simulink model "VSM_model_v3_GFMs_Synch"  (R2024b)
settings: Solver=ode23tb  StartTime=0.0  StopTime=Tend  FixedStep=T_s  RelTol=1e-3  EnableMultiTasking=on
PostLoadFcn:
  | Tcontrol=20e-6;
InitFcn:
  | Tcontrol=20e-6;
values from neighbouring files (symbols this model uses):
  C_4 = 0.1670*C_b    (= 1.00487241952e-06)    [VSM.m]    (also in VSM_CSIRO.m)
  C_6 = 0.2835*C_b    (= 1.70587623314e-06)    [VSM.m]    (also in VSM_CSIRO.m)
  C_8 = 0.2275*C_b    (= 1.36891302659e-06)    [VSM.m]    (also in VSM_CSIRO.m)
  C_dc = 0.008*(n)    (= 1.6)    [VSM.m]    (also in VSM_CSIRO.m)
  C_f = n*300*10^-6    (= 0.06)    [VSM.m]    (also in VSM_CSIRO.m)
  C_f_gfl = (n_gfl) * Cf_unit_gfl    (= 0.00350140874802)    [DER_param.m]
  D_p = (1/(m_p*w_b))    (= 101321.183642)    [VSM.m]    (also in VSM_CSIRO.m)
  droop_percentage = 5    [VSM.m]    (also in VSM_CSIRO.m = 1)
  I_b_dc = S_b/Vdc_n    [VSM.m]    (also in VSM_CSIRO.m)
  I_b_LV_peak = I_b_LV * sqrt(2)    [VSM.m]
  I_b_SG_peak = I_b_SG * sqrt(2)    [VSM.m]
  i_ll = -1.15*(S_b/Vdc_n)-i_loss_dc    [VSM.m]    (also in VSM_CSIRO.m)
  i_ul = 1.15*(S_b/Vdc_n)+i_loss_dc    [VSM.m]    (also in VSM_CSIRO.m)
  J = D_p*tau_f    (= 2026.42367285)    [VSM.m]    (also in VSM_CSIRO.m)
  k_dc = eta_1/(Vdc_n*m_p)    [VSM.m]    (also in VSM_CSIRO.m)
  K_p = (1/Vdc_n)    [VSM.m]    (also in VSM_CSIRO.m)
  K_r = 1/R_dc    [VSM.m]    (also in VSM_CSIRO.m)
  Kff_i = 1    [VSM.m]    (also in VSM_CSIRO.m)
  Kff_v = 1    [VSM.m]    (also in VSM_CSIRO.m)
  Ki_i = (1/n)*1.19    (= 0.00595)    [VSM.m]    (also in VSM_CSIRO.m)
  Ki_i_gfl = (1/n_gfl) * Ki_i_unit_gfl    (= 0.571198664289)    [DER_param.m]
  Ki_v = (n)*1.161022    (= 232.2044)    [VSM.m]    (also in VSM_CSIRO.m)
  ki_v_ac = 4*5.2500e-04    (= 0.0021)    [VSM.m]    (also in VSM_CSIRO.m)
  Kp_i = 0.738891    [VSM.m]    (also in VSM_CSIRO.m)
  Kp_i_gfl = (1/n_gfl) * Kp_i_unit_gfl    (= 0.00909090909091)    [DER_param.m]
  Kp_v = 0.52    [VSM.m]    (also in VSM_CSIRO.m)
  kp_v_ac = 0.001    [VSM.m]    (also in VSM_CSIRO.m)
  L1_f_gfl = (1/n_gfl) * L1_unit_gfl    (= 1.44686311902e-05)    [DER_param.m]
  L1_pu = 1*0.0186/m    (= 0.000186)    [VSM.m]    (also in VSM_CSIRO.m)
  L1_pu_gfl = 0.03    [DER_param.m]
  L2_f_gfl = (1/n_gfl) * L2_unit_gfl    (= 2.89372623803e-06)    [DER_param.m]
  L2_pu_gfl = 0.03    [DER_param.m]
  L_45 = L_lines(2)    [VSM.m]    (also in VSM_CSIRO.m)
  L_56 = L_lines(3)    [VSM.m]    (also in VSM_CSIRO.m)
  L_67 = L_lines(5)    [VSM.m]    (also in VSM_CSIRO.m)
  L_78 = L_lines(6)    [VSM.m]    (also in VSM_CSIRO.m)
  L_89 = L_lines(8)    [VSM.m]    (also in VSM_CSIRO.m)
  L_94 = L_lines(9)    [VSM.m]    (also in VSM_CSIRO.m)
  L_f = (1/n)*200*10^-6    (= 1e-06)    [VSM.m]    (also in VSM_CSIRO.m)
  Lg = (X_BY_R_gfl * Rg) / wn_gfl    [DER_param.m]    (also in initialcondition_gfm_Pooyan.m = X_BY_R*Rg/(wn); initialcondition_Pooyan.m = X_BY_R*Rg/(wn))
  n = 200    [VSM.m]    (also in VSM_CSIRO.m)
  Pgen_MW_gfl = 20    [DER_param.m]
  ps = base/3    (= 0.75)    [VSM.m]    (also in VSM_CSIRO.m)
  R1_f_gfl = (1/n_gfl) * R1_unit_gfl    (= 0.000909090909091)    [DER_param.m]
  R1_pu = 1*0.00734/m    (= 7.34e-05)    [VSM.m]    (also in VSM_CSIRO.m)
  R1_pu_gfl = 0.005    [DER_param.m]
  R2_f_gfl = (1/n_gfl) * R2_unit_gfl    (= 0.000181818181818)    [DER_param.m]
  R2_pu_gfl = 0.005    [DER_param.m]
  R_45 = R_lines(2)    [VSM.m]    (also in VSM_CSIRO.m)
  R_56 = R_lines(3)    [VSM.m]    (also in VSM_CSIRO.m)
  R_67 = R_lines(5)    [VSM.m]    (also in VSM_CSIRO.m)
  R_78 = R_lines(6)    [VSM.m]    (also in VSM_CSIRO.m)
  R_89 = R_lines(8)    [VSM.m]    (also in VSM_CSIRO.m)
  R_94 = R_lines(9)    [VSM.m]    (also in VSM_CSIRO.m)
  R_base_gfl = (3 * Vg_gfl^2) / (2 * Pn_gfl)    [DER_param.m]
  R_dc = (Vdc_n/(0.05*(S_b)/Vdc_n))    [VSM.m]    (also in VSM_CSIRO.m)
  R_f = 0.001/n    (= 5e-06)    [VSM.m]    (also in VSM_CSIRO.m)
  Rg = (3 * Vg_gfl^2) / (2 * SCR_gfl * sqrt(1 + X_BY_R_gfl^2) * Pn_gfl)    [DER_param.m]    (also in initialcondition_gfm_Pooyan.m = (3*Vg^2)/(2*SCR*sqrt(1+X_BY_R^2)*Pn); initialcondition_Pooyan.m = (3*Vg^2)/(2*SCR*sqrt(1+X_BY_R^2)*Pn))
  S_b = 100*(10^6)    (= 100000000)    [VSM.m]    (also in VSM_CSIRO.m)
  S_bt = S_b    (= 100000000)    [VSM.m]    (also in VSM_CSIRO.m)
  S_bt_gfl = S_b_gfl    (= 22000000)    [DER_param.m]
  T_en = T_load-0.5    (= 24.5)    [VSM.m]    (also in VSM_CSIRO.m = 44.5)
  T_s = 1e-4    (= 0.0001)    [VSM.m]    (also in VSM_CSIRO.m)
  tau_dc = 0.05    [VSM.m]    (also in VSM_CSIRO.m)
  tau_g = 5    [VSM.m]    (also in VSM_CSIRO.m)
  Tend = 90    [VSM.m]    (also in VSM_CSIRO.m = 50)
  ts_DER = 15    [DER_param.m]
  V1_rms = 1000    [VSM.m]    (also in VSM_CSIRO.m)
  V1_rms_gfl = 1000    [DER_param.m]
  V1_rms_tx1_gfl = 1000    [DER_param.m]
  V2_rms = 13800    [VSM.m]    (also in VSM_CSIRO.m)
  V2_rms_tx1_gfl = 13800    [DER_param.m]
  V_b = 230*(10^3)    (= 230000)    [VSM.m]    (also in VSM_CSIRO.m)
  V_m = sqrt(2/3)*V1_rms    [VSM.m]    (also in VSM_CSIRO.m)
  V_m_gfl = sqrt(2/3)*V1_rms_gfl    [DER_param.m]
  V_sg_p = sqrt(2/3)*V2_rms    [VSM.m]
  Vdc_n = 3*V_m    [VSM.m]    (also in VSM_CSIRO.m)
  Vdc_n_gfl = 2300    [DER_param.m]
  w_b = 2*pi*f_b    (= 314.159265359)    [VSM.m]    (also in VSM_CSIRO.m)
  w_b_gfl = 2*pi*f_b_gfl    (= 314.159265359)    [DER_param.m]
  w_f = 2*pi*5    (= 31.4159265359)    [VSM.m]    (also in VSM_CSIRO.m)
undefined symbols (not defined in the file or in its folder): D1, Delta, DiscIntNeverNeededParam, dspblkCoreblockFVToolHelper, gcbh, i_dc, magnitude
libraries: spsSeriesRLCBranchLib x82, spsabctodq0Lib x40, slpidlib x36, spsVoltageMeasurementLib x32, spsThreePhaseVIMeasurementLib x31, spsThreePhaseBreakerLib x26, spsGroundLib x22, spsCurrentMeasurementLib x20, spsPLL3phLib x14, spsThreePhaseTransformerTwoWindingsLib x14, simulink x13, spsThreePhaseSeriesRLCBranchLib x10
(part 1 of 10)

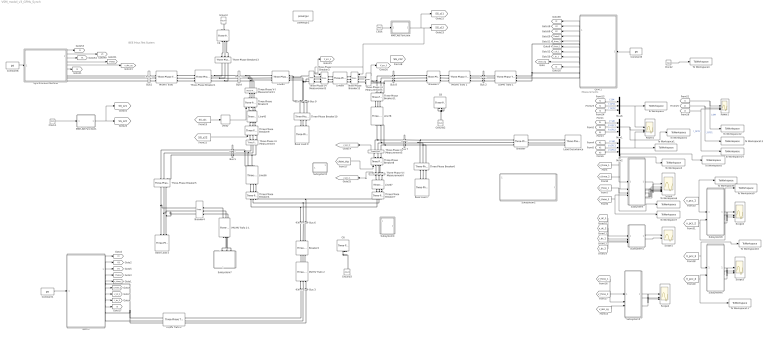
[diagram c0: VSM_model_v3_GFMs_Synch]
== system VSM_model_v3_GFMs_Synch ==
  note: Measurements
  note: IEEE 9-bus Test System
  Base Load 5 : spsThreePhaseParallelRLCLoadLib/Three-Phase Parallel RLC Load  LConnTagsString=A|B|C  Configuration=Y (grounded)  NominalVoltage=230e3  Vabc=[1e3 1e3 1e3]  Vabcp=[1e3 1e3 1e3]  NominalFrequency=50  UnbalancedPower=off  ActivePower=pl  InductivePower=0  CapacitivePower=0  Pabc=[10e3 9e3 11e3]  QLabc=[100 90 110]  QCabc=[100 90 110]  Pabcp=[10e3 9e3 11e3]  QLabcp=[100 90 110]  QCabcp=[100 90 110]  Measurements=None  LoadType=constant Z
  Base Load 7 : spsThreePhaseParallelRLCLoadLib/Three-Phase Parallel RLC Load  LConnTagsString=A|B|C  Configuration=Y (grounded)  NominalVoltage=230e3  Vabc=[1e3 1e3 1e3]  Vabcp=[1e3 1e3 1e3]  NominalFrequency=50  UnbalancedPower=off  ActivePower=pl  InductivePower=0  CapacitivePower=0  Pabc=[10e3 9e3 11e3]  QLabc=[100 90 110]  QCabc=[100 90 110]  Pabcp=[10e3 9e3 11e3]  QLabcp=[100 90 110]  QCabcp=[100 90 110]  Measurements=None  LoadType=constant Z
  "Base Load 9 " : spsThreePhaseParallelRLCLoadLib/Three-Phase Parallel RLC Load  LConnTagsString=A|B|C  Configuration=Y (grounded)  NominalVoltage=230e3  Vabc=[1e3 1e3 1e3]  Vabcp=[1e3 1e3 1e3]  NominalFrequency=50  UnbalancedPower=off  ActivePower=pl  InductivePower=0  CapacitivePower=0  Pabc=[10e3 9e3 11e3]  QLabc=[100 90 110]  QCabc=[100 90 110]  Pabcp=[10e3 9e3 11e3]  QLabcp=[100 90 110]  QCabcp=[100 90 110]  Measurements=None  LoadType=constant Z
  Breaker : spsThreePhaseBreakerLib/Three-Phase Breaker  InitialState=open  SwitchA=on  SwitchB=on  SwitchC=on  SwitchTimes=70  External=off  BreakerResistance=0.01  SnubberResistance=1e6  SnubberCapacitance=inf  Measurements=None
  Breaker2 : spsThreePhaseBreakerLib/Three-Phase Breaker  InitialState=open  SwitchA=on  SwitchB=on  SwitchC=on  SwitchTimes=10  External=off  BreakerResistance=0.01  SnubberResistance=1e6  SnubberCapacitance=inf  Measurements=None
  Breaker3 : spsThreePhaseBreakerLib/Three-Phase Breaker  InitialState=open  SwitchA=on  SwitchB=on  SwitchC=on  SwitchTimes=39  External=off  BreakerResistance=0.01  SnubberResistance=1e6  SnubberCapacitance=inf  Measurements=None
  Breaker4 : spsThreePhaseBreakerLib/Three-Phase Breaker  InitialState=open  SwitchA=on  SwitchB=on  SwitchC=on  SwitchTimes=ts_DER  External=off  BreakerResistance=0.01  SnubberResistance=1e6  SnubberCapacitance=inf  Measurements=None
  Bus 2 : spsThreePhaseVIMeasurementLib/Three-Phase V-I Measurement  VoltageMeasurement=no  SetLabelV=on  LabelV=Vabc_8  Vpu=on  VpuLL=off  CurrentMeasurement=no  SetLabelI=on  LabelI=Iabc_8  Ipu=on  Pbase=S_b  Vbase=V_b  OutputType=Complex  PhasorSimulation=off  PSBequivalent=0
  Bus 3 : spsThreePhaseVIMeasurementLib/Three-Phase V-I Measurement  VoltageMeasurement=no  SetLabelV=off  LabelV=Vabc_6  Vpu=off  VpuLL=off  CurrentMeasurement=no  SetLabelI=off  LabelI=Iabc_6  Ipu=off  Pbase=S_b  Vbase=V_b  OutputType=Complex  PhasorSimulation=off  PSBequivalent=0
  Bus 5 : spsThreePhaseVIMeasurementLib/Three-Phase V-I Measurement  VoltageMeasurement=no  SetLabelV=on  LabelV=Vabc_5  Vpu=on  VpuLL=off  CurrentMeasurement=no  SetLabelI=on  LabelI=Iabc_5  Ipu=on  Pbase=S_b  Vbase=V_b  OutputType=Complex  PhasorSimulation=off  PSBequivalent=0
  Bus 6 : spsThreePhaseVIMeasurementLib/Three-Phase V-I Measurement  VoltageMeasurement=no  SetLabelV=off  LabelV=Vabc_6  Vpu=off  VpuLL=off  CurrentMeasurement=no  SetLabelI=off  LabelI=Iabc_6  Ipu=off  Pbase=S_b  Vbase=V_b  OutputType=Complex  PhasorSimulation=off  PSBequivalent=0
  Bus 7 : spsThreePhaseVIMeasurementLib/Three-Phase V-I Measurement  VoltageMeasurement=no  SetLabelV=on  LabelV=Vabc_5  Vpu=on  VpuLL=off  CurrentMeasurement=no  SetLabelI=on  LabelI=Iabc_5  Ipu=on  Pbase=S_b  Vbase=V_b  OutputType=Complex  PhasorSimulation=off  PSBequivalent=0
  Bus 8 : spsThreePhaseVIMeasurementLib/Three-Phase V-I Measurement  VoltageMeasurement=no  SetLabelV=on  LabelV=Vabc_8  Vpu=on  VpuLL=off  CurrentMeasurement=no  SetLabelI=on  LabelI=Iabc_8  Ipu=on  Pbase=S_b  Vbase=V_b  OutputType=Complex  PhasorSimulation=off  PSBequivalent=0
  Bus 9 : spsThreePhaseVIMeasurementLib/Three-Phase V-I Measurement  VoltageMeasurement=no  SetLabelV=on  LabelV=Vabc_9  Vpu=on  VpuLL=off  CurrentMeasurement=no  SetLabelI=on  LabelI=Iabc_9  Ipu=on  Pbase=S_b  Vbase=V_b  OutputType=Complex  PhasorSimulation=off  PSBequivalent=0
  Bus1 : spsThreePhaseVIMeasurementLib/Three-Phase V-I Measurement  VoltageMeasurement=no  SetLabelV=on  LabelV=Vabc_1  Vpu=on  VpuLL=off  CurrentMeasurement=no  SetLabelI=on  LabelI=Iabc_1  Ipu=on  Pbase=S_b  Vbase=V_b  OutputType=Complex  PhasorSimulation=off  PSBequivalent=0
  Bus4 : spsThreePhaseVIMeasurementLib/Three-Phase V-I Measurement  VoltageMeasurement=no  SetLabelV=on  LabelV=Vabc_4  Vpu=on  VpuLL=off  CurrentMeasurement=no  SetLabelI=on  LabelI=Iabc_4  Ipu=on  Pbase=S_b  Vbase=V_b  OutputType=Complex  PhasorSimulation=off  PSBequivalent=0
  C4 : spsThreePhaseParallelRLCBranchLib/Three-Phase Parallel RLC Branch  LConnTagsString=A|B|C  RConnTagsString=A|B|C  BranchType=C  Resistance=1  Inductance=1e-3  Capacitance=C_4  Measurements=None
  C6 : spsThreePhaseParallelRLCBranchLib/Three-Phase Parallel RLC Branch  Commented=on  LConnTagsString=A|B|C  RConnTagsString=A|B|C  BranchType=C  Resistance=1  Inductance=1e-3  Capacitance=C_6  Measurements=None
  C8 : spsThreePhaseParallelRLCBranchLib/Three-Phase Parallel RLC Branch  Commented=on  LConnTagsString=A|B|C  RConnTagsString=A|B|C  BranchType=C  Resistance=1  Inductance=1e-3  Capacitance=C_8  Measurements=None
  Clock : Clock
  Clock1 : Clock
  Clock2 : Clock
  Constant1 : Constant  Value=ps
  Constant3 : Constant  Value=ps
  Constant8 : Constant  Value=ps
  Delay : Delay  DelayLength=1/T_s
  GFM 1 : Subsystem
  GFM 2 : Subsystem
  Ground : spsGroundLib/Ground  LConnTagsString=a
  Ground2 : spsGroundLib/Ground  Commented=on  LConnTagsString=a
  Ground3 : spsGroundLib/Ground  Commented=on  LConnTagsString=a
  LV/MV Trafo 1 : spsThreePhaseTransformerTwoWindingsLib/Three-Phase Transformer (Two Windings)  Winding1Connection=Yg  Winding2Connection=Yg  CoreType=Three single-phase transformers  SetSaturation=off  Hysteresis=off  DataFile='hysteresis'  SetInitialFlux=off  Measurements=None  UNITS=pu  NominalPower=[S_bt 50 ]  Winding1="[ V1_rms R1_pu  L1_pu]"  Winding2=[ V2_rms R1_pu L1_pu]  Rm=Rm_pu  Lm=Lm_pu  L0=0.5  Saturation="[ 0,0  ;  0.005,1.2  ;  1.0,1.4 ]"  InitialFluxes=[ 0.8 , -0.8 , 0.7 ]  BreakLoop=off  DiscreteSolver=Trapezoidal iterative  DataType=off  TransfoNumber=0
  LV/MV Trafo 2 : spsThreePhaseTransformerTwoWindingsLib/Three-Phase Transformer (Two Windings)  Winding1Connection=Yg  Winding2Connection=Yg  CoreType=Three single-phase transformers  SetSaturation=off  Hysteresis=off  DataFile='hysteresis'  SetInitialFlux=off  Measurements=None  UNITS=pu  NominalPower=[ S_bt 50 ]  Winding1="[ V1_rms R1_pu  L1_pu]"  Winding2=[ V2_rms R1_pu L1_pu]  Rm=Rm_pu  Lm=Lm_pu  L0=0.5  Saturation="[ 0,0  ;  0.005,1.2  ;  1.0,1.4 ]"  InitialFluxes=[ 0.8 , -0.8 , 0.7 ]  BreakLoop=off  DiscreteSolver=Trapezoidal iterative  DataType=off  TransfoNumber=0
  Line45 : spsThreePhaseSeriesRLCBranchLib/Three-Phase Series RLC Branch  LConnTagsString=A|B|C  RConnTagsString=A|B|C  BranchType=RL  Resistance=R_45  Inductance=L_45  Capacitance=0  Measurements=None
  Line56 : spsThreePhaseSeriesRLCBranchLib/Three-Phase Series RLC Branch  LConnTagsString=A|B|C  RConnTagsString=A|B|C  BranchType=RL  Resistance=R_56  Inductance=L_56  Capacitance=0  Measurements=None
  Line67 : spsThreePhaseSeriesRLCBranchLib/Three-Phase Series RLC Branch  LConnTagsString=A|B|C  RConnTagsString=A|B|C  BranchType=RL  Resistance=R_67  Inductance=L_67  Capacitance=0  Measurements=None
  Line78 : spsThreePhaseSeriesRLCBranchLib/Three-Phase Series RLC Branch  LConnTagsString=A|B|C  RConnTagsString=A|B|C  BranchType=RL  Resistance=R_78  Inductance=L_78  Capacitance=0  Measurements=None
  Line89 : spsThreePhaseSeriesRLCBranchLib/Three-Phase Series RLC Branch  LConnTagsString=A|B|C  RConnTagsString=A|B|C  BranchType=RL  Resistance=R_89  Inductance=L_89  Capacitance=0  Measurements=None
  Line94 : spsThreePhaseSeriesRLCBranchLib/Three-Phase Series RLC Branch  LConnTagsString=A|B|C  RConnTagsString=A|B|C  BranchType=RL  Resistance=R_94  Inductance=L_94  Capacitance=0  Measurements=None
  Load Disturbance : spsThreePhaseParallelRLCLoadLib/Three-Phase Parallel RLC Load  LConnTagsString=A|B|C  Configuration=Y (grounded)  NominalVoltage=230e3  Vabc=[1e3 1e3 1e3]  Vabcp=[1e3 1e3 1e3]  NominalFrequency=50  UnbalancedPower=off  ActivePower=load_step  InductivePower=0  CapacitivePower=0  Pabc=[10e3 9e3 11e3]  QLabc=[100 90 110]  QCabc=[100 90 110]  Pabcp=[10e3 9e3 11e3]  QLabcp=[100 90 110]  QCabcp=[100 90 110]  Measurements=None  LoadType=constant Z
  MATLAB Function : MATLAB Function  TreatAsAtomicUnit=on
  MATLAB Function1 : MATLAB Function  TreatAsAtomicUnit=on
  "MV/HV Trafo " : spsThreePhaseTransformerTwoWindingsLib/Three-Phase Transformer (Two Windings)  Winding1Connection=Delta (D1)  Winding2Connection=Yg  CoreType=Three single-phase transformers  SetSaturation=off  Hysteresis=off  DataFile='hysteresis'  SetInitialFlux=off  Measurements=None  UNITS=pu  NominalPower=[ 210e6 50 ]  Winding1="[V2_rms 0.0027  0.08]"  Winding2=[230e3 0.0027 0.08]  Rm=500  Lm=500  L0=0.5  Saturation="[ 0,0  ;  0.005,1.2  ;  1.0,1.4 ]"  InitialFluxes=[ 0.8 , -0.8 , 0.7 ]  BreakLoop=off  DiscreteSolver=Trapezoidal iterative  DataType=off  TransfoNumber=0
  "MV/HV Trafo 1 " : spsThreePhaseTransformerTwoWindingsLib/Three-Phase Transformer (Two Windings)  Winding1Connection=Yg  Winding2Connection=Yg  CoreType=Three single-phase transformers  SetSaturation=off  Hysteresis=off  DataFile='hysteresis'  SetInitialFlux=off  Measurements=None  UNITS=pu  NominalPower=[ 210e6 50 ]  Winding1=[V2_rms 0.0027 0.08]  Winding2=[ 230e3 0.0027 0.08]  Rm=500  Lm=500  L0=0.5  Saturation="[ 0,0  ;  0.005,1.2  ;  1.0,1.4 ]"  InitialFluxes=[ 0.8 , -0.8 , 0.7 ]  BreakLoop=off  DiscreteSolver=Trapezoidal iterative  DataType=off  TransfoNumber=0
  "MV/HV Trafo 2 " : spsThreePhaseTransformerTwoWindingsLib/Three-Phase Transformer (Two Windings)  Winding1Connection=Yg  Winding2Connection=Yg  CoreType=Three single-phase transformers  SetSaturation=off  Hysteresis=off  DataFile='hysteresis'  SetInitialFlux=off  Measurements=None  UNITS=pu  NominalPower=[ 210e6 50 ]  Winding1=[V2_rms 0.0027 0.08]  Winding2=[230e3 0.0027 0.08]  Rm=500  Lm=500  L0=0.5  Saturation="[ 0,0  ;  0.005,1.2  ;  1.0,1.4 ]"  InitialFluxes=[ 0.8 , -0.8 , 0.7 ]  BreakLoop=off  DiscreteSolver=Trapezoidal iterative  DataType=off  TransfoNumber=0
  MV/HV Trafo 2 1 : spsThreePhaseTransformerTwoWindingsLib/Three-Phase Transformer (Two Windings)  Winding1Connection=Yg  Winding2Connection=Yg  CoreType=Three single-phase transformers  SetSaturation=off  Hysteresis=off  DataFile='hysteresis'  SetInitialFlux=off  Measurements=None  UNITS=pu  NominalPower=[ 210e6 50 ]  Winding1=[V2_rms 0.0027 0.08]  Winding2=[230e3 0.0027 0.08]  Rm=500  Lm=500  L0=0.5  Saturation="[ 0,0  ;  0.005,1.2  ;  1.0,1.4 ]"  InitialFluxes=[ 0.8 , -0.8 , 0.7 ]  BreakLoop=off  DiscreteSolver=Trapezoidal iterative  DataType=off  TransfoNumber=0
  Mux1 : Mux  Inputs=3
  Mux2 : Mux  Inputs=3
  Mux6 : Mux  Inputs=3
  Power1 : Scope  NumInputPorts=3
  Power2 : Scope  NumInputPorts=3
  Scope : Scope  NumInputPorts=6
  Scope1 : Scope  NumInputPorts=2
  Scope2 : Scope  NumInputPorts=3
  Scope3 : Scope  NumInputPorts=3
  Scope4 : Scope  NumInputPorts=3
  Subsystem : Subsystem
  Subsystem1 : Subsystem
  Subsystem2 : Subsystem  Commented=on
  Subsystem3 : Subsystem  Commented=on
  Subsystem4 : Subsystem  Commented=on
  Subsystem5 : Subsystem  Commented=on
  Subsystem6 : Subsystem
  Subsystem7 : Subsystem
  Subsystem8 : Subsystem
  Synchronous Machine : Subsystem
  Three-Phase V-I Measurement{,1..5} (6 alike) : spsThreePhaseVIMeasurementLib/Three-Phase V-I Measurement  VoltageMeasurement=phase-to-ground  SetLabelV=off  LabelV=Vabc  Vpu=off  VpuLL=off  CurrentMeasurement=no  SetLabelI=off  LabelI=Iabc  Ipu=off  Pbase=100e6  Vbase=500e3  OutputType=Complex  PhasorSimulation=off  PSBequivalent=0
  Three-Phase Breaker1 : spsThreePhaseBreakerLib/Three-Phase Breaker  InitialState=closed  SwitchA=on  SwitchB=on  SwitchC=on  SwitchTimes=Tend+1  External=off  BreakerResistance=1  SnubberResistance=1e6  SnubberCapacitance=inf  Measurements=None
  Three-Phase Breaker10 : spsThreePhaseBreakerLib/Three-Phase Breaker  InitialState=closed  SwitchA=on  SwitchB=on  SwitchC=on  SwitchTimes=Tend+1  External=off  BreakerResistance=1  SnubberResistance=1e6  SnubberCapacitance=inf  Measurements=None
  Three-Phase Breaker11 : spsThreePhaseBreakerLib/Three-Phase Breaker  InitialState=open  SwitchA=on  SwitchB=on  SwitchC=on  SwitchTimes=41  External=off  BreakerResistance=1  SnubberResistance=1e6  SnubberCapacitance=inf  Measurements=None
  Three-Phase Breaker12 : spsThreePhaseBreakerLib/Three-Phase Breaker  InitialState=open  SwitchA=on  SwitchB=on  SwitchC=on  SwitchTimes=51  External=on  BreakerResistance=1  SnubberResistance=1e6  SnubberCapacitance=inf  Measurements=None
  Three-Phase Breaker13 : spsThreePhaseBreakerLib/Three-Phase Breaker  InitialState=closed  SwitchA=on  SwitchB=on  SwitchC=on  SwitchTimes=Tend+1  External=off  BreakerResistance=1  SnubberResistance=1e6  SnubberCapacitance=inf  Measurements=None
  Three-Phase Breaker2 : spsThreePhaseBreakerLib/Three-Phase Breaker  InitialState=open  SwitchA=on  SwitchB=on  SwitchC=on  SwitchTimes=34  External=on  BreakerResistance=1  SnubberResistance=1e6  SnubberCapacitance=inf  Measurements=None
  Three-Phase Breaker3 : spsThreePhaseBreakerLib/Three-Phase Breaker  InitialState=open  SwitchA=on  SwitchB=on  SwitchC=on  SwitchTimes=32  External=on  BreakerResistance=1  SnubberResistance=1e6  SnubberCapacitance=inf  Measurements=None
  Three-Phase Breaker4 : spsThreePhaseBreakerLib/Three-Phase Breaker  InitialState=open  SwitchA=on  SwitchB=on  SwitchC=on  SwitchTimes=12  External=off  BreakerResistance=1  SnubberResistance=1e6  SnubberCapacitance=inf  Measurements=None
  Three-Phase Breaker5 : spsThreePhaseBreakerLib/Three-Phase Breaker  InitialState=open  SwitchA=on  SwitchB=on  SwitchC=on  SwitchTimes=14  External=off  BreakerResistance=1  SnubberResistance=1e6  SnubberCapacitance=inf  Measurements=None
  Three-Phase Breaker6 : spsThreePhaseBreakerLib/Three-Phase Breaker  InitialState=open  SwitchA=on  SwitchB=on  SwitchC=on  SwitchTimes=43  External=off  BreakerResistance=1  SnubberResistance=1e6  SnubberCapacitance=inf  Measurements=None
  Three-Phase Breaker7 : spsThreePhaseBreakerLib/Three-Phase Breaker  InitialState=open  SwitchA=on  SwitchB=on  SwitchC=on  SwitchTimes=37.5  External=off  BreakerResistance=1  SnubberResistance=1e6  SnubberCapacitance=inf  Measurements=None
  Three-Phase Breaker8 : spsThreePhaseBreakerLib/Three-Phase Breaker  InitialState=open  SwitchA=on  SwitchB=on  SwitchC=on  SwitchTimes=22  External=on  BreakerResistance=1  SnubberResistance=1e6  SnubberCapacitance=inf  Measurements=None
  Three-Phase Breaker9 : spsThreePhaseBreakerLib/Three-Phase Breaker  InitialState=open  SwitchA=on  SwitchB=on  SwitchC=on  SwitchTimes=34  External=on  BreakerResistance=1  SnubberResistance=1e6  SnubberCapacitance=inf  Measurements=None
  To Workspace : ToWorkspace  VariableName=freq  SaveFormat=Structure With Time  SampleTime=-1
  To Workspace1 : ToWorkspace  VariableName=Volt  SaveFormat=Structure With Time  SampleTime=-1
  To Workspace10 : ToWorkspace  VariableName=v_pcc_33  SaveFormat=Structure With Time  SampleTime=-1
  To Workspace11 : ToWorkspace  VariableName=v_pcc_44  SaveFormat=Structure With Time  SampleTime=-1
  To Workspace12 : ToWorkspace  VariableName=I_SM_1  SaveFormat=Structure With Time  SampleTime=-1
  To Workspace13 : ToWorkspace  VariableName=I_GFC_1  SaveFormat=Structure With Time  SampleTime=-1
  To Workspace14 : ToWorkspace  VariableName=I_GFC_2  SaveFormat=Structure With Time  SampleTime=-1
  To Workspace2 : ToWorkspace  VariableName=Pwr  SaveFormat=Structure With Time  SampleTime=-1
  To Workspace3 : ToWorkspace  VariableName=v_three_11  SaveFormat=Structure With Time  SampleTime=-1
  To Workspace4 : ToWorkspace  VariableName=time_steps  SaveFormat=Structure With Time  SampleTime=-1
  To Workspace5 : ToWorkspace  VariableName=v_three_22  SaveFormat=Structure With Time  SampleTime=-1
  To Workspace6 : ToWorkspace  VariableName=i_three_11  SaveFormat=Structure With Time  SampleTime=-1
  To Workspace7 : ToWorkspace  VariableName=i_three_22  SaveFormat=Structure With Time  SampleTime=-1
  To Workspace8 : ToWorkspace  VariableName=v_pcc_11  SaveFormat=Structure With Time  SampleTime=-1
  To Workspace9 : ToWorkspace  VariableName=v_pcc_22  SaveFormat=Structure With Time  SampleTime=-1
  powergui2 : spspowerguiLib/powergui  Priority=1  SimulationMode=Discrete  SampleTime=T_s  frequency=50  Iterations=50  frequencyindice=0  Pbase=100e6  ErrMax=0.0001  UnitsV=kV  UnitsW=MW  buscounter=12  FunctionMessages=off  echomessages=off  EnableUseOfTLC=off  CurrentSourceSwitches=off  DisableSnubberDevices=off  DisableRonSwitches=off  DisableVfSwitches=off  DisplayEquations=off  AutomaticDiscreteSolvers=off  SolverType=Tustin/Backward Euler (TBE)  Interpol=off  ExternalGateDelay=off  methode=off  Ts=100  x0status=blocks  SPID=off  SwTol=0  HookPort=off  NonlinearTolerance=1e-4  nMaxIteration=100  ContinueOnMaxIteration=off  RestoreLinks=warning  ResistiveCurrentMeasurement=off  Frange=[0:2:500]  Ylog=off  Xlog=on  ShowGrid=off  save=off  variable=ZData  structure=0  ZoomFFT=off  StartTime=0.0  cycles=1  DisplayStyle=1  fundamental=60  FreqAxis=off  MaxFrequency=1000  frequencyindicesteady=1  RmsSteady=1  display=off
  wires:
  [f1] -> Mux6/1  "f_SM"
  GFM 2/2(V) -> [V3]
  GFM 2/1(f) -> [f3]
  [P3] -> Mux1/3  "P_GFC2"
  Constant1/1 -> GFM 2/1(Pset)
  [P2] -> Mux1/2  "P_GFC1"
  GFM 2/3(P) -> [P3]
  [V1] -> Mux2/1  "V_SM"
  Synchronous Machine/1(f) -> [f1]
  [f3] -> Mux6/3  "f_GFC2"
  [P1] -> Mux1/1  "P_SM"
  [V3] -> Mux2/3  "V_GFC2"
  Constant8/1 -> Synchronous Machine/1(Pset)
  Mux6/1 -> To Workspace/1, Power2/1
  [V2] -> Mux2/2  "V_GFC1"
  Mux1/1 -> To Workspace2/1, Power2/2
  Synchronous Machine/3(P) -> [P1]
  Synchronous Machine/4(Theta) -> [Theta1]
  GFM 2/4(Theta) -> [Theta3]
  Synchronous Machine/2(V) -> [V1]
  Mux2/1 -> To Workspace1/1, Power2/3
  [f2] -> Mux6/2  "f_GFC1"
  GFM 2/5(vabc) -> [v_three_2]
  GFM 2/6(iabc) -> [i_three_2]
  GFM 2/7(vdc) -> [v_dc_2]
  GFM 2/8(idc) -> [i_dc_2]
  [v_three_1] -> To Workspace3/1, Subsystem/1(In1)
  [v_three_2] -> To Workspace5/1, Subsystem/2(In2)
  [i_three_1] -> To Workspace6/1, Subsystem/3(In3)
  [i_three_2] -> To Workspace7/1, Subsystem/4(In4)
  Subsystem/1(Out1) -> Scope/1
  Subsystem/2(Out2) -> Scope/2
  Subsystem/3(Out3) -> Scope/3
  Subsystem/4(Out4) -> Scope/4
  Subsystem/5(Out5) -> Scope/5
  Subsystem/6(Out6) -> Scope/6
  [v_dc_1] -> Subsystem1/1(In1)
  [v_dc_2] -> Subsystem1/2(In2)
  [i_dc_1] -> Subsystem1/3(In3)
  [i_dc_2] -> Subsystem1/4(In4)
  Subsystem1/1(Out1) -> Scope1/1
  Subsystem1/2(Out2) -> Scope1/2
  GFM 1/8(idc1) -> [i_dc_1]
  GFM 1/6(iabc1) -> [i_three_1]
  GFM 1/7(vdc1) -> [v_dc_1]
  Constant3/1 -> GFM 1/1(Pset2)
  GFM 1/1(f1) -> [f2]
  GFM 1/4(Theta1) -> [Theta2]
  GFM 1/5(vabc1) -> [v_three_1]
  GFM 1/2(V1) -> [V2]
  GFM 1/3(P1) -> [P2]
  Synchronous Machine/5(Outport) -> [v_abc_sg]
  [v_abc_sg] -> Subsystem3/3(In2)
  Subsystem3/1(Out1) -> Scope2/1
  Subsystem3/2(Out2) -> Scope2/2
  Subsystem3/3(Out3) -> Scope2/3
  GFM 1/9(close_signal) -> [close_sig]
  GFM 2/9(I3) -> [I3]
  GFM 1/10(I2) -> [I2]
  Synchronous Machine/6(I1) -> [I1]
  [I1] -> To Workspace12/1, Power1/1  "I_SM"
  [I2] -> To Workspace13/1, Power1/2  "I_GFC1"
  [I3] -> To Workspace14/1, Power1/3  "I_GFC2"
  [SG_z21] -> Delay/1
  Clock/1 -> MATLAB Function/1(t)
  Clock1/1 -> MATLAB Function1/1(t)
  MATLAB Function1/1(y) -> [SG_z22], [SG_z21]
  MATLAB Function/1(y) -> [SG_z11], Three-Phase Breaker3/1, Three-Phase Breaker12/1, [SG_z12]
  [close_sig] -> Three-Phase Breaker8/1
  Three-Phase V-I Measurement5/1 -> [v_pcc_2]
  Three-Phase V-I Measurement4/1 -> [v_pcc_1]
  Delay/1 -> Three-Phase Breaker2/1
  [SG_z22] -> Three-Phase Breaker9/1
  [v_three_1] -> Subsystem3/1(In1)
  [v_three_2] -> Subsystem3/2(In3)
  Three-Phase V-I Measurement2/1 -> [V_pcc_4]
  Subsystem6/3(Out3) -> Scope3/3
  Subsystem6/1(Out1) -> Scope3/1
  Subsystem6/2(Out2) -> Scope3/2
  [V_pcc_3] -> To Workspace10/1, Subsystem6/1(In1)
  [V_pcc_4] -> To Workspace11/1, Subsystem6/2(In3)
  [v_pcc_2] -> To Workspace9/1, Subsystem8/2(In3)
  Subsystem8/3(Out3) -> Scope4/3
  Subsystem8/2(Out2) -> Scope4/2
  Subsystem8/1(Out1) -> Scope4/1
  [v_pcc_1] -> To Workspace8/1, Subsystem8/1(In1)
  Three-Phase V-I Measurement3/1 -> [V_pcc_3]
  Clock2/1 -> To Workspace4/1
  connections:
  GFM 1/RConn1 -- LV/MV Trafo 1/LConn1
  GFM 1/RConn2 -- LV/MV Trafo 1/LConn2
  GFM 1/RConn3 -- LV/MV Trafo 1/LConn3
  C8/RConn2 -- C8/RConn3 -- Ground2/LConn1 -- C8/RConn1
  Line94/RConn1 -- Three-Phase V-I Measurement2/LConn1 -- Bus 9/RConn3
  Bus 7/RConn3 -- Three-Phase V-I Measurement5/RConn3 -- Line78/RConn3
  Breaker2/RConn2 -- Bus 6/RConn2
  Three-Phase Breaker4/LConn1 -- Three-Phase Breaker7/LConn1 -- Bus 6/LConn1
  Three-Phase Breaker4/LConn3 -- Three-Phase Breaker7/LConn3 -- Bus 6/LConn3
  Bus 5/LConn3 -- Three-Phase V-I Measurement/LConn3 -- Line56/LConn3
  Three-Phase Breaker1/RConn2 -- Three-Phase Breaker13/RConn2 -- Bus4/RConn2
  Bus 7/LConn3 -- Three-Phase Breaker6/RConn3 -- Breaker/LConn3
  Bus 7/RConn1 -- Three-Phase V-I Measurement5/RConn1 -- Line78/RConn1
  Bus 5/LConn1 -- Three-Phase V-I Measurement/LConn1 -- Line56/LConn1
  C6/RConn2 -- C6/RConn1 -- Ground3/LConn1 -- C6/RConn3
  Bus 5/LConn2 -- Three-Phase V-I Measurement/LConn2 -- Line56/LConn2
  Breaker/LConn1 -- Three-Phase Breaker6/RConn1 -- Bus 7/LConn1
  Bus 8/RConn3 -- Three-Phase V-I Measurement3/RConn3 -- Three-Phase Breaker11/RConn3
  Bus 8/RConn1 -- Three-Phase V-I Measurement3/RConn1 -- Three-Phase Breaker11/RConn1
  Bus 7/LConn2 -- Three-Phase Breaker6/RConn2 -- Breaker/LConn2
  Line94/RConn3 -- Three-Phase V-I Measurement2/LConn3 -- Bus 9/RConn1
  C4/RConn2 -- C4/RConn1 -- C4/RConn3 -- Ground/LConn1
  Bus 8/RConn2 -- Three-Phase V-I Measurement3/RConn2 -- Three-Phase Breaker11/RConn2
  Bus4/LConn1 -- Three-Phase V-I Measurement1/RConn1 -- Line94/LConn1
  Three-Phase Breaker1/RConn1 -- Three-Phase Breaker13/RConn1 -- Bus4/RConn1
  Bus 7/RConn2 -- Three-Phase V-I Measurement5/RConn2 -- Line78/RConn2
  Bus4/LConn2 -- Three-Phase V-I Measurement1/RConn2 -- Line94/LConn2
  Bus4/LConn3 -- Three-Phase V-I Measurement1/RConn3 -- Line94/LConn3
  Three-Phase Breaker4/LConn2 -- Three-Phase Breaker7/LConn2 -- Bus 6/LConn2
  Breaker2/RConn3 -- Bus 6/RConn3
  Bus 9/RConn2 -- Three-Phase V-I Measurement2/LConn2 -- Line94/RConn2
  Breaker2/RConn1 -- Bus 6/RConn1
  Bus 3/LConn2 -- "MV/HV Trafo 2 "/LConn2
  Bus 3/LConn3 -- "MV/HV Trafo 2 "/LConn3
  Bus 3/LConn1 -- "MV/HV Trafo 2 "/LConn1
  GFM 2/RConn1 -- LV/MV Trafo 2/LConn1
  GFM 2/RConn2 -- LV/MV Trafo 2/LConn2
  GFM 2/RConn3 -- LV/MV Trafo 2/LConn3
  Breaker2/LConn1 -- "MV/HV Trafo 2 "/RConn1
  Breaker2/LConn2 -- "MV/HV Trafo 2 "/RConn2
  Breaker2/LConn3 -- "MV/HV Trafo 2 "/RConn3
  Bus 2/LConn1 -- LV/MV Trafo 1/RConn1
  Bus 2/LConn2 -- LV/MV Trafo 1/RConn2
  Bus 2/LConn3 -- LV/MV Trafo 1/RConn3
  Breaker3/RConn1 -- Bus 8/LConn1
  Breaker3/RConn2 -- Bus 8/LConn2
  Breaker3/RConn3 -- Bus 8/LConn3
  "MV/HV Trafo 1 "/LConn1 -- Bus 2/RConn1
  "MV/HV Trafo 1 "/LConn2 -- Bus 2/RConn2
  "MV/HV Trafo 1 "/LConn3 -- Bus 2/RConn3
  Breaker3/LConn1 -- "MV/HV Trafo 1 "/RConn1
  Breaker3/LConn2 -- "MV/HV Trafo 1 "/RConn2
  Breaker3/LConn3 -- "MV/HV Trafo 1 "/RConn3
  Three-Phase Breaker4/RConn1 -- Line56/RConn1
  Three-Phase Breaker4/RConn2 -- Line56/RConn2
  Three-Phase Breaker4/RConn3 -- Line56/RConn3
  Base Load 7/LConn1 -- Three-Phase Breaker6/LConn1
  Three-Phase Breaker6/LConn2 -- Base Load 7/LConn2
  Three-Phase Breaker6/LConn3 -- Base Load 7/LConn3
  Three-Phase Breaker7/RConn1 -- Line67/RConn1
  Three-Phase Breaker7/RConn2 -- Line67/RConn2
  Three-Phase Breaker7/RConn3 -- Line67/RConn3
  "Base Load 9 "/LConn1 -- Three-Phase Breaker10/LConn1
  "Base Load 9 "/LConn2 -- Three-Phase Breaker10/LConn2
  "Base Load 9 "/LConn3 -- Three-Phase Breaker10/LConn3
  Three-Phase Breaker10/RConn1 -- Bus 9/LConn3
  Three-Phase Breaker10/RConn2 -- Bus 9/LConn2
  Three-Phase Breaker10/RConn3 -- Bus 9/LConn1
  Three-Phase Breaker11/LConn1 -- Line78/LConn1
  Three-Phase Breaker11/LConn2 -- Line78/LConn2
  Three-Phase Breaker11/LConn3 -- Line78/LConn3
  Three-Phase Breaker12/RConn1 -- Line89/RConn1
  Three-Phase Breaker12/RConn2 -- Line89/RConn2
  Three-Phase Breaker12/RConn3 -- Line89/RConn3
  Three-Phase Breaker1/RConn3 -- Bus4/RConn3 -- Three-Phase Breaker13/RConn3
  "MV/HV Trafo "/LConn1 -- Bus1/LConn1
  "MV/HV Trafo "/LConn2 -- Bus1/LConn2
  "MV/HV Trafo "/LConn3 -- Bus1/LConn3
  "MV/HV Trafo "/RConn1 -- Three-Phase Breaker1/LConn1
  "MV/HV Trafo "/RConn2 -- Three-Phase Breaker1/LConn2
  "MV/HV Trafo "/RConn3 -- Three-Phase Breaker1/LConn3
  Synchronous Machine/RConn1 -- Bus1/RConn1
  Synchronous Machine/RConn2 -- Bus1/RConn2
  Synchronous Machine/RConn3 -- Bus1/RConn3
  Bus 5/RConn1 -- Three-Phase Breaker5/RConn1
  Three-Phase Breaker5/RConn2 -- Bus 5/RConn2
  Bus 5/RConn3 -- Three-Phase Breaker5/RConn3
  Base Load 5/LConn1 -- Breaker4/RConn1 -- Three-Phase Breaker5/LConn1
  Base Load 5/LConn2 -- Three-Phase Breaker5/LConn2 -- Breaker4/RConn2
  Base Load 5/LConn3 -- Breaker4/RConn3 -- Three-Phase Breaker5/LConn3
  Bus 3/RConn1 -- LV/MV Trafo 2/RConn1
  Bus 3/RConn2 -- LV/MV Trafo 2/RConn2
  Bus 3/RConn3 -- LV/MV Trafo 2/RConn3
  Three-Phase Breaker2/LConn1 -- Line45/LConn1
  Line45/LConn2 -- Three-Phase Breaker2/LConn2
  Line45/LConn3 -- Three-Phase Breaker2/LConn3
  Three-Phase Breaker9/RConn1 -- Line45/RConn1
  Three-Phase Breaker9/RConn2 -- Line45/RConn2
  Three-Phase Breaker9/RConn3 -- Line45/RConn3
  Three-Phase Breaker9/LConn2 -- Three-Phase V-I Measurement/RConn2
  Three-Phase V-I Measurement1/LConn2 -- Three-Phase Breaker2/RConn2
  Three-Phase V-I Measurement1/LConn1 -- Three-Phase Breaker2/RConn1
  Three-Phase V-I Measurement1/LConn3 -- Three-Phase Breaker2/RConn3
  Three-Phase V-I Measurement2/RConn2 -- Three-Phase Breaker3/LConn2
  Three-Phase V-I Measurement2/RConn1 -- Three-Phase Breaker3/LConn1
  Three-Phase V-I Measurement2/RConn3 -- Three-Phase Breaker3/LConn3
  Three-Phase V-I Measurement/RConn1 -- Three-Phase Breaker9/LConn1
  Three-Phase V-I Measurement/RConn3 -- Three-Phase Breaker9/LConn3
  Breaker/RConn1 -- Load Disturbance/LConn1
  Breaker/RConn2 -- Load Disturbance/LConn2
  Breaker/RConn3 -- Load Disturbance/LConn3
  MV/HV Trafo 2 1/RConn1 -- Breaker4/LConn1
  MV/HV Trafo 2 1/RConn2 -- Breaker4/LConn2
  MV/HV Trafo 2 1/RConn3 -- Breaker4/LConn3
  Subsystem7/RConn1 -- MV/HV Trafo 2 1/LConn1
  Subsystem7/RConn2 -- MV/HV Trafo 2 1/LConn2
  Subsystem7/RConn3 -- MV/HV Trafo 2 1/LConn3
  Three-Phase V-I Measurement4/LConn3 -- Line67/LConn3
  Three-Phase V-I Measurement4/RConn2 -- Three-Phase Breaker8/LConn2
  Three-Phase V-I Measurement4/RConn3 -- Three-Phase Breaker8/LConn3
  Three-Phase V-I Measurement4/RConn1 -- Three-Phase Breaker8/LConn1
  Line67/LConn2 -- Three-Phase V-I Measurement4/LConn2
  Line67/LConn1 -- Three-Phase V-I Measurement4/LConn1
  Three-Phase Breaker8/RConn1 -- Three-Phase V-I Measurement5/LConn1
  Three-Phase Breaker8/RConn2 -- Three-Phase V-I Measurement5/LConn2
  Three-Phase Breaker8/RConn3 -- Three-Phase V-I Measurement5/LConn3
  Three-Phase Breaker13/LConn1 -- C4/LConn1
  C4/LConn2 -- Three-Phase Breaker13/LConn2
  Three-Phase Breaker13/LConn3 -- C4/LConn3
  Three-Phase Breaker3/RConn1 -- Line89/LConn1
  Three-Phase Breaker3/RConn2 -- Line89/LConn2
  Three-Phase Breaker3/RConn3 -- Line89/LConn3
  Three-Phase V-I Measurement3/LConn1 -- Three-Phase Breaker12/LConn1
  Three-Phase V-I Measurement3/LConn2 -- Three-Phase Breaker12/LConn2
  Three-Phase V-I Measurement3/LConn3 -- Three-Phase Breaker12/LConn3

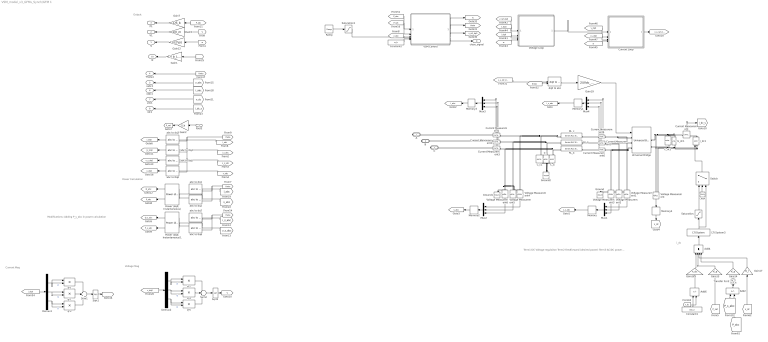
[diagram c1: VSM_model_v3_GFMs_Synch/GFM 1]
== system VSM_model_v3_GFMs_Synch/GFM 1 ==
  note: Term1-DC Voltage regulaiton Term2-feedforward (desired power) Term3-AC/DC power balance correciton Term4-Loss compensation (converter switching or filter resistor losses)
  note: Output
  note: Voltage Mag
  note: Modifications: Adding P_s_abc in power calculation
  note: Power Calculation
  note: i_dc
  note: Current Mag
  Pset2 : Inport
  Add2 : Sum  Inputs=+-
  Add4 : Sum  Inputs=++++
  Add6 : Sum  Inputs=+-
  C_a : spsSeriesRLCBranchLib/Series RLC Branch  LConnTagsString=__new0  RConnTagsString=__new0  BranchType=C  Resistance=1  Inductance=1e-3  SetiL0=off  InitialCurrent=0  Capacitance=C_f  Setx0=off  InitialVoltage=165  Measurements=None
  C_b : spsSeriesRLCBranchLib/Series RLC Branch  LConnTagsString=__new0  RConnTagsString=__new0  BranchType=C  Resistance=1  Inductance=1e-3  SetiL0=off  InitialCurrent=0  Capacitance=C_f  Setx0=off  InitialVoltage=165  Measurements=None
  C_c1 : spsSeriesRLCBranchLib/Series RLC Branch  LConnTagsString=__new0  RConnTagsString=__new0  BranchType=C  Resistance=1  Inductance=1e-3  SetiL0=off  InitialCurrent=0  Capacitance=C_f  Setx0=off  InitialVoltage=165  Measurements=None
  C_dc1 : spsSeriesRLCBranchLib/Series RLC Branch  LConnTagsString=__new0  RConnTagsString=__new0  BranchType=C  Resistance=1  Inductance=1e-3  SetiL0=off  InitialCurrent=0  Capacitance=C_dc  Setx0=off  InitialVoltage=Vdc_n  Measurements=None
  Clock : Clock
  Constant1 : Constant  Value=Vdc_n
  Constant2 : Constant  Value=w_b
  Current Loop : Subsystem
  Current Measurement{,1..6} (7 alike) : spsCurrentMeasurementLib/Current Measurement  PhasorSimulation=off  OutputType=Complex  PSBequivalent=0
  Demux1 : Demux  Outputs=3
  Demux2 : Demux  Outputs=3
  G_dc1 : spsSeriesRLCBranchLib/Series RLC Branch  LConnTagsString=__new0  RConnTagsString=__new0  BranchType=R  Resistance=R_dc  Inductance=1e-3  SetiL0=off  InitialCurrent=0  Capacitance=1e-6  Setx0=off  InitialVoltage=0  Measurements=None
  Gain1 : Gain  Gain=1/I_b_LV_peak
  Gain12 : Gain  Gain=1/(2*pi)
  Gain13 : Gain  Gain=K_p
  Gain14 : Gain  Gain=K_p
  Gain16 : Gain  Gain=k_dc
  Gain17 : Gain  Gain=K_r
  Gain19 : Gain  Gain=2/(Vdc_n)
  Gain2 : Gain  Gain=S_b
  Gain4 : Gain  Gain=1/V_m
  Gain7 : Gain  Gain=1/S_b
  Ground : spsGroundLib/Ground  LConnTagsString=a
  Ground1 : spsGroundLib/Ground  LConnTagsString=a
  Ground2 : spsGroundLib/Ground  LConnTagsString=a
  LTI System3 : cstblocks/LTI System  sys=tf(1,[tau_dc 1])  IC=[]  PadeOrder=0
  Memory{,1..4} (5 alike) : Memory
  Mux{1..4} (4 alike) : Mux  Inputs=3
  "Power (dq0, Instantaneous)" : spsPowerdq0InstantaneousLib/Power (dq0, Instantaneous)
  "Power (dq0, Instantaneous)1" : spsPowerdq0InstantaneousLib/Power (dq0, Instantaneous)
  RL_a : spsSeriesRLCBranchLib/Series RLC Branch  LConnTagsString=__new0  RConnTagsString=__new0  BranchType=RL  Resistance=R_f  Inductance=L_f  SetiL0=off  InitialCurrent=0  Capacitance=1e-6  Setx0=off  InitialVoltage=0  Measurements=Branch voltage and current
  RL_b : spsSeriesRLCBranchLib/Series RLC Branch  LConnTagsString=__new0  RConnTagsString=__new0  BranchType=RL  Resistance=R_f  Inductance=L_f  SetiL0=off  InitialCurrent=0  Capacitance=1e-6  Setx0=off  InitialVoltage=0  Measurements=None
  RL_c : spsSeriesRLCBranchLib/Series RLC Branch  LConnTagsString=__new0  RConnTagsString=__new0  BranchType=RL  Resistance=R_f  Inductance=L_f  SetiL0=off  InitialCurrent=0  Capacitance=1e-6  Setx0=off  InitialVoltage=0  Measurements=None
  Ramp : simulink/Sources/Ramp  slope=V_m  start=0  InitialOutput=0
  Saturation : Saturate  UpperLimit=i_ul  LowerLimit=i_ll
  Saturation1 : Saturate  UpperLimit=V_m  LowerLimit=0
  Sqrt1 : Sqrt
  Sqrt2 : Sqrt
  Sum1 : Sum  Inputs=+++  InputSameDT=on  SaturateOnIntegerOverflow=on
  Sum2 : Sum  Inputs=+++  InputSameDT=on  SaturateOnIntegerOverflow=on
  Switch : Switch  Criteria=u2 > Threshold  Threshold=T_en
  Transfer Fcn2 : TransferFcn  Numerator=[w_f]  Denominator=[1 w_f]
  Universal Bridge : spsUniversalBridgeLib/Universal Bridge  Arms=3  SnubberResistance=1e5  SnubberCapacitance=inf  Device=Average-model based VSC  Ron=1e-3  Lon=0  ForwardVoltages="[  0  0  ]"  ForwardVoltage=0  GTOparameters=[ 10e-6 , 20e-6 ]  IGBTparameters=[ 1e-6 , 2e-6 ]  Measurements=None  Measurements_2=None  converterType=Rectifier
  VSM Control : Subsystem
  Voltage Loop : Subsystem
  Voltage Measurement{,1..6} (7 alike) : spsVoltageMeasurementLib/Voltage Measurement  PhasorSimulation=off  OutputType=Complex  PSBequivalent=0
  abc to dq{1..8} (8 alike) : spsabctodq0Lib/abc to dq0  Alignment=90 degrees behind phase A axis
  dq0 to abc : spsdq0toabcLib/dq0 to abc  Alignment=90 degrees behind phase A axis
  d²1 : Product  InputSameDT=on  RndMeth=Zero  SaturateOnIntegerOverflow=on
  d²2 : Product  InputSameDT=on  RndMeth=Zero  SaturateOnIntegerOverflow=on
  i_dc1 : spsControlledCurrentSourceLib/Controlled Current Source  Initialize=off  Source_Type=DC  Amplitude=i_dc  Phase=0  Frequency=0  Measurements=None
  q²{1..2,4..5} (4 alike) : Product  InputSameDT=on  RndMeth=Zero  SaturateOnIntegerOverflow=on
  A : PMIOPort  Side=Right
  B : PMIOPort  Port=2  Side=Right
  C : PMIOPort  Port=3  Side=Right
  f1 : Outport  VectorParamsAs1DForOutWhenUnconnected=off
  V1 : Outport  Port=2  VectorParamsAs1DForOutWhenUnconnected=off
  P1 : Outport  Port=3  VectorParamsAs1DForOutWhenUnconnected=off
  Theta1 : Outport  Port=4  VectorParamsAs1DForOutWhenUnconnected=off
  vabc1 : Outport  Port=5  VectorParamsAs1DForOutWhenUnconnected=off
  iabc1 : Outport  Port=6  VectorParamsAs1DForOutWhenUnconnected=off
  vdc1 : Outport  Port=7  VectorParamsAs1DForOutWhenUnconnected=off
  idc1 : Outport  Port=8  VectorParamsAs1DForOutWhenUnconnected=off
  close_signal : Outport  Port=9
  I2 : Outport  Port=10  VectorParamsAs1DForOutWhenUnconnected=off
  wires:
  Memory2/1 -> [v_abc]
  Current Measurement3/1 -> Mux3/3
  Mux4/1 -> Memory1/1
  Memory3/1 -> [i_abc]
  Current Measurement/1 -> [i_dc_s]
  Current Measurement1/1 -> Mux3/1
  Voltage Measurement1/1 -> Mux1/1
  Current Measurement2/1 -> Mux3/2
  Voltage Measurement6/1 -> Mux2/3
  Memory1/1 -> [i_s_abc]
  Voltage Measurement2/1 -> Mux1/2
  Memory4/1 -> [v_dc]
  Voltage Measurement4/1 -> Mux2/1
  Mux2/1 -> Memory2/1
  Current Measurement4/1 -> Mux4/1
  Mux1/1 -> Memory/1
  Mux3/1 -> Memory3/1
  Voltage Measurement3/1 -> Mux1/3
  Current Measurement5/1 -> Mux4/2
  Current Measurement6/1 -> Mux4/3
  Voltage Measurement5/1 -> Mux2/2
  Memory/1 -> [v_s_abc]
  Voltage Measurement/1 -> Memory4/1
  [P_abc] -> Gain7/1
  [V] -> Gain4/1
  [v_dc] -> vdc1/1
  [i_abc] -> iabc1/1
  Gain7/1 -> P1/1
  [theta] -> Theta1/1
  [w] -> Gain12/1
  Gain12/1 -> f1/1
  [v_abc] -> vabc1/1
  Gain4/1 -> V1/1
  [i_dc_s] -> idc1/1
  [i_abc] -> abc to dq3/1
  abc to dq1/1 -> "Power (dq0, Instantaneous)"/2
  abc to dq7/1 -> "Power (dq0, Instantaneous)1"/2
  abc to dq4/1 -> [i_s_dq0]
  [theta] -> abc to dq7/2, abc to dq8/2
  [i_s_abc] -> abc to dq7/1
  [v_abc] -> abc to dq6/1
  [v_s_abc] -> abc to dq5/1
  [theta] -> abc to dq1/2, abc to dq2/2
  Sum2/1 -> Sqrt2/1
  q²4/1 -> Sum2/2
  [v_s_abc] -> abc to dq8/1
  [i_abc] -> abc to dq1/1
  d²2/1 -> Sum2/1
  abc to dq6/1 -> [v_dq0]
  Demux2/2 -> q²4/2, q²4/1  "q"
  "Power (dq0, Instantaneous)1"/2 -> [Q_s_abc]
  Demux2/1 -> d²2/2, d²2/1  "d"
  "Power (dq0, Instantaneous)1"/1 -> [P_s_abc]
  [theta] -> abc to dq3/2, abc to dq6/2, abc to dq5/2, abc to dq4/2
  [v_dq0] -> Demux2/1
  abc to dq2/1 -> "Power (dq0, Instantaneous)"/1
  abc to dq3/1 -> [i_dq0]
  [v_abc] -> abc to dq2/1
  Sqrt2/1 -> [V]
  [i_s_abc] -> abc to dq4/1
  "Power (dq0, Instantaneous)"/1 -> [P_abc]
  abc to dq8/1 -> "Power (dq0, Instantaneous)1"/1
  "Power (dq0, Instantaneous)"/2 -> [Q_abc]
  Demux2/3 -> q²5/2, q²5/1  "0"
  abc to dq5/1 -> [v_s_dq0]
  Gain2/1 -> [P_set]
  q²5/1 -> Sum2/3
  Pset2/1 -> Gain2/1
  [theta] -> dq0 to abc/2
  dq0 to abc/1 -> Gain19/1
  Gain19/1 -> Universal Bridge/1
  [v_s_ref_dq0] -> dq0 to abc/1
  Switch/1 -> i_dc1/1
  [P_set] -> Gain13/1
  Gain13/1 -> Add4/2
  Constant1/1 -> Add6/1
  Gain16/1 -> Add4/1
  LTI System3/1 -> Saturation/1, Switch/3
  [v_dc] -> Gain17/1
  Gain14/1 -> Add4/4
  Add6/1 -> Gain16/1
  Clock/1 -> Switch/2
  [v_dc] -> Add6/2
  Gain17/1 -> Add4/3
  [P_s_abc] -> Add2/1
  [P_abc] -> Add2/2
  Saturation/1 -> Switch/1
  Add4/1 -> LTI System3/1
  VSM Control/1(w_ref) -> [w]
  [P_abc] -> VSM Control/1(p_m)
  Current Loop/1(v_s_ref_dq0) -> [v_s_ref_dq0]
  [v_dq0] -> Voltage Loop/2(v_dq0)
  VSM Control/2(theta_ref) -> [theta]
  [w] -> Current Loop/4(w)
  [i_dq0] -> Voltage Loop/3(i_dq0)
  Voltage Loop/1(i_s_ref_dq0) -> Current Loop/1(i_s_ref_dq0)
  [i_s_dq0] -> Current Loop/3(i_s_dq0)
  [P_set] -> VSM Control/2(p_set)
  [v_ref_dq0] -> Voltage Loop/1(v_ref_dq0)
  [v_dq0] -> Current Loop/2(v_dq0)
  [w] -> Voltage Loop/4(w)
  [v_abc] -> VSM Control/4(V_abc)
  VSM Control/3(v_ref_dq0) -> [v_ref_dq0]
  Constant2/1 -> VSM Control/5(w_b)
  Ramp/1 -> Saturation1/1
  Saturation1/1 -> VSM Control/3(v_m)
  VSM Control/4(close_signal) -> close_signal/1
  q²1/1 -> Sum1/2
  Demux1/1 -> d²1/2, d²1/1  "d"
  q²2/1 -> Sum1/3
  Sum1/1 -> Sqrt1/1
  Sqrt1/1 -> [I]
  d²1/1 -> Sum1/1
  Demux1/3 -> q²2/2, q²2/1  "0"
  [i_dq0] -> Demux1/1
  Demux1/2 -> q²1/2, q²1/1  "q"
  [I] -> Gain1/1
  Gain1/1 -> I2/1
  Add2/1 -> Transfer Fcn2/1
  Transfer Fcn2/1 -> Gain14/1
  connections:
  RL_c/RConn1 -- C_c1/LConn1 -- Current Measurement1/LConn1 -- Voltage Measurement4/LConn1
  i_dc1/LConn1 -- G_dc1/RConn1 -- C_dc1/RConn1 -- Voltage Measurement/LConn2 -- Universal Bridge/RConn2
  C_b/LConn1 -- RL_b/RConn1 -- Current Measurement2/LConn1 -- Voltage Measurement5/LConn1
  Voltage Measurement1/LConn2 -- Voltage Measurement2/LConn2 -- Ground/LConn1 -- Voltage Measurement3/LConn2
  Ground1/LConn1 -- Voltage Measurement6/LConn2 -- Voltage Measurement4/LConn2 -- Voltage Measurement5/LConn2
  Ground2/LConn1 -- C_a/RConn1 -- C_b/RConn1 -- C_c1/RConn1
  Current Measurement5/LConn1 -- Universal Bridge/LConn2 -- Voltage Measurement2/LConn1
  C_a/LConn1 -- Current Measurement3/LConn1 -- Voltage Measurement6/LConn1 -- RL_a/RConn1
  Universal Bridge/RConn1 -- Voltage Measurement/LConn1 -- Current Measurement/RConn1 -- G_dc1/LConn1 -- C_dc1/LConn1
  Current Measurement4/LConn1 -- Universal Bridge/LConn1 -- Voltage Measurement1/LConn1
  Universal Bridge/LConn3 -- Current Measurement6/LConn1 -- Voltage Measurement3/LConn1
  Current Measurement2/RConn1 -- B/RConn1
  Current Measurement3/RConn1 -- C/RConn1
  i_dc1/RConn1 -- Current Measurement/LConn1
  Current Measurement6/RConn1 -- RL_a/LConn1
  Current Measurement5/RConn1 -- RL_b/LConn1
  Current Measurement4/RConn1 -- RL_c/LConn1
  Current Measurement1/RConn1 -- A/RConn1
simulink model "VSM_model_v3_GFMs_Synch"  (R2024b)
settings: Solver=ode23tb  StartTime=0.0  StopTime=Tend  FixedStep=T_s  RelTol=1e-3  EnableMultiTasking=on
PostLoadFcn:
  | Tcontrol=20e-6;
InitFcn:
  | Tcontrol=20e-6;
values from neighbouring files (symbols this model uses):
  C_4 = 0.1670*C_b    (= 1.00487241952e-06)    [VSM.m]    (also in VSM_CSIRO.m)
  C_6 = 0.2835*C_b    (= 1.70587623314e-06)    [VSM.m]    (also in VSM_CSIRO.m)
  C_8 = 0.2275*C_b    (= 1.36891302659e-06)    [VSM.m]    (also in VSM_CSIRO.m)
  C_dc = 0.008*(n)    (= 1.6)    [VSM.m]    (also in VSM_CSIRO.m)
  C_f = n*300*10^-6    (= 0.06)    [VSM.m]    (also in VSM_CSIRO.m)
  C_f_gfl = (n_gfl) * Cf_unit_gfl    (= 0.00350140874802)    [DER_param.m]
  D_p = (1/(m_p*w_b))    (= 101321.183642)    [VSM.m]    (also in VSM_CSIRO.m)
  droop_percentage = 5    [VSM.m]    (also in VSM_CSIRO.m = 1)
  I_b_dc = S_b/Vdc_n    [VSM.m]    (also in VSM_CSIRO.m)
  I_b_LV_peak = I_b_LV * sqrt(2)    [VSM.m]
  I_b_SG_peak = I_b_SG * sqrt(2)    [VSM.m]
  i_ll = -1.15*(S_b/Vdc_n)-i_loss_dc    [VSM.m]    (also in VSM_CSIRO.m)
  i_ul = 1.15*(S_b/Vdc_n)+i_loss_dc    [VSM.m]    (also in VSM_CSIRO.m)
  J = D_p*tau_f    (= 2026.42367285)    [VSM.m]    (also in VSM_CSIRO.m)
  k_dc = eta_1/(Vdc_n*m_p)    [VSM.m]    (also in VSM_CSIRO.m)
  K_p = (1/Vdc_n)    [VSM.m]    (also in VSM_CSIRO.m)
  K_r = 1/R_dc    [VSM.m]    (also in VSM_CSIRO.m)
  Kff_i = 1    [VSM.m]    (also in VSM_CSIRO.m)
  Kff_v = 1    [VSM.m]    (also in VSM_CSIRO.m)
  Ki_i = (1/n)*1.19    (= 0.00595)    [VSM.m]    (also in VSM_CSIRO.m)
  Ki_i_gfl = (1/n_gfl) * Ki_i_unit_gfl    (= 0.571198664289)    [DER_param.m]
  Ki_v = (n)*1.161022    (= 232.2044)    [VSM.m]    (also in VSM_CSIRO.m)
  ki_v_ac = 4*5.2500e-04    (= 0.0021)    [VSM.m]    (also in VSM_CSIRO.m)
  Kp_i = 0.738891    [VSM.m]    (also in VSM_CSIRO.m)
  Kp_i_gfl = (1/n_gfl) * Kp_i_unit_gfl    (= 0.00909090909091)    [DER_param.m]
  Kp_v = 0.52    [VSM.m]    (also in VSM_CSIRO.m)
  kp_v_ac = 0.001    [VSM.m]    (also in VSM_CSIRO.m)
  L1_f_gfl = (1/n_gfl) * L1_unit_gfl    (= 1.44686311902e-05)    [DER_param.m]
  L1_pu = 1*0.0186/m    (= 0.000186)    [VSM.m]    (also in VSM_CSIRO.m)
  L1_pu_gfl = 0.03    [DER_param.m]
  L2_f_gfl = (1/n_gfl) * L2_unit_gfl    (= 2.89372623803e-06)    [DER_param.m]
  L2_pu_gfl = 0.03    [DER_param.m]
  L_45 = L_lines(2)    [VSM.m]    (also in VSM_CSIRO.m)
  L_56 = L_lines(3)    [VSM.m]    (also in VSM_CSIRO.m)
  L_67 = L_lines(5)    [VSM.m]    (also in VSM_CSIRO.m)
  L_78 = L_lines(6)    [VSM.m]    (also in VSM_CSIRO.m)
  L_89 = L_lines(8)    [VSM.m]    (also in VSM_CSIRO.m)
  L_94 = L_lines(9)    [VSM.m]    (also in VSM_CSIRO.m)
  L_f = (1/n)*200*10^-6    (= 1e-06)    [VSM.m]    (also in VSM_CSIRO.m)
  Lg = (X_BY_R_gfl * Rg) / wn_gfl    [DER_param.m]    (also in initialcondition_gfm_Pooyan.m = X_BY_R*Rg/(wn); initialcondition_Pooyan.m = X_BY_R*Rg/(wn))
  n = 200    [VSM.m]    (also in VSM_CSIRO.m)
  Pgen_MW_gfl = 20    [DER_param.m]
  ps = base/3    (= 0.75)    [VSM.m]    (also in VSM_CSIRO.m)
  R1_f_gfl = (1/n_gfl) * R1_unit_gfl    (= 0.000909090909091)    [DER_param.m]
  R1_pu = 1*0.00734/m    (= 7.34e-05)    [VSM.m]    (also in VSM_CSIRO.m)
  R1_pu_gfl = 0.005    [DER_param.m]
  R2_f_gfl = (1/n_gfl) * R2_unit_gfl    (= 0.000181818181818)    [DER_param.m]
  R2_pu_gfl = 0.005    [DER_param.m]
  R_45 = R_lines(2)    [VSM.m]    (also in VSM_CSIRO.m)
  R_56 = R_lines(3)    [VSM.m]    (also in VSM_CSIRO.m)
  R_67 = R_lines(5)    [VSM.m]    (also in VSM_CSIRO.m)
  R_78 = R_lines(6)    [VSM.m]    (also in VSM_CSIRO.m)
  R_89 = R_lines(8)    [VSM.m]    (also in VSM_CSIRO.m)
  R_94 = R_lines(9)    [VSM.m]    (also in VSM_CSIRO.m)
  R_base_gfl = (3 * Vg_gfl^2) / (2 * Pn_gfl)    [DER_param.m]
  R_dc = (Vdc_n/(0.05*(S_b)/Vdc_n))    [VSM.m]    (also in VSM_CSIRO.m)
  R_f = 0.001/n    (= 5e-06)    [VSM.m]    (also in VSM_CSIRO.m)
  Rg = (3 * Vg_gfl^2) / (2 * SCR_gfl * sqrt(1 + X_BY_R_gfl^2) * Pn_gfl)    [DER_param.m]    (also in initialcondition_gfm_Pooyan.m = (3*Vg^2)/(2*SCR*sqrt(1+X_BY_R^2)*Pn); initialcondition_Pooyan.m = (3*Vg^2)/(2*SCR*sqrt(1+X_BY_R^2)*Pn))
  S_b = 100*(10^6)    (= 100000000)    [VSM.m]    (also in VSM_CSIRO.m)
  S_bt = S_b    (= 100000000)    [VSM.m]    (also in VSM_CSIRO.m)
  S_bt_gfl = S_b_gfl    (= 22000000)    [DER_param.m]
  T_en = T_load-0.5    (= 24.5)    [VSM.m]    (also in VSM_CSIRO.m = 44.5)
  T_s = 1e-4    (= 0.0001)    [VSM.m]    (also in VSM_CSIRO.m)
  tau_dc = 0.05    [VSM.m]    (also in VSM_CSIRO.m)
  tau_g = 5    [VSM.m]    (also in VSM_CSIRO.m)
  Tend = 90    [VSM.m]    (also in VSM_CSIRO.m = 50)
  ts_DER = 15    [DER_param.m]
  V1_rms = 1000    [VSM.m]    (also in VSM_CSIRO.m)
  V1_rms_gfl = 1000    [DER_param.m]
  V1_rms_tx1_gfl = 1000    [DER_param.m]
  V2_rms = 13800    [VSM.m]    (also in VSM_CSIRO.m)
  V2_rms_tx1_gfl = 13800    [DER_param.m]
  V_b = 230*(10^3)    (= 230000)    [VSM.m]    (also in VSM_CSIRO.m)
  V_m = sqrt(2/3)*V1_rms    [VSM.m]    (also in VSM_CSIRO.m)
  V_m_gfl = sqrt(2/3)*V1_rms_gfl    [DER_param.m]
  V_sg_p = sqrt(2/3)*V2_rms    [VSM.m]
  Vdc_n = 3*V_m    [VSM.m]    (also in VSM_CSIRO.m)
  Vdc_n_gfl = 2300    [DER_param.m]
  w_b = 2*pi*f_b    (= 314.159265359)    [VSM.m]    (also in VSM_CSIRO.m)
  w_b_gfl = 2*pi*f_b_gfl    (= 314.159265359)    [DER_param.m]
  w_f = 2*pi*5    (= 31.4159265359)    [VSM.m]    (also in VSM_CSIRO.m)
undefined symbols (not defined in the file or in its folder): D1, Delta, DiscIntNeverNeededParam, dspblkCoreblockFVToolHelper, gcbh, i_dc, magnitude
libraries: spsSeriesRLCBranchLib x82, spsabctodq0Lib x40, slpidlib x36, spsVoltageMeasurementLib x32, spsThreePhaseVIMeasurementLib x31, spsThreePhaseBreakerLib x26, spsGroundLib x22, spsCurrentMeasurementLib x20, spsPLL3phLib x14, spsThreePhaseTransformerTwoWindingsLib x14, simulink x13, spsThreePhaseSeriesRLCBranchLib x10
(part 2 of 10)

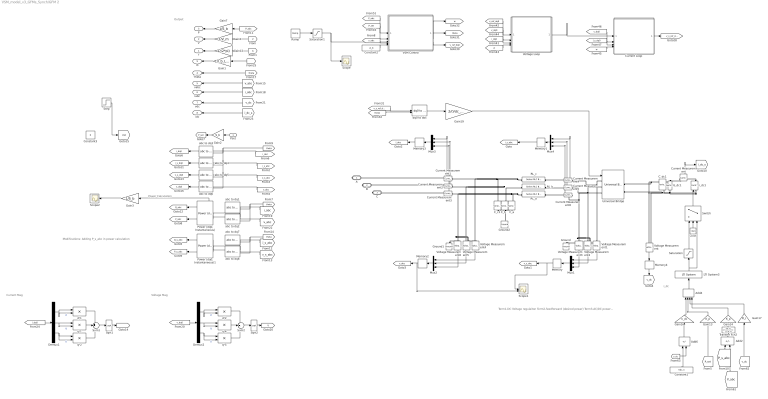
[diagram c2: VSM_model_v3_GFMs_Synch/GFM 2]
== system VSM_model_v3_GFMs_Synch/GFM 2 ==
  note: Modifications: Adding P_s_abc in power calculation
  note: Power Calculation
  note: Output
  note: Voltage Mag
  note: Term1-DC Voltage regulaiton Term2-feedforward (desired power) Term3-AC/DC power balance correciton Term4-Loss compensation (converter switching or filter resistor losses)
  note: i_dc
  note: Current Mag
  Pset : Inport
  Add2 : Sum  Inputs=+-
  Add4 : Sum  Inputs=++++
  Add6 : Sum  Inputs=+-
  C_a : spsSeriesRLCBranchLib/Series RLC Branch  LConnTagsString=__new0  RConnTagsString=__new0  BranchType=C  Resistance=1  Inductance=1e-3  SetiL0=off  InitialCurrent=0  Capacitance=C_f  Setx0=off  InitialVoltage=165  Measurements=None
  C_b : spsSeriesRLCBranchLib/Series RLC Branch  LConnTagsString=__new0  RConnTagsString=__new0  BranchType=C  Resistance=1  Inductance=1e-3  SetiL0=off  InitialCurrent=0  Capacitance=C_f  Setx0=off  InitialVoltage=165  Measurements=None
  C_c1 : spsSeriesRLCBranchLib/Series RLC Branch  LConnTagsString=__new0  RConnTagsString=__new0  BranchType=C  Resistance=1  Inductance=1e-3  SetiL0=off  InitialCurrent=0  Capacitance=C_f  Setx0=off  InitialVoltage=165  Measurements=None
  C_dc1 : spsSeriesRLCBranchLib/Series RLC Branch  LConnTagsString=__new0  RConnTagsString=__new0  BranchType=C  Resistance=1  Inductance=1e-3  SetiL0=off  InitialCurrent=0  Capacitance=C_dc  Setx0=off  InitialVoltage=Vdc_n  Measurements=None
  Clock : Clock
  Constant1 : Constant  Value=Vdc_n
  Constant2 : Constant  Value=w_b
  Constant3 : Constant  Value=0
  Current Loop : Subsystem
  Current Measurement{,1..6} (7 alike) : spsCurrentMeasurementLib/Current Measurement  PhasorSimulation=off  OutputType=Complex  PSBequivalent=0
  Demux1 : Demux  Outputs=3
  Demux2 : Demux  Outputs=3
  G_dc1 : spsSeriesRLCBranchLib/Series RLC Branch  LConnTagsString=__new0  RConnTagsString=__new0  BranchType=R  Resistance=R_dc  Inductance=1e-3  SetiL0=off  InitialCurrent=0  Capacitance=1e-6  Setx0=off  InitialVoltage=0  Measurements=None
  Gain1 : Gain  Gain=1/I_b_LV_peak
  Gain12 : Gain  Gain=1/(2*pi)
  Gain13 : Gain  Gain=K_p
  Gain14 : Gain  Gain=K_p
  Gain16 : Gain  Gain=k_dc
  Gain17 : Gain  Gain=K_r
  Gain19 : Gain  Gain=2/(Vdc_n)
  Gain2 : Gain  Gain=S_b
  Gain3 : Gain  Gain=1/S_b
  Gain4 : Gain  Gain=1/V_m
  Gain7 : Gain  Gain=1/S_b
  Ground : spsGroundLib/Ground  LConnTagsString=a
  Ground1 : spsGroundLib/Ground  LConnTagsString=a
  Ground2 : spsGroundLib/Ground  LConnTagsString=a
  LTI System3 : cstblocks/LTI System  sys=tf(1,[tau_dc 1])  IC=[]  PadeOrder=0
  Memory{,1..4} (5 alike) : Memory
  Mux{1..4} (4 alike) : Mux  Inputs=3
  "Power (dq0, Instantaneous)" : spsPowerdq0InstantaneousLib/Power (dq0, Instantaneous)
  "Power (dq0, Instantaneous)1" : spsPowerdq0InstantaneousLib/Power (dq0, Instantaneous)
  RL_a : spsSeriesRLCBranchLib/Series RLC Branch  LConnTagsString=__new0  RConnTagsString=__new0  BranchType=RL  Resistance=R_f  Inductance=L_f  SetiL0=off  InitialCurrent=0  Capacitance=1e-6  Setx0=off  InitialVoltage=0  Measurements=Branch voltage and current
  RL_b : spsSeriesRLCBranchLib/Series RLC Branch  LConnTagsString=__new0  RConnTagsString=__new0  BranchType=RL  Resistance=R_f  Inductance=L_f  SetiL0=off  InitialCurrent=0  Capacitance=1e-6  Setx0=off  InitialVoltage=0  Measurements=None
  RL_c : spsSeriesRLCBranchLib/Series RLC Branch  LConnTagsString=__new0  RConnTagsString=__new0  BranchType=RL  Resistance=R_f  Inductance=L_f  SetiL0=off  InitialCurrent=0  Capacitance=1e-6  Setx0=off  InitialVoltage=0  Measurements=None
  Ramp : simulink/Sources/Ramp  slope=V_m  start=0  InitialOutput=0
  Saturation : Saturate  UpperLimit=i_ul  LowerLimit=i_ll
  Saturation1 : Saturate  UpperLimit=V_m  LowerLimit=0
  Scope : Scope
  Scope1 : Scope  NumInputPorts=2
  Scope2 : Scope
  Sqrt1 : Sqrt
  Sqrt2 : Sqrt
  Step : Step  Time=T_s  Before=1  After=0  SampleTime=T_s
  Sum1 : Sum  Inputs=+++  InputSameDT=on  SaturateOnIntegerOverflow=on
  Sum2 : Sum  Inputs=+++  InputSameDT=on  SaturateOnIntegerOverflow=on
  Switch : Switch  Criteria=u2 > Threshold  Threshold=T_en
  Transfer Fcn2 : TransferFcn  Numerator=[w_f]  Denominator=[1 w_f]
  Universal Bridge : spsUniversalBridgeLib/Universal Bridge  Arms=3  SnubberResistance=1e5  SnubberCapacitance=inf  Device=Average-model based VSC  Ron=1e-3  Lon=0  ForwardVoltages="[  0  0  ]"  ForwardVoltage=0  GTOparameters=[ 10e-6 , 20e-6 ]  IGBTparameters=[ 1e-6 , 2e-6 ]  Measurements=None  Measurements_2=None  converterType=Rectifier
  VSM Control : Subsystem
  Voltage Loop : Subsystem
  Voltage Measurement{,1..6} (7 alike) : spsVoltageMeasurementLib/Voltage Measurement  PhasorSimulation=off  OutputType=Complex  PSBequivalent=0
  abc to dq{1..8} (8 alike) : spsabctodq0Lib/abc to dq0  Alignment=90 degrees behind phase A axis
  dq0 to abc : spsdq0toabcLib/dq0 to abc  Alignment=90 degrees behind phase A axis
  d²1 : Product  InputSameDT=on  RndMeth=Zero  SaturateOnIntegerOverflow=on
  d²2 : Product  InputSameDT=on  RndMeth=Zero  SaturateOnIntegerOverflow=on
  i_dc1 : spsControlledCurrentSourceLib/Controlled Current Source  Initialize=off  Source_Type=DC  Amplitude=i_dc  Phase=0  Frequency=0  Measurements=None
  q²{1..2,4..5} (4 alike) : Product  InputSameDT=on  RndMeth=Zero  SaturateOnIntegerOverflow=on
  A : PMIOPort  Side=Right
  B : PMIOPort  Port=2  Side=Right
  C : PMIOPort  Port=3  Side=Right
  f : Outport  VectorParamsAs1DForOutWhenUnconnected=off
  V : Outport  Port=2  VectorParamsAs1DForOutWhenUnconnected=off
  P : Outport  Port=3  VectorParamsAs1DForOutWhenUnconnected=off
  Theta : Outport  Port=4  VectorParamsAs1DForOutWhenUnconnected=off
  vabc : Outport  Port=5  VectorParamsAs1DForOutWhenUnconnected=off
  iabc : Outport  Port=6  VectorParamsAs1DForOutWhenUnconnected=off
  vdc : Outport  Port=7  VectorParamsAs1DForOutWhenUnconnected=off
  idc : Outport  Port=8  VectorParamsAs1DForOutWhenUnconnected=off
  I3 : Outport  Port=9  VectorParamsAs1DForOutWhenUnconnected=off
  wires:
  [v_dc] -> Gain17/1
  [P_s_abc] -> Add2/1
  Add6/1 -> Gain16/1
  [v_dc] -> Add6/2
  Gain17/1 -> Add4/3
  Constant1/1 -> Add6/1
  Gain16/1 -> Add4/1
  Gain13/1 -> Add4/2
  [P_set] -> Gain13/1
  Gain14/1 -> Add4/4
  [P_abc] -> Add2/2
  VSM Control/1(w_ref) -> [w]
  [P_abc] -> VSM Control/1(p_m)
  [v_abc] -> VSM Control/4(V_abc)
  [P_set] -> VSM Control/2(p_set)
  Constant2/1 -> VSM Control/5(w_b)
  VSM Control/3(v_ref_dq0) -> [v_ref_dq0]
  VSM Control/2(theta_ref) -> [theta]
  [v_s_ref_dq0] -> dq0 to abc/1
  Gain19/1 -> Universal Bridge/1
  Switch/1 -> i_dc1/1
  [v_dq0] -> Voltage Loop/2(v_dq0)
  [w] -> Voltage Loop/4(w)
  Current Loop/1(v_s_ref_dq0) -> [v_s_ref_dq0]
  [i_s_dq0] -> Current Loop/3(i_s_dq0)
  [v_dq0] -> Current Loop/2(v_dq0)
  Voltage Loop/1(i_s_ref_dq0) -> Current Loop/1(i_s_ref_dq0)
  [i_dq0] -> Voltage Loop/3(i_dq0)
  [v_ref_dq0] -> Voltage Loop/1(v_ref_dq0)
  [w] -> Current Loop/4(w)
  dq0 to abc/1 -> Gain19/1
  Memory1/1 -> [i_s_abc]
  Memory/1 -> Scope1/1, [v_s_abc]
  Memory4/1 -> [v_dc]
  Voltage Measurement/1 -> Memory4/1
  Memory3/1 -> [i_abc]
  Memory2/1 -> Scope1/2, [v_abc]
  Mux4/1 -> Memory1/1
  Sqrt2/1 -> [V]
  Demux2/1 -> d²2/2, d²2/1  "d"
  Demux2/2 -> q²4/2, q²4/1  "q"
  d²2/1 -> Sum2/1
  Demux2/3 -> q²5/2, q²5/1  "0"
  Sum2/1 -> Sqrt2/1
  q²5/1 -> Sum2/3
  [v_dq0] -> Demux2/1
  q²4/1 -> Sum2/2
  [theta] -> dq0 to abc/2
  abc to dq6/1 -> [v_dq0]
  abc to dq5/1 -> [v_s_dq0]
  abc to dq4/1 -> [i_s_dq0]
  abc to dq3/1 -> [i_dq0]
  [theta] -> abc to dq3/2, abc to dq6/2, abc to dq5/2, abc to dq4/2
  [v_s_abc] -> abc to dq5/1
  [v_abc] -> abc to dq6/1
  [i_s_abc] -> abc to dq4/1
  [i_abc] -> abc to dq3/1
  [theta] -> Theta/1
  Gain4/1 -> V/1
  [i_abc] -> abc to dq1/1
  "Power (dq0, Instantaneous)"/1 -> [P_abc]
  "Power (dq0, Instantaneous)"/2 -> Gain3/1, [Q_abc]
  [v_abc] -> abc to dq2/1
  [theta] -> abc to dq1/2, abc to dq2/2
  abc to dq2/1 -> "Power (dq0, Instantaneous)"/1
  abc to dq1/1 -> "Power (dq0, Instantaneous)"/2
  Mux1/1 -> Memory/1
  Mux3/1 -> Memory3/1
  Mux2/1 -> Memory2/1
  [w] -> Gain12/1
  Gain12/1 -> f/1
  Pset/1 -> Gain2/1
  Gain2/1 -> [P_set]
  [V] -> Gain4/1
  Voltage Measurement1/1 -> Mux1/1
  Voltage Measurement2/1 -> Mux1/2
  Voltage Measurement3/1 -> Mux1/3
  Voltage Measurement6/1 -> Mux2/3
  Voltage Measurement5/1 -> Mux2/2
  Voltage Measurement4/1 -> Mux2/1
  Current Measurement1/1 -> Mux3/1
  Current Measurement2/1 -> Mux3/2
  Current Measurement3/1 -> Mux3/3
  Current Measurement4/1 -> Mux4/1
  Current Measurement5/1 -> Mux4/2
  Current Measurement6/1 -> Mux4/3
  [P_abc] -> Gain7/1
  Gain7/1 -> P/1
  LTI System3/1 -> Saturation/1, Switch/3
  Saturation/1 -> Switch/1
  Clock/1 -> Switch/2
  Add4/1 -> LTI System3/1
  abc to dq7/1 -> "Power (dq0, Instantaneous)1"/2
  [i_s_abc] -> abc to dq7/1
  "Power (dq0, Instantaneous)1"/2 -> [Q_s_abc]
  "Power (dq0, Instantaneous)1"/1 -> [P_s_abc]
  [theta] -> abc to dq7/2, abc to dq8/2
  abc to dq8/1 -> "Power (dq0, Instantaneous)1"/1
  [v_s_abc] -> abc to dq8/1
  Current Measurement/1 -> [i_dc_s]
  [v_abc] -> vabc/1
  [i_abc] -> iabc/1
  [v_dc] -> vdc/1
  [i_dc_s] -> idc/1
  d²1/1 -> Sum1/1
  Demux1/3 -> q²2/2, q²2/1  "0"
  [i_dq0] -> Demux1/1
  Demux1/2 -> q²1/2, q²1/1  "q"
  Sqrt1/1 -> [I]
  Sum1/1 -> Sqrt1/1
  q²2/1 -> Sum1/3
  Demux1/1 -> d²1/2, d²1/1  "d"
  q²1/1 -> Sum1/2
  [I] -> Gain1/1
  Gain1/1 -> I3/1
  Ramp/1 -> Saturation1/1
  Saturation1/1 -> Scope/1, VSM Control/3(v_m)
  Gain3/1 -> Scope2/1
  Add2/1 -> Transfer Fcn2/1
  Transfer Fcn2/1 -> Gain14/1
  Step/1 -> [rst]
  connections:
  RL_c/RConn1 -- C_c1/LConn1 -- Current Measurement1/LConn1 -- Voltage Measurement4/LConn1
  C_c1/RConn1 -- Ground2/LConn1 -- C_a/RConn1 -- C_b/RConn1
  i_dc1/LConn1 -- G_dc1/RConn1 -- C_dc1/RConn1 -- Voltage Measurement/LConn2 -- Universal Bridge/RConn2
  Voltage Measurement1/LConn1 -- Current Measurement4/LConn1 -- Universal Bridge/LConn1
  Voltage Measurement2/LConn1 -- Current Measurement5/LConn1 -- Universal Bridge/LConn2
  Voltage Measurement3/LConn1 -- Universal Bridge/LConn3 -- Current Measurement6/LConn1
  Current Measurement1/RConn1 -- A/RConn1
  Current Measurement2/RConn1 -- B/RConn1
  Current Measurement3/RConn1 -- C/RConn1
  Voltage Measurement3/LConn2 -- Voltage Measurement1/LConn2 -- Voltage Measurement2/LConn2 -- Ground/LConn1
  Ground1/LConn1 -- Voltage Measurement4/LConn2 -- Voltage Measurement5/LConn2 -- Voltage Measurement6/LConn2
  G_dc1/LConn1 -- C_dc1/LConn1 -- Universal Bridge/RConn1 -- Voltage Measurement/LConn1 -- Current Measurement/RConn1
  Current Measurement5/RConn1 -- RL_b/LConn1
  Current Measurement6/RConn1 -- RL_a/LConn1
  Current Measurement4/RConn1 -- RL_c/LConn1
  RL_a/RConn1 -- C_a/LConn1 -- Current Measurement3/LConn1 -- Voltage Measurement6/LConn1
  C_b/LConn1 -- Current Measurement2/LConn1 -- Voltage Measurement5/LConn1 -- RL_b/RConn1
  i_dc1/RConn1 -- Current Measurement/LConn1

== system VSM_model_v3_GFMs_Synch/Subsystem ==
  note: voltage GFM
  note: current GFM
  In1 : Inport
  In2 : Inport  Port=2
  In3 : Inport  Port=3
  In4 : Inport  Port=4
  Demux{,1..3} (4 alike) : Demux  Outputs=3
  Mux{3..5,7..9} (6 alike) : Mux  Inputs=2
  Out1 : Outport
  Out2 : Outport  Port=2
  Out3 : Outport  Port=3
  Out4 : Outport  Port=4
  Out5 : Outport  Port=5
  Out6 : Outport  Port=6
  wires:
  Demux3/2 -> Mux8/2
  Mux8/1 -> Out5/1
  Demux/1 -> Mux3/1
  Demux/3 -> Mux5/1
  Demux3/1 -> Mux7/2
  Demux1/2 -> Mux4/2
  Mux7/1 -> Out4/1
  Demux2/1 -> Mux7/1
  Demux3/3 -> Mux9/2
  Demux2/2 -> Mux8/1
  Demux2/3 -> Mux9/1
  Demux/2 -> Mux4/1
  Demux1/3 -> Mux5/2
  Demux1/1 -> Mux3/2
  In3/1 -> Demux2/1
  Mux3/1 -> Out1/1
  Mux4/1 -> Out2/1
  In4/1 -> Demux3/1
  In2/1 -> Demux1/1
  In1/1 -> Demux/1
  Mux5/1 -> Out3/1
  Mux9/1 -> Out6/1

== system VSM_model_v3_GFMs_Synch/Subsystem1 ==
  In1 : Inport
  In2 : Inport  Port=2
  In3 : Inport  Port=3
  In4 : Inport  Port=4
  Constant : Constant  Value=I_b_dc
  Constant1 : Constant  Value=Vdc_n
  Divide{,1..3} (4 alike) : Product  Inputs=*/
  Mux : Mux  Inputs=2
  Mux3 : Mux  Inputs=2
  Out1 : Outport
  Out2 : Outport  Port=2
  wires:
  Mux3/1 -> Out2/1
  Mux/1 -> Out1/1
  Constant/1 -> Divide1/2, Divide/2
  In3/1 -> Divide/1
  Divide/1 -> Mux3/1
  In4/1 -> Divide1/1
  Divide1/1 -> Mux3/2
  Constant1/1 -> Divide2/2, Divide3/2
  In1/1 -> Divide2/1
  Divide2/1 -> Mux/1
  In2/1 -> Divide3/1
  Divide3/1 -> Mux/2

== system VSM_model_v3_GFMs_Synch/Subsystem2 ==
  note: GFL1
  Breaker1 : spsThreePhaseBreakerLib/Three-Phase Breaker  Commented=on  InitialState=open  SwitchA=on  SwitchB=on  SwitchC=on  SwitchTimes=34  External=off  BreakerResistance=0.01  SnubberResistance=1e6  SnubberCapacitance=inf  Measurements=None
  DER 1 : Subsystem  Commented=on
  GFL : Subsystem
  LV/MV Trafo 3 : spsThreePhaseTransformerTwoWindingsLib/Three-Phase Transformer (Two Windings)  Commented=on  Winding1Connection=Yg  Winding2Connection=Yg  CoreType=Three single-phase transformers  SetSaturation=off  Hysteresis=off  DataFile='hysteresis'  SetInitialFlux=off  Measurements=None  UNITS=pu  NominalPower=[S_bt 50 ]  Winding1="[ V1_rms R1_pu  L1_pu]"  Winding2=[ V2_rms R1_pu L1_pu]  Rm=Rm_pu  Lm=Lm_pu  L0=0.5  Saturation="[ 0,0  ;  0.005,1.2  ;  1.0,1.4 ]"  InitialFluxes=[ 0.8 , -0.8 , 0.7 ]  BreakLoop=off  DiscreteSolver=Trapezoidal iterative  DataType=off  TransfoNumber=0
  LV/MV Trafo 4 : spsThreePhaseTransformerTwoWindingsLib/Three-Phase Transformer (Two Windings)  Winding1Connection=Yg  Winding2Connection=Yg  CoreType=Three single-phase transformers  SetSaturation=off  Hysteresis=off  DataFile='hysteresis'  SetInitialFlux=off  Measurements=None  UNITS=pu  NominalPower=[S_bt 50 ]  Winding1="[ V1_rms R1_pu  L1_pu]"  Winding2=[ V2_rms R1_pu L1_pu]  Rm=Rm_pu  Lm=Lm_pu  L0=0.5  Saturation="[ 0,0  ;  0.005,1.2  ;  1.0,1.4 ]"  InitialFluxes=[ 0.8 , -0.8 , 0.7 ]  BreakLoop=off  DiscreteSolver=Trapezoidal iterative  DataType=off  TransfoNumber=0
  MV/HV Trafo 1 : spsThreePhaseTransformerTwoWindingsLib/Three-Phase Transformer (Two Windings)  Winding1Connection=Yg  Winding2Connection=Yg  CoreType=Three single-phase transformers  SetSaturation=off  Hysteresis=off  DataFile='hysteresis'  SetInitialFlux=off  Measurements=None  UNITS=pu  NominalPower=[ 210e6 50 ]  Winding1=[V2_rms 0.0027 0.08]  Winding2=[ 230e3 0.0027 0.08]  Rm=500  Lm=500  L0=0.5  Saturation="[ 0,0  ;  0.005,1.2  ;  1.0,1.4 ]"  InitialFluxes=[ 0.8 , -0.8 , 0.7 ]  BreakLoop=off  DiscreteSolver=Trapezoidal iterative  DataType=off  TransfoNumber=0
  MV/HV Trafo 3 : spsThreePhaseTransformerTwoWindingsLib/Three-Phase Transformer (Two Windings)  Commented=on  Winding1Connection=Yg  Winding2Connection=Yg  CoreType=Three single-phase transformers  SetSaturation=off  Hysteresis=off  DataFile='hysteresis'  SetInitialFlux=off  Measurements=None  UNITS=pu  NominalPower=[ 210e6 50 ]  Winding1=[V2_rms 0.0027 0.08]  Winding2=[ 230e3 0.0027 0.08]  Rm=500  Lm=500  L0=0.5  Saturation="[ 0,0  ;  0.005,1.2  ;  1.0,1.4 ]"  InitialFluxes=[ 0.8 , -0.8 , 0.7 ]  BreakLoop=off  DiscreteSolver=Trapezoidal iterative  DataType=off  TransfoNumber=0
  Scope3 : Scope  NumInputPorts=3
  A : PMIOPort  Side=Left
  B : PMIOPort  Port=2  Side=Left
  C : PMIOPort  Port=3  Side=Left
  A1 : PMIOPort  Port=4  Side=Left
  B1 : PMIOPort  Port=5  Side=Left
  C1 : PMIOPort  Port=6  Side=Left
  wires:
  DER 1/1(Out1) -> Scope3/1, [P4]
  GFL/2(Out2) -> [V4]
  DER 1/2(Out2) -> [V4], Scope3/2
  GFL/3(Out4) -> [f_GFL]
  DER 1/3(Out3) -> [f_GFL], Scope3/3
  GFL/1(Out1) -> [P4]
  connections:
  MV/HV Trafo 1/LConn2 -- B1/RConn1
  DER 1/LConn3 -- Breaker1/LConn3
  MV/HV Trafo 3/LConn1 -- A/RConn1
  LV/MV Trafo 4/LConn2 -- GFL/LConn2
  DER 1/LConn1 -- Breaker1/LConn1
  Breaker1/RConn3 -- LV/MV Trafo 3/RConn3
  LV/MV Trafo 4/RConn3 -- MV/HV Trafo 1/RConn3
  MV/HV Trafo 3/LConn2 -- B/RConn1
  LV/MV Trafo 4/LConn1 -- GFL/LConn1
  Breaker1/RConn1 -- LV/MV Trafo 3/RConn1
  LV/MV Trafo 4/RConn2 -- MV/HV Trafo 1/RConn2
  DER 1/LConn2 -- Breaker1/LConn2
  MV/HV Trafo 3/RConn3 -- LV/MV Trafo 3/LConn3
  LV/MV Trafo 4/RConn1 -- MV/HV Trafo 1/RConn1
  LV/MV Trafo 4/LConn3 -- GFL/LConn3
  MV/HV Trafo 3/RConn1 -- LV/MV Trafo 3/LConn1
  MV/HV Trafo 3/LConn3 -- C/RConn1
  Breaker1/RConn2 -- LV/MV Trafo 3/RConn2
  MV/HV Trafo 3/RConn2 -- LV/MV Trafo 3/LConn2
  MV/HV Trafo 1/LConn3 -- C1/RConn1
  MV/HV Trafo 1/LConn1 -- A1/RConn1

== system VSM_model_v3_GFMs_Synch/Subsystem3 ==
  In1 : Inport
  In3 : Inport  Port=2
  In2 : Inport  Port=3
  Demux : Demux  Outputs=3
  Demux1 : Demux  Outputs=3
  Demux2 : Demux  Outputs=3
  Gain : Gain  Gain=1/V_m
  Gain1 : Gain  Gain=1/V_m
  Gain2 : Gain  Gain=1/V_sg_p
  Mux3 : Mux  Inputs=3
  Mux4 : Mux  Inputs=3
  Mux5 : Mux  Inputs=3
  Out1 : Outport
  Out2 : Outport  Port=2
  Out3 : Outport  Port=3
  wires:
  Mux3/1 -> Out1/1
  Mux4/1 -> Out2/1
  In2/1 -> Gain2/1
  In1/1 -> Gain/1
  Mux5/1 -> Out3/1
  In3/1 -> Gain1/1
  Demux/1 -> Mux3/1
  Demux2/1 -> Mux3/2
  Demux1/1 -> Mux3/3
  Demux/2 -> Mux4/1
  Demux2/2 -> Mux4/2
  Demux1/2 -> Mux4/3
  Demux/3 -> Mux5/1
  Demux2/3 -> Mux5/2
  Demux1/3 -> Mux5/3
  Gain/1 -> Demux/1
  Gain1/1 -> Demux2/1
  Gain2/1 -> Demux1/1

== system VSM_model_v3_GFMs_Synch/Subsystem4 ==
  Ground5 : spsGroundLib/Ground  LConnTagsString=a
  Memory1 : Memory
  Mux4 : Mux  Inputs=3
  Voltage Measurement1 : spsVoltageMeasurementLib/Voltage Measurement  PhasorSimulation=off  OutputType=Complex  PSBequivalent=0
  Voltage Measurement2 : spsVoltageMeasurementLib/Voltage Measurement  PhasorSimulation=off  OutputType=Complex  PSBequivalent=0
  Voltage Measurement3 : spsVoltageMeasurementLib/Voltage Measurement  PhasorSimulation=off  OutputType=Complex  PSBequivalent=0
  a : PMIOPort  Side=Left
  b : PMIOPort  Port=2  Side=Left
  c : PMIOPort  Port=3  Side=Left
  Out1 : Outport
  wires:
  Memory1/1 -> Out1/1
  Mux4/1 -> Memory1/1
  Voltage Measurement3/1 -> Mux4/3
  Voltage Measurement1/1 -> Mux4/1
  Voltage Measurement2/1 -> Mux4/2
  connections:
  Voltage Measurement3/LConn2 -- Ground5/LConn1 -- Voltage Measurement2/LConn2 -- Voltage Measurement1/LConn2
  Voltage Measurement3/LConn1 -- a/RConn1
  Voltage Measurement2/LConn1 -- b/RConn1
  Voltage Measurement1/LConn1 -- c/RConn1

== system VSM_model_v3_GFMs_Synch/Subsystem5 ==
  Ground5 : spsGroundLib/Ground  LConnTagsString=a
  Memory1 : Memory
  Mux4 : Mux  Inputs=3
  Voltage Measurement1 : spsVoltageMeasurementLib/Voltage Measurement  PhasorSimulation=off  OutputType=Complex  PSBequivalent=0
  Voltage Measurement2 : spsVoltageMeasurementLib/Voltage Measurement  PhasorSimulation=off  OutputType=Complex  PSBequivalent=0
  Voltage Measurement3 : spsVoltageMeasurementLib/Voltage Measurement  PhasorSimulation=off  OutputType=Complex  PSBequivalent=0
  a : PMIOPort  Side=Left
  b : PMIOPort  Port=2  Side=Left
  c : PMIOPort  Port=3  Side=Left
  Out1 : Outport
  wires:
  Memory1/1 -> Out1/1
  Mux4/1 -> Memory1/1
  Voltage Measurement3/1 -> Mux4/3
  Voltage Measurement1/1 -> Mux4/1
  Voltage Measurement2/1 -> Mux4/2
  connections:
  Voltage Measurement3/LConn2 -- Ground5/LConn1 -- Voltage Measurement2/LConn2 -- Voltage Measurement1/LConn2
  Voltage Measurement3/LConn1 -- a/RConn1
  Voltage Measurement2/LConn1 -- b/RConn1
  Voltage Measurement1/LConn1 -- c/RConn1

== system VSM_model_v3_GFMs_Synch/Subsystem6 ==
  In1 : Inport
  In3 : Inport  Port=2
  Demux : Demux  Outputs=3
  Demux2 : Demux  Outputs=3
  Gain : Gain  Gain=1/V_b
  Gain1 : Gain  Gain=1/V_b
  Mux1 : Mux  Inputs=2
  Mux3 : Mux  Inputs=2
  Mux4 : Mux  Inputs=2
  Out1 : Outport
  Out2 : Outport  Port=2
  Out3 : Outport  Port=3
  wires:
  Gain/1 -> Demux/1
  In1/1 -> Gain/1
  In3/1 -> Gain1/1
  Gain1/1 -> Demux2/1
  Mux1/1 -> Out1/1
  Mux3/1 -> Out2/1
  Mux4/1 -> Out3/1
  Demux/1 -> Mux1/1
  Demux2/1 -> Mux1/2
  Demux/2 -> Mux3/1
  Demux2/2 -> Mux3/2
  Demux/3 -> Mux4/1
  Demux2/3 -> Mux4/2

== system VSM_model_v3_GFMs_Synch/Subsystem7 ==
  Breaker1 : spsThreePhaseBreakerLib/Three-Phase Breaker  InitialState=open  SwitchA=on  SwitchB=on  SwitchC=on  SwitchTimes=ts_DER+2  External=off  BreakerResistance=0.01  SnubberResistance=1e6  SnubberCapacitance=inf  Measurements=None
  Breaker2 : spsThreePhaseBreakerLib/Three-Phase Breaker  InitialState=open  SwitchA=on  SwitchB=on  SwitchC=on  SwitchTimes=ts_DER+7  External=off  BreakerResistance=0.01  SnubberResistance=1e6  SnubberCapacitance=inf  Measurements=None
  Breaker3 : spsThreePhaseBreakerLib/Three-Phase Breaker  InitialState=open  SwitchA=on  SwitchB=on  SwitchC=on  SwitchTimes=ts_DER+16  External=off  BreakerResistance=0.01  SnubberResistance=1e6  SnubberCapacitance=inf  Measurements=None
  Breaker4 : spsThreePhaseBreakerLib/Three-Phase Breaker  Commented=on  InitialState=open  SwitchA=on  SwitchB=on  SwitchC=on  SwitchTimes=ts_DER+2  External=off  BreakerResistance=0.01  SnubberResistance=1e6  SnubberCapacitance=inf  Measurements=None
  Constant : Constant  Value=Pgen_MW_gfl
  Constant1 : Constant  Value=Pgen_MW_gfl
  Constant2 : Constant  Value=Pgen_MW_gfl
  Constant3 : Constant  Commented=on  Value=Pgen_MW_gfl
  LV/MV Trafo 1 : spsThreePhaseTransformerTwoWindingsLib/Three-Phase Transformer (Two Windings)  Winding1Connection=Yg  Winding2Connection=Yg  CoreType=Three single-phase transformers  SetSaturation=off  Hysteresis=off  DataFile='hysteresis'  SetInitialFlux=off  Measurements=None  UNITS=pu  NominalPower=[ S_bt_gfl 50 ]  Winding1="[ V1_rms_tx1_gfl R1_pu_gfl  L1_pu_gfl]"  Winding2=[V2_rms_tx1_gfl R2_pu_gfl L2_pu_gfl]  Rm=Rm_pu_gfl  Lm=Lm_pu_gfl  L0=0.5  Saturation="[ 0,0  ;  0.005,1.2  ;  1.0,1.4 ]"  InitialFluxes=[ 0.8 , -0.8 , 0.7 ]  BreakLoop=off  DiscreteSolver=Trapezoidal iterative  DataType=off  TransfoNumber=0
  LV/MV Trafo 2 : spsThreePhaseTransformerTwoWindingsLib/Three-Phase Transformer (Two Windings)  Winding1Connection=Yg  Winding2Connection=Yg  CoreType=Three single-phase transformers  SetSaturation=off  Hysteresis=off  DataFile='hysteresis'  SetInitialFlux=off  Measurements=None  UNITS=pu  NominalPower=[ S_bt_gfl 50 ]  Winding1="[ V1_rms_tx1_gfl R1_pu_gfl  L1_pu_gfl]"  Winding2=[V2_rms_tx1_gfl R2_pu_gfl L2_pu_gfl]  Rm=Rm_pu_gfl  Lm=Lm_pu_gfl  L0=0.5  Saturation="[ 0,0  ;  0.005,1.2  ;  1.0,1.4 ]"  InitialFluxes=[ 0.8 , -0.8 , 0.7 ]  BreakLoop=off  DiscreteSolver=Trapezoidal iterative  DataType=off  TransfoNumber=0
  LV/MV Trafo 3 : spsThreePhaseTransformerTwoWindingsLib/Three-Phase Transformer (Two Windings)  Winding1Connection=Yg  Winding2Connection=Yg  CoreType=Three single-phase transformers  SetSaturation=off  Hysteresis=off  DataFile='hysteresis'  SetInitialFlux=off  Measurements=None  UNITS=pu  NominalPower=[ S_bt_gfl 50 ]  Winding1="[ V1_rms_tx1_gfl R1_pu_gfl  L1_pu_gfl]"  Winding2=[V2_rms_tx1_gfl R2_pu_gfl L2_pu_gfl]  Rm=Rm_pu_gfl  Lm=Lm_pu_gfl  L0=0.5  Saturation="[ 0,0  ;  0.005,1.2  ;  1.0,1.4 ]"  InitialFluxes=[ 0.8 , -0.8 , 0.7 ]  BreakLoop=off  DiscreteSolver=Trapezoidal iterative  DataType=off  TransfoNumber=0
  LV/MV Trafo 4 : spsThreePhaseTransformerTwoWindingsLib/Three-Phase Transformer (Two Windings)  Commented=on  Winding1Connection=Yg  Winding2Connection=Yg  CoreType=Three single-phase transformers  SetSaturation=off  Hysteresis=off  DataFile='hysteresis'  SetInitialFlux=off  Measurements=None  UNITS=pu  NominalPower=[ S_bt_gfl 50 ]  Winding1="[ V1_rms_tx1_gfl R1_pu_gfl  L1_pu_gfl]"  Winding2=[V2_rms_tx1_gfl R2_pu_gfl L2_pu_gfl]  Rm=Rm_pu_gfl  Lm=Lm_pu_gfl  L0=0.5  Saturation="[ 0,0  ;  0.005,1.2  ;  1.0,1.4 ]"  InitialFluxes=[ 0.8 , -0.8 , 0.7 ]  BreakLoop=off  DiscreteSolver=Trapezoidal iterative  DataType=off  TransfoNumber=0
  Step : Step  Time=ts_DER+3  SampleTime=0
  Step1 : Step  Time=ts_DER+8  SampleTime=0
  Step2 : Step  Time=ts_DER+17  SampleTime=0
  Step3 : Step  Commented=on  Time=ts_DER+3  SampleTime=0
  Subsystem1 : Subsystem
  Subsystem2 : Subsystem
  Subsystem3 : Subsystem  Commented=on
  Subsystem8 : Subsystem
  Connection Port : PMIOPort  Side=Right
  Connection Port1 : PMIOPort  Port=2  Side=Right
  Connection Port2 : PMIOPort  Port=3  Side=Right
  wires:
  Constant/1 -> Subsystem8/1(Inport)
  Step/1 -> Subsystem8/2(Enable)
  Step1/1 -> Subsystem1/2(Enable)
  Constant1/1 -> Subsystem1/1(Inport)
  Constant2/1 -> Subsystem2/1(Inport)
  Step2/1 -> Subsystem2/2(Enable)
  Constant3/1 -> Subsystem3/1(Inport)
  Step3/1 -> Subsystem3/2(Enable)
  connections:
  Subsystem8/RConn2 -- LV/MV Trafo 3/LConn2
  Subsystem8/RConn1 -- LV/MV Trafo 3/LConn1
  Subsystem8/RConn3 -- LV/MV Trafo 3/LConn3
  LV/MV Trafo 3/RConn1 -- Breaker1/LConn1
  LV/MV Trafo 3/RConn2 -- Breaker1/LConn2
  LV/MV Trafo 3/RConn3 -- Breaker1/LConn3
  Connection Port/RConn1 -- Breaker3/RConn1 -- Breaker2/RConn1 -- Breaker1/RConn1
  Connection Port1/RConn1 -- Breaker3/RConn2 -- Breaker2/RConn2 -- Breaker1/RConn2
  Connection Port2/RConn1 -- Breaker3/RConn3 -- Breaker2/RConn3 -- Breaker1/RConn3
  LV/MV Trafo 1/RConn2 -- Breaker2/LConn2
  Subsystem1/RConn2 -- LV/MV Trafo 1/LConn2
  Subsystem1/RConn3 -- LV/MV Trafo 1/LConn3
  Subsystem1/RConn1 -- LV/MV Trafo 1/LConn1
  LV/MV Trafo 1/RConn1 -- Breaker2/LConn1
  LV/MV Trafo 1/RConn3 -- Breaker2/LConn3
  LV/MV Trafo 2/RConn3 -- Breaker3/LConn3
  Subsystem2/RConn2 -- LV/MV Trafo 2/LConn2
  Subsystem2/RConn1 -- LV/MV Trafo 2/LConn1
  LV/MV Trafo 2/RConn1 -- Breaker3/LConn1
  LV/MV Trafo 2/RConn2 -- Breaker3/LConn2
  Subsystem2/RConn3 -- LV/MV Trafo 2/LConn3
  LV/MV Trafo 4/RConn3 -- Breaker4/LConn3
  Subsystem3/RConn2 -- LV/MV Trafo 4/LConn2
  Subsystem3/RConn1 -- LV/MV Trafo 4/LConn1
  LV/MV Trafo 4/RConn1 -- Breaker4/LConn1
  LV/MV Trafo 4/RConn2 -- Breaker4/LConn2
  Subsystem3/RConn3 -- LV/MV Trafo 4/LConn3

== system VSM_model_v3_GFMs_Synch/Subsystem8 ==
  In1 : Inport
  In3 : Inport  Port=2
  Demux : Demux  Outputs=3
  Demux2 : Demux  Outputs=3
  Gain : Gain  Gain=1/V_b
  Gain1 : Gain  Gain=1/V_b
  Mux1 : Mux  Inputs=2
  Mux3 : Mux  Inputs=2
  Mux4 : Mux  Inputs=2
  Out1 : Outport
  Out2 : Outport  Port=2
  Out3 : Outport  Port=3
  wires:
  Gain/1 -> Demux/1
  In1/1 -> Gain/1
  In3/1 -> Gain1/1
  Gain1/1 -> Demux2/1
  Mux1/1 -> Out1/1
  Mux3/1 -> Out2/1
  Mux4/1 -> Out3/1
  Demux/1 -> Mux1/1
  Demux2/1 -> Mux1/2
  Demux/2 -> Mux3/1
  Demux2/2 -> Mux3/2
  Demux/3 -> Mux4/1
  Demux2/3 -> Mux4/2

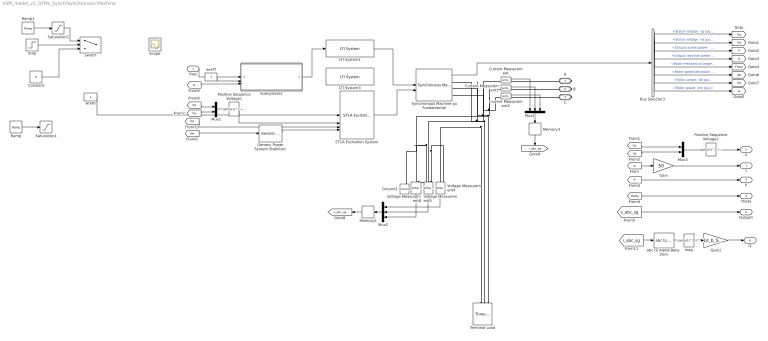
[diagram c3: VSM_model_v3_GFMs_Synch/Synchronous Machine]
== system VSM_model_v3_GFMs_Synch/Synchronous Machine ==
  Pset : Inport
  Bus Selector3 : BusSelector  OutputSignals="dq0 components.Stator voltage  vq (pu),dq0 components.Stator voltage  vd (pu),Output active power   Peo (pu),Output reactive power  Qeo (pu),Mechanical.Rotor mechanical angle  theta (deg),Mechanical.Rotor speed deviation  dw (pu),dq0 components.Field current  ifd (pu),Mechanical.Rotor speed  wm (pu)"
  Constant : Constant  Commented=on  Value=0
  Current Measurement : spsCurrentMeasurementLib/Current Measurement  PhasorSimulation=off  OutputType=Complex  PSBequivalent=0
  Current Measurement1 : spsCurrentMeasurementLib/Current Measurement  PhasorSimulation=off  OutputType=Complex  PSBequivalent=0
  Current Measurement2 : spsCurrentMeasurementLib/Current Measurement  PhasorSimulation=off  OutputType=Complex  PSBequivalent=0
  Gain : Gain  Gain=50
  Gain1 : Gain  Gain=1/I_b_SG_peak
  Generic Power System Stabilizer : spsGenericPowerSystemStabilizerLib/Generic Power System Stabilizer  Tsensor=30e-4  K=2.5  Twashout=2  Tleadlag1=[2*50e-3 0.01*20e-3]  Tleadlag2=[2*3 0.1*5.4]  VSlimits=2*[-0.15 0.15]  Vinit=0  Plot_On=off  MagdB_On=on  FreqRange=logspace(-2,2,500)
  Ground1 : spsGroundLib/Ground  LConnTagsString=a
  LTI System1 : cstblocks/LTI System  sys=ss(-1/tau_g,1/tau_g,1,[])  IC=ps  PadeOrder=0
  LTI System3 : cstblocks/LTI System  Commented=on  sys=tf(1,[tau_g 1])  IC=[]  PadeOrder=0
  Memory2 : Memory
  Memory3 : Memory
  Mux1 : Mux  Inputs=2
  Mux2 : Mux  Inputs=3
  Mux3 : Mux  Inputs=2
  Mux4 : Mux  Inputs=3
  Positive Sequence Voltage1 : Fcn  Expr=sqrt(u(1)^2 + u(2)^2)
  Positive Sequence Voltage2 : Fcn  Expr=sqrt(u(1)^2 + u(2)^2)
  Ramp : simulink/Sources/Ramp  Commented=on  slope=1/3  start=0  InitialOutput=0
  Ramp1 : simulink/Sources/Ramp  Commented=on  slope=ps/10  start=0  InitialOutput=0
  ST1A Excitation System : spsST1AExcitationSystemLib/ST1A Excitation System  Tr=20e-4  KaTa=[210 0.001]  VIminmax=[-999 +999]  VAminmax=[-999 999]  VRminmax=[-6.0 6.43]  KfTf=[0.001 1]  TbTc=[0 0 0 0]  KLR=1  ILR=2  Kc=0.038  v0=[1 1]  TsBlock=0
  Saturation1 : Saturate  Commented=on  UpperLimit=1  LowerLimit=0
  Saturation2 : Saturate  Commented=on  UpperLimit=ps  LowerLimit=0
  Scope : Scope
  Step : Step  Commented=on  Time=3  SampleTime=0
  Subsystem2 : Subsystem
  Switch : Switch  Commented=on  Criteria=u2 > Threshold
  Synchronous Machine pu Fundamental : spsSynchronousMachinepuFundamentalLib/Synchronous Machine pu Fundamental  PresetModel=No  MechanicalLoad=Mechanical power Pm  ShowDetailedParameters=on  RotorType=Salient-pole  Units=per unit fundamental parameters  MeasurementBus=off  NominalParameters="[100E6  V2_rms   50]"  Stator="[ 2.85E-03  0.114  1.19  0.36 ]"  Field="[ 5.79E-04  0.114]"  Dampers2=[0.0652, 0.5134, 0.0287, 0.2553, 7.765e-3, 0.9167 ]  Dampers1="[ 1.17E-02  0.182  1.97E-02  0.384 ]"  Mechanical=[ 3.7 0 20]  PolePairs=20  InitialConditions=[0 0 0 0 0 0 0 0 1]  SetSaturation=off  Saturation=[0.6404,0.7127,0.8441,0.9214,0.9956,1.082,1.19,1.316,1.457;0.7,0.7698,0.8872,0.9466,0.9969,1.046,1.1,1.151,1.201]  LoadFlowParameters=[1 0 0 0 0]  TsPowergui=0  TsBlock=-1  IterativeModel=Trapezoidal non iterative  IterativeDiscreteModel=Trapezoidal non iterative  BusType=PV  Pref=0  Qref=0  Qmin=-inf  Qmax=inf  PLF=0  QLF=0
  Terminal Load : spsThreePhaseParallelRLCLoadLib/Three-Phase Parallel RLC Load  LConnTagsString=A|B|C  Configuration=Y (grounded)  NominalVoltage=V2_rms  Vabc=[1e3 1e3 1e3]  Vabcp=[1e3 1e3 1e3]  NominalFrequency=50  UnbalancedPower=off  ActivePower=1  InductivePower=0  CapacitivePower=0  Pabc=[10e3 9e3 11e3]  QLabc=[100 90 110]  QCabc=[100 90 110]  Pabcp=[10e3 9e3 11e3]  QLabcp=[100 90 110]  QCabcp=[100 90 110]  Measurements=None  LoadType=constant Z
  Voltage Measurement4 : spsVoltageMeasurementLib/Voltage Measurement  PhasorSimulation=off  OutputType=Complex  PSBequivalent=0
  Voltage Measurement5 : spsVoltageMeasurementLib/Voltage Measurement  PhasorSimulation=off  OutputType=Complex  PSBequivalent=0
  Voltage Measurement6 : spsVoltageMeasurementLib/Voltage Measurement  PhasorSimulation=off  OutputType=Complex  PSBequivalent=0
  abc to Alpha-Beta-Zero : spsabctoAlphaBetaZeroLib/abc to Alpha-Beta-Zero
  mag : Fcn  Expr=sqrt(u(1)^2 + u(2)^2)
  wref6 : Constant
  wref7 : Constant
  A : PMIOPort  Side=Right
  B : PMIOPort  Port=2  Side=Right
  C : PMIOPort  Port=3  Side=Right
  f : Outport  VectorParamsAs1DForOutWhenUnconnected=off
  V : Outport  Port=2  VectorParamsAs1DForOutWhenUnconnected=off
  P : Outport  Port=3  VectorParamsAs1DForOutWhenUnconnected=off
  Theta : Outport  Port=4  VectorParamsAs1DForOutWhenUnconnected=off
  Outport : Outport  Port=5
  I1 : Outport  Port=6  VectorParamsAs1DForOutWhenUnconnected=off
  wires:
  Gain/1 -> f/1
  Positive Sequence Voltage2/1 -> V/1
  wref7/1 -> Subsystem2/2(speed_ref)
  Mux3/1 -> Positive Sequence Voltage2/1
  Synchronous Machine pu Fundamental/1 -> Bus Selector3/1
  [w] -> Gain/1
  [Vq] -> Mux3/1
  [Vd] -> Mux3/2
  [P] -> P/1
  [Theta] -> Theta/1
  Bus Selector3/1 -> [Vq]  "<Stator voltage  vq (pu)>"
  Bus Selector3/2 -> [Vd]  "<Stator voltage  vd (pu)>"
  Bus Selector3/3 -> [P]  "<Output active power   Peo (pu)>"
  Bus Selector3/4 -> [Q]  "<Output reactive power  Qeo (pu)>"
  Bus Selector3/5 -> [Theta]  "<Rotor mechanical angle  theta (deg)>"
  Bus Selector3/6 -> [dw]  "<Rotor speed deviation  dw (pu)>"
  Bus Selector3/7 -> [Ifd]  "<Field current  ifd (pu)>"
  Bus Selector3/8 -> [w]  "<Rotor speed  wm (pu)>"
  Generic Power System Stabilizer/1 -> ST1A Excitation System/4
  [dw] -> Generic Power System Stabilizer/1
  [Ifd] -> ST1A Excitation System/3
  Mux1/1 -> Positive Sequence Voltage1/1
  [Vd] -> Mux1/1
  [Vq] -> Mux1/2
  ST1A Excitation System/1 -> Synchronous Machine pu Fundamental/2
  Positive Sequence Voltage1/1 -> ST1A Excitation System/2
  [w] -> Subsystem2/3(speed)
  Voltage Measurement6/1 -> Mux2/3
  Mux2/1 -> Memory2/1
  Voltage Measurement4/1 -> Mux2/1
  Memory2/1 -> [v_abc_sg]
  Voltage Measurement5/1 -> Mux2/2
  [v_abc_sg] -> Outport/1
  Subsystem2/1(throttle) -> LTI System1/1
  LTI System1/1 -> Synchronous Machine pu Fundamental/1
  Ramp/1 -> Saturation1/1
  Step/1 -> Switch/2
  Constant/1 -> Switch/3
  Mux4/1 -> Memory3/1
  Memory3/1 -> [i_abc_sg]
  Current Measurement/1 -> Mux4/1
  Current Measurement1/1 -> Mux4/2
  Current Measurement2/1 -> Mux4/3
  [i_abc_sg] -> abc to Alpha-Beta-Zero/1
  abc to Alpha-Beta-Zero/1 -> mag/1
  mag/1 -> Gain1/1
  Gain1/1 -> I1/1
  Ramp1/1 -> Saturation2/1
  Saturation2/1 -> Switch/1
  Pset/1 -> Subsystem2/1(P_ref)
  wref6/1 -> ST1A Excitation System/1
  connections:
  Terminal Load/LConn1 -- Current Measurement/LConn1 -- Synchronous Machine pu Fundamental/RConn1 -- Voltage Measurement4/LConn1
  Terminal Load/LConn3 -- Current Measurement2/LConn1 -- Synchronous Machine pu Fundamental/RConn3 -- Voltage Measurement6/LConn1
  Terminal Load/LConn2 -- Synchronous Machine pu Fundamental/RConn2 -- Current Measurement1/LConn1 -- Voltage Measurement5/LConn1
  Voltage Measurement5/LConn2 -- Ground1/LConn1 -- Voltage Measurement6/LConn2 -- Voltage Measurement4/LConn2
  Current Measurement/RConn1 -- A/RConn1
  Current Measurement1/RConn1 -- B/RConn1
  Current Measurement2/RConn1 -- C/RConn1

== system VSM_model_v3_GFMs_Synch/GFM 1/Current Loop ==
  i_s_ref_dq0 : Inport
  v_dq0 : Inport  Port=2
  i_s_dq0 : Inport  Port=3
  w : Inport  Port=4
  Demux : Demux  Outputs=2
  Demux1 : Demux  Outputs=2
  Demux2 : Demux  Outputs=2
  First-Order Filter2 : spsFirstOrderFilterLib/First-Order Filter  Commented=on  FilterType=Lowpass  Tc=25e-3  Ts=0  Initialize=on  Vac_Init=[0, 0, 50]  Vdc_Init=1  PlotResponse=off  FreqRange="[0,  200,  1]"
  First-Order Filter3 : spsFirstOrderFilterLib/First-Order Filter  Commented=on  FilterType=Lowpass  Tc=25e-3  Ts=0  Initialize=on  Vac_Init=[0, 0, 50]  Vdc_Init=0  PlotResponse=off  FreqRange="[0,  200,  1]"
  Gain Corrector : Gain  Gain=Kp_i
  Gain Corrector1 : Gain  Gain=Kp_i
  Integration Time : Gain  Gain=Ki_i / Kp_i
  Integration Time 1 : Gain  Gain=Ki_i / Kp_i
  Integration Time1 : Gain  Gain=1/n
  Integration Time2 : Gain  Gain=1/n
  Integrator : Integrator  InitialCondition=0.0001
  Integrator 1 : Integrator
  Mux : Mux  Inputs=3
  Product : Product  RndMeth=Zero
  Product1 : Product  RndMeth=Zero
  Selector1 : Selector  InputPortWidth=3  IndexOptions=Index vector (dialog)  Indices=[1 2]  OutputSizes=1
  Selector2 : Selector  InputPortWidth=3  IndexOptions=Index vector (dialog)  Indices=[1 2]  OutputSizes=1
  Selector3 : Selector  InputPortWidth=3  IndexOptions=Index vector (dialog)  Indices=[1 2]  OutputSizes=1
  Sum : Sum  Inputs=|+-
  Sum1 : Sum  Inputs=|++
  Sum2 : Sum  Inputs=|+-
  Sum3 : Sum  Inputs=|++
  Sum4 : Sum  Inputs=|++
  Sum5 : Sum  Inputs=++|
  Sum6 : Sum  Inputs=-+|
  Sum7 : Sum  Inputs=++|
  Vm_0* : Constant  Value=0
  Voltage Compensator 1 : Gain  Gain=Kff_v
  Voltage compensator : Gain  Gain=Kff_v
  w*Lf_pu : Gain  Gain=L_f
  v_s_ref_dq0 : Outport  VectorParamsAs1DForOutWhenUnconnected=off
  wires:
  Integration Time2/1 -> Sum4/2
  Integration Time1/1 -> Sum1/2
  Gain Corrector1/1 -> Sum5/2
  Product1/1 -> Sum5/1
  Demux2/1 -> Voltage compensator/1
  Demux1/1 -> Sum/2, Product1/2
  Integrator/1 -> Sum1/1
  Vm_0*/1 -> Mux/3
  Demux1/2 -> Sum6/1, Product/1
  Selector3/1 -> Demux2/1
  i_s_dq0/1 -> Selector2/1
  Selector2/1 -> Demux1/1
  Mux/1 -> v_s_ref_dq0/1
  w/1 -> w*Lf_pu/1
  Gain Corrector/1 -> Sum2/1
  Selector1/1 -> Demux/1
  Demux/2 -> Sum6/2
  Sum4/1 -> Gain Corrector1/1
  Sum2/1 -> Sum3/1
  Sum1/1 -> Gain Corrector/1
  Voltage compensator/1 -> Sum3/2
  Integrator 1/1 -> Sum4/1
  v_dq0/1 -> Selector3/1
  i_s_ref_dq0/1 -> Selector1/1
  w*Lf_pu/1 -> Product/2, Product1/1
  Product/1 -> Sum2/2
  Voltage Compensator 1/1 -> Sum7/1
  Demux2/2 -> Voltage Compensator 1/1
  Sum7/1 -> Mux/2  "Vm_q*"
  Sum3/1 -> Mux/1  "Vm_d*"
  Demux/1 -> Sum/1
  Sum6/1 -> Integration Time2/1, Integration Time 1/1
  Sum5/1 -> Sum7/2
  Integration Time/1 -> Integrator/1
  Integration Time 1/1 -> Integrator 1/1
  Sum/1 -> Integration Time1/1, Integration Time/1

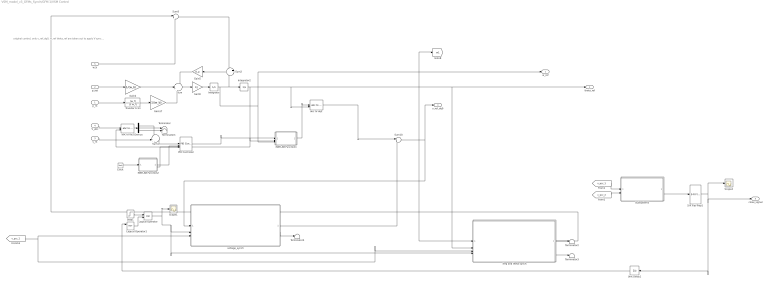
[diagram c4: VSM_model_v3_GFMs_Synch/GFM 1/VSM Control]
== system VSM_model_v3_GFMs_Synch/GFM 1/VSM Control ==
  note: original control, only v_ref_dq0, w_ref theta_ref are taken out to apply V synchronization
  p_m : Inport
  p_set : Inport  Port=2
  v_m : Inport  Port=3
  V_abc : Inport  Port=4
  w_b : Inport  Port=5
  Clock : Clock
  Demux : Demux  Outputs=3
  Gain17 : Gain  Gain=1/(w_b)
  Gain2 : Gain  Gain=1/(w_b)
  Gain5 : Gain  Gain=D_p
  Gain6 : Gain  Gain=1/J
  Integrator : Integrator  InitialCondition=314.1599
  Integrator2 : Integrator
  Logical Operator : Logic  AllPortsSameDT=off  OutDataTypeStr=boolean
  Logical Operator1 : Logic  Operator=NOT  AllPortsSameDT=off  OutDataTypeStr=boolean
  MATLAB Function1 : MATLAB Function  TreatAsAtomicUnit=on
  MATLAB Function2 : MATLAB Function  TreatAsAtomicUnit=on
  PID Controller : slpidlib/PID Controller  Controller=PI  Form=Parallel  TimeDomain=Continuous-time  UseExternalTs=off  SampleTime=-1  IntegratorMethod=Forward Euler  FilterMethod=Forward Euler  ControllerParametersSource=external  P=kp_v_ac  I=ki_v_ac  UseKiTs=off  D=0  UseExternalDerivativeSource=off  N=100  UseFilter=on  TunerSelectOption=Transfer Function Based (PID Tuner App)  InitialConditionSource=internal  InitialConditionForIntegrator=0  InitialConditionForFilter=0  DifferentiatorICPrevScaledInput=0  ExternalReset=none  TrackingMode=off  Kt=1  LimitOutput=off  SatLimitsSource=internal  UpperSaturationLimit=inf  LowerSaturationLimit=-inf  LinearizeAsGain=on  AntiWindupMode=none  Kb=1  LimitIntegrator=off  UpperIntegratorSaturationLimit=inf  LowerIntegratorSaturationLimit=-inf  POutMin=[]  POutMax=[]  IOutMin=[]  IOutMax=[]  DOutMin=[]  DOutMax=[]  NOutMin=[]  NOutMax=[]  SumOutMin=[]  SumOutMax=[]  SaturationOutMin=[]  SaturationOutMax=[]  PParamMin=[]  PParamMax=[]  IParamMin=[]  IParamMax=[]  DParamMin=[]  DParamMax=[]  NParamMin=[]  NParamMax=[]  KbParamMin=[]  KbParamMax=[]  KtParamMin=[]  KtParamMax=[]  KbOutMin=[]  KbOutMax=[]  KtOutMin=[]  KtOutMax=[]  IntegratorOutMin=[]  IntegratorOutMax=[]  FilterOutMin=[]  FilterOutMax=[]  SumI1OutMin=[]  SumI1OutMax=[]  SumI2OutMin=[]  SumI2OutMax=[]  SumI3OutMin=[]  SumI3OutMax=[]  SumI4OutMin=[]  SumI4OutMax=[]  SumDOutMin=[]  SumDOutMax=[]  DifferentiatorOutMin=[]  DifferentiatorOutMax=[]  FilterDiffOutCoefMin=[]  FilterDiffOutCoefMax=[]  ReciprocalOutMin=[]  ReciprocalOutMax=[]  SumDenOutMin=[]  SumDenOutMax=[]  SumNumOutMin=[]  SumNumOutMax=[]  DivideOutMin=[]  DivideOutMax=[]  UdiffTsProdOutMin=[]  UdiffTsProdOutMax=[]  NTsProdOutMin=[]  NTsProdOutMax=[]  UintegralTsProdOutMin=[]  UintegralTsProdOutMax=[]  UngainTsProdOutMin=[]  UngainTsProdOutMax=[]  ClampingZeroOutDataTypeStr=Inherit: Inherit via back propagation  ClampingZeroOutMin=[]  ClampingZeroOutMax=[]  FilterDenConstantOutDataTypeStr=Inherit: Inherit via back propagation  FilterDenConstantOutMin=[]  FilterDenConstantOutMax=[]  PCopyOutDataTypeStr=Inherit: Inherit via back propagation  PCopyOutMin=[]  PCopyOutMax=[]  NCopyOutDataTypeStr=Inherit: Inherit via back propagation  NCopyOutMin=[]  NCopyOutMax=[]  IntegratorContinuousStateAttributes=''  IntegratorStateMustResolveToSignalObject=off  IntegratorRTWStateStorageClass=Auto  FilterContinuousStateAttributes=''  FilterStateMustResolveToSignalObject=off  FilterRTWStateStorageClass=Auto  ParallelPVariant=ExternalParameters  IdealPVariant=Disabled  IVariant=ExternalParameters  DVariant=Disabled  IntegratorVariant=Continuous  SatVariant=Disabled  AWVariant=Passthrough  PCopyVariant=Disabled  TRVariant=Disabled  FdbkBlocksVariant=Forward  IdealPFdbkVariant=Disabled  SatFdbkVariant=Disabled  DerivativeFilterVariant=Disabled  NVariant=Disabled  NCopyVariant=Disabled_SignalSpec  FilterICVariant=Disabled  IntegratorICVariant=InternalICs  ExternalResetVariant=Disabled  TRSumVariant=Passthrough  SumFdbkVariant=Disabled  SumVariant=Sum_PI  TsampFilterVariant=InternalTs  TsampNgainVariant=Passthrough  TsampIntegralVariant=Disabled_SignalSpec  ExternalSaturationOutDataTypeStr=Inherit: Same as second input  DerivativeSourceVariant=Disabled  PreIntVariant=InternalPreInt
  S-R Flip-Flop1 : simulink_extras/Flip Flops/S-R Flip-Flop  initial_condition=0
  Scope1 : Scope
  Scope4 : Scope
  Step1 : Step  Time=46.5  SampleTime=0
  Subsystem5 : Subsystem
  Sum : Sum  Inputs=+|+|-
  Sum1 : Sum  Inputs=-+|
  Sum10 : Sum  Inputs=|++
  Sum2 : Sum  Inputs=+|-
  Sum5 : Sum  Inputs=|++
  Terminator{,1..4} (5 alike) : Terminator
  Transfer Fcn1 : TransferFcn  Numerator=[w_f]  Denominator=[1 w_f]
  Unit Delay1 : UnitDelay  SampleTime=-1  HasFrameUpgradeWarning=on
  abc to dq1 : spsabctodq0Lib/abc to dq0  Alignment=90 degrees behind phase A axis
  abc to dq2 : spsabctodq0Lib/abc to dq0  Alignment=90 degrees behind phase A axis
  freq and theta synch : Subsystem
  voltage_synch : Subsystem
  w_ref : Outport  VectorParamsAs1DForOutWhenUnconnected=off
  theta_ref : Outport  Port=2  VectorParamsAs1DForOutWhenUnconnected=off
  v_ref_dq0 : Outport  Port=3  VectorParamsAs1DForOutWhenUnconnected=off
  close_signal : Outport  Port=4
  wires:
  v_m/1 -> Sum1/2
  Sum1/1 -> PID Controller/1
  abc to dq1/1 -> Demux/1
  V_abc/1 -> abc to dq1/1
  Demux/1 -> Sum1/1
  Demux/2 -> Terminator/1
  Demux/3 -> Terminator1/1
  Transfer Fcn1/1 -> Gain17/1
  Sum2/1 -> Gain5/1
  Sum/1 -> Gain6/1
  Gain2/1 -> Sum/2
  Gain6/1 -> Integrator/1
  Gain17/1 -> Sum/3
  Gain5/1 -> Sum/1
  p_m/1 -> Transfer Fcn1/1
  p_set/1 -> Gain2/1
  PID Controller/1 -> MATLAB Function1/1(M_fi_f)
  MATLAB Function1/1(e) -> abc to dq2/1
  abc to dq2/1 -> Sum10/1
  Sum10/1 -> voltage_synch/1(In1), v_ref_dq0/1
  Integrator2/1 -> abc to dq1/2, MATLAB Function1/2(theta), abc to dq2/2, freq and theta synch/2(In2), theta_ref/1
  [v_pcc_1] -> voltage_synch/3(abc), freq and theta synch/3(abc)
  Integrator/1 -> Integrator2/1, Sum2/2, freq and theta synch/1(In1), [w1], w_ref/1, MATLAB Function1/3(w)
  w_b/1 -> Sum5/2
  Sum5/1 -> Sum2/1
  freq and theta synch/1(Out1) -> Sum5/1
  voltage_synch/1(delta_v) -> Sum10/2
  Logical Operator/1 -> freq and theta synch/4(sync), voltage_synch/2(sync), Scope1/1
  Logical Operator1/1 -> Logical Operator/2
  Unit Delay1/1 -> Logical Operator1/1
  Step1/1 -> Logical Operator/1
  MATLAB Function2/1(Kp) -> PID Controller/2
  Clock/1 -> MATLAB Function2/1(t)
  MATLAB Function2/2(Ki) -> PID Controller/3
  [v_pcc_2] -> Subsystem5/2(Vpcc_2)
  [v_pcc_1] -> Subsystem5/1(Vpcc_1)
  S-R Flip-Flop1/1 -> Scope4/1, close_signal/1, Unit Delay1/1
  Subsystem5/1(close_signal) -> S-R Flip-Flop1/1
  freq and theta synch/2(err_theta) -> Terminator2/1
  freq and theta synch/3(err_w) -> Terminator3/1
  voltage_synch/2(err_V) -> Terminator4/1
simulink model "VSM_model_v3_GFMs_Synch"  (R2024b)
settings: Solver=ode23tb  StartTime=0.0  StopTime=Tend  FixedStep=T_s  RelTol=1e-3  EnableMultiTasking=on
PostLoadFcn:
  | Tcontrol=20e-6;
InitFcn:
  | Tcontrol=20e-6;
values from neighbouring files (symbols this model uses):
  C_4 = 0.1670*C_b    (= 1.00487241952e-06)    [VSM.m]    (also in VSM_CSIRO.m)
  C_6 = 0.2835*C_b    (= 1.70587623314e-06)    [VSM.m]    (also in VSM_CSIRO.m)
  C_8 = 0.2275*C_b    (= 1.36891302659e-06)    [VSM.m]    (also in VSM_CSIRO.m)
  C_dc = 0.008*(n)    (= 1.6)    [VSM.m]    (also in VSM_CSIRO.m)
  C_f = n*300*10^-6    (= 0.06)    [VSM.m]    (also in VSM_CSIRO.m)
  C_f_gfl = (n_gfl) * Cf_unit_gfl    (= 0.00350140874802)    [DER_param.m]
  D_p = (1/(m_p*w_b))    (= 101321.183642)    [VSM.m]    (also in VSM_CSIRO.m)
  droop_percentage = 5    [VSM.m]    (also in VSM_CSIRO.m = 1)
  I_b_dc = S_b/Vdc_n    [VSM.m]    (also in VSM_CSIRO.m)
  I_b_LV_peak = I_b_LV * sqrt(2)    [VSM.m]
  I_b_SG_peak = I_b_SG * sqrt(2)    [VSM.m]
  i_ll = -1.15*(S_b/Vdc_n)-i_loss_dc    [VSM.m]    (also in VSM_CSIRO.m)
  i_ul = 1.15*(S_b/Vdc_n)+i_loss_dc    [VSM.m]    (also in VSM_CSIRO.m)
  J = D_p*tau_f    (= 2026.42367285)    [VSM.m]    (also in VSM_CSIRO.m)
  k_dc = eta_1/(Vdc_n*m_p)    [VSM.m]    (also in VSM_CSIRO.m)
  K_p = (1/Vdc_n)    [VSM.m]    (also in VSM_CSIRO.m)
  K_r = 1/R_dc    [VSM.m]    (also in VSM_CSIRO.m)
  Kff_i = 1    [VSM.m]    (also in VSM_CSIRO.m)
  Kff_v = 1    [VSM.m]    (also in VSM_CSIRO.m)
  Ki_i = (1/n)*1.19    (= 0.00595)    [VSM.m]    (also in VSM_CSIRO.m)
  Ki_i_gfl = (1/n_gfl) * Ki_i_unit_gfl    (= 0.571198664289)    [DER_param.m]
  Ki_v = (n)*1.161022    (= 232.2044)    [VSM.m]    (also in VSM_CSIRO.m)
  ki_v_ac = 4*5.2500e-04    (= 0.0021)    [VSM.m]    (also in VSM_CSIRO.m)
  Kp_i = 0.738891    [VSM.m]    (also in VSM_CSIRO.m)
  Kp_i_gfl = (1/n_gfl) * Kp_i_unit_gfl    (= 0.00909090909091)    [DER_param.m]
  Kp_v = 0.52    [VSM.m]    (also in VSM_CSIRO.m)
  kp_v_ac = 0.001    [VSM.m]    (also in VSM_CSIRO.m)
  L1_f_gfl = (1/n_gfl) * L1_unit_gfl    (= 1.44686311902e-05)    [DER_param.m]
  L1_pu = 1*0.0186/m    (= 0.000186)    [VSM.m]    (also in VSM_CSIRO.m)
  L1_pu_gfl = 0.03    [DER_param.m]
  L2_f_gfl = (1/n_gfl) * L2_unit_gfl    (= 2.89372623803e-06)    [DER_param.m]
  L2_pu_gfl = 0.03    [DER_param.m]
  L_45 = L_lines(2)    [VSM.m]    (also in VSM_CSIRO.m)
  L_56 = L_lines(3)    [VSM.m]    (also in VSM_CSIRO.m)
  L_67 = L_lines(5)    [VSM.m]    (also in VSM_CSIRO.m)
  L_78 = L_lines(6)    [VSM.m]    (also in VSM_CSIRO.m)
  L_89 = L_lines(8)    [VSM.m]    (also in VSM_CSIRO.m)
  L_94 = L_lines(9)    [VSM.m]    (also in VSM_CSIRO.m)
  L_f = (1/n)*200*10^-6    (= 1e-06)    [VSM.m]    (also in VSM_CSIRO.m)
  Lg = (X_BY_R_gfl * Rg) / wn_gfl    [DER_param.m]    (also in initialcondition_gfm_Pooyan.m = X_BY_R*Rg/(wn); initialcondition_Pooyan.m = X_BY_R*Rg/(wn))
  n = 200    [VSM.m]    (also in VSM_CSIRO.m)
  Pgen_MW_gfl = 20    [DER_param.m]
  ps = base/3    (= 0.75)    [VSM.m]    (also in VSM_CSIRO.m)
  R1_f_gfl = (1/n_gfl) * R1_unit_gfl    (= 0.000909090909091)    [DER_param.m]
  R1_pu = 1*0.00734/m    (= 7.34e-05)    [VSM.m]    (also in VSM_CSIRO.m)
  R1_pu_gfl = 0.005    [DER_param.m]
  R2_f_gfl = (1/n_gfl) * R2_unit_gfl    (= 0.000181818181818)    [DER_param.m]
  R2_pu_gfl = 0.005    [DER_param.m]
  R_45 = R_lines(2)    [VSM.m]    (also in VSM_CSIRO.m)
  R_56 = R_lines(3)    [VSM.m]    (also in VSM_CSIRO.m)
  R_67 = R_lines(5)    [VSM.m]    (also in VSM_CSIRO.m)
  R_78 = R_lines(6)    [VSM.m]    (also in VSM_CSIRO.m)
  R_89 = R_lines(8)    [VSM.m]    (also in VSM_CSIRO.m)
  R_94 = R_lines(9)    [VSM.m]    (also in VSM_CSIRO.m)
  R_base_gfl = (3 * Vg_gfl^2) / (2 * Pn_gfl)    [DER_param.m]
  R_dc = (Vdc_n/(0.05*(S_b)/Vdc_n))    [VSM.m]    (also in VSM_CSIRO.m)
  R_f = 0.001/n    (= 5e-06)    [VSM.m]    (also in VSM_CSIRO.m)
  Rg = (3 * Vg_gfl^2) / (2 * SCR_gfl * sqrt(1 + X_BY_R_gfl^2) * Pn_gfl)    [DER_param.m]    (also in initialcondition_gfm_Pooyan.m = (3*Vg^2)/(2*SCR*sqrt(1+X_BY_R^2)*Pn); initialcondition_Pooyan.m = (3*Vg^2)/(2*SCR*sqrt(1+X_BY_R^2)*Pn))
  S_b = 100*(10^6)    (= 100000000)    [VSM.m]    (also in VSM_CSIRO.m)
  S_bt = S_b    (= 100000000)    [VSM.m]    (also in VSM_CSIRO.m)
  S_bt_gfl = S_b_gfl    (= 22000000)    [DER_param.m]
  T_en = T_load-0.5    (= 24.5)    [VSM.m]    (also in VSM_CSIRO.m = 44.5)
  T_s = 1e-4    (= 0.0001)    [VSM.m]    (also in VSM_CSIRO.m)
  tau_dc = 0.05    [VSM.m]    (also in VSM_CSIRO.m)
  tau_g = 5    [VSM.m]    (also in VSM_CSIRO.m)
  Tend = 90    [VSM.m]    (also in VSM_CSIRO.m = 50)
  ts_DER = 15    [DER_param.m]
  V1_rms = 1000    [VSM.m]    (also in VSM_CSIRO.m)
  V1_rms_gfl = 1000    [DER_param.m]
  V1_rms_tx1_gfl = 1000    [DER_param.m]
  V2_rms = 13800    [VSM.m]    (also in VSM_CSIRO.m)
  V2_rms_tx1_gfl = 13800    [DER_param.m]
  V_b = 230*(10^3)    (= 230000)    [VSM.m]    (also in VSM_CSIRO.m)
  V_m = sqrt(2/3)*V1_rms    [VSM.m]    (also in VSM_CSIRO.m)
  V_m_gfl = sqrt(2/3)*V1_rms_gfl    [DER_param.m]
  V_sg_p = sqrt(2/3)*V2_rms    [VSM.m]
  Vdc_n = 3*V_m    [VSM.m]    (also in VSM_CSIRO.m)
  Vdc_n_gfl = 2300    [DER_param.m]
  w_b = 2*pi*f_b    (= 314.159265359)    [VSM.m]    (also in VSM_CSIRO.m)
  w_b_gfl = 2*pi*f_b_gfl    (= 314.159265359)    [DER_param.m]
  w_f = 2*pi*5    (= 31.4159265359)    [VSM.m]    (also in VSM_CSIRO.m)
undefined symbols (not defined in the file or in its folder): D1, Delta, DiscIntNeverNeededParam, dspblkCoreblockFVToolHelper, gcbh, i_dc, magnitude
libraries: spsSeriesRLCBranchLib x82, spsabctodq0Lib x40, slpidlib x36, spsVoltageMeasurementLib x32, spsThreePhaseVIMeasurementLib x31, spsThreePhaseBreakerLib x26, spsGroundLib x22, spsCurrentMeasurementLib x20, spsPLL3phLib x14, spsThreePhaseTransformerTwoWindingsLib x14, simulink x13, spsThreePhaseSeriesRLCBranchLib x10
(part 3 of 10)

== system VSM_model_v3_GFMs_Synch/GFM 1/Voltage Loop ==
  v_ref_dq0 : Inport
  v_dq0 : Inport  Port=2
  i_dq0 : Inport  Port=3
  w : Inport  Port=4
  Current Compensator : Gain  Gain=Kff_i
  Current Compensator1 : Gain  Gain=Kff_i
  Damping (d) : Gain  Gain=Kp_v
  Damping (q) : Gain  Gain=Kp_v
  Demux : Demux  Outputs=2
  Demux1 : Demux  Outputs=2
  Demux2 : Demux  Outputs=2
  Eg_d * (wCf) : Product  RndMeth=Zero
  "Eg_q * (wCf) " : Product  RndMeth=Zero
  Filter capacitance : Gain  Gain=C_f
  Integration Time : Gain  Gain=Ki_v / Kp_v
  Integration Time1 : Gain  Gain=Ki_v / Kp_v
  Integration Time2 : Gain  Gain=n
  Integration Time3 : Gain  Gain=n
  Integrator : Integrator
  Integrator1 : Integrator
  Is_0* : Constant  Value=0
  Mux : Mux  Inputs=3
  Selector : Selector  InputPortWidth=3  IndexOptions=Index vector (dialog)  Indices=[1 2]  OutputSizes=1
  Selector1 : Selector  InputPortWidth=3  IndexOptions=Index vector (dialog)  Indices=[1 2]  OutputSizes=1
  Selector2 : Selector  InputPortWidth=3  IndexOptions=Index vector (dialog)  Indices=[1 2]  OutputSizes=1
  Sum : Sum  Inputs=|+-
  Sum1 : Sum  Inputs=|++
  Sum2 : Sum  Inputs=|+-
  Sum3 : Sum  Inputs=|++
  Sum4 : Sum  Inputs=|++
  Sum5 : Sum  Inputs=++|
  Sum6 : Sum  Inputs=-+|
  Sum7 : Sum  Inputs=++|
  i_s_ref_dq0 : Outport  VectorParamsAs1DForOutWhenUnconnected=off
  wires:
  Integration Time3/1 -> Sum4/2
  Integration Time2/1 -> Sum1/2
  Sum/1 -> Integration Time2/1, Integration Time/1
  Mux/1 -> i_s_ref_dq0/1
  Selector2/1 -> Demux2/1
  Selector1/1 -> Demux/1
  Selector/1 -> Demux1/1
  Damping (q)/1 -> Sum5/2  "Is_q\""
  v_dq0/1 -> Selector/1
  Sum3/1 -> Mux/1  "Is_d*"
  Sum4/1 -> Damping (q)/1
  Integration Time/1 -> Integrator/1
  Integrator/1 -> Sum1/1
  Sum1/1 -> Damping (d)/1
  Sum5/1 -> Sum7/2  "Is_q'"
  i_dq0/1 -> Selector2/1
  Damping (d)/1 -> Sum2/1  "Is_d\""
  Filter capacitance/1 -> Eg_d * (wCf)/2, "Eg_q * (wCf) "/2
  Demux1/2 -> Sum6/1, "Eg_q * (wCf) "/1  "Eg_q"
  "Eg_q * (wCf) "/1 -> Sum2/2  "Is_f"
  Current Compensator1/1 -> Sum7/1
  Demux1/1 -> Sum/2, Eg_d * (wCf)/1  "Eg_d"
  Current Compensator/1 -> Sum3/2
  Sum2/1 -> Sum3/1  "Is_d'"
  Demux2/1 -> Current Compensator/1  "Ig_d"
  Sum6/1 -> Integration Time1/1, Integration Time3/1
  Demux/1 -> Sum/1  "Eg_d*"
  Demux2/2 -> Current Compensator1/1  "Ig_q"
  Sum7/1 -> Mux/2  "Is_q*"
  Eg_d * (wCf)/1 -> Sum5/1  "Is_f"
  v_ref_dq0/1 -> Selector1/1
  Demux/2 -> Sum6/2  "Eg_q*"
  Integrator1/1 -> Sum4/1
  Integration Time1/1 -> Integrator1/1
  w/1 -> Filter capacitance/1
  Is_0*/1 -> Mux/3

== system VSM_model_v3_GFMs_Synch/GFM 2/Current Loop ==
  i_s_ref_dq0 : Inport
  v_dq0 : Inport  Port=2
  i_s_dq0 : Inport  Port=3
  w : Inport  Port=4
  Demux : Demux  Outputs=2
  Demux1 : Demux  Outputs=2
  Demux2 : Demux  Outputs=2
  Discrete-Time Integrator1 : DiscreteIntegrator  ExternalReset=level  SampleTime=-1  ICPrevOutput=DiscIntNeverNeededParam  ICPrevScaledInput=DiscIntNeverNeededParam
  Discrete-Time Integrator2 : DiscreteIntegrator  ExternalReset=level  SampleTime=-1  ICPrevOutput=DiscIntNeverNeededParam  ICPrevScaledInput=DiscIntNeverNeededParam
  First-Order Filter2 : spsFirstOrderFilterLib/First-Order Filter  Commented=on  FilterType=Lowpass  Tc=25e-3  Ts=0  Initialize=on  Vac_Init=[0, 0, 50]  Vdc_Init=1  PlotResponse=off  FreqRange="[0,  200,  1]"
  First-Order Filter3 : spsFirstOrderFilterLib/First-Order Filter  Commented=on  FilterType=Lowpass  Tc=25e-3  Ts=0  Initialize=on  Vac_Init=[0, 0, 50]  Vdc_Init=0  PlotResponse=off  FreqRange="[0,  200,  1]"
  Gain Corrector : Gain  Gain=Kp_i
  Gain Corrector1 : Gain  Gain=Kp_i
  Integration Time : Gain  Gain=Ki_i / Kp_i
  Integration Time 1 : Gain  Gain=Ki_i / Kp_i
  Integration Time1 : Gain  Gain=1/n
  Integration Time2 : Gain  Gain=1/n
  Integrator : Integrator  Commented=on  InitialCondition=0.0001
  Integrator 1 : Integrator  Commented=on
  Mux : Mux  Inputs=3
  Product : Product  RndMeth=Zero
  Product1 : Product  RndMeth=Zero
  Selector1 : Selector  InputPortWidth=3  IndexOptions=Index vector (dialog)  Indices=[1 2]  OutputSizes=1
  Selector2 : Selector  InputPortWidth=3  IndexOptions=Index vector (dialog)  Indices=[1 2]  OutputSizes=1
  Selector3 : Selector  InputPortWidth=3  IndexOptions=Index vector (dialog)  Indices=[1 2]  OutputSizes=1
  Sum : Sum  Inputs=|+-
  Sum1 : Sum  Inputs=|++
  Sum2 : Sum  Inputs=|+-
  Sum3 : Sum  Inputs=|++
  Sum4 : Sum  Inputs=|++
  Sum5 : Sum  Inputs=++|
  Sum6 : Sum  Inputs=-+|
  Sum7 : Sum  Inputs=++|
  Vm_0* : Constant  Value=0
  Voltage Compensator 1 : Gain  Gain=Kff_v
  Voltage compensator : Gain  Gain=Kff_v
  w*Lf_pu : Gain  Gain=L_f
  v_s_ref_dq0 : Outport  VectorParamsAs1DForOutWhenUnconnected=off
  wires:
  Integration Time2/1 -> Sum4/2
  Integration Time1/1 -> Sum1/2
  Gain Corrector1/1 -> Sum5/2
  Product1/1 -> Sum5/1
  Demux2/1 -> Voltage compensator/1
  Demux1/1 -> Sum/2, Product1/2
  Vm_0*/1 -> Mux/3
  Demux1/2 -> Sum6/1, Product/1
  Selector3/1 -> Demux2/1
  i_s_dq0/1 -> Selector2/1
  Selector2/1 -> Demux1/1
  Mux/1 -> v_s_ref_dq0/1
  w/1 -> w*Lf_pu/1
  Gain Corrector/1 -> Sum2/1
  Selector1/1 -> Demux/1
  Demux/2 -> Sum6/2
  Sum4/1 -> Gain Corrector1/1
  Sum2/1 -> Sum3/1
  Sum1/1 -> Gain Corrector/1
  Voltage compensator/1 -> Sum3/2
  v_dq0/1 -> Selector3/1
  i_s_ref_dq0/1 -> Selector1/1
  w*Lf_pu/1 -> Product/2, Product1/1
  Product/1 -> Sum2/2
  Voltage Compensator 1/1 -> Sum7/1
  Demux2/2 -> Voltage Compensator 1/1
  Sum7/1 -> Mux/2  "Vm_q*"
  Sum3/1 -> Mux/1  "Vm_d*"
  Demux/1 -> Sum/1
  Sum6/1 -> Integration Time2/1, Integration Time 1/1
  Sum5/1 -> Sum7/2
  Sum/1 -> Integration Time1/1, Integration Time/1
  Integration Time/1 -> Discrete-Time Integrator2/1
  [rst] -> Discrete-Time Integrator2/2
  Discrete-Time Integrator2/1 -> Sum1/1
  Integration Time 1/1 -> Discrete-Time Integrator1/1
  [rst] -> Discrete-Time Integrator1/2
  Discrete-Time Integrator1/1 -> Sum4/1

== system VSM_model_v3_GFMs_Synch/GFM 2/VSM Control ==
  p_m : Inport
  p_set : Inport  Port=2
  v_m : Inport  Port=3
  V_abc : Inport  Port=4
  w_b : Inport  Port=5
  Clock : Clock
  Demux : Demux  Outputs=3
  Discrete Transfer Fcn : DiscreteTransferFcn  LoadFcn=dspblkCoreblockFVToolHelper(gcbh,'load');  Numerator=[0.0015683,0.0015683]  Denominator=[1,-0.99686]
  Discrete-Time Integrator : DiscreteIntegrator  ExternalReset=level  SampleTime=-1  ICPrevOutput=DiscIntNeverNeededParam  ICPrevScaledInput=DiscIntNeverNeededParam
  Discrete-Time Integrator1 : DiscreteIntegrator  ExternalReset=level  SampleTime=-1  ICPrevOutput=DiscIntNeverNeededParam  ICPrevScaledInput=DiscIntNeverNeededParam
  Gain17 : Gain  Gain=1/(w_b)
  Gain2 : Gain  Gain=1/(w_b)
  Gain5 : Gain  Gain=D_p
  Gain6 : Gain  Gain=1/J
  Integrator : Integrator  Commented=on  InitialCondition=314.1599
  Integrator2 : Integrator  Commented=on
  MATLAB Function : MATLAB Function  TreatAsAtomicUnit=on
  MATLAB Function1 : MATLAB Function  TreatAsAtomicUnit=on
  PID Controller : slpidlib/PID Controller  Commented=on  Controller=PI  Form=Parallel  TimeDomain=Continuous-time  UseExternalTs=off  SampleTime=-1  IntegratorMethod=Forward Euler  FilterMethod=Forward Euler  ControllerParametersSource=external  P=kp_v_ac  I=ki_v_ac  UseKiTs=off  D=0  UseExternalDerivativeSource=off  N=100  UseFilter=on  TunerSelectOption=Transfer Function Based (PID Tuner App)  InitialConditionSource=internal  InitialConditionForIntegrator=0  InitialConditionForFilter=0  DifferentiatorICPrevScaledInput=0  ExternalReset=none  TrackingMode=off  Kt=1  LimitOutput=off  SatLimitsSource=internal  UpperSaturationLimit=inf  LowerSaturationLimit=-inf  LinearizeAsGain=on  AntiWindupMode=none  Kb=1  LimitIntegrator=off  UpperIntegratorSaturationLimit=inf  LowerIntegratorSaturationLimit=-inf  POutMin=[]  POutMax=[]  IOutMin=[]  IOutMax=[]  DOutMin=[]  DOutMax=[]  NOutMin=[]  NOutMax=[]  SumOutMin=[]  SumOutMax=[]  SaturationOutMin=[]  SaturationOutMax=[]  PParamMin=[]  PParamMax=[]  IParamMin=[]  IParamMax=[]  DParamMin=[]  DParamMax=[]  NParamMin=[]  NParamMax=[]  KbParamMin=[]  KbParamMax=[]  KtParamMin=[]  KtParamMax=[]  KbOutMin=[]  KbOutMax=[]  KtOutMin=[]  KtOutMax=[]  IntegratorOutMin=[]  IntegratorOutMax=[]  FilterOutMin=[]  FilterOutMax=[]  SumI1OutMin=[]  SumI1OutMax=[]  SumI2OutMin=[]  SumI2OutMax=[]  SumI3OutMin=[]  SumI3OutMax=[]  SumI4OutMin=[]  SumI4OutMax=[]  SumDOutMin=[]  SumDOutMax=[]  DifferentiatorOutMin=[]  DifferentiatorOutMax=[]  FilterDiffOutCoefMin=[]  FilterDiffOutCoefMax=[]  ReciprocalOutMin=[]  ReciprocalOutMax=[]  SumDenOutMin=[]  SumDenOutMax=[]  SumNumOutMin=[]  SumNumOutMax=[]  DivideOutMin=[]  DivideOutMax=[]  UdiffTsProdOutMin=[]  UdiffTsProdOutMax=[]  NTsProdOutMin=[]  NTsProdOutMax=[]  UintegralTsProdOutMin=[]  UintegralTsProdOutMax=[]  UngainTsProdOutMin=[]  UngainTsProdOutMax=[]  ClampingZeroOutDataTypeStr=Inherit: Inherit via back propagation  ClampingZeroOutMin=[]  ClampingZeroOutMax=[]  FilterDenConstantOutDataTypeStr=Inherit: Inherit via back propagation  FilterDenConstantOutMin=[]  FilterDenConstantOutMax=[]  PCopyOutDataTypeStr=Inherit: Inherit via back propagation  PCopyOutMin=[]  PCopyOutMax=[]  NCopyOutDataTypeStr=Inherit: Inherit via back propagation  NCopyOutMin=[]  NCopyOutMax=[]  IntegratorContinuousStateAttributes=''  IntegratorStateMustResolveToSignalObject=off  IntegratorRTWStateStorageClass=Auto  FilterContinuousStateAttributes=''  FilterStateMustResolveToSignalObject=off  FilterRTWStateStorageClass=Auto  ParallelPVariant=ExternalParameters  IdealPVariant=Disabled  IVariant=ExternalParameters  DVariant=Disabled  IntegratorVariant=Continuous  SatVariant=Disabled  AWVariant=Passthrough  PCopyVariant=Disabled  TRVariant=Disabled  FdbkBlocksVariant=Forward  IdealPFdbkVariant=Disabled  SatFdbkVariant=Disabled  DerivativeFilterVariant=Disabled  NVariant=Disabled  NCopyVariant=Disabled_SignalSpec  FilterICVariant=Disabled  IntegratorICVariant=InternalICs  ExternalResetVariant=Disabled  TRSumVariant=Passthrough  SumFdbkVariant=Disabled  SumVariant=Sum_PI  TsampFilterVariant=InternalTs  TsampNgainVariant=Passthrough  TsampIntegralVariant=Disabled_SignalSpec  ExternalSaturationOutDataTypeStr=Inherit: Same as second input  DerivativeSourceVariant=Disabled  PreIntVariant=InternalPreInt
  PID Controller1 : slpidlib/PID Controller  Controller=PI  Form=Parallel  TimeDomain=Discrete-time  UseExternalTs=off  SampleTime=-1  IntegratorMethod=Forward Euler  FilterMethod=Forward Euler  ControllerParametersSource=external  P=kp_v_ac  I=ki_v_ac  UseKiTs=off  D=0  UseExternalDerivativeSource=off  N=100  UseFilter=on  TunerSelectOption=Transfer Function Based (PID Tuner App)  InitialConditionSource=internal  InitialConditionForIntegrator=0  InitialConditionForFilter=0  DifferentiatorICPrevScaledInput=0  ExternalReset=level  TrackingMode=off  Kt=1  LimitOutput=off  SatLimitsSource=internal  UpperSaturationLimit=inf  LowerSaturationLimit=-inf  LinearizeAsGain=on  AntiWindupMode=none  Kb=1  LimitIntegrator=off  UpperIntegratorSaturationLimit=inf  LowerIntegratorSaturationLimit=-inf  POutMin=[]  POutMax=[]  IOutMin=[]  IOutMax=[]  DOutMin=[]  DOutMax=[]  NOutMin=[]  NOutMax=[]  SumOutMin=[]  SumOutMax=[]  SaturationOutMin=[]  SaturationOutMax=[]  PParamMin=[]  PParamMax=[]  IParamMin=[]  IParamMax=[]  DParamMin=[]  DParamMax=[]  NParamMin=[]  NParamMax=[]  KbParamMin=[]  KbParamMax=[]  KtParamMin=[]  KtParamMax=[]  KbOutMin=[]  KbOutMax=[]  KtOutMin=[]  KtOutMax=[]  IntegratorOutMin=[]  IntegratorOutMax=[]  FilterOutMin=[]  FilterOutMax=[]  SumI1OutMin=[]  SumI1OutMax=[]  SumI2OutMin=[]  SumI2OutMax=[]  SumI3OutMin=[]  SumI3OutMax=[]  SumI4OutMin=[]  SumI4OutMax=[]  SumDOutMin=[]  SumDOutMax=[]  DifferentiatorOutMin=[]  DifferentiatorOutMax=[]  FilterDiffOutCoefMin=[]  FilterDiffOutCoefMax=[]  ReciprocalOutMin=[]  ReciprocalOutMax=[]  SumDenOutMin=[]  SumDenOutMax=[]  SumNumOutMin=[]  SumNumOutMax=[]  DivideOutMin=[]  DivideOutMax=[]  UdiffTsProdOutMin=[]  UdiffTsProdOutMax=[]  NTsProdOutMin=[]  NTsProdOutMax=[]  UintegralTsProdOutMin=[]  UintegralTsProdOutMax=[]  UngainTsProdOutMin=[]  UngainTsProdOutMax=[]  ClampingZeroOutDataTypeStr=Inherit: Inherit via back propagation  ClampingZeroOutMin=[]  ClampingZeroOutMax=[]  FilterDenConstantOutDataTypeStr=Inherit: Inherit via back propagation  FilterDenConstantOutMin=[]  FilterDenConstantOutMax=[]  PCopyOutDataTypeStr=Inherit: Inherit via back propagation  PCopyOutMin=[]  PCopyOutMax=[]  NCopyOutDataTypeStr=Inherit: Inherit via back propagation  NCopyOutMin=[]  NCopyOutMax=[]  IntegratorContinuousStateAttributes=''  IntegratorStateMustResolveToSignalObject=off  IntegratorRTWStateStorageClass=Auto  FilterContinuousStateAttributes=''  FilterStateMustResolveToSignalObject=off  FilterRTWStateStorageClass=Auto  ParallelPVariant=ExternalParameters  IdealPVariant=Disabled  IVariant=ExternalParameters  DVariant=Disabled  IntegratorVariant=Discrete  SatVariant=Disabled  AWVariant=Passthrough  PCopyVariant=Disabled  TRVariant=Disabled  FdbkBlocksVariant=Forward  IdealPFdbkVariant=Disabled  SatFdbkVariant=Disabled  DerivativeFilterVariant=Disabled  NVariant=Disabled  NCopyVariant=Disabled_SignalSpec  FilterICVariant=Disabled  IntegratorICVariant=InternalICs  ExternalResetVariant=ExternalReset  TRSumVariant=Passthrough  SumFdbkVariant=Disabled  SumVariant=Sum_PI  TsampFilterVariant=InternalTs  TsampNgainVariant=Passthrough  TsampIntegralVariant=Disabled_SignalSpec  ExternalSaturationOutDataTypeStr=Inherit: Same as second input  DerivativeSourceVariant=Disabled  PreIntVariant=InternalPreInt
  Subsystem : Subsystem  Commented=on
  Sum : Sum  Inputs=+|+|-
  Sum1 : Sum  Inputs=-+|
  Sum10 : Sum  Commented=on  Inputs=|++
  Sum2 : Sum  Inputs=+|-
  Sum3 : Sum  Commented=on  Inputs=|++
  Terminator : Terminator
  Terminator1 : Terminator
  Terminator2 : Terminator
  Transfer Fcn1 : TransferFcn  Commented=on  Numerator=[w_f]  Denominator=[1 w_f]
  abc to dq1 : spsabctodq0Lib/abc to dq0  Alignment=90 degrees behind phase A axis
  abc to dq2 : spsabctodq0Lib/abc to dq0  Alignment=90 degrees behind phase A axis
  w_ref : Outport  VectorParamsAs1DForOutWhenUnconnected=off
  theta_ref : Outport  Port=2  VectorParamsAs1DForOutWhenUnconnected=off
  v_ref_dq0 : Outport  Port=3  VectorParamsAs1DForOutWhenUnconnected=off
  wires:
  v_m/1 -> Sum1/2
  abc to dq1/1 -> Demux/1
  V_abc/1 -> abc to dq1/1
  Demux/1 -> Sum1/1
  Demux/2 -> Terminator/1
  Demux/3 -> Terminator1/1
  Sum2/1 -> Gain5/1
  Sum/1 -> Gain6/1
  Gain2/1 -> Sum/2
  Gain17/1 -> Sum/3
  Gain5/1 -> Sum/1
  MATLAB Function1/1(e) -> abc to dq2/1
  p_set/1 -> Gain2/1
  Clock/1 -> MATLAB Function/1(t)
  [rst] -> Discrete-Time Integrator1/2, Discrete-Time Integrator/2
  Gain6/1 -> Discrete-Time Integrator/1
  Discrete-Time Integrator/1 -> [w_ref], w_ref/1, MATLAB Function1/3(w), Discrete-Time Integrator1/1, Sum2/2
  Discrete-Time Integrator1/1 -> theta_ref/1, [theta_ref], abc to dq2/2, abc to dq1/2, MATLAB Function1/2(theta)
  MATLAB Function/1(Kp) -> PID Controller1/2
  MATLAB Function/2(Ki) -> PID Controller1/3
  Sum1/1 -> PID Controller1/1
  PID Controller1/1 -> MATLAB Function1/1(M_fi_f)
  [rst] -> PID Controller1/4
  p_m/1 -> Discrete Transfer Fcn/1
  Discrete Transfer Fcn/1 -> Gain17/1
  Subsystem/2(delta_v) -> Sum10/2
  Subsystem/4(close_signal) -> [SG_z12]
  [v_ref_dq0] -> Subsystem/3(In3)
  [w_ref] -> Subsystem/1(In1)
  [theta_ref] -> Subsystem/2(In2)
  Subsystem/3(!Q) -> Terminator2/1
  Sum10/1 -> [v_ref_dq0]
  w_b/1 -> Sum2/1
  abc to dq2/1 -> v_ref_dq0/1

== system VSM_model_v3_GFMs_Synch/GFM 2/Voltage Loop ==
  v_ref_dq0 : Inport
  v_dq0 : Inport  Port=2
  i_dq0 : Inport  Port=3
  w : Inport  Port=4
  Current Compensator : Gain  Gain=Kff_i
  Current Compensator1 : Gain  Gain=Kff_i
  Damping (d) : Gain  Gain=Kp_v
  Damping (q) : Gain  Gain=Kp_v
  Demux : Demux  Outputs=2
  Demux1 : Demux  Outputs=2
  Demux2 : Demux  Outputs=2
  Discrete-Time Integrator1 : DiscreteIntegrator  ExternalReset=level  SampleTime=-1  ICPrevOutput=DiscIntNeverNeededParam  ICPrevScaledInput=DiscIntNeverNeededParam
  Discrete-Time Integrator2 : DiscreteIntegrator  ExternalReset=level  SampleTime=-1  ICPrevOutput=DiscIntNeverNeededParam  ICPrevScaledInput=DiscIntNeverNeededParam
  Eg_d * (wCf) : Product  RndMeth=Zero
  "Eg_q * (wCf) " : Product  RndMeth=Zero
  Filter capacitance : Gain  Gain=C_f
  Integration Time : Gain  Gain=Ki_v / Kp_v
  Integration Time1 : Gain  Gain=Ki_v / Kp_v
  Integration Time2 : Gain  Gain=n
  Integration Time3 : Gain  Gain=n
  Integrator : Integrator  Commented=on
  Integrator1 : Integrator  Commented=on
  Is_0* : Constant  Value=0
  Mux : Mux  Inputs=3
  Selector : Selector  InputPortWidth=3  IndexOptions=Index vector (dialog)  Indices=[1 2]  OutputSizes=1
  Selector1 : Selector  InputPortWidth=3  IndexOptions=Index vector (dialog)  Indices=[1 2]  OutputSizes=1
  Selector2 : Selector  InputPortWidth=3  IndexOptions=Index vector (dialog)  Indices=[1 2]  OutputSizes=1
  Sum : Sum  Inputs=|+-
  Sum1 : Sum  Inputs=|++
  Sum2 : Sum  Inputs=|+-
  Sum3 : Sum  Inputs=|++
  Sum4 : Sum  Inputs=|++
  Sum5 : Sum  Inputs=++|
  Sum6 : Sum  Inputs=-+|
  Sum7 : Sum  Inputs=++|
  i_s_ref_dq0 : Outport  VectorParamsAs1DForOutWhenUnconnected=off
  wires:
  Integration Time3/1 -> Sum4/2
  Integration Time2/1 -> Sum1/2
  Sum/1 -> Integration Time2/1, Integration Time/1
  Mux/1 -> i_s_ref_dq0/1
  Selector2/1 -> Demux2/1
  Selector1/1 -> Demux/1
  Selector/1 -> Demux1/1
  Damping (q)/1 -> Sum5/2  "Is_q\""
  v_dq0/1 -> Selector/1
  Sum3/1 -> Mux/1  "Is_d*"
  Sum4/1 -> Damping (q)/1
  Sum1/1 -> Damping (d)/1
  Sum5/1 -> Sum7/2  "Is_q'"
  i_dq0/1 -> Selector2/1
  Damping (d)/1 -> Sum2/1  "Is_d\""
  Filter capacitance/1 -> Eg_d * (wCf)/2, "Eg_q * (wCf) "/2
  Demux1/2 -> Sum6/1, "Eg_q * (wCf) "/1  "Eg_q"
  "Eg_q * (wCf) "/1 -> Sum2/2  "Is_f"
  Current Compensator1/1 -> Sum7/1
  Demux1/1 -> Sum/2, Eg_d * (wCf)/1  "Eg_d"
  Current Compensator/1 -> Sum3/2
  Sum2/1 -> Sum3/1  "Is_d'"
  Demux2/1 -> Current Compensator/1  "Ig_d"
  Sum6/1 -> Integration Time1/1, Integration Time3/1
  Demux/1 -> Sum/1  "Eg_d*"
  Demux2/2 -> Current Compensator1/1  "Ig_q"
  Sum7/1 -> Mux/2  "Is_q*"
  Eg_d * (wCf)/1 -> Sum5/1  "Is_f"
  v_ref_dq0/1 -> Selector1/1
  Demux/2 -> Sum6/2  "Eg_q*"
  w/1 -> Filter capacitance/1
  Is_0*/1 -> Mux/3
  Integration Time1/1 -> Discrete-Time Integrator1/1
  Discrete-Time Integrator1/1 -> Sum4/1
  [rst] -> Discrete-Time Integrator1/2
  Integration Time/1 -> Discrete-Time Integrator2/1
  [rst] -> Discrete-Time Integrator2/2
  Discrete-Time Integrator2/1 -> Sum1/1

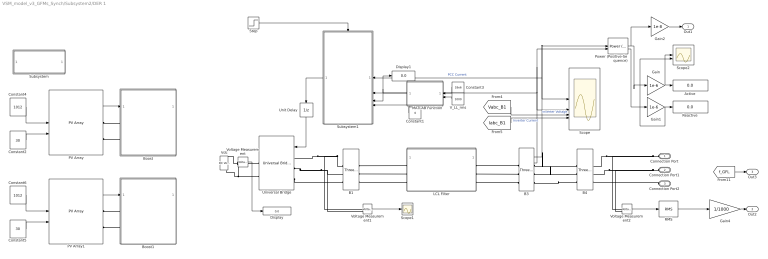
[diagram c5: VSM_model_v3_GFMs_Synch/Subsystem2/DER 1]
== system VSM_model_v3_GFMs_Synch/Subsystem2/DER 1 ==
  Active : Display
  B1 : spsThreePhaseVIMeasurementLib/Three-Phase V-I Measurement  VoltageMeasurement=phase-to-ground  SetLabelV=on  LabelV=Vabc_B1  Vpu=off  VpuLL=off  CurrentMeasurement=yes  SetLabelI=on  LabelI=Iabc_B1  Ipu=off  Pbase=100e6  Vbase=500e3  OutputType=Complex  PhasorSimulation=off  PSBequivalent=0
  B3 : spsThreePhaseVIMeasurementLib/Three-Phase V-I Measurement  VoltageMeasurement=phase-to-ground  SetLabelV=off  LabelV=Vabc_B3  Vpu=off  VpuLL=off  CurrentMeasurement=yes  SetLabelI=off  LabelI=Iabc_B3  Ipu=off  Pbase=100e6  Vbase=500e3  OutputType=Complex  PhasorSimulation=off  PSBequivalent=0
  B4 : spsThreePhaseVIMeasurementLib/Three-Phase V-I Measurement  VoltageMeasurement=phase-to-ground  SetLabelV=on  LabelV=Vabc_B4  Vpu=off  VpuLL=off  CurrentMeasurement=yes  SetLabelI=on  LabelI=Iabc_B4  Ipu=off  Pbase=100e6  Vbase=500e3  OutputType=Complex  PhasorSimulation=off  PSBequivalent=0
  Boost : Subsystem  Commented=on  mask{CPV=1e-3, RPV=1e-6, L0=3.9375e-3, C0=4296.875e-6, Kp=0.0053, Ki=0.0015}
      mask prompts: CPV "PV电容CPV："; RPV "PV电阻RPV："; L0 "BOOST电感L0："; C0 "直流电容C0："; Kp "BOOTKp："; Ki "BOOSTKi："
  Boost1 : Subsystem  Commented=on  mask{CPV=1e-3, RPV=1e-6, L0=3.9375e-3, C0=4296.875e-6, Kp=0.0053, Ki=0.0015}
      mask prompts: CPV "PV电容CPV："; RPV "PV电阻RPV："; L0 "BOOST电感L0："; C0 "直流电容C0："; Kp "BOOTKp："; Ki "BOOSTKi："
  Constant1 : Constant  Value=0  SampleTime=-1
  Constant2 : Constant  Commented=on  Value=30
  Constant3 : Constant  Value=18e6
  Constant4 : Constant  Commented=on  Value=1012
  Constant5 : Constant  Commented=on  Value=30
  Constant6 : Constant  Commented=on  Value=1012
  Display : Display
  Display1 : Display
  Gain : Gain  Gain=1e-6
  Gain1 : Gain  Gain=1e-6
  Gain2 : Gain  Gain=1e-8
  Gain4 : Gain  Gain=1/1000
  LCL Filter : Subsystem
  MATLAB Function : MATLAB Function  TreatAsAtomicUnit=on
  PV Array : spsPVArrayLib/PV Array  Commented=on  Npar=48  Nser=10  PlotType=array @ 25 deg.C & specified irradiances  S_vec="[ 1000  500  100 ]"  Temp_C_vec="[ 45 25  ]"  ModuleName=User-defined  PlotWhenSelected=off  Pm=213.15  Ncell=60  Voc=37.5  Isc=7.84  Vm=29  Im=7.35  beta_Voc_pc=-0.36099  alpha_Isc_pc=0.102  beta_Voc=-0.13537  alpha_Isc=0.0079968  IL=7.878  I0=2.9331e-10  nI=1.0135  Rsh=395.2679  Rs=0.55367  RobustModel=off  RobustCellTemperature=313.3991  BAL=off  Tc=1e-6  Tfilter=5e-5
  PV Array1 : spsPVArrayLib/PV Array  Commented=on  Npar=37532  Nser=35  PlotType=array @ 25 deg.C & specified irradiances  S_vec="[ 1000  500  100 ]"  Temp_C_vec="[ 45 25  ]"  ModuleName=User-defined  PlotWhenSelected=off  Pm=213.15  Ncell=60  Voc=37.5  Isc=7.84  Vm=29  Im=7.35  beta_Voc_pc=-0.36099  alpha_Isc_pc=0.102  beta_Voc=-0.13537  alpha_Isc=0.0079968  IL=7.878  I0=2.9331e-10  nI=1.0135  Rsh=395.2679  Rs=0.55367  RobustModel=off  RobustCellTemperature=313.3991  BAL=off  Tc=1e-6  Tfilter=5e-5
  Power (Positive-Sequence) : spsPowerPositiveSequenceLib/Power (Positive-Sequence)  Freq=50  Vinit=[0, 0]  Iinit=[0, 0]  Ts=0
  RMS : spsRMSLib/RMS  TrueRMS=on  Freq=50  RMSInit=120  Ts=0
  Reactive : Display
  Scope : Scope  NumInputPorts=4
  Scope1 : Scope
  Scope2 : Scope  NumInputPorts=2
  Step : Step  Time=42  SampleTime=0
  Subsystem : Subsystem  Commented=on
  Subsystem1 : Subsystem
  Unit Delay : UnitDelay  SampleTime=-1  HasFrameUpgradeWarning=on
  Universal Bridge : spsUniversalBridgeLib/Universal Bridge  Arms=3  SnubberResistance=1e5  SnubberCapacitance=inf  Device=Average-model based VSC  Ron=1e-3  Lon=0  ForwardVoltages="[  0  0  ]"  ForwardVoltage=0  GTOparameters=[ 10e-6 , 20e-6 ]  IGBTparameters=[ 1e-6 , 2e-6 ]  Measurements=None  Measurements_2=None  converterType=Rectifier
  V_LL_rms : Constant  Value=1000
  Vdc : spsDCVoltageSourceLib/DC Voltage Source  Amplitude=6000  Measurements=None
  Voltage Measurement : spsVoltageMeasurementLib/Voltage Measurement  PhasorSimulation=off  OutputType=Complex  PSBequivalent=0
  Voltage Measurement1 : spsVoltageMeasurementLib/Voltage Measurement  PhasorSimulation=off  OutputType=Complex  PSBequivalent=0
  Voltage Measurement2 : spsVoltageMeasurementLib/Voltage Measurement  PhasorSimulation=off  OutputType=Complex  PSBequivalent=0
  Connection Port : PMIOPort  Side=Left
  Connection Port1 : PMIOPort  Port=2  Side=Left
  Connection Port2 : PMIOPort  Port=3  Side=Left
  Out1 : Outport
  Out2 : Outport  Port=2
  Out3 : Outport  Port=3
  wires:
  B3/1 -> Scope/1, Power (Positive-Sequence)/1, Subsystem1/1(Vabc_B3)  "PCC Current"
  Voltage Measurement/1 -> Display/1
  [f_GFL] -> Out3/1
  Voltage Measurement1/1 -> Scope1/1
  Power (Positive-Sequence)/2 -> Gain1/1
  RMS/1 -> Gain4/1
  Gain/1 -> Scope2/1, Active/1
  Power (Positive-Sequence)/1 -> Gain2/1, Gain/1
  Gain4/1 -> Out2/1
  [Iabc_B1] -> Scope/4  "Inverter Current"
  Gain2/1 -> Out1/1
  Gain1/1 -> Scope2/2, Reactive/1
  [Vabc_B1] -> Scope/3  "Inverter Voltage"
  Voltage Measurement2/1 -> RMS/1
  MATLAB Function/1(Idref) -> Display1/1, Subsystem1/3(Idref)
  Constant1/1 -> Subsystem1/4(Iqref)
  Subsystem1/1(Pulses) -> Unit Delay/1
  Step/1 -> Subsystem1/Enable
  Unit Delay/1 -> Universal Bridge/1
  V_LL_rms/1 -> MATLAB Function/2(V)
  Constant3/1 -> MATLAB Function/1(P)
  Constant6/1 -> PV Array1/1
  Constant5/1 -> PV Array1/2
  Constant4/1 -> PV Array/1
  PV Array1/1 -> Boost1/1(m)
  Constant2/1 -> PV Array/2
  PV Array/1 -> Boost/1(m)
  B3/2 -> Scope/2, Power (Positive-Sequence)/2, Subsystem1/2(Iabc_B3)
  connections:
  B1/LConn1 -- Universal Bridge/LConn1 -- Voltage Measurement1/LConn1
  Connection Port1/RConn1 -- B4/RConn2 -- Voltage Measurement2/LConn2
  Connection Port/RConn1 -- B4/RConn1 -- Voltage Measurement2/LConn1
  Universal Bridge/RConn1 -- Vdc/RConn1 -- Voltage Measurement/LConn1
  Universal Bridge/LConn2 -- B1/LConn2 -- Voltage Measurement1/LConn2
  Universal Bridge/RConn2 -- Vdc/LConn1 -- Voltage Measurement/LConn2
  B3/LConn2 -- LCL Filter/RConn2
  B1/RConn3 -- LCL Filter/LConn3
  B3/RConn2 -- B4/LConn2
  B3/RConn1 -- B4/LConn1
  Connection Port2/RConn1 -- B4/RConn3
  B1/RConn2 -- LCL Filter/LConn2
  B3/LConn3 -- LCL Filter/RConn3
  B3/LConn1 -- LCL Filter/RConn1
  Universal Bridge/LConn3 -- B1/LConn3
  B1/RConn1 -- LCL Filter/LConn1
  B3/RConn3 -- B4/LConn3
  Boost/LConn2 -- PV Array/RConn2
  Boost1/LConn2 -- PV Array1/RConn2
  Boost1/LConn1 -- PV Array1/RConn1
  Boost/LConn1 -- PV Array/RConn1

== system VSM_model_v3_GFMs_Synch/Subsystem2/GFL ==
  Active : Display
  B1 : spsThreePhaseVIMeasurementLib/Three-Phase V-I Measurement  VoltageMeasurement=phase-to-ground  SetLabelV=on  LabelV=Vabc_B1  Vpu=off  VpuLL=off  CurrentMeasurement=yes  SetLabelI=on  LabelI=Iabc_B1  Ipu=off  Pbase=100e6  Vbase=500e3  OutputType=Complex  PhasorSimulation=off  PSBequivalent=0
  B3 : spsThreePhaseVIMeasurementLib/Three-Phase V-I Measurement  VoltageMeasurement=phase-to-ground  SetLabelV=on  LabelV=Vabc_B3  Vpu=off  VpuLL=off  CurrentMeasurement=yes  SetLabelI=on  LabelI=Iabc_B3  Ipu=off  Pbase=100e6  Vbase=500e3  OutputType=Complex  PhasorSimulation=off  PSBequivalent=0
  B4 : spsThreePhaseVIMeasurementLib/Three-Phase V-I Measurement  VoltageMeasurement=phase-to-ground  SetLabelV=on  LabelV=Vabc_B4  Vpu=off  VpuLL=off  CurrentMeasurement=yes  SetLabelI=on  LabelI=Iabc_B4  Ipu=off  Pbase=100e6  Vbase=500e3  OutputType=Complex  PhasorSimulation=off  PSBequivalent=0
  Constant1 : Constant  Value=0  SampleTime=-1
  Derivative : Derivative
  Display : Display
  Gain : Gain  Gain=1e-6
  Gain1 : Gain  Gain=1e-6
  Gain2 : Gain  Gain=1e-8
  Gain3 : Gain  Gain=1/(2*pi)
  Gain4 : Gain  Gain=1/1000
  Inverter Control : Subsystem
  LCL Filter : Subsystem
  Power (Positive-Sequence) : spsPowerPositiveSequenceLib/Power (Positive-Sequence)  Freq=50  Vinit=[0, 0]  Iinit=[0, 0]  Ts=0
  RMS : spsRMSLib/RMS  TrueRMS=on  Freq=50  RMSInit=120  Ts=0
  Ramp : simulink/Sources/Ramp  slope=60e3  start=30  InitialOutput=0
  Reactive : Display
  Saturation : Saturate  UpperLimit=60e3  LowerLimit=0
  Scope : Scope  NumInputPorts=4
  Scope1 : Scope
  Scope2 : Scope  NumInputPorts=2
  Subsystem1 : Subsystem
  Universal Bridge : spsUniversalBridgeLib/Universal Bridge  Arms=3  SnubberResistance=1e5  SnubberCapacitance=inf  Device=Average-model based VSC  Ron=1e-3  Lon=0  ForwardVoltages="[  0  0  ]"  ForwardVoltage=0  GTOparameters=[ 10e-6 , 20e-6 ]  IGBTparameters=[ 1e-6 , 2e-6 ]  Measurements=None  Measurements_2=None  converterType=Rectifier
  Vdc : spsDCVoltageSourceLib/DC Voltage Source  Amplitude=40e3  Measurements=None
  Voltage Measurement : spsVoltageMeasurementLib/Voltage Measurement  PhasorSimulation=off  OutputType=Complex  PSBequivalent=0
  Voltage Measurement1 : spsVoltageMeasurementLib/Voltage Measurement  PhasorSimulation=off  OutputType=Complex  PSBequivalent=0
  Voltage Measurement2 : spsVoltageMeasurementLib/Voltage Measurement  PhasorSimulation=off  OutputType=Complex  PSBequivalent=0
  Connection Port : PMIOPort  Side=Left
  Connection Port1 : PMIOPort  Port=2  Side=Left
  Connection Port2 : PMIOPort  Port=3  Side=Left
  Out1 : Outport
  Out2 : Outport  Port=2
  Out4 : Outport  Port=3
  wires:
  [Vabc_B1] -> Scope/3  "Inverter Voltage"
  [Iabc_B1] -> Scope/4  "Inverter Current"
  Voltage Measurement1/1 -> Scope1/1
  Gain1/1 -> Scope2/2, Reactive/1  "Q"
  [Iabc_B3] -> Power (Positive-Sequence)/2, Scope/2  "PCC Current"
  Inverter Control/1(Pulses) -> Universal Bridge/1
  [Vabc_B3] -> Inverter Control/1(Vabc_B3)
  Voltage Measurement/1 -> Display/1
  Gain/1 -> Scope2/1, Active/1  "P"
  Power (Positive-Sequence)/2 -> Gain1/1
  [Iabc_B3] -> Inverter Control/2(Iabc_B3)
  [Vabc_B3] -> Scope/1, Power (Positive-Sequence)/1  "PCC Voltage"
  Power (Positive-Sequence)/1 -> Gain2/1, Gain/1
  Gain2/1 -> Out1/1
  RMS/1 -> [Vpcc], Gain4/1
  Voltage Measurement2/1 -> RMS/1
  Gain4/1 -> Out2/1
  Inverter Control/2(wt) -> Derivative/1
  Derivative/1 -> Gain3/1
  Gain3/1 -> Out4/1
  Inverter Control/3(Iq_droop) -> [Iq_droop]
  [Vpcc] -> Inverter Control/5(Vpcc)
  Constant1/1 -> Inverter Control/4(Iqref)
  Ramp/1 -> Saturation/1
  Saturation/1 -> Inverter Control/3(Idref)
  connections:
  Universal Bridge/RConn1 -- Vdc/RConn1 -- Voltage Measurement/LConn1
  Vdc/LConn1 -- Universal Bridge/RConn2 -- Voltage Measurement/LConn2
  B1/LConn2 -- Voltage Measurement1/LConn2 -- Universal Bridge/LConn2
  Universal Bridge/LConn1 -- Voltage Measurement1/LConn1 -- B1/LConn1
  B3/LConn3 -- LCL Filter/RConn3
  B3/RConn3 -- B4/LConn3
  B3/RConn1 -- B4/LConn1
  Connection Port2/RConn1 -- B4/RConn3
  B3/LConn2 -- LCL Filter/RConn2
  Universal Bridge/LConn3 -- B1/LConn3
  B3/RConn2 -- B4/LConn2
  B3/LConn1 -- LCL Filter/RConn1
  B1/RConn1 -- LCL Filter/LConn1
  B1/RConn2 -- LCL Filter/LConn2
  B1/RConn3 -- LCL Filter/LConn3
  B4/RConn1 -- Voltage Measurement2/LConn1 -- Connection Port/RConn1
  B4/RConn2 -- Voltage Measurement2/LConn2 -- Connection Port1/RConn1

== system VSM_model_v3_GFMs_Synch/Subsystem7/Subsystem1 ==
  Inport : Inport
  Enable : Inport  Port=2
  Breaker6 : spsThreePhaseBreakerLib/Three-Phase Breaker  InitialState=open  SwitchA=on  SwitchB=on  SwitchC=on  SwitchTimes=18  External=on  BreakerResistance=0.01  SnubberResistance=1e6  SnubberCapacitance=inf  Measurements=None
  DER : Subsystem
  Demux : Demux  Outputs=3
  Demux1 : Demux  Outputs=3
  Ground : spsGroundLib/Ground  Commented=on  LConnTagsString=a
  MATLAB Function : MATLAB Function  TreatAsAtomicUnit=on
  Pgen : Display
  Pgen1 : Display
  Scope1 : Scope  NumInputPorts=2
  Scope5 : Scope  NumInputPorts=2
  Subsystem6 : Subsystem  Commented=on
  Three-Phase Series RLC Branch : spsThreePhaseSeriesRLCBranchLib/Three-Phase Series RLC Branch  Commented=on  LConnTagsString=A|B|C  RConnTagsString=A|B|C  BranchType=R  Resistance=R_base_gfl  Inductance=1e-3  Capacitance=1e-6  Measurements=None
  Three-Phase V-I Measurement1 : spsThreePhaseVIMeasurementLib/Three-Phase V-I Measurement  VoltageMeasurement=phase-to-ground  SetLabelV=off  LabelV=Vabc  Vpu=off  VpuLL=off  CurrentMeasurement=yes  SetLabelI=off  LabelI=Iabc  Ipu=off  Pbase=100e6  Vbase=500e3  OutputType=Complex  PhasorSimulation=off  PSBequivalent=0
  Three-Phase V-I Measurement4 : spsThreePhaseVIMeasurementLib/Three-Phase V-I Measurement  VoltageMeasurement=phase-to-ground  SetLabelV=off  LabelV=Vabc  Vpu=off  VpuLL=off  CurrentMeasurement=yes  SetLabelI=off  LabelI=Iabc  Ipu=off  Pbase=100e6  Vbase=500e3  OutputType=Complex  PhasorSimulation=off  PSBequivalent=0
  Three-Phase Source : spsThreePhaseSourceLib/Three-Phase Source  Commented=on  InternalConnection=Yg  VoltagePhases=off  Voltage=V1_rms_gfl  PhaseAngle=0  Voltage_phases=[25e3 25e3 25e3]/sqrt(3)  PhaseAngles_phases=[0 -120 +120]  Frequency=50  NonIdealSource=on  SpecifyImpedance=off  Resistance=Rg  Inductance=Lg  ShortCircuitLevel=1000e6  BaseVoltage=V1_rms_gfl  XRratio=7  BusType=swing  Pref=10e3  Qref=0  Prefabc=[10e3, 10e3, 10e3]  Qrefabc=[0, 0, 0]  Qmin=-inf  Qmax=inf
  Connection Port : PMIOPort  Side=Right
  Connection Port1 : PMIOPort  Port=2  Side=Right
  Connection Port2 : PMIOPort  Port=3  Side=Right
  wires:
  Three-Phase V-I Measurement4/1 -> Demux/1, [Vabc_PCC], Scope1/1, Scope5/1
  Inport/1 -> DER/1(P_ref_MW)
  Enable/1 -> Breaker6/1, DER/2(Enable)
  Three-Phase V-I Measurement4/2 -> Demux1/1, Scope5/2
  MATLAB Function/1(P_W) -> Pgen/1
  MATLAB Function/2(Q_VAr) -> Pgen1/1
  Demux/1 -> MATLAB Function/1(Va)
  Demux/2 -> MATLAB Function/2(Vb)
  Demux/3 -> MATLAB Function/3(Vc)
  Demux1/1 -> MATLAB Function/4(Ia)
  Demux1/2 -> MATLAB Function/5(Ib)
  Demux1/3 -> MATLAB Function/6(Ic)
  [Iabc] -> DER/3(Iabc)
  [Vabc_PCC] -> DER/4(Vabc)
  Three-Phase V-I Measurement1/1 -> Scope1/2
  [Vabc_PCC] -> Subsystem6/1(Vabc_PCC)
  [Vabc_DER] -> Subsystem6/2(Vabc_DER)
  Three-Phase V-I Measurement1/2 -> [Iabc]
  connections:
  Three-Phase Series RLC Branch/LConn3 -- Three-Phase Source/RConn3
  Three-Phase Series RLC Branch/LConn1 -- Three-Phase Source/RConn1
  Three-Phase Series RLC Branch/LConn2 -- Three-Phase Source/RConn2
  Three-Phase Series RLC Branch/RConn1 -- Ground/LConn1 -- Three-Phase Series RLC Branch/RConn3 -- Three-Phase Series RLC Branch/RConn2
  Connection Port/RConn1 -- Three-Phase V-I Measurement4/RConn1
  Connection Port2/RConn1 -- Three-Phase V-I Measurement4/RConn3
  Connection Port1/RConn1 -- Three-Phase V-I Measurement4/RConn2
  Breaker6/RConn1 -- Three-Phase V-I Measurement4/LConn1
  Breaker6/RConn2 -- Three-Phase V-I Measurement4/LConn2
  Breaker6/RConn3 -- Three-Phase V-I Measurement4/LConn3
  Three-Phase V-I Measurement1/RConn1 -- Breaker6/LConn1
  Three-Phase V-I Measurement1/RConn2 -- Breaker6/LConn2
  Three-Phase V-I Measurement1/RConn3 -- Breaker6/LConn3
  DER/RConn1 -- Three-Phase V-I Measurement1/LConn1
  DER/RConn2 -- Three-Phase V-I Measurement1/LConn2
  DER/RConn3 -- Three-Phase V-I Measurement1/LConn3

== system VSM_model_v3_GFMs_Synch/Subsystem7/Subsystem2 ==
  Inport : Inport
  Enable : Inport  Port=2
  Breaker6 : spsThreePhaseBreakerLib/Three-Phase Breaker  InitialState=open  SwitchA=on  SwitchB=on  SwitchC=on  SwitchTimes=18  External=on  BreakerResistance=0.01  SnubberResistance=1e6  SnubberCapacitance=inf  Measurements=None
  DER : Subsystem
  Demux : Demux  Outputs=3
  Demux1 : Demux  Outputs=3
  Ground : spsGroundLib/Ground  Commented=on  LConnTagsString=a
  MATLAB Function : MATLAB Function  TreatAsAtomicUnit=on
  Pgen : Display
  Pgen1 : Display
  Scope1 : Scope  NumInputPorts=2
  Scope5 : Scope  NumInputPorts=2
  Subsystem6 : Subsystem  Commented=on
  Three-Phase Series RLC Branch : spsThreePhaseSeriesRLCBranchLib/Three-Phase Series RLC Branch  Commented=on  LConnTagsString=A|B|C  RConnTagsString=A|B|C  BranchType=R  Resistance=R_base_gfl  Inductance=1e-3  Capacitance=1e-6  Measurements=None
  Three-Phase V-I Measurement1 : spsThreePhaseVIMeasurementLib/Three-Phase V-I Measurement  VoltageMeasurement=phase-to-ground  SetLabelV=off  LabelV=Vabc  Vpu=off  VpuLL=off  CurrentMeasurement=yes  SetLabelI=off  LabelI=Iabc  Ipu=off  Pbase=100e6  Vbase=500e3  OutputType=Complex  PhasorSimulation=off  PSBequivalent=0
  Three-Phase V-I Measurement4 : spsThreePhaseVIMeasurementLib/Three-Phase V-I Measurement  VoltageMeasurement=phase-to-ground  SetLabelV=off  LabelV=Vabc  Vpu=off  VpuLL=off  CurrentMeasurement=yes  SetLabelI=off  LabelI=Iabc  Ipu=off  Pbase=100e6  Vbase=500e3  OutputType=Complex  PhasorSimulation=off  PSBequivalent=0
  Three-Phase Source : spsThreePhaseSourceLib/Three-Phase Source  Commented=on  InternalConnection=Yg  VoltagePhases=off  Voltage=V1_rms_gfl  PhaseAngle=0  Voltage_phases=[25e3 25e3 25e3]/sqrt(3)  PhaseAngles_phases=[0 -120 +120]  Frequency=50  NonIdealSource=on  SpecifyImpedance=off  Resistance=Rg  Inductance=Lg  ShortCircuitLevel=1000e6  BaseVoltage=V1_rms_gfl  XRratio=7  BusType=swing  Pref=10e3  Qref=0  Prefabc=[10e3, 10e3, 10e3]  Qrefabc=[0, 0, 0]  Qmin=-inf  Qmax=inf
  Connection Port : PMIOPort  Side=Right
  Connection Port1 : PMIOPort  Port=2  Side=Right
  Connection Port2 : PMIOPort  Port=3  Side=Right
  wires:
  Three-Phase V-I Measurement4/1 -> Demux/1, [Vabc_PCC], Scope1/1, Scope5/1
  Inport/1 -> DER/1(P_ref_MW)
  Enable/1 -> Breaker6/1, DER/2(Enable)
  Three-Phase V-I Measurement4/2 -> Demux1/1, Scope5/2
  MATLAB Function/1(P_W) -> Pgen/1
  MATLAB Function/2(Q_VAr) -> Pgen1/1
  Demux/1 -> MATLAB Function/1(Va)
  Demux/2 -> MATLAB Function/2(Vb)
  Demux/3 -> MATLAB Function/3(Vc)
  Demux1/1 -> MATLAB Function/4(Ia)
  Demux1/2 -> MATLAB Function/5(Ib)
  Demux1/3 -> MATLAB Function/6(Ic)
  [Iabc] -> DER/3(Iabc)
  [Vabc_PCC] -> DER/4(Vabc)
  Three-Phase V-I Measurement1/1 -> Scope1/2
  [Vabc_PCC] -> Subsystem6/1(Vabc_PCC)
  [Vabc_DER] -> Subsystem6/2(Vabc_DER)
  Three-Phase V-I Measurement1/2 -> [Iabc]
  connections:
  Three-Phase Series RLC Branch/LConn3 -- Three-Phase Source/RConn3
  Three-Phase Series RLC Branch/LConn1 -- Three-Phase Source/RConn1
  Three-Phase Series RLC Branch/LConn2 -- Three-Phase Source/RConn2
  Three-Phase Series RLC Branch/RConn1 -- Ground/LConn1 -- Three-Phase Series RLC Branch/RConn3 -- Three-Phase Series RLC Branch/RConn2
  Connection Port/RConn1 -- Three-Phase V-I Measurement4/RConn1
  Connection Port2/RConn1 -- Three-Phase V-I Measurement4/RConn3
  Connection Port1/RConn1 -- Three-Phase V-I Measurement4/RConn2
  Breaker6/RConn1 -- Three-Phase V-I Measurement4/LConn1
  Breaker6/RConn2 -- Three-Phase V-I Measurement4/LConn2
  Breaker6/RConn3 -- Three-Phase V-I Measurement4/LConn3
  Three-Phase V-I Measurement1/RConn1 -- Breaker6/LConn1
  Three-Phase V-I Measurement1/RConn2 -- Breaker6/LConn2
  Three-Phase V-I Measurement1/RConn3 -- Breaker6/LConn3
  DER/RConn1 -- Three-Phase V-I Measurement1/LConn1
  DER/RConn2 -- Three-Phase V-I Measurement1/LConn2
  DER/RConn3 -- Three-Phase V-I Measurement1/LConn3

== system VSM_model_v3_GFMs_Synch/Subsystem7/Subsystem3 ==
  Inport : Inport
  Enable : Inport  Port=2
  Breaker6 : spsThreePhaseBreakerLib/Three-Phase Breaker  InitialState=open  SwitchA=on  SwitchB=on  SwitchC=on  SwitchTimes=18  External=on  BreakerResistance=0.01  SnubberResistance=1e6  SnubberCapacitance=inf  Measurements=None
  DER : Subsystem
  Demux : Demux  Outputs=3
  Demux1 : Demux  Outputs=3
  Ground : spsGroundLib/Ground  Commented=on  LConnTagsString=a
  MATLAB Function : MATLAB Function  TreatAsAtomicUnit=on
  Pgen : Display
  Pgen1 : Display
  Scope1 : Scope  NumInputPorts=2
  Scope5 : Scope  NumInputPorts=2
  Subsystem6 : Subsystem  Commented=on
  Three-Phase Series RLC Branch : spsThreePhaseSeriesRLCBranchLib/Three-Phase Series RLC Branch  Commented=on  LConnTagsString=A|B|C  RConnTagsString=A|B|C  BranchType=R  Resistance=R_base_gfl  Inductance=1e-3  Capacitance=1e-6  Measurements=None
  Three-Phase V-I Measurement1 : spsThreePhaseVIMeasurementLib/Three-Phase V-I Measurement  VoltageMeasurement=phase-to-ground  SetLabelV=off  LabelV=Vabc  Vpu=off  VpuLL=off  CurrentMeasurement=yes  SetLabelI=off  LabelI=Iabc  Ipu=off  Pbase=100e6  Vbase=500e3  OutputType=Complex  PhasorSimulation=off  PSBequivalent=0
  Three-Phase V-I Measurement4 : spsThreePhaseVIMeasurementLib/Three-Phase V-I Measurement  VoltageMeasurement=phase-to-ground  SetLabelV=off  LabelV=Vabc  Vpu=off  VpuLL=off  CurrentMeasurement=yes  SetLabelI=off  LabelI=Iabc  Ipu=off  Pbase=100e6  Vbase=500e3  OutputType=Complex  PhasorSimulation=off  PSBequivalent=0
  Three-Phase Source : spsThreePhaseSourceLib/Three-Phase Source  Commented=on  InternalConnection=Yg  VoltagePhases=off  Voltage=V1_rms_gfl  PhaseAngle=0  Voltage_phases=[25e3 25e3 25e3]/sqrt(3)  PhaseAngles_phases=[0 -120 +120]  Frequency=50  NonIdealSource=on  SpecifyImpedance=off  Resistance=Rg  Inductance=Lg  ShortCircuitLevel=1000e6  BaseVoltage=V1_rms_gfl  XRratio=7  BusType=swing  Pref=10e3  Qref=0  Prefabc=[10e3, 10e3, 10e3]  Qrefabc=[0, 0, 0]  Qmin=-inf  Qmax=inf
  Connection Port : PMIOPort  Side=Right
  Connection Port1 : PMIOPort  Port=2  Side=Right
  Connection Port2 : PMIOPort  Port=3  Side=Right
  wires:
  Three-Phase V-I Measurement4/1 -> Demux/1, [Vabc_PCC], Scope1/1, Scope5/1
  Inport/1 -> DER/1(P_ref_MW)
  Enable/1 -> Breaker6/1, DER/2(Enable)
  Three-Phase V-I Measurement4/2 -> Demux1/1, Scope5/2
  MATLAB Function/1(P_W) -> Pgen/1
  MATLAB Function/2(Q_VAr) -> Pgen1/1
  Demux/1 -> MATLAB Function/1(Va)
  Demux/2 -> MATLAB Function/2(Vb)
  Demux/3 -> MATLAB Function/3(Vc)
  Demux1/1 -> MATLAB Function/4(Ia)
  Demux1/2 -> MATLAB Function/5(Ib)
  Demux1/3 -> MATLAB Function/6(Ic)
  [Iabc] -> DER/3(Iabc)
  [Vabc_PCC] -> DER/4(Vabc)
  Three-Phase V-I Measurement1/1 -> Scope1/2
  [Vabc_PCC] -> Subsystem6/1(Vabc_PCC)
  [Vabc_DER] -> Subsystem6/2(Vabc_DER)
  Three-Phase V-I Measurement1/2 -> [Iabc]
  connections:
  Three-Phase Series RLC Branch/LConn3 -- Three-Phase Source/RConn3
  Three-Phase Series RLC Branch/LConn1 -- Three-Phase Source/RConn1
  Three-Phase Series RLC Branch/LConn2 -- Three-Phase Source/RConn2
  Three-Phase Series RLC Branch/RConn1 -- Ground/LConn1 -- Three-Phase Series RLC Branch/RConn3 -- Three-Phase Series RLC Branch/RConn2
  Connection Port/RConn1 -- Three-Phase V-I Measurement4/RConn1
  Connection Port2/RConn1 -- Three-Phase V-I Measurement4/RConn3
  Connection Port1/RConn1 -- Three-Phase V-I Measurement4/RConn2
  Breaker6/RConn1 -- Three-Phase V-I Measurement4/LConn1
  Breaker6/RConn2 -- Three-Phase V-I Measurement4/LConn2
  Breaker6/RConn3 -- Three-Phase V-I Measurement4/LConn3
  Three-Phase V-I Measurement1/RConn1 -- Breaker6/LConn1
  Three-Phase V-I Measurement1/RConn2 -- Breaker6/LConn2
  Three-Phase V-I Measurement1/RConn3 -- Breaker6/LConn3
  DER/RConn1 -- Three-Phase V-I Measurement1/LConn1
  DER/RConn2 -- Three-Phase V-I Measurement1/LConn2
  DER/RConn3 -- Three-Phase V-I Measurement1/LConn3
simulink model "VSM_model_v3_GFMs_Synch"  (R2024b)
settings: Solver=ode23tb  StartTime=0.0  StopTime=Tend  FixedStep=T_s  RelTol=1e-3  EnableMultiTasking=on
PostLoadFcn:
  | Tcontrol=20e-6;
InitFcn:
  | Tcontrol=20e-6;
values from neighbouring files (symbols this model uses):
  C_4 = 0.1670*C_b    (= 1.00487241952e-06)    [VSM.m]    (also in VSM_CSIRO.m)
  C_6 = 0.2835*C_b    (= 1.70587623314e-06)    [VSM.m]    (also in VSM_CSIRO.m)
  C_8 = 0.2275*C_b    (= 1.36891302659e-06)    [VSM.m]    (also in VSM_CSIRO.m)
  C_dc = 0.008*(n)    (= 1.6)    [VSM.m]    (also in VSM_CSIRO.m)
  C_f = n*300*10^-6    (= 0.06)    [VSM.m]    (also in VSM_CSIRO.m)
  C_f_gfl = (n_gfl) * Cf_unit_gfl    (= 0.00350140874802)    [DER_param.m]
  D_p = (1/(m_p*w_b))    (= 101321.183642)    [VSM.m]    (also in VSM_CSIRO.m)
  droop_percentage = 5    [VSM.m]    (also in VSM_CSIRO.m = 1)
  I_b_dc = S_b/Vdc_n    [VSM.m]    (also in VSM_CSIRO.m)
  I_b_LV_peak = I_b_LV * sqrt(2)    [VSM.m]
  I_b_SG_peak = I_b_SG * sqrt(2)    [VSM.m]
  i_ll = -1.15*(S_b/Vdc_n)-i_loss_dc    [VSM.m]    (also in VSM_CSIRO.m)
  i_ul = 1.15*(S_b/Vdc_n)+i_loss_dc    [VSM.m]    (also in VSM_CSIRO.m)
  J = D_p*tau_f    (= 2026.42367285)    [VSM.m]    (also in VSM_CSIRO.m)
  k_dc = eta_1/(Vdc_n*m_p)    [VSM.m]    (also in VSM_CSIRO.m)
  K_p = (1/Vdc_n)    [VSM.m]    (also in VSM_CSIRO.m)
  K_r = 1/R_dc    [VSM.m]    (also in VSM_CSIRO.m)
  Kff_i = 1    [VSM.m]    (also in VSM_CSIRO.m)
  Kff_v = 1    [VSM.m]    (also in VSM_CSIRO.m)
  Ki_i = (1/n)*1.19    (= 0.00595)    [VSM.m]    (also in VSM_CSIRO.m)
  Ki_i_gfl = (1/n_gfl) * Ki_i_unit_gfl    (= 0.571198664289)    [DER_param.m]
  Ki_v = (n)*1.161022    (= 232.2044)    [VSM.m]    (also in VSM_CSIRO.m)
  ki_v_ac = 4*5.2500e-04    (= 0.0021)    [VSM.m]    (also in VSM_CSIRO.m)
  Kp_i = 0.738891    [VSM.m]    (also in VSM_CSIRO.m)
  Kp_i_gfl = (1/n_gfl) * Kp_i_unit_gfl    (= 0.00909090909091)    [DER_param.m]
  Kp_v = 0.52    [VSM.m]    (also in VSM_CSIRO.m)
  kp_v_ac = 0.001    [VSM.m]    (also in VSM_CSIRO.m)
  L1_f_gfl = (1/n_gfl) * L1_unit_gfl    (= 1.44686311902e-05)    [DER_param.m]
  L1_pu = 1*0.0186/m    (= 0.000186)    [VSM.m]    (also in VSM_CSIRO.m)
  L1_pu_gfl = 0.03    [DER_param.m]
  L2_f_gfl = (1/n_gfl) * L2_unit_gfl    (= 2.89372623803e-06)    [DER_param.m]
  L2_pu_gfl = 0.03    [DER_param.m]
  L_45 = L_lines(2)    [VSM.m]    (also in VSM_CSIRO.m)
  L_56 = L_lines(3)    [VSM.m]    (also in VSM_CSIRO.m)
  L_67 = L_lines(5)    [VSM.m]    (also in VSM_CSIRO.m)
  L_78 = L_lines(6)    [VSM.m]    (also in VSM_CSIRO.m)
  L_89 = L_lines(8)    [VSM.m]    (also in VSM_CSIRO.m)
  L_94 = L_lines(9)    [VSM.m]    (also in VSM_CSIRO.m)
  L_f = (1/n)*200*10^-6    (= 1e-06)    [VSM.m]    (also in VSM_CSIRO.m)
  Lg = (X_BY_R_gfl * Rg) / wn_gfl    [DER_param.m]    (also in initialcondition_gfm_Pooyan.m = X_BY_R*Rg/(wn); initialcondition_Pooyan.m = X_BY_R*Rg/(wn))
  n = 200    [VSM.m]    (also in VSM_CSIRO.m)
  Pgen_MW_gfl = 20    [DER_param.m]
  ps = base/3    (= 0.75)    [VSM.m]    (also in VSM_CSIRO.m)
  R1_f_gfl = (1/n_gfl) * R1_unit_gfl    (= 0.000909090909091)    [DER_param.m]
  R1_pu = 1*0.00734/m    (= 7.34e-05)    [VSM.m]    (also in VSM_CSIRO.m)
  R1_pu_gfl = 0.005    [DER_param.m]
  R2_f_gfl = (1/n_gfl) * R2_unit_gfl    (= 0.000181818181818)    [DER_param.m]
  R2_pu_gfl = 0.005    [DER_param.m]
  R_45 = R_lines(2)    [VSM.m]    (also in VSM_CSIRO.m)
  R_56 = R_lines(3)    [VSM.m]    (also in VSM_CSIRO.m)
  R_67 = R_lines(5)    [VSM.m]    (also in VSM_CSIRO.m)
  R_78 = R_lines(6)    [VSM.m]    (also in VSM_CSIRO.m)
  R_89 = R_lines(8)    [VSM.m]    (also in VSM_CSIRO.m)
  R_94 = R_lines(9)    [VSM.m]    (also in VSM_CSIRO.m)
  R_base_gfl = (3 * Vg_gfl^2) / (2 * Pn_gfl)    [DER_param.m]
  R_dc = (Vdc_n/(0.05*(S_b)/Vdc_n))    [VSM.m]    (also in VSM_CSIRO.m)
  R_f = 0.001/n    (= 5e-06)    [VSM.m]    (also in VSM_CSIRO.m)
  Rg = (3 * Vg_gfl^2) / (2 * SCR_gfl * sqrt(1 + X_BY_R_gfl^2) * Pn_gfl)    [DER_param.m]    (also in initialcondition_gfm_Pooyan.m = (3*Vg^2)/(2*SCR*sqrt(1+X_BY_R^2)*Pn); initialcondition_Pooyan.m = (3*Vg^2)/(2*SCR*sqrt(1+X_BY_R^2)*Pn))
  S_b = 100*(10^6)    (= 100000000)    [VSM.m]    (also in VSM_CSIRO.m)
  S_bt = S_b    (= 100000000)    [VSM.m]    (also in VSM_CSIRO.m)
  S_bt_gfl = S_b_gfl    (= 22000000)    [DER_param.m]
  T_en = T_load-0.5    (= 24.5)    [VSM.m]    (also in VSM_CSIRO.m = 44.5)
  T_s = 1e-4    (= 0.0001)    [VSM.m]    (also in VSM_CSIRO.m)
  tau_dc = 0.05    [VSM.m]    (also in VSM_CSIRO.m)
  tau_g = 5    [VSM.m]    (also in VSM_CSIRO.m)
  Tend = 90    [VSM.m]    (also in VSM_CSIRO.m = 50)
  ts_DER = 15    [DER_param.m]
  V1_rms = 1000    [VSM.m]    (also in VSM_CSIRO.m)
  V1_rms_gfl = 1000    [DER_param.m]
  V1_rms_tx1_gfl = 1000    [DER_param.m]
  V2_rms = 13800    [VSM.m]    (also in VSM_CSIRO.m)
  V2_rms_tx1_gfl = 13800    [DER_param.m]
  V_b = 230*(10^3)    (= 230000)    [VSM.m]    (also in VSM_CSIRO.m)
  V_m = sqrt(2/3)*V1_rms    [VSM.m]    (also in VSM_CSIRO.m)
  V_m_gfl = sqrt(2/3)*V1_rms_gfl    [DER_param.m]
  V_sg_p = sqrt(2/3)*V2_rms    [VSM.m]
  Vdc_n = 3*V_m    [VSM.m]    (also in VSM_CSIRO.m)
  Vdc_n_gfl = 2300    [DER_param.m]
  w_b = 2*pi*f_b    (= 314.159265359)    [VSM.m]    (also in VSM_CSIRO.m)
  w_b_gfl = 2*pi*f_b_gfl    (= 314.159265359)    [DER_param.m]
  w_f = 2*pi*5    (= 31.4159265359)    [VSM.m]    (also in VSM_CSIRO.m)
undefined symbols (not defined in the file or in its folder): D1, Delta, DiscIntNeverNeededParam, dspblkCoreblockFVToolHelper, gcbh, i_dc, magnitude
libraries: spsSeriesRLCBranchLib x82, spsabctodq0Lib x40, slpidlib x36, spsVoltageMeasurementLib x32, spsThreePhaseVIMeasurementLib x31, spsThreePhaseBreakerLib x26, spsGroundLib x22, spsCurrentMeasurementLib x20, spsPLL3phLib x14, spsThreePhaseTransformerTwoWindingsLib x14, simulink x13, spsThreePhaseSeriesRLCBranchLib x10
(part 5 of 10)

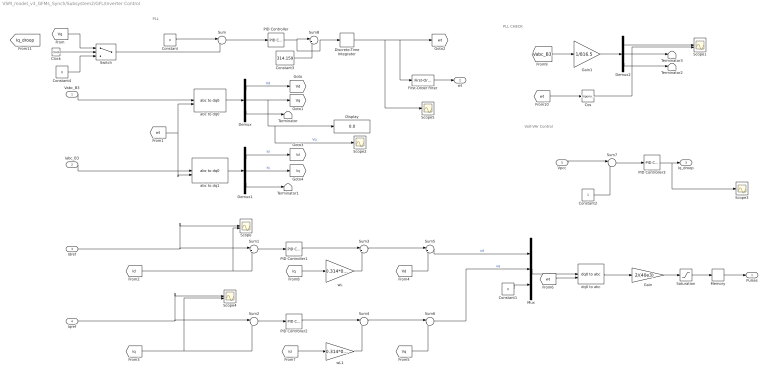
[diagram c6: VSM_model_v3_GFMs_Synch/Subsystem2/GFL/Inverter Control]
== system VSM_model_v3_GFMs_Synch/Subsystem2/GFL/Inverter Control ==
  note: PLL CHECK
  note: PLL
  note: Volt-VAr Control
  Vabc_B3 : Inport
  Iabc_B3 : Inport  Port=2
  Idref : Inport  Port=3
  Iqref : Inport  Port=4
  Vpcc : Inport  Port=5
  Clock : Clock
  Constant : Constant  Value=0  SampleTime=-1
  Constant1 : Constant  Value=0  SampleTime=-1
  Constant2 : Constant  Commented=on
  Constant3 : Constant  Value=314.159  SampleTime=-1
  Constant4 : Constant  Value=0
  Cos : Trigonometry
  Demux : Demux  Outputs=3
  Demux1 : Demux  Outputs=3
  Demux2 : Demux  Outputs=3
  Discrete-Time Integrator : DiscreteIntegrator  SampleTime=-1  ICPrevOutput=DiscIntNeverNeededParam  ICPrevScaledInput=DiscIntNeverNeededParam
  Display : Display
  First-Order Filter : spsFirstOrderFilterLib/First-Order Filter  FilterType=Lowpass  Tc=40e-3  Ts=0  Initialize=on  Vac_Init=[0, 0, 50]  Vdc_Init=0  PlotResponse=off  FreqRange="[0,  200,  1]"
  Gain : Gain  Gain=2/(40e3)
  Gain1 : Gain  Gain=1/816.5
  Memory : Memory
  Mux : Mux  Inputs=3
  PID Controller : slpidlib/PID Controller  Controller=PI  Form=Parallel  TimeDomain=Discrete-time  UseExternalTs=off  SampleTime=-1  IntegratorMethod=Forward Euler  FilterMethod=Forward Euler  ControllerParametersSource=internal  P=0.02  I=50  UseKiTs=off  D=0  UseExternalDerivativeSource=off  N=100  UseFilter=on  TunerSelectOption=Transfer Function Based (PID Tuner App)  InitialConditionSource=internal  InitialConditionForIntegrator=0  InitialConditionForFilter=0  DifferentiatorICPrevScaledInput=0  ExternalReset=none  TrackingMode=off  Kt=1  LimitOutput=off  SatLimitsSource=internal  UpperSaturationLimit=inf  LowerSaturationLimit=-inf  LinearizeAsGain=on  AntiWindupMode=none  Kb=1  LimitIntegrator=off  UpperIntegratorSaturationLimit=inf  LowerIntegratorSaturationLimit=-inf  POutMin=[]  POutMax=[]  IOutMin=[]  IOutMax=[]  DOutMin=[]  DOutMax=[]  NOutMin=[]  NOutMax=[]  SumOutMin=[]  SumOutMax=[]  SaturationOutMin=[]  SaturationOutMax=[]  PParamMin=[]  PParamMax=[]  IParamMin=[]  IParamMax=[]  DParamMin=[]  DParamMax=[]  NParamMin=[]  NParamMax=[]  KbParamMin=[]  KbParamMax=[]  KtParamMin=[]  KtParamMax=[]  KbOutMin=[]  KbOutMax=[]  KtOutMin=[]  KtOutMax=[]  IntegratorOutMin=[]  IntegratorOutMax=[]  FilterOutMin=[]  FilterOutMax=[]  SumI1OutMin=[]  SumI1OutMax=[]  SumI2OutMin=[]  SumI2OutMax=[]  SumI3OutMin=[]  SumI3OutMax=[]  SumI4OutMin=[]  SumI4OutMax=[]  SumDOutMin=[]  SumDOutMax=[]  DifferentiatorOutMin=[]  DifferentiatorOutMax=[]  FilterDiffOutCoefMin=[]  FilterDiffOutCoefMax=[]  ReciprocalOutMin=[]  ReciprocalOutMax=[]  SumDenOutMin=[]  SumDenOutMax=[]  SumNumOutMin=[]  SumNumOutMax=[]  DivideOutMin=[]  DivideOutMax=[]  UdiffTsProdOutMin=[]  UdiffTsProdOutMax=[]  NTsProdOutMin=[]  NTsProdOutMax=[]  UintegralTsProdOutMin=[]  UintegralTsProdOutMax=[]  UngainTsProdOutMin=[]  UngainTsProdOutMax=[]  ClampingZeroOutDataTypeStr=Inherit: Inherit via back propagation  ClampingZeroOutMin=[]  ClampingZeroOutMax=[]  FilterDenConstantOutDataTypeStr=Inherit: Inherit via back propagation  FilterDenConstantOutMin=[]  FilterDenConstantOutMax=[]  PCopyOutDataTypeStr=Inherit: Inherit via back propagation  PCopyOutMin=[]  PCopyOutMax=[]  NCopyOutDataTypeStr=Inherit: Inherit via back propagation  NCopyOutMin=[]  NCopyOutMax=[]  IntegratorContinuousStateAttributes=''  IntegratorStateMustResolveToSignalObject=off  IntegratorRTWStateStorageClass=Auto  FilterContinuousStateAttributes=''  FilterStateMustResolveToSignalObject=off  FilterRTWStateStorageClass=Auto  ParallelPVariant=InternalParameters  IdealPVariant=Disabled  IVariant=InternalParameters  DVariant=Disabled  IntegratorVariant=Discrete  SatVariant=Disabled  AWVariant=Passthrough  PCopyVariant=Disabled  TRVariant=Disabled  FdbkBlocksVariant=Forward  IdealPFdbkVariant=Disabled  SatFdbkVariant=Disabled  DerivativeFilterVariant=Disabled  NVariant=Disabled  NCopyVariant=Disabled_SignalSpec  FilterICVariant=Disabled  IntegratorICVariant=InternalICs  ExternalResetVariant=Disabled  TRSumVariant=Passthrough  SumFdbkVariant=Disabled  SumVariant=Sum_PI  TsampFilterVariant=InternalTs  TsampNgainVariant=Passthrough  TsampIntegralVariant=Disabled_SignalSpec  ExternalSaturationOutDataTypeStr=Inherit: Same as second input  DerivativeSourceVariant=Disabled  PreIntVariant=InternalPreInt
  PID Controller1 : slpidlib/PID Controller  Controller=PI  Form=Parallel  TimeDomain=Discrete-time  UseExternalTs=off  SampleTime=-1  IntegratorMethod=Forward Euler  FilterMethod=Forward Euler  ControllerParametersSource=internal  P=0.1  I=10000/200  UseKiTs=off  D=0  UseExternalDerivativeSource=off  N=100  UseFilter=on  TunerSelectOption=Transfer Function Based (PID Tuner App)  InitialConditionSource=internal  InitialConditionForIntegrator=0  InitialConditionForFilter=0  DifferentiatorICPrevScaledInput=0  ExternalReset=none  TrackingMode=off  Kt=1  LimitOutput=on  SatLimitsSource=internal  UpperSaturationLimit=20e3  LowerSaturationLimit=-20e3  LinearizeAsGain=on  AntiWindupMode=none  Kb=1  LimitIntegrator=off  UpperIntegratorSaturationLimit=inf  LowerIntegratorSaturationLimit=-inf  POutMin=[]  POutMax=[]  IOutMin=[]  IOutMax=[]  DOutMin=[]  DOutMax=[]  NOutMin=[]  NOutMax=[]  SumOutMin=[]  SumOutMax=[]  SaturationOutMin=[]  SaturationOutMax=[]  PParamMin=[]  PParamMax=[]  IParamMin=[]  IParamMax=[]  DParamMin=[]  DParamMax=[]  NParamMin=[]  NParamMax=[]  KbParamMin=[]  KbParamMax=[]  KtParamMin=[]  KtParamMax=[]  KbOutMin=[]  KbOutMax=[]  KtOutMin=[]  KtOutMax=[]  IntegratorOutMin=[]  IntegratorOutMax=[]  FilterOutMin=[]  FilterOutMax=[]  SumI1OutMin=[]  SumI1OutMax=[]  SumI2OutMin=[]  SumI2OutMax=[]  SumI3OutMin=[]  SumI3OutMax=[]  SumI4OutMin=[]  SumI4OutMax=[]  SumDOutMin=[]  SumDOutMax=[]  DifferentiatorOutMin=[]  DifferentiatorOutMax=[]  FilterDiffOutCoefMin=[]  FilterDiffOutCoefMax=[]  ReciprocalOutMin=[]  ReciprocalOutMax=[]  SumDenOutMin=[]  SumDenOutMax=[]  SumNumOutMin=[]  SumNumOutMax=[]  DivideOutMin=[]  DivideOutMax=[]  UdiffTsProdOutMin=[]  UdiffTsProdOutMax=[]  NTsProdOutMin=[]  NTsProdOutMax=[]  UintegralTsProdOutMin=[]  UintegralTsProdOutMax=[]  UngainTsProdOutMin=[]  UngainTsProdOutMax=[]  ClampingZeroOutDataTypeStr=Inherit: Inherit via back propagation  ClampingZeroOutMin=[]  ClampingZeroOutMax=[]  FilterDenConstantOutDataTypeStr=Inherit: Inherit via back propagation  FilterDenConstantOutMin=[]  FilterDenConstantOutMax=[]  PCopyOutDataTypeStr=Inherit: Inherit via back propagation  PCopyOutMin=[]  PCopyOutMax=[]  NCopyOutDataTypeStr=Inherit: Inherit via back propagation  NCopyOutMin=[]  NCopyOutMax=[]  IntegratorContinuousStateAttributes=''  IntegratorStateMustResolveToSignalObject=off  IntegratorRTWStateStorageClass=Auto  FilterContinuousStateAttributes=''  FilterStateMustResolveToSignalObject=off  FilterRTWStateStorageClass=Auto  ParallelPVariant=InternalParameters  IdealPVariant=Disabled  IVariant=InternalParameters  DVariant=Disabled  IntegratorVariant=Discrete  SatVariant=Enabled  AWVariant=Passthrough  PCopyVariant=Disabled  TRVariant=Disabled  FdbkBlocksVariant=Forward  IdealPFdbkVariant=Disabled  SatFdbkVariant=Disabled  DerivativeFilterVariant=Disabled  NVariant=Disabled  NCopyVariant=Disabled_SignalSpec  FilterICVariant=Disabled  IntegratorICVariant=InternalICs  ExternalResetVariant=Disabled  TRSumVariant=Passthrough  SumFdbkVariant=Disabled  SumVariant=Sum_PI  TsampFilterVariant=InternalTs  TsampNgainVariant=Passthrough  TsampIntegralVariant=Disabled_SignalSpec  ExternalSaturationOutDataTypeStr=Inherit: Same as second input  DerivativeSourceVariant=Disabled  PreIntVariant=InternalPreInt
  PID Controller2 : slpidlib/PID Controller  Controller=PI  Form=Parallel  TimeDomain=Discrete-time  UseExternalTs=off  SampleTime=-1  IntegratorMethod=Forward Euler  FilterMethod=Forward Euler  ControllerParametersSource=internal  P=0.1  I=1000  UseKiTs=off  D=0  UseExternalDerivativeSource=off  N=100  UseFilter=on  TunerSelectOption=Transfer Function Based (PID Tuner App)  InitialConditionSource=internal  InitialConditionForIntegrator=0  InitialConditionForFilter=0  DifferentiatorICPrevScaledInput=0  ExternalReset=none  TrackingMode=off  Kt=1  LimitOutput=on  SatLimitsSource=internal  UpperSaturationLimit=20e3  LowerSaturationLimit=-20e3  LinearizeAsGain=on  AntiWindupMode=none  Kb=1  LimitIntegrator=off  UpperIntegratorSaturationLimit=inf  LowerIntegratorSaturationLimit=-inf  POutMin=[]  POutMax=[]  IOutMin=[]  IOutMax=[]  DOutMin=[]  DOutMax=[]  NOutMin=[]  NOutMax=[]  SumOutMin=[]  SumOutMax=[]  SaturationOutMin=[]  SaturationOutMax=[]  PParamMin=[]  PParamMax=[]  IParamMin=[]  IParamMax=[]  DParamMin=[]  DParamMax=[]  NParamMin=[]  NParamMax=[]  KbParamMin=[]  KbParamMax=[]  KtParamMin=[]  KtParamMax=[]  KbOutMin=[]  KbOutMax=[]  KtOutMin=[]  KtOutMax=[]  IntegratorOutMin=[]  IntegratorOutMax=[]  FilterOutMin=[]  FilterOutMax=[]  SumI1OutMin=[]  SumI1OutMax=[]  SumI2OutMin=[]  SumI2OutMax=[]  SumI3OutMin=[]  SumI3OutMax=[]  SumI4OutMin=[]  SumI4OutMax=[]  SumDOutMin=[]  SumDOutMax=[]  DifferentiatorOutMin=[]  DifferentiatorOutMax=[]  FilterDiffOutCoefMin=[]  FilterDiffOutCoefMax=[]  ReciprocalOutMin=[]  ReciprocalOutMax=[]  SumDenOutMin=[]  SumDenOutMax=[]  SumNumOutMin=[]  SumNumOutMax=[]  DivideOutMin=[]  DivideOutMax=[]  UdiffTsProdOutMin=[]  UdiffTsProdOutMax=[]  NTsProdOutMin=[]  NTsProdOutMax=[]  UintegralTsProdOutMin=[]  UintegralTsProdOutMax=[]  UngainTsProdOutMin=[]  UngainTsProdOutMax=[]  ClampingZeroOutDataTypeStr=Inherit: Inherit via back propagation  ClampingZeroOutMin=[]  ClampingZeroOutMax=[]  FilterDenConstantOutDataTypeStr=Inherit: Inherit via back propagation  FilterDenConstantOutMin=[]  FilterDenConstantOutMax=[]  PCopyOutDataTypeStr=Inherit: Inherit via back propagation  PCopyOutMin=[]  PCopyOutMax=[]  NCopyOutDataTypeStr=Inherit: Inherit via back propagation  NCopyOutMin=[]  NCopyOutMax=[]  IntegratorContinuousStateAttributes=''  IntegratorStateMustResolveToSignalObject=off  IntegratorRTWStateStorageClass=Auto  FilterContinuousStateAttributes=''  FilterStateMustResolveToSignalObject=off  FilterRTWStateStorageClass=Auto  ParallelPVariant=InternalParameters  IdealPVariant=Disabled  IVariant=InternalParameters  DVariant=Disabled  IntegratorVariant=Discrete  SatVariant=Enabled  AWVariant=Passthrough  PCopyVariant=Disabled  TRVariant=Disabled  FdbkBlocksVariant=Forward  IdealPFdbkVariant=Disabled  SatFdbkVariant=Disabled  DerivativeFilterVariant=Disabled  NVariant=Disabled  NCopyVariant=Disabled_SignalSpec  FilterICVariant=Disabled  IntegratorICVariant=InternalICs  ExternalResetVariant=Disabled  TRSumVariant=Passthrough  SumFdbkVariant=Disabled  SumVariant=Sum_PI  TsampFilterVariant=InternalTs  TsampNgainVariant=Passthrough  TsampIntegralVariant=Disabled_SignalSpec  ExternalSaturationOutDataTypeStr=Inherit: Same as second input  DerivativeSourceVariant=Disabled  PreIntVariant=InternalPreInt
  PID Controller3 : slpidlib/PID Controller  Commented=on  Controller=PI  Form=Parallel  TimeDomain=Discrete-time  UseExternalTs=off  SampleTime=-1  IntegratorMethod=Forward Euler  FilterMethod=Forward Euler  ControllerParametersSource=internal  P=50  I=5000  UseKiTs=off  D=0  UseExternalDerivativeSource=off  N=100  UseFilter=on  TunerSelectOption=Transfer Function Based (PID Tuner App)  InitialConditionSource=internal  InitialConditionForIntegrator=0  InitialConditionForFilter=0  DifferentiatorICPrevScaledInput=0  ExternalReset=none  TrackingMode=off  Kt=1  LimitOutput=on  SatLimitsSource=internal  UpperSaturationLimit=50e3  LowerSaturationLimit=-50e3  LinearizeAsGain=on  AntiWindupMode=none  Kb=1  LimitIntegrator=off  UpperIntegratorSaturationLimit=inf  LowerIntegratorSaturationLimit=-inf  POutMin=[]  POutMax=[]  IOutMin=[]  IOutMax=[]  DOutMin=[]  DOutMax=[]  NOutMin=[]  NOutMax=[]  SumOutMin=[]  SumOutMax=[]  SaturationOutMin=[]  SaturationOutMax=[]  PParamMin=[]  PParamMax=[]  IParamMin=[]  IParamMax=[]  DParamMin=[]  DParamMax=[]  NParamMin=[]  NParamMax=[]  KbParamMin=[]  KbParamMax=[]  KtParamMin=[]  KtParamMax=[]  KbOutMin=[]  KbOutMax=[]  KtOutMin=[]  KtOutMax=[]  IntegratorOutMin=[]  IntegratorOutMax=[]  FilterOutMin=[]  FilterOutMax=[]  SumI1OutMin=[]  SumI1OutMax=[]  SumI2OutMin=[]  SumI2OutMax=[]  SumI3OutMin=[]  SumI3OutMax=[]  SumI4OutMin=[]  SumI4OutMax=[]  SumDOutMin=[]  SumDOutMax=[]  DifferentiatorOutMin=[]  DifferentiatorOutMax=[]  FilterDiffOutCoefMin=[]  FilterDiffOutCoefMax=[]  ReciprocalOutMin=[]  ReciprocalOutMax=[]  SumDenOutMin=[]  SumDenOutMax=[]  SumNumOutMin=[]  SumNumOutMax=[]  DivideOutMin=[]  DivideOutMax=[]  UdiffTsProdOutMin=[]  UdiffTsProdOutMax=[]  NTsProdOutMin=[]  NTsProdOutMax=[]  UintegralTsProdOutMin=[]  UintegralTsProdOutMax=[]  UngainTsProdOutMin=[]  UngainTsProdOutMax=[]  ClampingZeroOutDataTypeStr=Inherit: Inherit via back propagation  ClampingZeroOutMin=[]  ClampingZeroOutMax=[]  FilterDenConstantOutDataTypeStr=Inherit: Inherit via back propagation  FilterDenConstantOutMin=[]  FilterDenConstantOutMax=[]  PCopyOutDataTypeStr=Inherit: Inherit via back propagation  PCopyOutMin=[]  PCopyOutMax=[]  NCopyOutDataTypeStr=Inherit: Inherit via back propagation  NCopyOutMin=[]  NCopyOutMax=[]  IntegratorContinuousStateAttributes=''  IntegratorStateMustResolveToSignalObject=off  IntegratorRTWStateStorageClass=Auto  FilterContinuousStateAttributes=''  FilterStateMustResolveToSignalObject=off  FilterRTWStateStorageClass=Auto  ParallelPVariant=InternalParameters  IdealPVariant=Disabled  IVariant=InternalParameters  DVariant=Disabled  IntegratorVariant=Discrete  SatVariant=Enabled  AWVariant=Passthrough  PCopyVariant=Disabled  TRVariant=Disabled  FdbkBlocksVariant=Forward  IdealPFdbkVariant=Disabled  SatFdbkVariant=Disabled  DerivativeFilterVariant=Disabled  NVariant=Disabled  NCopyVariant=Disabled_SignalSpec  FilterICVariant=Disabled  IntegratorICVariant=InternalICs  ExternalResetVariant=Disabled  TRSumVariant=Passthrough  SumFdbkVariant=Disabled  SumVariant=Sum_PI  TsampFilterVariant=InternalTs  TsampNgainVariant=Passthrough  TsampIntegralVariant=Disabled_SignalSpec  ExternalSaturationOutDataTypeStr=Inherit: Same as second input  DerivativeSourceVariant=Disabled  PreIntVariant=InternalPreInt
  Saturation : Saturate  UpperLimit=1  LowerLimit=-1
  Scope : Scope  NumInputPorts=2
  Scope1 : Scope  NumInputPorts=2
  Scope2 : Scope
  Scope3 : Scope
  Scope4 : Scope  NumInputPorts=2
  Scope5 : Scope
  Sum : Sum  Inputs=|-+
  Sum1 : Sum  Inputs=|+-
  Sum2 : Sum  Inputs=|+-
  Sum3 : Sum  Inputs=|+-
  Sum{4..6,8} (4 alike) : Sum  Inputs=|++
  Sum7 : Sum  Commented=on  Inputs=|-+
  Switch : Switch  Criteria=u2 > Threshold  Threshold=28
  Terminator{,1..3} (4 alike) : Terminator
  abc to dq0 : spsabctodq0Lib/abc to dq0  Alignment=90 degrees behind phase A axis
  abc to dq1 : spsabctodq0Lib/abc to dq0  Alignment=90 degrees behind phase A axis
  dq0 to abc : spsdq0toabcLib/dq0 to abc  Alignment=90 degrees behind phase A axis
  wL : Gain  Gain=0.314*0.1
  wL1 : Gain  Gain=0.314*0.1
  Pulses : Outport
  wt : Outport  Port=2
  Iq_droop : Outport  Port=3
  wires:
  abc to dq0/1 -> Demux/1
  Demux/3 -> Terminator/1
  Demux1/3 -> Terminator1/1
  abc to dq1/1 -> Demux1/1
  Iabc_B3/1 -> abc to dq1/1
  Constant/1 -> Sum/1
  Demux/2 -> [Vq], Scope2/1, Display/1  "Vq"
  Sum/1 -> PID Controller/1
  PID Controller/1 -> Discrete-Time Integrator/1, Sum8/1
  [wt] -> abc to dq1/2, abc to dq0/2
  Demux1/1 -> [Id]  "Id"
  Demux1/2 -> [Iq]  "Iq"
  [Id] -> Scope/2, Sum1/2
  Iqref/1 -> Scope4/1, Sum2/1
  [Iq] -> Sum2/2, Scope4/2
  Sum1/1 -> PID Controller1/1
  Sum2/1 -> PID Controller2/1
  PID Controller1/1 -> Sum3/1
  PID Controller2/1 -> Sum4/1
  wL1/1 -> Sum4/2
  wL/1 -> Sum3/2
  Sum3/1 -> Sum5/1
  [Vd] -> Sum5/2
  Sum4/1 -> Sum6/1
  [Vq] -> Sum6/2
  Mux/1 -> dq0 to abc/1
  Sum5/1 -> Mux/1  "ud"
  Sum6/1 -> Mux/2  "uq"
  Constant1/1 -> Mux/3
  [wt] -> dq0 to abc/2
  dq0 to abc/1 -> Gain/1
  Vabc_B3/1 -> abc to dq0/1
  Idref/1 -> Scope/1, Sum1/1
  [Id] -> wL1/1
  [Iq] -> wL/1
  [Vabc_B3] -> Gain1/1
  Demux2/3 -> Terminator2/1
  Demux2/2 -> Terminator3/1
  Demux2/1 -> Scope1/1
  Gain1/1 -> Demux2/1
  [wt] -> Cos/1
  Cos/1 -> Scope1/2
  Demux/1 -> [Vd]  "Vd"
  Gain/1 -> Saturation/1
  Memory/1 -> Pulses/1
  Discrete-Time Integrator/1 -> First-Order Filter/1, [wt], Scope5/1
  Saturation/1 -> Memory/1
  Sum7/1 -> PID Controller3/1
  Constant2/1 -> Sum7/2
  PID Controller3/1 -> Scope3/1, Iq_droop/1
  Vpcc/1 -> Sum7/1
  Constant3/1 -> Sum8/2
  Switch/1 -> Sum/2
  Constant4/1 -> Switch/3
  Clock/1 -> Switch/2
  [Vq] -> Switch/1
  First-Order Filter/1 -> wt/1

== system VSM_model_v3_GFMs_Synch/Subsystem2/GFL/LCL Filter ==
  Cf : spsSeriesRLCBranchLib/Series RLC Branch  LConnTagsString=__new0  RConnTagsString=__new0  BranchType=RC  Resistance=200  Inductance=0.0058  SetiL0=off  InitialCurrent=0  Capacitance=50e-6  Setx0=off  InitialVoltage=0  Measurements=None
  Cf1 : spsSeriesRLCBranchLib/Series RLC Branch  LConnTagsString=__new0  RConnTagsString=__new0  BranchType=RC  Resistance=200  Inductance=0.0058  SetiL0=off  InitialCurrent=0  Capacitance=50e-6  Setx0=off  InitialVoltage=0  Measurements=None
  Cf2 : spsSeriesRLCBranchLib/Series RLC Branch  LConnTagsString=__new0  RConnTagsString=__new0  BranchType=RC  Resistance=200  Inductance=0.0058  SetiL0=off  InitialCurrent=0  Capacitance=50e-6  Setx0=off  InitialVoltage=0  Measurements=None
  Ground : spsGroundLib/Ground  LConnTagsString=a
  Lg : spsSeriesRLCBranchLib/Series RLC Branch  LConnTagsString=__new0  RConnTagsString=__new0  BranchType=L  Resistance=0.2  Inductance=2e-3  SetiL0=off  InitialCurrent=0  Capacitance=1e-6  Setx0=off  InitialVoltage=0  Measurements=None
  Linv : spsSeriesRLCBranchLib/Series RLC Branch  LConnTagsString=__new0  RConnTagsString=__new0  BranchType=RL  Resistance=0.2  Inductance=0.1e-3  SetiL0=off  InitialCurrent=0  Capacitance=1e-6  Setx0=off  InitialVoltage=0  Measurements=None
  Series RLC Branch1 : spsSeriesRLCBranchLib/Series RLC Branch  LConnTagsString=__new0  RConnTagsString=__new0  BranchType=RL  Resistance=0.2  Inductance=0.1e-3  SetiL0=off  InitialCurrent=0  Capacitance=1e-6  Setx0=off  InitialVoltage=0  Measurements=None
  Series RLC Branch2 : spsSeriesRLCBranchLib/Series RLC Branch  LConnTagsString=__new0  RConnTagsString=__new0  BranchType=RL  Resistance=0.2  Inductance=0.1e-3  SetiL0=off  InitialCurrent=0  Capacitance=1e-6  Setx0=off  InitialVoltage=0  Measurements=None
  Series RLC Branch3 : spsSeriesRLCBranchLib/Series RLC Branch  LConnTagsString=__new0  RConnTagsString=__new0  BranchType=L  Resistance=0.2  Inductance=2e-3  SetiL0=off  InitialCurrent=0  Capacitance=1e-6  Setx0=off  InitialVoltage=0  Measurements=None
  Series RLC Branch4 : spsSeriesRLCBranchLib/Series RLC Branch  LConnTagsString=__new0  RConnTagsString=__new0  BranchType=L  Resistance=0.2  Inductance=2e-3  SetiL0=off  InitialCurrent=0  Capacitance=1e-6  Setx0=off  InitialVoltage=0  Measurements=None
  Three-Phase V-I Measurement : spsThreePhaseVIMeasurementLib/Three-Phase V-I Measurement  VoltageMeasurement=phase-to-phase  SetLabelV=on  LabelV=Vabc_B2  Vpu=off  VpuLL=off  CurrentMeasurement=no  SetLabelI=off  LabelI=Iabc  Ipu=off  Pbase=100e6  Vbase=500e3  OutputType=Complex  PhasorSimulation=off  PSBequivalent=0
  A : PMIOPort  Side=Left
  a : PMIOPort  Port=2  Side=Right
  B : PMIOPort  Port=3  Side=Left
  b : PMIOPort  Port=4  Side=Right
  C : PMIOPort  Port=5  Side=Left
  c : PMIOPort  Port=6  Side=Right
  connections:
  A/RConn1 -- Linv/LConn1
  B/RConn1 -- Series RLC Branch1/LConn1
  C/RConn1 -- Series RLC Branch2/LConn1
  Linv/RConn1 -- a/RConn1 -- Three-Phase V-I Measurement/LConn1
  Series RLC Branch2/RConn1 -- c/RConn1 -- Three-Phase V-I Measurement/LConn3
  Series RLC Branch1/RConn1 -- b/RConn1 -- Three-Phase V-I Measurement/LConn2
  Cf1/LConn1 -- Ground/LConn1 -- Cf/LConn1 -- Cf2/LConn1
  Cf/RConn1 -- Three-Phase V-I Measurement/RConn1
  Cf1/RConn1 -- Three-Phase V-I Measurement/RConn2
  Cf2/RConn1 -- Three-Phase V-I Measurement/RConn3

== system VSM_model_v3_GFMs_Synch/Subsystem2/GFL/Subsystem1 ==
  Clock : Clock
  Constant : Constant  Value=0
  Stair Generator : eeStairGenerator/Stair Generator  LabelModeActiveChoice=Continuous  TimeInput=[0 30]  AmplitudeInput=[0 60000]  SampleTime=0  RepeatPattern=off  OutDataTypeStr=double
  Switch : Switch  Criteria=u2 > Threshold  Threshold=30
  y : Outport
  Out2 : Outport  Port=2
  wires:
  Clock/1 -> Switch/2
  Stair Generator/1 -> y/1
  Switch/1 -> Out2/1
  Constant/1 -> Switch/3
  [Iq_droop] -> Switch/1

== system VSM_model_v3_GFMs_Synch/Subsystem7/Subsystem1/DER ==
  note: Term1-DC Voltage regulaiton Term2-feedforward (desired power) Term3-AC/DC power balance correciton Term4-Loss compensation (converter switching or filter resistor losses)
  note: i_dc
  P_ref_MW : Inport
  Enable : Inport  Port=2
  Iabc : Inport  Port=3
  Vabc : Inport  Port=4
  Add2 : Sum  Commented=on  Inputs=+-
  Add4 : Sum  Commented=on  Inputs=++++
  Add6 : Sum  Commented=on  Inputs=+-
  C_dc1 : spsSeriesRLCBranchLib/Series RLC Branch  Commented=on  LConnTagsString=__new0  RConnTagsString=__new0  BranchType=C  Resistance=1  Inductance=1e-3  SetiL0=off  InitialCurrent=0  Capacitance=C_dc  Setx0=off  InitialVoltage=Vdc_n  Measurements=None
  Clock : Clock
  Constant1 : Constant  Commented=on  Value=Vdc_n
  Current Measurement : spsCurrentMeasurementLib/Current Measurement  Commented=on  PhasorSimulation=off  OutputType=Complex  PSBequivalent=0
  DC Voltage Source : spsDCVoltageSourceLib/DC Voltage Source  Amplitude=Vdc_n_gfl  Measurements=None
  G_dc1 : spsSeriesRLCBranchLib/Series RLC Branch  Commented=on  LConnTagsString=__new0  RConnTagsString=__new0  BranchType=R  Resistance=R_dc  Inductance=1e-3  SetiL0=off  InitialCurrent=0  Capacitance=1e-6  Setx0=off  InitialVoltage=0  Measurements=None
  Gain : Gain  Gain=2/(Vdc_n_gfl)
  Gain1 : Gain  Gain=2/(Vdc_n_gfl)
  Gain13 : Gain  Commented=on  Gain=K_p
  Gain14 : Gain  Commented=on  Gain=K_p
  Gain16 : Gain  Commented=on  Gain=k_dc
  Gain17 : Gain  Commented=on  Gain=K_r
  Gain2 : Gain  Gain=2/(Vdc_n_gfl)
  LTI System3 : cstblocks/LTI System  Commented=on  sys=tf(1,[tau_dc 1])  IC=[]  PadeOrder=0
  Memory4 : Memory  Commented=on
  Mux : Mux  Inputs=3
  Saturation : Saturate  Commented=on  UpperLimit=i_ul  LowerLimit=i_ll
  Scope : Scope
  Scope1 : Scope
  Subsystem : Subsystem
  Subsystem1 : Subsystem
  Switch : Switch  Commented=on  Criteria=u2 > Threshold  Threshold=T_en
  Transfer Fcn2 : TransferFcn  Commented=on  Numerator=[w_f]  Denominator=[1 w_f]
  Unit Delay : UnitDelay  SampleTime=-1  HasFrameUpgradeWarning=on
  Universal Bridge : spsUniversalBridgeLib/Universal Bridge  Arms=3  SnubberResistance=1e5  SnubberCapacitance=inf  Device=Average-model based VSC  Ron=1e-3  Lon=0  ForwardVoltages="[  0  0  ]"  ForwardVoltage=0  GTOparameters=[ 10e-6 , 20e-6 ]  IGBTparameters=[ 1e-6 , 2e-6 ]  Measurements=None  Measurements_2=None  converterType=Rectifier
  Voltage Measurement : spsVoltageMeasurementLib/Voltage Measurement  Commented=on  PhasorSimulation=off  OutputType=Complex  PSBequivalent=0
  i_dc1 : spsControlledCurrentSourceLib/Controlled Current Source  Commented=on  Initialize=off  Source_Type=DC  Amplitude=i_dc  Phase=0  Frequency=0  Measurements=None
  A : PMIOPort  Side=Right
  B : PMIOPort  Port=2  Side=Right
  C : PMIOPort  Port=3  Side=Right
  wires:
  [v_dc] -> Gain17/1
  [P_s_abc] -> Add2/1
  Add6/1 -> Gain16/1
  [v_dc] -> Add6/2
  Transfer Fcn2/1 -> Gain14/1
  Add2/1 -> Transfer Fcn2/1
  Gain17/1 -> Add4/3
  Constant1/1 -> Add6/1
  Gain16/1 -> Add4/1
  Gain13/1 -> Add4/2
  [P_set] -> Gain13/1
  Gain14/1 -> Add4/4
  [P_abc] -> Add2/2
  Switch/1 -> i_dc1/1
  Memory4/1 -> [v_dc]
  Voltage Measurement/1 -> Memory4/1
  LTI System3/1 -> Saturation/1, Switch/3
  Saturation/1 -> Switch/1
  Clock/1 -> Switch/2
  Add4/1 -> LTI System3/1
  Current Measurement/1 -> [i_dc_s]
  Gain/1 -> Mux/1
  Gain1/1 -> Mux/2
  Gain2/1 -> Mux/3
  Mux/1 -> Unit Delay/1, Scope/1
  P_ref_MW/1 -> Subsystem1/1(P_ref_MW)
  Subsystem1/1(Varef) -> Gain/1
  Subsystem1/2(Vbref) -> Gain1/1
  Subsystem1/3(Vcref) -> Gain2/1
  Enable/1 -> Subsystem1/Enable
  Subsystem1/4(wt) -> Scope1/1
  Iabc/1 -> Subsystem1/2(Iabc)
  Vabc/1 -> Subsystem1/3(Vabc)
  Unit Delay/1 -> Universal Bridge/1
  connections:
  i_dc1/LConn1 -- G_dc1/RConn1 -- Voltage Measurement/LConn2 -- C_dc1/RConn1
  G_dc1/LConn1 -- Voltage Measurement/LConn1 -- C_dc1/LConn1 -- Current Measurement/RConn1
  i_dc1/RConn1 -- Current Measurement/LConn1
  Subsystem/RConn1 -- Universal Bridge/LConn1
  Subsystem/RConn2 -- Universal Bridge/LConn2
  Subsystem/RConn3 -- Universal Bridge/LConn3
  DC Voltage Source/RConn1 -- Universal Bridge/RConn1
  DC Voltage Source/LConn1 -- Universal Bridge/RConn2
  A/RConn1 -- Subsystem/LConn1
  B/RConn1 -- Subsystem/LConn2
  C/RConn1 -- Subsystem/LConn3

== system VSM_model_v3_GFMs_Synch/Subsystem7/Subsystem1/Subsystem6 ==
  Vabc_PCC : Inport
  Vabc_DER : Inport  Port=2
  S-R Flip-Flop : simulink_extras/Flip Flops/S-R Flip-Flop  initial_condition=0
  Subsystem5 : Subsystem
  close_signal : Outport
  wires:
  Vabc_PCC/1 -> Subsystem5/1(abc)
  Vabc_DER/1 -> Subsystem5/2(abc1)
  Subsystem5/1(close_signal) -> S-R Flip-Flop/1
  S-R Flip-Flop/1 -> close_signal/1

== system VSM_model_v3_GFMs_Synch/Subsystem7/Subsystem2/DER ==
  note: Term1-DC Voltage regulaiton Term2-feedforward (desired power) Term3-AC/DC power balance correciton Term4-Loss compensation (converter switching or filter resistor losses)
  note: i_dc
  P_ref_MW : Inport
  Enable : Inport  Port=2
  Iabc : Inport  Port=3
  Vabc : Inport  Port=4
  Add2 : Sum  Commented=on  Inputs=+-
  Add4 : Sum  Commented=on  Inputs=++++
  Add6 : Sum  Commented=on  Inputs=+-
  C_dc1 : spsSeriesRLCBranchLib/Series RLC Branch  Commented=on  LConnTagsString=__new0  RConnTagsString=__new0  BranchType=C  Resistance=1  Inductance=1e-3  SetiL0=off  InitialCurrent=0  Capacitance=C_dc  Setx0=off  InitialVoltage=Vdc_n  Measurements=None
  Clock : Clock
  Constant1 : Constant  Commented=on  Value=Vdc_n
  Current Measurement : spsCurrentMeasurementLib/Current Measurement  Commented=on  PhasorSimulation=off  OutputType=Complex  PSBequivalent=0
  DC Voltage Source : spsDCVoltageSourceLib/DC Voltage Source  Amplitude=Vdc_n_gfl  Measurements=None
  G_dc1 : spsSeriesRLCBranchLib/Series RLC Branch  Commented=on  LConnTagsString=__new0  RConnTagsString=__new0  BranchType=R  Resistance=R_dc  Inductance=1e-3  SetiL0=off  InitialCurrent=0  Capacitance=1e-6  Setx0=off  InitialVoltage=0  Measurements=None
  Gain : Gain  Gain=2/(Vdc_n_gfl)
  Gain1 : Gain  Gain=2/(Vdc_n_gfl)
  Gain13 : Gain  Commented=on  Gain=K_p
  Gain14 : Gain  Commented=on  Gain=K_p
  Gain16 : Gain  Commented=on  Gain=k_dc
  Gain17 : Gain  Commented=on  Gain=K_r
  Gain2 : Gain  Gain=2/(Vdc_n_gfl)
  LTI System3 : cstblocks/LTI System  Commented=on  sys=tf(1,[tau_dc 1])  IC=[]  PadeOrder=0
  Memory4 : Memory  Commented=on
  Mux : Mux  Inputs=3
  Saturation : Saturate  Commented=on  UpperLimit=i_ul  LowerLimit=i_ll
  Scope : Scope
  Scope1 : Scope
  Subsystem : Subsystem
  Subsystem1 : Subsystem
  Switch : Switch  Commented=on  Criteria=u2 > Threshold  Threshold=T_en
  Transfer Fcn2 : TransferFcn  Commented=on  Numerator=[w_f]  Denominator=[1 w_f]
  Unit Delay : UnitDelay  SampleTime=-1  HasFrameUpgradeWarning=on
  Universal Bridge : spsUniversalBridgeLib/Universal Bridge  Arms=3  SnubberResistance=1e5  SnubberCapacitance=inf  Device=Average-model based VSC  Ron=1e-3  Lon=0  ForwardVoltages="[  0  0  ]"  ForwardVoltage=0  GTOparameters=[ 10e-6 , 20e-6 ]  IGBTparameters=[ 1e-6 , 2e-6 ]  Measurements=None  Measurements_2=None  converterType=Rectifier
  Voltage Measurement : spsVoltageMeasurementLib/Voltage Measurement  Commented=on  PhasorSimulation=off  OutputType=Complex  PSBequivalent=0
  i_dc1 : spsControlledCurrentSourceLib/Controlled Current Source  Commented=on  Initialize=off  Source_Type=DC  Amplitude=i_dc  Phase=0  Frequency=0  Measurements=None
  A : PMIOPort  Side=Right
  B : PMIOPort  Port=2  Side=Right
  C : PMIOPort  Port=3  Side=Right
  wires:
  [v_dc] -> Gain17/1
  [P_s_abc] -> Add2/1
  Add6/1 -> Gain16/1
  [v_dc] -> Add6/2
  Transfer Fcn2/1 -> Gain14/1
  Add2/1 -> Transfer Fcn2/1
  Gain17/1 -> Add4/3
  Constant1/1 -> Add6/1
  Gain16/1 -> Add4/1
  Gain13/1 -> Add4/2
  [P_set] -> Gain13/1
  Gain14/1 -> Add4/4
  [P_abc] -> Add2/2
  Switch/1 -> i_dc1/1
  Memory4/1 -> [v_dc]
  Voltage Measurement/1 -> Memory4/1
  LTI System3/1 -> Saturation/1, Switch/3
  Saturation/1 -> Switch/1
  Clock/1 -> Switch/2
  Add4/1 -> LTI System3/1
  Current Measurement/1 -> [i_dc_s]
  Gain/1 -> Mux/1
  Gain1/1 -> Mux/2
  Gain2/1 -> Mux/3
  Mux/1 -> Unit Delay/1, Scope/1
  P_ref_MW/1 -> Subsystem1/1(P_ref_MW)
  Subsystem1/1(Varef) -> Gain/1
  Subsystem1/2(Vbref) -> Gain1/1
  Subsystem1/3(Vcref) -> Gain2/1
  Enable/1 -> Subsystem1/Enable
  Subsystem1/4(wt) -> Scope1/1
  Iabc/1 -> Subsystem1/2(Iabc)
  Vabc/1 -> Subsystem1/3(Vabc)
  Unit Delay/1 -> Universal Bridge/1
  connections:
  i_dc1/LConn1 -- G_dc1/RConn1 -- Voltage Measurement/LConn2 -- C_dc1/RConn1
  G_dc1/LConn1 -- Voltage Measurement/LConn1 -- C_dc1/LConn1 -- Current Measurement/RConn1
  i_dc1/RConn1 -- Current Measurement/LConn1
  Subsystem/RConn1 -- Universal Bridge/LConn1
  Subsystem/RConn2 -- Universal Bridge/LConn2
  Subsystem/RConn3 -- Universal Bridge/LConn3
  DC Voltage Source/RConn1 -- Universal Bridge/RConn1
  DC Voltage Source/LConn1 -- Universal Bridge/RConn2
  A/RConn1 -- Subsystem/LConn1
  B/RConn1 -- Subsystem/LConn2
  C/RConn1 -- Subsystem/LConn3

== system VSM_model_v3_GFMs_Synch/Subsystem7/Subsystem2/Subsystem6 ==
  Vabc_PCC : Inport
  Vabc_DER : Inport  Port=2
  S-R Flip-Flop : simulink_extras/Flip Flops/S-R Flip-Flop  initial_condition=0
  Subsystem5 : Subsystem
  close_signal : Outport
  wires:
  Vabc_PCC/1 -> Subsystem5/1(abc)
  Vabc_DER/1 -> Subsystem5/2(abc1)
  Subsystem5/1(close_signal) -> S-R Flip-Flop/1
  S-R Flip-Flop/1 -> close_signal/1

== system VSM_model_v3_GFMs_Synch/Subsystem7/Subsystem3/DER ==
  note: Term1-DC Voltage regulaiton Term2-feedforward (desired power) Term3-AC/DC power balance correciton Term4-Loss compensation (converter switching or filter resistor losses)
  note: i_dc
  P_ref_MW : Inport
  Enable : Inport  Port=2
  Iabc : Inport  Port=3
  Vabc : Inport  Port=4
  Add2 : Sum  Commented=on  Inputs=+-
  Add4 : Sum  Commented=on  Inputs=++++
  Add6 : Sum  Commented=on  Inputs=+-
  C_dc1 : spsSeriesRLCBranchLib/Series RLC Branch  Commented=on  LConnTagsString=__new0  RConnTagsString=__new0  BranchType=C  Resistance=1  Inductance=1e-3  SetiL0=off  InitialCurrent=0  Capacitance=C_dc  Setx0=off  InitialVoltage=Vdc_n  Measurements=None
  Clock : Clock
  Constant1 : Constant  Commented=on  Value=Vdc_n
  Current Measurement : spsCurrentMeasurementLib/Current Measurement  Commented=on  PhasorSimulation=off  OutputType=Complex  PSBequivalent=0
  DC Voltage Source : spsDCVoltageSourceLib/DC Voltage Source  Amplitude=Vdc_n_gfl  Measurements=None
  G_dc1 : spsSeriesRLCBranchLib/Series RLC Branch  Commented=on  LConnTagsString=__new0  RConnTagsString=__new0  BranchType=R  Resistance=R_dc  Inductance=1e-3  SetiL0=off  InitialCurrent=0  Capacitance=1e-6  Setx0=off  InitialVoltage=0  Measurements=None
  Gain : Gain  Gain=2/(Vdc_n_gfl)
  Gain1 : Gain  Gain=2/(Vdc_n_gfl)
  Gain13 : Gain  Commented=on  Gain=K_p
  Gain14 : Gain  Commented=on  Gain=K_p
  Gain16 : Gain  Commented=on  Gain=k_dc
  Gain17 : Gain  Commented=on  Gain=K_r
  Gain2 : Gain  Gain=2/(Vdc_n_gfl)
  LTI System3 : cstblocks/LTI System  Commented=on  sys=tf(1,[tau_dc 1])  IC=[]  PadeOrder=0
  Memory4 : Memory  Commented=on
  Mux : Mux  Inputs=3
  Saturation : Saturate  Commented=on  UpperLimit=i_ul  LowerLimit=i_ll
  Scope : Scope
  Scope1 : Scope
  Subsystem : Subsystem
  Subsystem1 : Subsystem
  Switch : Switch  Commented=on  Criteria=u2 > Threshold  Threshold=T_en
  Transfer Fcn2 : TransferFcn  Commented=on  Numerator=[w_f]  Denominator=[1 w_f]
  Unit Delay : UnitDelay  SampleTime=-1  HasFrameUpgradeWarning=on
  Universal Bridge : spsUniversalBridgeLib/Universal Bridge  Arms=3  SnubberResistance=1e5  SnubberCapacitance=inf  Device=Average-model based VSC  Ron=1e-3  Lon=0  ForwardVoltages="[  0  0  ]"  ForwardVoltage=0  GTOparameters=[ 10e-6 , 20e-6 ]  IGBTparameters=[ 1e-6 , 2e-6 ]  Measurements=None  Measurements_2=None  converterType=Rectifier
  Voltage Measurement : spsVoltageMeasurementLib/Voltage Measurement  Commented=on  PhasorSimulation=off  OutputType=Complex  PSBequivalent=0
  i_dc1 : spsControlledCurrentSourceLib/Controlled Current Source  Commented=on  Initialize=off  Source_Type=DC  Amplitude=i_dc  Phase=0  Frequency=0  Measurements=None
  A : PMIOPort  Side=Right
  B : PMIOPort  Port=2  Side=Right
  C : PMIOPort  Port=3  Side=Right
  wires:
  [v_dc] -> Gain17/1
  [P_s_abc] -> Add2/1
  Add6/1 -> Gain16/1
  [v_dc] -> Add6/2
  Transfer Fcn2/1 -> Gain14/1
  Add2/1 -> Transfer Fcn2/1
  Gain17/1 -> Add4/3
  Constant1/1 -> Add6/1
  Gain16/1 -> Add4/1
  Gain13/1 -> Add4/2
  [P_set] -> Gain13/1
  Gain14/1 -> Add4/4
  [P_abc] -> Add2/2
  Switch/1 -> i_dc1/1
  Memory4/1 -> [v_dc]
  Voltage Measurement/1 -> Memory4/1
  LTI System3/1 -> Saturation/1, Switch/3
  Saturation/1 -> Switch/1
  Clock/1 -> Switch/2
  Add4/1 -> LTI System3/1
  Current Measurement/1 -> [i_dc_s]
  Gain/1 -> Mux/1
  Gain1/1 -> Mux/2
  Gain2/1 -> Mux/3
  Mux/1 -> Unit Delay/1, Scope/1
  P_ref_MW/1 -> Subsystem1/1(P_ref_MW)
  Subsystem1/1(Varef) -> Gain/1
  Subsystem1/2(Vbref) -> Gain1/1
  Subsystem1/3(Vcref) -> Gain2/1
  Enable/1 -> Subsystem1/Enable
  Subsystem1/4(wt) -> Scope1/1
  Iabc/1 -> Subsystem1/2(Iabc)
  Vabc/1 -> Subsystem1/3(Vabc)
  Unit Delay/1 -> Universal Bridge/1
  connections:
  i_dc1/LConn1 -- G_dc1/RConn1 -- Voltage Measurement/LConn2 -- C_dc1/RConn1
  G_dc1/LConn1 -- Voltage Measurement/LConn1 -- C_dc1/LConn1 -- Current Measurement/RConn1
  i_dc1/RConn1 -- Current Measurement/LConn1
  Subsystem/RConn1 -- Universal Bridge/LConn1
  Subsystem/RConn2 -- Universal Bridge/LConn2
  Subsystem/RConn3 -- Universal Bridge/LConn3
  DC Voltage Source/RConn1 -- Universal Bridge/RConn1
  DC Voltage Source/LConn1 -- Universal Bridge/RConn2
  A/RConn1 -- Subsystem/LConn1
  B/RConn1 -- Subsystem/LConn2
  C/RConn1 -- Subsystem/LConn3

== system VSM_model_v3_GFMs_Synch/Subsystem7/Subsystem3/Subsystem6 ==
  Vabc_PCC : Inport
  Vabc_DER : Inport  Port=2
  S-R Flip-Flop : simulink_extras/Flip Flops/S-R Flip-Flop  initial_condition=0
  Subsystem5 : Subsystem
  close_signal : Outport
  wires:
  Vabc_PCC/1 -> Subsystem5/1(abc)
  Vabc_DER/1 -> Subsystem5/2(abc1)
  Subsystem5/1(close_signal) -> S-R Flip-Flop/1
  S-R Flip-Flop/1 -> close_signal/1

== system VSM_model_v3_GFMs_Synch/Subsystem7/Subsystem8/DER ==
  P_ref_MW : Inport
  Enable : Inport  Port=2
  Iabc : Inport  Port=3
  Vabc : Inport  Port=4
  DC Voltage Source : spsDCVoltageSourceLib/DC Voltage Source  Amplitude=Vdc_n_gfl  Measurements=None
  Gain : Gain  Gain=2/(Vdc_n_gfl)
  Gain1 : Gain  Gain=2/(Vdc_n_gfl)
  Gain2 : Gain  Gain=2/(Vdc_n_gfl)
  Mux : Mux  Inputs=3
  Scope : Scope
  Scope1 : Scope
  Subsystem : Subsystem
  Subsystem1 : Subsystem
  Unit Delay : UnitDelay  SampleTime=-1  HasFrameUpgradeWarning=on
  Universal Bridge : spsUniversalBridgeLib/Universal Bridge  Arms=3  SnubberResistance=1e5  SnubberCapacitance=inf  Device=Average-model based VSC  Ron=1e-3  Lon=0  ForwardVoltages="[  0  0  ]"  ForwardVoltage=0  GTOparameters=[ 10e-6 , 20e-6 ]  IGBTparameters=[ 1e-6 , 2e-6 ]  Measurements=None  Measurements_2=None  converterType=Rectifier
  A : PMIOPort  Side=Right
  B : PMIOPort  Port=2  Side=Right
  C : PMIOPort  Port=3  Side=Right
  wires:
  Gain/1 -> Mux/1
  Gain1/1 -> Mux/2
  Gain2/1 -> Mux/3
  Mux/1 -> Unit Delay/1, Scope/1
  P_ref_MW/1 -> Subsystem1/1(P_ref_MW)
  Subsystem1/1(Varef) -> Gain/1
  Subsystem1/2(Vbref) -> Gain1/1
  Subsystem1/3(Vcref) -> Gain2/1
  Enable/1 -> Subsystem1/Enable
  Subsystem1/4(wt) -> Scope1/1
  Iabc/1 -> Subsystem1/2(Iabc)
  Vabc/1 -> Subsystem1/3(Vabc)
  Unit Delay/1 -> Universal Bridge/1
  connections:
  Subsystem/RConn1 -- Universal Bridge/LConn1
  Subsystem/RConn2 -- Universal Bridge/LConn2
  Subsystem/RConn3 -- Universal Bridge/LConn3
  DC Voltage Source/RConn1 -- Universal Bridge/RConn1
  DC Voltage Source/LConn1 -- Universal Bridge/RConn2
  A/RConn1 -- Subsystem/LConn1
  B/RConn1 -- Subsystem/LConn2
  C/RConn1 -- Subsystem/LConn3

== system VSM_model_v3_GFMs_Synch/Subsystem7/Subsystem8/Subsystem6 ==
  Vabc_PCC : Inport
  Vabc_DER : Inport  Port=2
  S-R Flip-Flop : simulink_extras/Flip Flops/S-R Flip-Flop  initial_condition=0
  Subsystem5 : Subsystem
  close_signal : Outport
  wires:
  Vabc_PCC/1 -> Subsystem5/1(abc)
  Vabc_DER/1 -> Subsystem5/2(abc1)
  Subsystem5/1(close_signal) -> S-R Flip-Flop/1
  S-R Flip-Flop/1 -> close_signal/1

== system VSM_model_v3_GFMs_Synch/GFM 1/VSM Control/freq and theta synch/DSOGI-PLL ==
  abc : Inport
  1 : Constant  Value=0
  Demux2 : Demux  Outputs=2
  K : Gain  Gain=0.5
  K1 : Gain  Gain=0.5
  Mux15 : Mux  Inputs=2
  Mux2 : Mux  Inputs=2
  SOGI-QSG1 : Subsystem
  SOGI-QSG2 : Subsystem
  SRF-PLL : Subsystem
  Sum1 : Sum  Inputs=|+-
  Sum2 : Sum  Inputs=|++
  abc to alpha-beta : Subsystem
  hr : Gain
  Valp_bet+ : Outport  VectorParamsAs1DForOutWhenUnconnected=off
  w_pcc : Outport  Port=2  VectorParamsAs1DForOutWhenUnconnected=off
  theta_pcc : Outport  Port=3  VectorParamsAs1DForOutWhenUnconnected=off
  f : Outport  Port=4  VectorParamsAs1DForOutWhenUnconnected=off
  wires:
  abc/1 -> abc to alpha-beta/1(abc)
  SOGI-QSG1/1(vad) -> Sum1/1
  Demux2/1 -> SOGI-QSG1/1(Va)
  abc to alpha-beta/1(al_be) -> Demux2/1
  Demux2/2 -> SOGI-QSG2/2(Vb)
  SOGI-QSG2/1(vbd) -> Sum2/2
  SOGI-QSG2/2(vbq) -> Sum1/2
  Sum1/1 -> K/1
  K/1 -> Mux2/1
  SOGI-QSG1/2(vaq) -> Sum2/1
  Sum2/1 -> K1/1
  K1/1 -> Mux2/2
  SRF-PLL/1(theta_pcc) -> theta_pcc/1
  SRF-PLL/2(f) -> hr/1, f/1
  Mux15/1 -> SRF-PLL/1(al-be-0)
  1/1 -> Mux15/2
  Mux2/1 -> Valp_bet+/1, Mux15/1
  hr/1 -> SOGI-QSG1/2(f), SOGI-QSG2/1(f)
  SRF-PLL/3(w_pcc) -> w_pcc/1

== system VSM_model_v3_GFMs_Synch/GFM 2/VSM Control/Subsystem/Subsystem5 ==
  Vpcc_1 : Inport
  Vpcc_2 : Inport  Port=2
  Clock : Clock
  Data Type Conversion : DataTypeConversion  OutDataTypeStr=boolean
  Demux : Demux  Outputs=3
  Demux1 : Demux  Outputs=3
  Display{,1..4} (5 alike) : Display
  Gain : Gain  Gain=1/V_b
  Gain1 : Gain  Gain=1/V_b
  MATLAB Function : MATLAB Function  TreatAsAtomicUnit=on
  Math Function{,1..3} (4 alike) : Math  Operator=magnitude^2
  PLL (3ph)1 : spsPLL3phLib/PLL (3ph)  Fmin=10  Par_Init=[0, 50]  ParK=[180, 3200, 1]  TcD=1e-4  MaxRateChangeFreq=20  FilterCutOffFreq=25  Ts=0  AGC=on
  PLL (3ph)2 : spsPLL3phLib/PLL (3ph)  Fmin=10  Par_Init=[0, 50]  ParK=[180, 3200, 1]  TcD=1e-4  MaxRateChangeFreq=20  FilterCutOffFreq=25  Ts=0  AGC=on
  Scope : Scope  NumInputPorts=3
  Scope1 : Scope
  Sqrt : Sqrt
  Sqrt1 : Sqrt
  Sum : Sum  Inputs=|++
  Sum1 : Sum  Inputs=|++
  Terminator : Terminator
  Terminator1 : Terminator
  abc to dq0 : spsabctodq0Lib/abc to dq0  Alignment=90 degrees behind phase A axis
  abc to dq1 : spsabctodq0Lib/abc to dq0  Alignment=90 degrees behind phase A axis
  close_signal : Outport
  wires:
  PLL (3ph)1/1 -> MATLAB Function/5(w1)
  PLL (3ph)1/2 -> MATLAB Function/3(theta1), abc to dq0/2
  PLL (3ph)2/2 -> abc to dq1/2, MATLAB Function/4(theta2)
  PLL (3ph)2/1 -> MATLAB Function/6(w2)
  abc to dq0/1 -> Demux/1
  Demux/1 -> Math Function/1
  Demux/2 -> Math Function2/1
  Math Function/1 -> Sum/1
  Math Function2/1 -> Sum/2
  Sum/1 -> Sqrt/1
  Demux/3 -> Terminator/1
  Demux1/1 -> Math Function1/1
  abc to dq1/1 -> Demux1/1
  Sum1/1 -> Sqrt1/1
  Demux1/2 -> Math Function3/1
  Demux1/3 -> Terminator1/1
  Math Function1/1 -> Sum1/1
  Math Function3/1 -> Sum1/2
  Sqrt1/1 -> Gain1/1
  MATLAB Function/2(delta_V) -> Scope/1, Display/1
  MATLAB Function/3(delta_theta) -> Scope/2, Display1/1
  MATLAB Function/4(delta_w) -> Scope/3, Display2/1
  Sqrt/1 -> Gain/1
  Gain/1 -> Display3/1, MATLAB Function/1(V1)
  Gain1/1 -> Display4/1, MATLAB Function/2(V2)
  MATLAB Function/1(close_signal) -> Data Type Conversion/1
  Clock/1 -> MATLAB Function/7(t)
  Data Type Conversion/1 -> Scope1/1, close_signal/1
  Vpcc_2/1 -> abc to dq1/1, PLL (3ph)2/1
  Vpcc_1/1 -> abc to dq0/1, PLL (3ph)1/1
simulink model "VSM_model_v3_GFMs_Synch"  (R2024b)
settings: Solver=ode23tb  StartTime=0.0  StopTime=Tend  FixedStep=T_s  RelTol=1e-3  EnableMultiTasking=on
PostLoadFcn:
  | Tcontrol=20e-6;
InitFcn:
  | Tcontrol=20e-6;
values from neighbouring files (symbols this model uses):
  C_4 = 0.1670*C_b    (= 1.00487241952e-06)    [VSM.m]    (also in VSM_CSIRO.m)
  C_6 = 0.2835*C_b    (= 1.70587623314e-06)    [VSM.m]    (also in VSM_CSIRO.m)
  C_8 = 0.2275*C_b    (= 1.36891302659e-06)    [VSM.m]    (also in VSM_CSIRO.m)
  C_dc = 0.008*(n)    (= 1.6)    [VSM.m]    (also in VSM_CSIRO.m)
  C_f = n*300*10^-6    (= 0.06)    [VSM.m]    (also in VSM_CSIRO.m)
  C_f_gfl = (n_gfl) * Cf_unit_gfl    (= 0.00350140874802)    [DER_param.m]
  D_p = (1/(m_p*w_b))    (= 101321.183642)    [VSM.m]    (also in VSM_CSIRO.m)
  droop_percentage = 5    [VSM.m]    (also in VSM_CSIRO.m = 1)
  I_b_dc = S_b/Vdc_n    [VSM.m]    (also in VSM_CSIRO.m)
  I_b_LV_peak = I_b_LV * sqrt(2)    [VSM.m]
  I_b_SG_peak = I_b_SG * sqrt(2)    [VSM.m]
  i_ll = -1.15*(S_b/Vdc_n)-i_loss_dc    [VSM.m]    (also in VSM_CSIRO.m)
  i_ul = 1.15*(S_b/Vdc_n)+i_loss_dc    [VSM.m]    (also in VSM_CSIRO.m)
  J = D_p*tau_f    (= 2026.42367285)    [VSM.m]    (also in VSM_CSIRO.m)
  k_dc = eta_1/(Vdc_n*m_p)    [VSM.m]    (also in VSM_CSIRO.m)
  K_p = (1/Vdc_n)    [VSM.m]    (also in VSM_CSIRO.m)
  K_r = 1/R_dc    [VSM.m]    (also in VSM_CSIRO.m)
  Kff_i = 1    [VSM.m]    (also in VSM_CSIRO.m)
  Kff_v = 1    [VSM.m]    (also in VSM_CSIRO.m)
  Ki_i = (1/n)*1.19    (= 0.00595)    [VSM.m]    (also in VSM_CSIRO.m)
  Ki_i_gfl = (1/n_gfl) * Ki_i_unit_gfl    (= 0.571198664289)    [DER_param.m]
  Ki_v = (n)*1.161022    (= 232.2044)    [VSM.m]    (also in VSM_CSIRO.m)
  ki_v_ac = 4*5.2500e-04    (= 0.0021)    [VSM.m]    (also in VSM_CSIRO.m)
  Kp_i = 0.738891    [VSM.m]    (also in VSM_CSIRO.m)
  Kp_i_gfl = (1/n_gfl) * Kp_i_unit_gfl    (= 0.00909090909091)    [DER_param.m]
  Kp_v = 0.52    [VSM.m]    (also in VSM_CSIRO.m)
  kp_v_ac = 0.001    [VSM.m]    (also in VSM_CSIRO.m)
  L1_f_gfl = (1/n_gfl) * L1_unit_gfl    (= 1.44686311902e-05)    [DER_param.m]
  L1_pu = 1*0.0186/m    (= 0.000186)    [VSM.m]    (also in VSM_CSIRO.m)
  L1_pu_gfl = 0.03    [DER_param.m]
  L2_f_gfl = (1/n_gfl) * L2_unit_gfl    (= 2.89372623803e-06)    [DER_param.m]
  L2_pu_gfl = 0.03    [DER_param.m]
  L_45 = L_lines(2)    [VSM.m]    (also in VSM_CSIRO.m)
  L_56 = L_lines(3)    [VSM.m]    (also in VSM_CSIRO.m)
  L_67 = L_lines(5)    [VSM.m]    (also in VSM_CSIRO.m)
  L_78 = L_lines(6)    [VSM.m]    (also in VSM_CSIRO.m)
  L_89 = L_lines(8)    [VSM.m]    (also in VSM_CSIRO.m)
  L_94 = L_lines(9)    [VSM.m]    (also in VSM_CSIRO.m)
  L_f = (1/n)*200*10^-6    (= 1e-06)    [VSM.m]    (also in VSM_CSIRO.m)
  Lg = (X_BY_R_gfl * Rg) / wn_gfl    [DER_param.m]    (also in initialcondition_gfm_Pooyan.m = X_BY_R*Rg/(wn); initialcondition_Pooyan.m = X_BY_R*Rg/(wn))
  n = 200    [VSM.m]    (also in VSM_CSIRO.m)
  Pgen_MW_gfl = 20    [DER_param.m]
  ps = base/3    (= 0.75)    [VSM.m]    (also in VSM_CSIRO.m)
  R1_f_gfl = (1/n_gfl) * R1_unit_gfl    (= 0.000909090909091)    [DER_param.m]
  R1_pu = 1*0.00734/m    (= 7.34e-05)    [VSM.m]    (also in VSM_CSIRO.m)
  R1_pu_gfl = 0.005    [DER_param.m]
  R2_f_gfl = (1/n_gfl) * R2_unit_gfl    (= 0.000181818181818)    [DER_param.m]
  R2_pu_gfl = 0.005    [DER_param.m]
  R_45 = R_lines(2)    [VSM.m]    (also in VSM_CSIRO.m)
  R_56 = R_lines(3)    [VSM.m]    (also in VSM_CSIRO.m)
  R_67 = R_lines(5)    [VSM.m]    (also in VSM_CSIRO.m)
  R_78 = R_lines(6)    [VSM.m]    (also in VSM_CSIRO.m)
  R_89 = R_lines(8)    [VSM.m]    (also in VSM_CSIRO.m)
  R_94 = R_lines(9)    [VSM.m]    (also in VSM_CSIRO.m)
  R_base_gfl = (3 * Vg_gfl^2) / (2 * Pn_gfl)    [DER_param.m]
  R_dc = (Vdc_n/(0.05*(S_b)/Vdc_n))    [VSM.m]    (also in VSM_CSIRO.m)
  R_f = 0.001/n    (= 5e-06)    [VSM.m]    (also in VSM_CSIRO.m)
  Rg = (3 * Vg_gfl^2) / (2 * SCR_gfl * sqrt(1 + X_BY_R_gfl^2) * Pn_gfl)    [DER_param.m]    (also in initialcondition_gfm_Pooyan.m = (3*Vg^2)/(2*SCR*sqrt(1+X_BY_R^2)*Pn); initialcondition_Pooyan.m = (3*Vg^2)/(2*SCR*sqrt(1+X_BY_R^2)*Pn))
  S_b = 100*(10^6)    (= 100000000)    [VSM.m]    (also in VSM_CSIRO.m)
  S_bt = S_b    (= 100000000)    [VSM.m]    (also in VSM_CSIRO.m)
  S_bt_gfl = S_b_gfl    (= 22000000)    [DER_param.m]
  T_en = T_load-0.5    (= 24.5)    [VSM.m]    (also in VSM_CSIRO.m = 44.5)
  T_s = 1e-4    (= 0.0001)    [VSM.m]    (also in VSM_CSIRO.m)
  tau_dc = 0.05    [VSM.m]    (also in VSM_CSIRO.m)
  tau_g = 5    [VSM.m]    (also in VSM_CSIRO.m)
  Tend = 90    [VSM.m]    (also in VSM_CSIRO.m = 50)
  ts_DER = 15    [DER_param.m]
  V1_rms = 1000    [VSM.m]    (also in VSM_CSIRO.m)
  V1_rms_gfl = 1000    [DER_param.m]
  V1_rms_tx1_gfl = 1000    [DER_param.m]
  V2_rms = 13800    [VSM.m]    (also in VSM_CSIRO.m)
  V2_rms_tx1_gfl = 13800    [DER_param.m]
  V_b = 230*(10^3)    (= 230000)    [VSM.m]    (also in VSM_CSIRO.m)
  V_m = sqrt(2/3)*V1_rms    [VSM.m]    (also in VSM_CSIRO.m)
  V_m_gfl = sqrt(2/3)*V1_rms_gfl    [DER_param.m]
  V_sg_p = sqrt(2/3)*V2_rms    [VSM.m]
  Vdc_n = 3*V_m    [VSM.m]    (also in VSM_CSIRO.m)
  Vdc_n_gfl = 2300    [DER_param.m]
  w_b = 2*pi*f_b    (= 314.159265359)    [VSM.m]    (also in VSM_CSIRO.m)
  w_b_gfl = 2*pi*f_b_gfl    (= 314.159265359)    [DER_param.m]
  w_f = 2*pi*5    (= 31.4159265359)    [VSM.m]    (also in VSM_CSIRO.m)
undefined symbols (not defined in the file or in its folder): D1, Delta, DiscIntNeverNeededParam, dspblkCoreblockFVToolHelper, gcbh, i_dc, magnitude
libraries: spsSeriesRLCBranchLib x82, spsabctodq0Lib x40, slpidlib x36, spsVoltageMeasurementLib x32, spsThreePhaseVIMeasurementLib x31, spsThreePhaseBreakerLib x26, spsGroundLib x22, spsCurrentMeasurementLib x20, spsPLL3phLib x14, spsThreePhaseTransformerTwoWindingsLib x14, simulink x13, spsThreePhaseSeriesRLCBranchLib x10
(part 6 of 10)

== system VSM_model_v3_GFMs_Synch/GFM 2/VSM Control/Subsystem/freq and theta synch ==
  In1 : Inport
  In2 : Inport  Port=2
  abc : Inport  Port=3
  sync : Inport  Port=4
  Compare To Zero : simulink/Logic and Bit Operations/Compare To Zero  relop===  OutDataTypeStr=boolean
  Compare To Zero1 : simulink/Logic and Bit Operations/Compare To Zero  relop===  OutDataTypeStr=boolean
  DSOGI-PLL : Subsystem
  Delay : Delay  DelayLength=1  InputProcessing=Columns as channels (frame based)
  Gain : Gain  Gain=2*pi
  Logical Operator : Logic  Operator=NOT  AllPortsSameDT=off  OutDataTypeStr=boolean
  MATLAB Function : MATLAB Function  TreatAsAtomicUnit=on
  MATLAB Function2 : MATLAB Function  TreatAsAtomicUnit=on
  MATLAB Function3 : MATLAB Function  TreatAsAtomicUnit=on
  PID Controller1 : slpidlib/PID Controller  Controller=PI  Form=Parallel  TimeDomain=Discrete-time  UseExternalTs=off  SampleTime=-1  IntegratorMethod=Forward Euler  FilterMethod=Forward Euler  ControllerParametersSource=internal  P=0.2  I=40  UseKiTs=off  D=0  UseExternalDerivativeSource=off  N=100  UseFilter=on  TunerSelectOption=Transfer Function Based (PID Tuner App)  InitialConditionSource=internal  InitialConditionForIntegrator=0  InitialConditionForFilter=0  DifferentiatorICPrevScaledInput=0  ExternalReset=level  TrackingMode=off  Kt=1  LimitOutput=off  SatLimitsSource=internal  UpperSaturationLimit=inf  LowerSaturationLimit=-inf  LinearizeAsGain=on  AntiWindupMode=none  Kb=1  LimitIntegrator=off  UpperIntegratorSaturationLimit=inf  LowerIntegratorSaturationLimit=-inf  POutMin=[]  POutMax=[]  IOutMin=[]  IOutMax=[]  DOutMin=[]  DOutMax=[]  NOutMin=[]  NOutMax=[]  SumOutMin=[]  SumOutMax=[]  SaturationOutMin=[]  SaturationOutMax=[]  PParamMin=[]  PParamMax=[]  IParamMin=[]  IParamMax=[]  DParamMin=[]  DParamMax=[]  NParamMin=[]  NParamMax=[]  KbParamMin=[]  KbParamMax=[]  KtParamMin=[]  KtParamMax=[]  KbOutMin=[]  KbOutMax=[]  KtOutMin=[]  KtOutMax=[]  IntegratorOutMin=[]  IntegratorOutMax=[]  FilterOutMin=[]  FilterOutMax=[]  SumI1OutMin=[]  SumI1OutMax=[]  SumI2OutMin=[]  SumI2OutMax=[]  SumI3OutMin=[]  SumI3OutMax=[]  SumI4OutMin=[]  SumI4OutMax=[]  SumDOutMin=[]  SumDOutMax=[]  DifferentiatorOutMin=[]  DifferentiatorOutMax=[]  FilterDiffOutCoefMin=[]  FilterDiffOutCoefMax=[]  ReciprocalOutMin=[]  ReciprocalOutMax=[]  SumDenOutMin=[]  SumDenOutMax=[]  SumNumOutMin=[]  SumNumOutMax=[]  DivideOutMin=[]  DivideOutMax=[]  UdiffTsProdOutMin=[]  UdiffTsProdOutMax=[]  NTsProdOutMin=[]  NTsProdOutMax=[]  UintegralTsProdOutMin=[]  UintegralTsProdOutMax=[]  UngainTsProdOutMin=[]  UngainTsProdOutMax=[]  ClampingZeroOutDataTypeStr=Inherit: Inherit via back propagation  ClampingZeroOutMin=[]  ClampingZeroOutMax=[]  FilterDenConstantOutDataTypeStr=Inherit: Inherit via back propagation  FilterDenConstantOutMin=[]  FilterDenConstantOutMax=[]  PCopyOutDataTypeStr=Inherit: Inherit via back propagation  PCopyOutMin=[]  PCopyOutMax=[]  NCopyOutDataTypeStr=Inherit: Inherit via back propagation  NCopyOutMin=[]  NCopyOutMax=[]  IntegratorContinuousStateAttributes=''  IntegratorStateMustResolveToSignalObject=off  IntegratorRTWStateStorageClass=Auto  FilterContinuousStateAttributes=''  FilterStateMustResolveToSignalObject=off  FilterRTWStateStorageClass=Auto  ParallelPVariant=InternalParameters  IdealPVariant=Disabled  IVariant=InternalParameters  DVariant=Disabled  IntegratorVariant=Discrete  SatVariant=Disabled  AWVariant=Passthrough  PCopyVariant=Disabled  TRVariant=Disabled  FdbkBlocksVariant=Forward  IdealPFdbkVariant=Disabled  SatFdbkVariant=Disabled  DerivativeFilterVariant=Disabled  NVariant=Disabled  NCopyVariant=Disabled_SignalSpec  FilterICVariant=Disabled  IntegratorICVariant=InternalICs  ExternalResetVariant=ExternalReset  TRSumVariant=Passthrough  SumFdbkVariant=Disabled  SumVariant=Sum_PI  TsampFilterVariant=InternalTs  TsampNgainVariant=Passthrough  TsampIntegralVariant=Disabled_SignalSpec  ExternalSaturationOutDataTypeStr=Inherit: Same as second input  DerivativeSourceVariant=Disabled  PreIntVariant=InternalPreInt
  PID Controller2 : slpidlib/PID Controller  Controller=PI  Form=Parallel  TimeDomain=Discrete-time  UseExternalTs=off  SampleTime=-1  IntegratorMethod=Forward Euler  FilterMethod=Forward Euler  ControllerParametersSource=internal  P=1  I=30  UseKiTs=off  D=0  UseExternalDerivativeSource=off  N=100  UseFilter=on  TunerSelectOption=Transfer Function Based (PID Tuner App)  InitialConditionSource=internal  InitialConditionForIntegrator=0  InitialConditionForFilter=0  DifferentiatorICPrevScaledInput=0  ExternalReset=level  TrackingMode=off  Kt=1  LimitOutput=off  SatLimitsSource=internal  UpperSaturationLimit=inf  LowerSaturationLimit=-inf  LinearizeAsGain=on  AntiWindupMode=none  Kb=1  LimitIntegrator=off  UpperIntegratorSaturationLimit=inf  LowerIntegratorSaturationLimit=-inf  POutMin=[]  POutMax=[]  IOutMin=[]  IOutMax=[]  DOutMin=[]  DOutMax=[]  NOutMin=[]  NOutMax=[]  SumOutMin=[]  SumOutMax=[]  SaturationOutMin=[]  SaturationOutMax=[]  PParamMin=[]  PParamMax=[]  IParamMin=[]  IParamMax=[]  DParamMin=[]  DParamMax=[]  NParamMin=[]  NParamMax=[]  KbParamMin=[]  KbParamMax=[]  KtParamMin=[]  KtParamMax=[]  KbOutMin=[]  KbOutMax=[]  KtOutMin=[]  KtOutMax=[]  IntegratorOutMin=[]  IntegratorOutMax=[]  FilterOutMin=[]  FilterOutMax=[]  SumI1OutMin=[]  SumI1OutMax=[]  SumI2OutMin=[]  SumI2OutMax=[]  SumI3OutMin=[]  SumI3OutMax=[]  SumI4OutMin=[]  SumI4OutMax=[]  SumDOutMin=[]  SumDOutMax=[]  DifferentiatorOutMin=[]  DifferentiatorOutMax=[]  FilterDiffOutCoefMin=[]  FilterDiffOutCoefMax=[]  ReciprocalOutMin=[]  ReciprocalOutMax=[]  SumDenOutMin=[]  SumDenOutMax=[]  SumNumOutMin=[]  SumNumOutMax=[]  DivideOutMin=[]  DivideOutMax=[]  UdiffTsProdOutMin=[]  UdiffTsProdOutMax=[]  NTsProdOutMin=[]  NTsProdOutMax=[]  UintegralTsProdOutMin=[]  UintegralTsProdOutMax=[]  UngainTsProdOutMin=[]  UngainTsProdOutMax=[]  ClampingZeroOutDataTypeStr=Inherit: Inherit via back propagation  ClampingZeroOutMin=[]  ClampingZeroOutMax=[]  FilterDenConstantOutDataTypeStr=Inherit: Inherit via back propagation  FilterDenConstantOutMin=[]  FilterDenConstantOutMax=[]  PCopyOutDataTypeStr=Inherit: Inherit via back propagation  PCopyOutMin=[]  PCopyOutMax=[]  NCopyOutDataTypeStr=Inherit: Inherit via back propagation  NCopyOutMin=[]  NCopyOutMax=[]  IntegratorContinuousStateAttributes=''  IntegratorStateMustResolveToSignalObject=off  IntegratorRTWStateStorageClass=Auto  FilterContinuousStateAttributes=''  FilterStateMustResolveToSignalObject=off  FilterRTWStateStorageClass=Auto  ParallelPVariant=InternalParameters  IdealPVariant=Disabled  IVariant=InternalParameters  DVariant=Disabled  IntegratorVariant=Discrete  SatVariant=Disabled  AWVariant=Passthrough  PCopyVariant=Disabled  TRVariant=Disabled  FdbkBlocksVariant=Forward  IdealPFdbkVariant=Disabled  SatFdbkVariant=Disabled  DerivativeFilterVariant=Disabled  NVariant=Disabled  NCopyVariant=Disabled_SignalSpec  FilterICVariant=Disabled  IntegratorICVariant=InternalICs  ExternalResetVariant=ExternalReset  TRSumVariant=Passthrough  SumFdbkVariant=Disabled  SumVariant=Sum_PI  TsampFilterVariant=InternalTs  TsampNgainVariant=Passthrough  TsampIntegralVariant=Disabled_SignalSpec  ExternalSaturationOutDataTypeStr=Inherit: Same as second input  DerivativeSourceVariant=Disabled  PreIntVariant=InternalPreInt
  PLL (3ph)1 : spsPLL3phLib/PLL (3ph)  Fmin=10  Par_Init=[0, 50]  ParK=[180, 3200, 1]  TcD=1e-4  MaxRateChangeFreq=20  FilterCutOffFreq=25  Ts=0  AGC=on
  Sin : Trigonometry
  Sum3 : Sum  Inputs=-+|
  Sum4 : Sum  Inputs=-+|
  Sum6 : Sum  Inputs=|+-
  Sum7 : Sum  Inputs=|++
  Terminator2 : Terminator
  Terminator3 : Terminator
  Out1 : Outport
  err_theta : Outport  Port=2
  err_w : Outport  Port=3
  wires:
  Delay/1 -> Sum3/1
  Sum7/1 -> Out1/1
  Sum6/1 -> MATLAB Function/2(error_w)
  DSOGI-PLL/4(f) -> Terminator3/1
  Sum4/1 -> err_theta/1, Sin/1, [theta_err]  "err_theta"
  PID Controller1/1 -> MATLAB Function3/1(u)  "delta_w"
  Sin/1 -> MATLAB Function/1(error)
  MATLAB Function/1(y) -> PID Controller2/1
  [w1] -> Sum6/2
  sync/1 -> Logical Operator/1, MATLAB Function2/2(sync), Compare To Zero1/1, Compare To Zero/1, MATLAB Function3/2(sync)
  Sum3/1 -> [w_err], err_w/1, PID Controller1/1  "err_w"
  Compare To Zero/1 -> PID Controller1/2
  PID Controller2/1 -> MATLAB Function2/1(u)  "delta_theta"
  DSOGI-PLL/1(Valp_bet+) -> Terminator2/1
  PLL (3ph)1/1 -> Gain/1
  Compare To Zero1/1 -> PID Controller2/2
  In2/1 -> Sum4/1
  In1/1 -> Delay/1
  Logical Operator/1 -> MATLAB Function/3(reset)
  abc/1 -> DSOGI-PLL/1(abc), PLL (3ph)1/1
  Gain/1 -> Sum6/1, Sum3/2
  MATLAB Function3/1(y) -> Sum7/2  "delta_wt"
  DSOGI-PLL/3(theta_pcc) -> Sum4/2
  MATLAB Function2/1(y) -> Sum7/1  "delta_theta"

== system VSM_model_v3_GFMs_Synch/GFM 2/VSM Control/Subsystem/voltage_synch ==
  In1 : Inport
  sync : Inport  Port=2
  abc : Inport  Port=3
  Compare To Zero2 : simulink/Logic and Bit Operations/Compare To Zero  relop===  OutDataTypeStr=boolean
  Delay1 : Delay  DelayLength=1  InputProcessing=Columns as channels (frame based)
  Demux1 : Demux  Outputs=3
  Demux2 : Demux  Outputs=3
  Fcn1 : Fcn  Expr=sqrt(u[1]^2+u[2]^2)
  Fcn5 : Fcn  Expr=sqrt(u[1]^2+u[2]^2)
  Gain : Gain  Gain=1/V_b
  Gain1 : Gain  Gain=1/V_m
  MATLAB Function3 : MATLAB Function  TreatAsAtomicUnit=on
  Mux1 : Mux  Inputs=2
  Mux5 : Mux  Inputs=2
  PID Controller2 : slpidlib/PID Controller  Controller=PI  Form=Parallel  TimeDomain=Discrete-time  UseExternalTs=off  SampleTime=-1  IntegratorMethod=Forward Euler  FilterMethod=Forward Euler  ControllerParametersSource=internal  P=0.23  I=20  UseKiTs=off  D=0  UseExternalDerivativeSource=off  N=100  UseFilter=on  TunerSelectOption=Transfer Function Based (PID Tuner App)  InitialConditionSource=internal  InitialConditionForIntegrator=0  InitialConditionForFilter=0  DifferentiatorICPrevScaledInput=0  ExternalReset=level  TrackingMode=off  Kt=1  LimitOutput=off  SatLimitsSource=internal  UpperSaturationLimit=inf  LowerSaturationLimit=-inf  LinearizeAsGain=on  AntiWindupMode=none  Kb=1  LimitIntegrator=off  UpperIntegratorSaturationLimit=inf  LowerIntegratorSaturationLimit=-inf  POutMin=[]  POutMax=[]  IOutMin=[]  IOutMax=[]  DOutMin=[]  DOutMax=[]  NOutMin=[]  NOutMax=[]  SumOutMin=[]  SumOutMax=[]  SaturationOutMin=[]  SaturationOutMax=[]  PParamMin=[]  PParamMax=[]  IParamMin=[]  IParamMax=[]  DParamMin=[]  DParamMax=[]  NParamMin=[]  NParamMax=[]  KbParamMin=[]  KbParamMax=[]  KtParamMin=[]  KtParamMax=[]  KbOutMin=[]  KbOutMax=[]  KtOutMin=[]  KtOutMax=[]  IntegratorOutMin=[]  IntegratorOutMax=[]  FilterOutMin=[]  FilterOutMax=[]  SumI1OutMin=[]  SumI1OutMax=[]  SumI2OutMin=[]  SumI2OutMax=[]  SumI3OutMin=[]  SumI3OutMax=[]  SumI4OutMin=[]  SumI4OutMax=[]  SumDOutMin=[]  SumDOutMax=[]  DifferentiatorOutMin=[]  DifferentiatorOutMax=[]  FilterDiffOutCoefMin=[]  FilterDiffOutCoefMax=[]  ReciprocalOutMin=[]  ReciprocalOutMax=[]  SumDenOutMin=[]  SumDenOutMax=[]  SumNumOutMin=[]  SumNumOutMax=[]  DivideOutMin=[]  DivideOutMax=[]  UdiffTsProdOutMin=[]  UdiffTsProdOutMax=[]  NTsProdOutMin=[]  NTsProdOutMax=[]  UintegralTsProdOutMin=[]  UintegralTsProdOutMax=[]  UngainTsProdOutMin=[]  UngainTsProdOutMax=[]  ClampingZeroOutDataTypeStr=Inherit: Inherit via back propagation  ClampingZeroOutMin=[]  ClampingZeroOutMax=[]  FilterDenConstantOutDataTypeStr=Inherit: Inherit via back propagation  FilterDenConstantOutMin=[]  FilterDenConstantOutMax=[]  PCopyOutDataTypeStr=Inherit: Inherit via back propagation  PCopyOutMin=[]  PCopyOutMax=[]  NCopyOutDataTypeStr=Inherit: Inherit via back propagation  NCopyOutMin=[]  NCopyOutMax=[]  IntegratorContinuousStateAttributes=''  IntegratorStateMustResolveToSignalObject=off  IntegratorRTWStateStorageClass=Auto  FilterContinuousStateAttributes=''  FilterStateMustResolveToSignalObject=off  FilterRTWStateStorageClass=Auto  ParallelPVariant=InternalParameters  IdealPVariant=Disabled  IVariant=InternalParameters  DVariant=Disabled  IntegratorVariant=Discrete  SatVariant=Disabled  AWVariant=Passthrough  PCopyVariant=Disabled  TRVariant=Disabled  FdbkBlocksVariant=Forward  IdealPFdbkVariant=Disabled  SatFdbkVariant=Disabled  DerivativeFilterVariant=Disabled  NVariant=Disabled  NCopyVariant=Disabled_SignalSpec  FilterICVariant=Disabled  IntegratorICVariant=InternalICs  ExternalResetVariant=ExternalReset  TRSumVariant=Passthrough  SumFdbkVariant=Disabled  SumVariant=Sum_PI  TsampFilterVariant=InternalTs  TsampNgainVariant=Passthrough  TsampIntegralVariant=Disabled_SignalSpec  ExternalSaturationOutDataTypeStr=Inherit: Same as second input  DerivativeSourceVariant=Disabled  PreIntVariant=InternalPreInt
  Sum9 : Sum  Inputs=+-
  Terminator2 : Terminator
  Terminator3 : Terminator
  Unit Delay : UnitDelay  SampleTime=-1  HasFrameUpgradeWarning=on
  abc to Alpha-Beta-Zero : spsabctoAlphaBetaZeroLib/abc to Alpha-Beta-Zero
  abc to Alpha-Beta-Zero1 : spsabctoAlphaBetaZeroLib/abc to Alpha-Beta-Zero
  delta_v : Outport
  err_V : Outport  Port=2
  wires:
  Demux1/1 -> Mux5/1
  Fcn1/1 -> Gain1/1
  Demux1/2 -> Mux5/2
  Sum9/1 -> err_V/1, [err_V_mag], PID Controller2/1  "err_v"
  Unit Delay/1 -> MATLAB Function3/1(u)
  MATLAB Function3/1(y) -> delta_v/1  "delta_wt"
  sync/1 -> MATLAB Function3/2(sync), Compare To Zero2/1
  PID Controller2/1 -> Unit Delay/1  "delta_v"
  Demux1/3 -> Terminator2/1
  Compare To Zero2/1 -> PID Controller2/2
  Delay1/1 -> Sum9/2
  Mux5/1 -> Fcn5/1
  abc to Alpha-Beta-Zero/1 -> Demux1/1
  Demux2/3 -> Terminator3/1
  abc/1 -> abc to Alpha-Beta-Zero/1
  Mux1/1 -> Fcn1/1
  Demux2/2 -> Mux1/2
  Demux2/1 -> Mux1/1
  abc to Alpha-Beta-Zero1/1 -> Demux2/1
  In1/1 -> abc to Alpha-Beta-Zero1/1
  Gain1/1 -> Delay1/1
  Fcn5/1 -> Gain/1
  Gain/1 -> Sum9/1

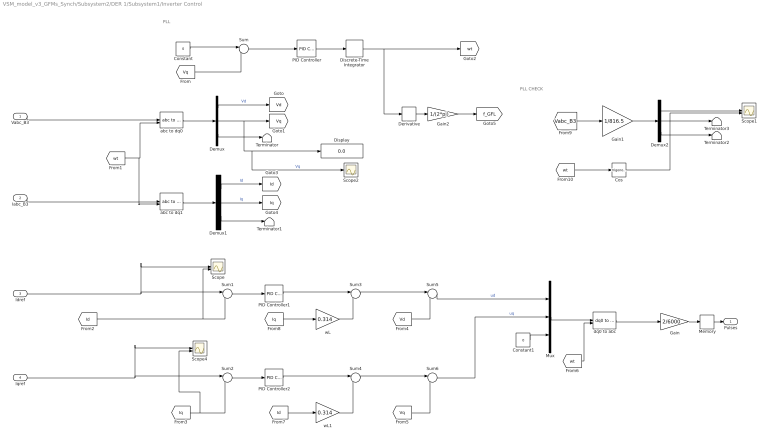
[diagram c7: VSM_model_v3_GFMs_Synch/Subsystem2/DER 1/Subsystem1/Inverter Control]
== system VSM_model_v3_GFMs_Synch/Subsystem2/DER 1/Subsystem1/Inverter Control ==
  note: PLL CHECK
  note: PLL
  Vabc_B3 : Inport
  Iabc_B3 : Inport  Port=2
  Idref : Inport  Port=3
  Iqref : Inport  Port=4
  Constant : Constant  Value=0  SampleTime=-1
  Constant1 : Constant  Value=0  SampleTime=-1
  Cos : Trigonometry
  Demux : Demux  Outputs=3
  Demux1 : Demux  Outputs=3
  Demux2 : Demux  Outputs=3
  Derivative : Derivative
  Discrete-Time Integrator : DiscreteIntegrator  SampleTime=-1  ICPrevOutput=DiscIntNeverNeededParam  ICPrevScaledInput=DiscIntNeverNeededParam
  Display : Display
  Gain : Gain  Gain=2/6000
  Gain1 : Gain  Gain=1/816.5
  Gain2 : Gain  Gain=1/(2*pi)
  Memory : Memory
  Mux : Mux  Inputs=3
  PID Controller : slpidlib/PID Controller  Controller=PI  Form=Parallel  TimeDomain=Discrete-time  UseExternalTs=off  SampleTime=-1  IntegratorMethod=Forward Euler  FilterMethod=Forward Euler  ControllerParametersSource=internal  P=0.5  I=10  UseKiTs=off  D=0  UseExternalDerivativeSource=off  N=100  UseFilter=on  TunerSelectOption=Transfer Function Based (PID Tuner App)  InitialConditionSource=internal  InitialConditionForIntegrator=0  InitialConditionForFilter=0  DifferentiatorICPrevScaledInput=0  ExternalReset=none  TrackingMode=off  Kt=1  LimitOutput=off  SatLimitsSource=internal  UpperSaturationLimit=inf  LowerSaturationLimit=-inf  LinearizeAsGain=on  AntiWindupMode=none  Kb=1  LimitIntegrator=off  UpperIntegratorSaturationLimit=inf  LowerIntegratorSaturationLimit=-inf  POutMin=[]  POutMax=[]  IOutMin=[]  IOutMax=[]  DOutMin=[]  DOutMax=[]  NOutMin=[]  NOutMax=[]  SumOutMin=[]  SumOutMax=[]  SaturationOutMin=[]  SaturationOutMax=[]  PParamMin=[]  PParamMax=[]  IParamMin=[]  IParamMax=[]  DParamMin=[]  DParamMax=[]  NParamMin=[]  NParamMax=[]  KbParamMin=[]  KbParamMax=[]  KtParamMin=[]  KtParamMax=[]  KbOutMin=[]  KbOutMax=[]  KtOutMin=[]  KtOutMax=[]  IntegratorOutMin=[]  IntegratorOutMax=[]  FilterOutMin=[]  FilterOutMax=[]  SumI1OutMin=[]  SumI1OutMax=[]  SumI2OutMin=[]  SumI2OutMax=[]  SumI3OutMin=[]  SumI3OutMax=[]  SumI4OutMin=[]  SumI4OutMax=[]  SumDOutMin=[]  SumDOutMax=[]  DifferentiatorOutMin=[]  DifferentiatorOutMax=[]  FilterDiffOutCoefMin=[]  FilterDiffOutCoefMax=[]  ReciprocalOutMin=[]  ReciprocalOutMax=[]  SumDenOutMin=[]  SumDenOutMax=[]  SumNumOutMin=[]  SumNumOutMax=[]  DivideOutMin=[]  DivideOutMax=[]  UdiffTsProdOutMin=[]  UdiffTsProdOutMax=[]  NTsProdOutMin=[]  NTsProdOutMax=[]  UintegralTsProdOutMin=[]  UintegralTsProdOutMax=[]  UngainTsProdOutMin=[]  UngainTsProdOutMax=[]  ClampingZeroOutDataTypeStr=Inherit: Inherit via back propagation  ClampingZeroOutMin=[]  ClampingZeroOutMax=[]  FilterDenConstantOutDataTypeStr=Inherit: Inherit via back propagation  FilterDenConstantOutMin=[]  FilterDenConstantOutMax=[]  PCopyOutDataTypeStr=Inherit: Inherit via back propagation  PCopyOutMin=[]  PCopyOutMax=[]  NCopyOutDataTypeStr=Inherit: Inherit via back propagation  NCopyOutMin=[]  NCopyOutMax=[]  IntegratorContinuousStateAttributes=''  IntegratorStateMustResolveToSignalObject=off  IntegratorRTWStateStorageClass=Auto  FilterContinuousStateAttributes=''  FilterStateMustResolveToSignalObject=off  FilterRTWStateStorageClass=Auto  ParallelPVariant=InternalParameters  IdealPVariant=Disabled  IVariant=InternalParameters  DVariant=Disabled  IntegratorVariant=Discrete  SatVariant=Disabled  AWVariant=Passthrough  PCopyVariant=Disabled  TRVariant=Disabled  FdbkBlocksVariant=Forward  IdealPFdbkVariant=Disabled  SatFdbkVariant=Disabled  DerivativeFilterVariant=Disabled  NVariant=Disabled  NCopyVariant=Disabled_SignalSpec  FilterICVariant=Disabled  IntegratorICVariant=InternalICs  ExternalResetVariant=Disabled  TRSumVariant=Passthrough  SumFdbkVariant=Disabled  SumVariant=Sum_PI  TsampFilterVariant=InternalTs  TsampNgainVariant=Passthrough  TsampIntegralVariant=Disabled_SignalSpec  ExternalSaturationOutDataTypeStr=Inherit: Same as second input  DerivativeSourceVariant=Disabled  PreIntVariant=InternalPreInt
  PID Controller1 : slpidlib/PID Controller  Controller=PI  Form=Parallel  TimeDomain=Discrete-time  UseExternalTs=off  SampleTime=-1  IntegratorMethod=Forward Euler  FilterMethod=Forward Euler  ControllerParametersSource=internal  P=0.1  I=10000/200  UseKiTs=off  D=0  UseExternalDerivativeSource=off  N=100  UseFilter=on  TunerSelectOption=Transfer Function Based (PID Tuner App)  InitialConditionSource=internal  InitialConditionForIntegrator=0  InitialConditionForFilter=0  DifferentiatorICPrevScaledInput=0  ExternalReset=none  TrackingMode=off  Kt=1  LimitOutput=on  SatLimitsSource=internal  UpperSaturationLimit=3000  LowerSaturationLimit=-3000  LinearizeAsGain=on  AntiWindupMode=none  Kb=1  LimitIntegrator=off  UpperIntegratorSaturationLimit=inf  LowerIntegratorSaturationLimit=-inf  POutMin=[]  POutMax=[]  IOutMin=[]  IOutMax=[]  DOutMin=[]  DOutMax=[]  NOutMin=[]  NOutMax=[]  SumOutMin=[]  SumOutMax=[]  SaturationOutMin=[]  SaturationOutMax=[]  PParamMin=[]  PParamMax=[]  IParamMin=[]  IParamMax=[]  DParamMin=[]  DParamMax=[]  NParamMin=[]  NParamMax=[]  KbParamMin=[]  KbParamMax=[]  KtParamMin=[]  KtParamMax=[]  KbOutMin=[]  KbOutMax=[]  KtOutMin=[]  KtOutMax=[]  IntegratorOutMin=[]  IntegratorOutMax=[]  FilterOutMin=[]  FilterOutMax=[]  SumI1OutMin=[]  SumI1OutMax=[]  SumI2OutMin=[]  SumI2OutMax=[]  SumI3OutMin=[]  SumI3OutMax=[]  SumI4OutMin=[]  SumI4OutMax=[]  SumDOutMin=[]  SumDOutMax=[]  DifferentiatorOutMin=[]  DifferentiatorOutMax=[]  FilterDiffOutCoefMin=[]  FilterDiffOutCoefMax=[]  ReciprocalOutMin=[]  ReciprocalOutMax=[]  SumDenOutMin=[]  SumDenOutMax=[]  SumNumOutMin=[]  SumNumOutMax=[]  DivideOutMin=[]  DivideOutMax=[]  UdiffTsProdOutMin=[]  UdiffTsProdOutMax=[]  NTsProdOutMin=[]  NTsProdOutMax=[]  UintegralTsProdOutMin=[]  UintegralTsProdOutMax=[]  UngainTsProdOutMin=[]  UngainTsProdOutMax=[]  ClampingZeroOutDataTypeStr=Inherit: Inherit via back propagation  ClampingZeroOutMin=[]  ClampingZeroOutMax=[]  FilterDenConstantOutDataTypeStr=Inherit: Inherit via back propagation  FilterDenConstantOutMin=[]  FilterDenConstantOutMax=[]  PCopyOutDataTypeStr=Inherit: Inherit via back propagation  PCopyOutMin=[]  PCopyOutMax=[]  NCopyOutDataTypeStr=Inherit: Inherit via back propagation  NCopyOutMin=[]  NCopyOutMax=[]  IntegratorContinuousStateAttributes=''  IntegratorStateMustResolveToSignalObject=off  IntegratorRTWStateStorageClass=Auto  FilterContinuousStateAttributes=''  FilterStateMustResolveToSignalObject=off  FilterRTWStateStorageClass=Auto  ParallelPVariant=InternalParameters  IdealPVariant=Disabled  IVariant=InternalParameters  DVariant=Disabled  IntegratorVariant=Discrete  SatVariant=Enabled  AWVariant=Passthrough  PCopyVariant=Disabled  TRVariant=Disabled  FdbkBlocksVariant=Forward  IdealPFdbkVariant=Disabled  SatFdbkVariant=Disabled  DerivativeFilterVariant=Disabled  NVariant=Disabled  NCopyVariant=Disabled_SignalSpec  FilterICVariant=Disabled  IntegratorICVariant=InternalICs  ExternalResetVariant=Disabled  TRSumVariant=Passthrough  SumFdbkVariant=Disabled  SumVariant=Sum_PI  TsampFilterVariant=InternalTs  TsampNgainVariant=Passthrough  TsampIntegralVariant=Disabled_SignalSpec  ExternalSaturationOutDataTypeStr=Inherit: Same as second input  DerivativeSourceVariant=Disabled  PreIntVariant=InternalPreInt
  PID Controller2 : slpidlib/PID Controller  Controller=PI  Form=Parallel  TimeDomain=Discrete-time  UseExternalTs=off  SampleTime=-1  IntegratorMethod=Forward Euler  FilterMethod=Forward Euler  ControllerParametersSource=internal  P=0.1  I=1000  UseKiTs=off  D=0  UseExternalDerivativeSource=off  N=100  UseFilter=on  TunerSelectOption=Transfer Function Based (PID Tuner App)  InitialConditionSource=internal  InitialConditionForIntegrator=0  InitialConditionForFilter=0  DifferentiatorICPrevScaledInput=0  ExternalReset=none  TrackingMode=off  Kt=1  LimitOutput=on  SatLimitsSource=internal  UpperSaturationLimit=3000  LowerSaturationLimit=-3000  LinearizeAsGain=on  AntiWindupMode=none  Kb=1  LimitIntegrator=off  UpperIntegratorSaturationLimit=inf  LowerIntegratorSaturationLimit=-inf  POutMin=[]  POutMax=[]  IOutMin=[]  IOutMax=[]  DOutMin=[]  DOutMax=[]  NOutMin=[]  NOutMax=[]  SumOutMin=[]  SumOutMax=[]  SaturationOutMin=[]  SaturationOutMax=[]  PParamMin=[]  PParamMax=[]  IParamMin=[]  IParamMax=[]  DParamMin=[]  DParamMax=[]  NParamMin=[]  NParamMax=[]  KbParamMin=[]  KbParamMax=[]  KtParamMin=[]  KtParamMax=[]  KbOutMin=[]  KbOutMax=[]  KtOutMin=[]  KtOutMax=[]  IntegratorOutMin=[]  IntegratorOutMax=[]  FilterOutMin=[]  FilterOutMax=[]  SumI1OutMin=[]  SumI1OutMax=[]  SumI2OutMin=[]  SumI2OutMax=[]  SumI3OutMin=[]  SumI3OutMax=[]  SumI4OutMin=[]  SumI4OutMax=[]  SumDOutMin=[]  SumDOutMax=[]  DifferentiatorOutMin=[]  DifferentiatorOutMax=[]  FilterDiffOutCoefMin=[]  FilterDiffOutCoefMax=[]  ReciprocalOutMin=[]  ReciprocalOutMax=[]  SumDenOutMin=[]  SumDenOutMax=[]  SumNumOutMin=[]  SumNumOutMax=[]  DivideOutMin=[]  DivideOutMax=[]  UdiffTsProdOutMin=[]  UdiffTsProdOutMax=[]  NTsProdOutMin=[]  NTsProdOutMax=[]  UintegralTsProdOutMin=[]  UintegralTsProdOutMax=[]  UngainTsProdOutMin=[]  UngainTsProdOutMax=[]  ClampingZeroOutDataTypeStr=Inherit: Inherit via back propagation  ClampingZeroOutMin=[]  ClampingZeroOutMax=[]  FilterDenConstantOutDataTypeStr=Inherit: Inherit via back propagation  FilterDenConstantOutMin=[]  FilterDenConstantOutMax=[]  PCopyOutDataTypeStr=Inherit: Inherit via back propagation  PCopyOutMin=[]  PCopyOutMax=[]  NCopyOutDataTypeStr=Inherit: Inherit via back propagation  NCopyOutMin=[]  NCopyOutMax=[]  IntegratorContinuousStateAttributes=''  IntegratorStateMustResolveToSignalObject=off  IntegratorRTWStateStorageClass=Auto  FilterContinuousStateAttributes=''  FilterStateMustResolveToSignalObject=off  FilterRTWStateStorageClass=Auto  ParallelPVariant=InternalParameters  IdealPVariant=Disabled  IVariant=InternalParameters  DVariant=Disabled  IntegratorVariant=Discrete  SatVariant=Enabled  AWVariant=Passthrough  PCopyVariant=Disabled  TRVariant=Disabled  FdbkBlocksVariant=Forward  IdealPFdbkVariant=Disabled  SatFdbkVariant=Disabled  DerivativeFilterVariant=Disabled  NVariant=Disabled  NCopyVariant=Disabled_SignalSpec  FilterICVariant=Disabled  IntegratorICVariant=InternalICs  ExternalResetVariant=Disabled  TRSumVariant=Passthrough  SumFdbkVariant=Disabled  SumVariant=Sum_PI  TsampFilterVariant=InternalTs  TsampNgainVariant=Passthrough  TsampIntegralVariant=Disabled_SignalSpec  ExternalSaturationOutDataTypeStr=Inherit: Same as second input  DerivativeSourceVariant=Disabled  PreIntVariant=InternalPreInt
  Scope : Scope  NumInputPorts=2
  Scope1 : Scope  NumInputPorts=2
  Scope2 : Scope
  Scope4 : Scope  NumInputPorts=2
  Sum : Sum  Inputs=|-+
  Sum1 : Sum  Inputs=|+-
  Sum2 : Sum  Inputs=|+-
  Sum3 : Sum  Inputs=|+-
  Sum4 : Sum  Inputs=|++
  Sum5 : Sum  Inputs=|++
  Sum6 : Sum  Inputs=|++
  Terminator{,1..3} (4 alike) : Terminator
  abc to dq0 : spsabctodq0Lib/abc to dq0  Alignment=90 degrees behind phase A axis
  abc to dq1 : spsabctodq0Lib/abc to dq0  Alignment=90 degrees behind phase A axis
  dq0 to abc : spsdq0toabcLib/dq0 to abc  Alignment=90 degrees behind phase A axis
  wL : Gain  Gain=0.314
  wL1 : Gain  Gain=0.314
  Pulses : Outport
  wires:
  abc to dq0/1 -> Demux/1
  Demux/3 -> Terminator/1
  Demux1/3 -> Terminator1/1
  abc to dq1/1 -> Demux1/1
  Iabc_B3/1 -> abc to dq1/1
  Constant/1 -> Sum/1
  Demux/2 -> [Vq], Scope2/1, Display/1  "Vq"
  [Vq] -> Sum/2
  Sum/1 -> PID Controller/1
  PID Controller/1 -> Discrete-Time Integrator/1
  [wt] -> abc to dq1/2, abc to dq0/2
  Demux1/1 -> [Id]  "Id"
  Demux1/2 -> [Iq]  "Iq"
  [Id] -> Scope/2, Sum1/2
  Iqref/1 -> Scope4/1, Sum2/1
  [Iq] -> Scope4/2, Sum2/2
  Sum1/1 -> PID Controller1/1
  Sum2/1 -> PID Controller2/1
  PID Controller1/1 -> Sum3/1
  PID Controller2/1 -> Sum4/1
  wL1/1 -> Sum4/2
  wL/1 -> Sum3/2
  Sum3/1 -> Sum5/1
  [Vd] -> Sum5/2
  Sum4/1 -> Sum6/1
  [Vq] -> Sum6/2
  Mux/1 -> dq0 to abc/1
  Sum5/1 -> Mux/1  "ud"
  Sum6/1 -> Mux/2  "uq"
  Constant1/1 -> Mux/3
  [wt] -> dq0 to abc/2
  dq0 to abc/1 -> Gain/1
  Vabc_B3/1 -> abc to dq0/1
  Idref/1 -> Scope/1, Sum1/1
  [Id] -> wL1/1
  [Iq] -> wL/1
  [Vabc_B3] -> Gain1/1
  Demux2/3 -> Terminator2/1
  Demux2/2 -> Terminator3/1
  Demux2/1 -> Scope1/1
  Gain1/1 -> Demux2/1
  [wt] -> Cos/1
  Cos/1 -> Scope1/2
  Demux/1 -> [Vd]  "Vd"
  Gain/1 -> Memory/1
  Memory/1 -> Pulses/1
  Discrete-Time Integrator/1 -> [wt], Derivative/1
  Derivative/1 -> Gain2/1
  Gain2/1 -> [f_GFL]

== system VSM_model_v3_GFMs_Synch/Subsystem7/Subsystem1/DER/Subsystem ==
  C_a : spsSeriesRLCBranchLib/Series RLC Branch  LConnTagsString=__new0  RConnTagsString=__new0  BranchType=C  Resistance=1  Inductance=1e-3  SetiL0=off  InitialCurrent=0  Capacitance=C_f_gfl  Setx0=off  InitialVoltage=165  Measurements=None
  C_b : spsSeriesRLCBranchLib/Series RLC Branch  LConnTagsString=__new0  RConnTagsString=__new0  BranchType=C  Resistance=1  Inductance=1e-3  SetiL0=off  InitialCurrent=0  Capacitance=C_f_gfl  Setx0=off  InitialVoltage=165  Measurements=None
  C_c1 : spsSeriesRLCBranchLib/Series RLC Branch  LConnTagsString=__new0  RConnTagsString=__new0  BranchType=C  Resistance=1  Inductance=1e-3  SetiL0=off  InitialCurrent=0  Capacitance=C_f_gfl  Setx0=off  InitialVoltage=165  Measurements=None
  Ground2 : spsGroundLib/Ground  LConnTagsString=a
  RL_c : spsSeriesRLCBranchLib/Series RLC Branch  LConnTagsString=__new0  RConnTagsString=__new0  BranchType=RL  Resistance=R1_f_gfl  Inductance=L1_f_gfl  SetiL0=off  InitialCurrent=0  Capacitance=1e-6  Setx0=off  InitialVoltage=0  Measurements=None
  RL_c1 : spsSeriesRLCBranchLib/Series RLC Branch  LConnTagsString=__new0  RConnTagsString=__new0  BranchType=RL  Resistance=L2_f_gfl  Inductance=R2_f_gfl  SetiL0=off  InitialCurrent=0  Capacitance=1e-6  Setx0=off  InitialVoltage=0  Measurements=None
  RL_c2 : spsSeriesRLCBranchLib/Series RLC Branch  LConnTagsString=__new0  RConnTagsString=__new0  BranchType=RL  Resistance=R1_f_gfl  Inductance=L1_f_gfl  SetiL0=off  InitialCurrent=0  Capacitance=1e-6  Setx0=off  InitialVoltage=0  Measurements=None
  RL_c3 : spsSeriesRLCBranchLib/Series RLC Branch  LConnTagsString=__new0  RConnTagsString=__new0  BranchType=RL  Resistance=R1_f_gfl  Inductance=L1_f_gfl  SetiL0=off  InitialCurrent=0  Capacitance=1e-6  Setx0=off  InitialVoltage=0  Measurements=None
  RL_c4 : spsSeriesRLCBranchLib/Series RLC Branch  LConnTagsString=__new0  RConnTagsString=__new0  BranchType=RL  Resistance=L2_f_gfl  Inductance=R2_f_gfl  SetiL0=off  InitialCurrent=0  Capacitance=1e-6  Setx0=off  InitialVoltage=0  Measurements=None
  RL_c5 : spsSeriesRLCBranchLib/Series RLC Branch  LConnTagsString=__new0  RConnTagsString=__new0  BranchType=RL  Resistance=L2_f_gfl  Inductance=R2_f_gfl  SetiL0=off  InitialCurrent=0  Capacitance=1e-6  Setx0=off  InitialVoltage=0  Measurements=None
  A : PMIOPort  Side=Left
  B : PMIOPort  Port=2  Side=Left
  C : PMIOPort  Port=3  Side=Left
  Connection Port3 : PMIOPort  Port=4  Side=Right
  Connection Port4 : PMIOPort  Port=5  Side=Right
  Connection Port5 : PMIOPort  Port=6  Side=Right
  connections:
  C_a/LConn1 -- RL_c5/LConn1 -- RL_c3/RConn1
  C_b/RConn1 -- C_c1/RConn1 -- Ground2/LConn1 -- C_a/RConn1
  C_b/LConn1 -- RL_c4/LConn1 -- RL_c2/RConn1
  C_c1/LConn1 -- RL_c1/LConn1 -- RL_c/RConn1
  A/RConn1 -- RL_c1/RConn1
  RL_c4/RConn1 -- B/RConn1
  RL_c5/RConn1 -- C/RConn1
  Connection Port3/RConn1 -- RL_c/LConn1
  RL_c2/LConn1 -- Connection Port4/RConn1
  RL_c3/LConn1 -- Connection Port5/RConn1

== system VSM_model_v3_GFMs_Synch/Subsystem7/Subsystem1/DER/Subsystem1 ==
  P_ref_MW : Inport
  Iabc : Inport  Port=2
  Vabc : Inport  Port=3
  Enable : EnablePort  StatesWhenEnabling=reset
  Subsystem2 : Subsystem
  Varef : Outport
  Vbref : Outport  Port=2
  Vcref : Outport  Port=3
  wt : Outport  Port=4
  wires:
  Vabc/1 -> Subsystem2/1(Vabc)
  Iabc/1 -> Subsystem2/2(Iabc)
  P_ref_MW/1 -> Subsystem2/3(P_ref_MW)
  Subsystem2/3(Vcref) -> Vcref/1
  Subsystem2/2(Vbref) -> Vbref/1
  Subsystem2/1(Varef) -> Varef/1
  Subsystem2/4(wt) -> wt/1

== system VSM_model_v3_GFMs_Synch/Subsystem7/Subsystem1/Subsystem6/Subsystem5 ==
  abc : Inport
  abc1 : Inport  Port=2
  Clock : Clock
  Data Type Conversion : DataTypeConversion  OutDataTypeStr=boolean
  Demux : Demux  Outputs=3
  Demux1 : Demux  Outputs=3
  Display{,1..4} (5 alike) : Display
  Gain : Gain  Gain=1/V_m_gfl
  Gain1 : Gain  Gain=1/V_m_gfl
  MATLAB Function : MATLAB Function  TreatAsAtomicUnit=on
  Math Function{,1..3} (4 alike) : Math  Operator=magnitude^2
  PLL (3ph)1 : spsPLL3phLib/PLL (3ph)  Fmin=10  Par_Init=[0, 50]  ParK=[180, 3200, 1]  TcD=1e-4  MaxRateChangeFreq=20  FilterCutOffFreq=25  Ts=0  AGC=on
  PLL (3ph)2 : spsPLL3phLib/PLL (3ph)  Fmin=10  Par_Init=[0, 50]  ParK=[180, 3200, 1]  TcD=1e-4  MaxRateChangeFreq=20  FilterCutOffFreq=25  Ts=0  AGC=on
  Sqrt : Sqrt
  Sqrt1 : Sqrt
  Sum : Sum  Inputs=|++
  Sum1 : Sum  Inputs=|++
  Terminator : Terminator
  Terminator1 : Terminator
  abc to dq0 : spsabctodq0Lib/abc to dq0  Alignment=90 degrees behind phase A axis
  abc to dq1 : spsabctodq0Lib/abc to dq0  Alignment=90 degrees behind phase A axis
  close_signal : Outport
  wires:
  PLL (3ph)1/1 -> MATLAB Function/5(w1)
  PLL (3ph)1/2 -> MATLAB Function/3(theta1), abc to dq0/2
  abc/1 -> abc to dq1/1, PLL (3ph)2/1
  abc1/1 -> abc to dq0/1, PLL (3ph)1/1
  PLL (3ph)2/2 -> abc to dq1/2, MATLAB Function/4(theta2)
  PLL (3ph)2/1 -> MATLAB Function/6(w2)
  abc to dq0/1 -> Demux/1
  Demux/1 -> Math Function/1
  Demux/2 -> Math Function2/1
  Math Function/1 -> Sum/1
  Math Function2/1 -> Sum/2
  Sum/1 -> Sqrt/1
  Demux/3 -> Terminator/1
  Demux1/1 -> Math Function1/1
  abc to dq1/1 -> Demux1/1
  Sum1/1 -> Sqrt1/1
  Demux1/2 -> Math Function3/1
  Demux1/3 -> Terminator1/1
  Math Function1/1 -> Sum1/1
  Math Function3/1 -> Sum1/2
  Sqrt1/1 -> Gain1/1
  MATLAB Function/2(delta_V) -> Display/1
  MATLAB Function/3(delta_theta) -> Display1/1
  MATLAB Function/4(delta_w) -> Display2/1
  Sqrt/1 -> Gain/1
  Gain/1 -> Display3/1, MATLAB Function/1(V1)
  Gain1/1 -> Display4/1, MATLAB Function/2(V2)
  MATLAB Function/1(close_signal) -> Data Type Conversion/1
  Clock/1 -> MATLAB Function/7(t)
  Data Type Conversion/1 -> close_signal/1

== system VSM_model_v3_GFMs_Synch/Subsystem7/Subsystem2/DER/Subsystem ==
  C_a : spsSeriesRLCBranchLib/Series RLC Branch  LConnTagsString=__new0  RConnTagsString=__new0  BranchType=C  Resistance=1  Inductance=1e-3  SetiL0=off  InitialCurrent=0  Capacitance=C_f_gfl  Setx0=off  InitialVoltage=165  Measurements=None
  C_b : spsSeriesRLCBranchLib/Series RLC Branch  LConnTagsString=__new0  RConnTagsString=__new0  BranchType=C  Resistance=1  Inductance=1e-3  SetiL0=off  InitialCurrent=0  Capacitance=C_f_gfl  Setx0=off  InitialVoltage=165  Measurements=None
  C_c1 : spsSeriesRLCBranchLib/Series RLC Branch  LConnTagsString=__new0  RConnTagsString=__new0  BranchType=C  Resistance=1  Inductance=1e-3  SetiL0=off  InitialCurrent=0  Capacitance=C_f_gfl  Setx0=off  InitialVoltage=165  Measurements=None
  Ground2 : spsGroundLib/Ground  LConnTagsString=a
  RL_c : spsSeriesRLCBranchLib/Series RLC Branch  LConnTagsString=__new0  RConnTagsString=__new0  BranchType=RL  Resistance=R1_f_gfl  Inductance=L1_f_gfl  SetiL0=off  InitialCurrent=0  Capacitance=1e-6  Setx0=off  InitialVoltage=0  Measurements=None
  RL_c1 : spsSeriesRLCBranchLib/Series RLC Branch  LConnTagsString=__new0  RConnTagsString=__new0  BranchType=RL  Resistance=L2_f_gfl  Inductance=R2_f_gfl  SetiL0=off  InitialCurrent=0  Capacitance=1e-6  Setx0=off  InitialVoltage=0  Measurements=None
  RL_c2 : spsSeriesRLCBranchLib/Series RLC Branch  LConnTagsString=__new0  RConnTagsString=__new0  BranchType=RL  Resistance=R1_f_gfl  Inductance=L1_f_gfl  SetiL0=off  InitialCurrent=0  Capacitance=1e-6  Setx0=off  InitialVoltage=0  Measurements=None
  RL_c3 : spsSeriesRLCBranchLib/Series RLC Branch  LConnTagsString=__new0  RConnTagsString=__new0  BranchType=RL  Resistance=R1_f_gfl  Inductance=L1_f_gfl  SetiL0=off  InitialCurrent=0  Capacitance=1e-6  Setx0=off  InitialVoltage=0  Measurements=None
  RL_c4 : spsSeriesRLCBranchLib/Series RLC Branch  LConnTagsString=__new0  RConnTagsString=__new0  BranchType=RL  Resistance=L2_f_gfl  Inductance=R2_f_gfl  SetiL0=off  InitialCurrent=0  Capacitance=1e-6  Setx0=off  InitialVoltage=0  Measurements=None
  RL_c5 : spsSeriesRLCBranchLib/Series RLC Branch  LConnTagsString=__new0  RConnTagsString=__new0  BranchType=RL  Resistance=L2_f_gfl  Inductance=R2_f_gfl  SetiL0=off  InitialCurrent=0  Capacitance=1e-6  Setx0=off  InitialVoltage=0  Measurements=None
  A : PMIOPort  Side=Left
  B : PMIOPort  Port=2  Side=Left
  C : PMIOPort  Port=3  Side=Left
  Connection Port3 : PMIOPort  Port=4  Side=Right
  Connection Port4 : PMIOPort  Port=5  Side=Right
  Connection Port5 : PMIOPort  Port=6  Side=Right
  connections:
  C_a/LConn1 -- RL_c5/LConn1 -- RL_c3/RConn1
  C_b/RConn1 -- C_c1/RConn1 -- Ground2/LConn1 -- C_a/RConn1
  C_b/LConn1 -- RL_c4/LConn1 -- RL_c2/RConn1
  C_c1/LConn1 -- RL_c1/LConn1 -- RL_c/RConn1
  A/RConn1 -- RL_c1/RConn1
  RL_c4/RConn1 -- B/RConn1
  RL_c5/RConn1 -- C/RConn1
  Connection Port3/RConn1 -- RL_c/LConn1
  RL_c2/LConn1 -- Connection Port4/RConn1
  RL_c3/LConn1 -- Connection Port5/RConn1

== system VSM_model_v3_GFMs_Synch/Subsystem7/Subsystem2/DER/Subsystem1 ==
  P_ref_MW : Inport
  Iabc : Inport  Port=2
  Vabc : Inport  Port=3
  Enable : EnablePort  StatesWhenEnabling=reset
  Subsystem2 : Subsystem
  Varef : Outport
  Vbref : Outport  Port=2
  Vcref : Outport  Port=3
  wt : Outport  Port=4
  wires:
  Vabc/1 -> Subsystem2/1(Vabc)
  Iabc/1 -> Subsystem2/2(Iabc)
  P_ref_MW/1 -> Subsystem2/3(P_ref_MW)
  Subsystem2/3(Vcref) -> Vcref/1
  Subsystem2/2(Vbref) -> Vbref/1
  Subsystem2/1(Varef) -> Varef/1
  Subsystem2/4(wt) -> wt/1

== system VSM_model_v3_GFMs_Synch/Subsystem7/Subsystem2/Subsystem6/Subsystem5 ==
  abc : Inport
  abc1 : Inport  Port=2
  Clock : Clock
  Data Type Conversion : DataTypeConversion  OutDataTypeStr=boolean
  Demux : Demux  Outputs=3
  Demux1 : Demux  Outputs=3
  Display{,1..4} (5 alike) : Display
  Gain : Gain  Gain=1/V_m_gfl
  Gain1 : Gain  Gain=1/V_m_gfl
  MATLAB Function : MATLAB Function  TreatAsAtomicUnit=on
  Math Function{,1..3} (4 alike) : Math  Operator=magnitude^2
  PLL (3ph)1 : spsPLL3phLib/PLL (3ph)  Fmin=10  Par_Init=[0, 50]  ParK=[180, 3200, 1]  TcD=1e-4  MaxRateChangeFreq=20  FilterCutOffFreq=25  Ts=0  AGC=on
  PLL (3ph)2 : spsPLL3phLib/PLL (3ph)  Fmin=10  Par_Init=[0, 50]  ParK=[180, 3200, 1]  TcD=1e-4  MaxRateChangeFreq=20  FilterCutOffFreq=25  Ts=0  AGC=on
  Sqrt : Sqrt
  Sqrt1 : Sqrt
  Sum : Sum  Inputs=|++
  Sum1 : Sum  Inputs=|++
  Terminator : Terminator
  Terminator1 : Terminator
  abc to dq0 : spsabctodq0Lib/abc to dq0  Alignment=90 degrees behind phase A axis
  abc to dq1 : spsabctodq0Lib/abc to dq0  Alignment=90 degrees behind phase A axis
  close_signal : Outport
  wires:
  PLL (3ph)1/1 -> MATLAB Function/5(w1)
  PLL (3ph)1/2 -> MATLAB Function/3(theta1), abc to dq0/2
  abc/1 -> abc to dq1/1, PLL (3ph)2/1
  abc1/1 -> abc to dq0/1, PLL (3ph)1/1
  PLL (3ph)2/2 -> abc to dq1/2, MATLAB Function/4(theta2)
  PLL (3ph)2/1 -> MATLAB Function/6(w2)
  abc to dq0/1 -> Demux/1
  Demux/1 -> Math Function/1
  Demux/2 -> Math Function2/1
  Math Function/1 -> Sum/1
  Math Function2/1 -> Sum/2
  Sum/1 -> Sqrt/1
  Demux/3 -> Terminator/1
  Demux1/1 -> Math Function1/1
  abc to dq1/1 -> Demux1/1
  Sum1/1 -> Sqrt1/1
  Demux1/2 -> Math Function3/1
  Demux1/3 -> Terminator1/1
  Math Function1/1 -> Sum1/1
  Math Function3/1 -> Sum1/2
  Sqrt1/1 -> Gain1/1
  MATLAB Function/2(delta_V) -> Display/1
  MATLAB Function/3(delta_theta) -> Display1/1
  MATLAB Function/4(delta_w) -> Display2/1
  Sqrt/1 -> Gain/1
  Gain/1 -> Display3/1, MATLAB Function/1(V1)
  Gain1/1 -> Display4/1, MATLAB Function/2(V2)
  MATLAB Function/1(close_signal) -> Data Type Conversion/1
  Clock/1 -> MATLAB Function/7(t)
  Data Type Conversion/1 -> close_signal/1

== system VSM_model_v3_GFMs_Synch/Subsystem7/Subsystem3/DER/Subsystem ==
  C_a : spsSeriesRLCBranchLib/Series RLC Branch  LConnTagsString=__new0  RConnTagsString=__new0  BranchType=C  Resistance=1  Inductance=1e-3  SetiL0=off  InitialCurrent=0  Capacitance=C_f_gfl  Setx0=off  InitialVoltage=165  Measurements=None
  C_b : spsSeriesRLCBranchLib/Series RLC Branch  LConnTagsString=__new0  RConnTagsString=__new0  BranchType=C  Resistance=1  Inductance=1e-3  SetiL0=off  InitialCurrent=0  Capacitance=C_f_gfl  Setx0=off  InitialVoltage=165  Measurements=None
  C_c1 : spsSeriesRLCBranchLib/Series RLC Branch  LConnTagsString=__new0  RConnTagsString=__new0  BranchType=C  Resistance=1  Inductance=1e-3  SetiL0=off  InitialCurrent=0  Capacitance=C_f_gfl  Setx0=off  InitialVoltage=165  Measurements=None
  Ground2 : spsGroundLib/Ground  LConnTagsString=a
  RL_c : spsSeriesRLCBranchLib/Series RLC Branch  LConnTagsString=__new0  RConnTagsString=__new0  BranchType=RL  Resistance=R1_f_gfl  Inductance=L1_f_gfl  SetiL0=off  InitialCurrent=0  Capacitance=1e-6  Setx0=off  InitialVoltage=0  Measurements=None
  RL_c1 : spsSeriesRLCBranchLib/Series RLC Branch  LConnTagsString=__new0  RConnTagsString=__new0  BranchType=RL  Resistance=L2_f_gfl  Inductance=R2_f_gfl  SetiL0=off  InitialCurrent=0  Capacitance=1e-6  Setx0=off  InitialVoltage=0  Measurements=None
  RL_c2 : spsSeriesRLCBranchLib/Series RLC Branch  LConnTagsString=__new0  RConnTagsString=__new0  BranchType=RL  Resistance=R1_f_gfl  Inductance=L1_f_gfl  SetiL0=off  InitialCurrent=0  Capacitance=1e-6  Setx0=off  InitialVoltage=0  Measurements=None
  RL_c3 : spsSeriesRLCBranchLib/Series RLC Branch  LConnTagsString=__new0  RConnTagsString=__new0  BranchType=RL  Resistance=R1_f_gfl  Inductance=L1_f_gfl  SetiL0=off  InitialCurrent=0  Capacitance=1e-6  Setx0=off  InitialVoltage=0  Measurements=None
  RL_c4 : spsSeriesRLCBranchLib/Series RLC Branch  LConnTagsString=__new0  RConnTagsString=__new0  BranchType=RL  Resistance=L2_f_gfl  Inductance=R2_f_gfl  SetiL0=off  InitialCurrent=0  Capacitance=1e-6  Setx0=off  InitialVoltage=0  Measurements=None
  RL_c5 : spsSeriesRLCBranchLib/Series RLC Branch  LConnTagsString=__new0  RConnTagsString=__new0  BranchType=RL  Resistance=L2_f_gfl  Inductance=R2_f_gfl  SetiL0=off  InitialCurrent=0  Capacitance=1e-6  Setx0=off  InitialVoltage=0  Measurements=None
  A : PMIOPort  Side=Left
  B : PMIOPort  Port=2  Side=Left
  C : PMIOPort  Port=3  Side=Left
  Connection Port3 : PMIOPort  Port=4  Side=Right
  Connection Port4 : PMIOPort  Port=5  Side=Right
  Connection Port5 : PMIOPort  Port=6  Side=Right
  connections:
  C_a/LConn1 -- RL_c5/LConn1 -- RL_c3/RConn1
  C_b/RConn1 -- C_c1/RConn1 -- Ground2/LConn1 -- C_a/RConn1
  C_b/LConn1 -- RL_c4/LConn1 -- RL_c2/RConn1
  C_c1/LConn1 -- RL_c1/LConn1 -- RL_c/RConn1
  A/RConn1 -- RL_c1/RConn1
  RL_c4/RConn1 -- B/RConn1
  RL_c5/RConn1 -- C/RConn1
  Connection Port3/RConn1 -- RL_c/LConn1
  RL_c2/LConn1 -- Connection Port4/RConn1
  RL_c3/LConn1 -- Connection Port5/RConn1

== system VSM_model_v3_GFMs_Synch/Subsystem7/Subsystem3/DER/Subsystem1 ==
  P_ref_MW : Inport
  Iabc : Inport  Port=2
  Vabc : Inport  Port=3
  Enable : EnablePort  StatesWhenEnabling=reset
  Subsystem2 : Subsystem
  Varef : Outport
  Vbref : Outport  Port=2
  Vcref : Outport  Port=3
  wt : Outport  Port=4
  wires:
  Vabc/1 -> Subsystem2/1(Vabc)
  Iabc/1 -> Subsystem2/2(Iabc)
  P_ref_MW/1 -> Subsystem2/3(P_ref_MW)
  Subsystem2/3(Vcref) -> Vcref/1
  Subsystem2/2(Vbref) -> Vbref/1
  Subsystem2/1(Varef) -> Varef/1
  Subsystem2/4(wt) -> wt/1

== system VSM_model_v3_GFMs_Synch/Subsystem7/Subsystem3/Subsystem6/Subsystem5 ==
  abc : Inport
  abc1 : Inport  Port=2
  Clock : Clock
  Data Type Conversion : DataTypeConversion  OutDataTypeStr=boolean
  Demux : Demux  Outputs=3
  Demux1 : Demux  Outputs=3
  Display{,1..4} (5 alike) : Display
  Gain : Gain  Gain=1/V_m_gfl
  Gain1 : Gain  Gain=1/V_m_gfl
  MATLAB Function : MATLAB Function  TreatAsAtomicUnit=on
  Math Function{,1..3} (4 alike) : Math  Operator=magnitude^2
  PLL (3ph)1 : spsPLL3phLib/PLL (3ph)  Fmin=10  Par_Init=[0, 50]  ParK=[180, 3200, 1]  TcD=1e-4  MaxRateChangeFreq=20  FilterCutOffFreq=25  Ts=0  AGC=on
  PLL (3ph)2 : spsPLL3phLib/PLL (3ph)  Fmin=10  Par_Init=[0, 50]  ParK=[180, 3200, 1]  TcD=1e-4  MaxRateChangeFreq=20  FilterCutOffFreq=25  Ts=0  AGC=on
  Sqrt : Sqrt
  Sqrt1 : Sqrt
  Sum : Sum  Inputs=|++
  Sum1 : Sum  Inputs=|++
  Terminator : Terminator
  Terminator1 : Terminator
  abc to dq0 : spsabctodq0Lib/abc to dq0  Alignment=90 degrees behind phase A axis
  abc to dq1 : spsabctodq0Lib/abc to dq0  Alignment=90 degrees behind phase A axis
  close_signal : Outport
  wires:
  PLL (3ph)1/1 -> MATLAB Function/5(w1)
  PLL (3ph)1/2 -> MATLAB Function/3(theta1), abc to dq0/2
  abc/1 -> abc to dq1/1, PLL (3ph)2/1
  abc1/1 -> abc to dq0/1, PLL (3ph)1/1
  PLL (3ph)2/2 -> abc to dq1/2, MATLAB Function/4(theta2)
  PLL (3ph)2/1 -> MATLAB Function/6(w2)
  abc to dq0/1 -> Demux/1
  Demux/1 -> Math Function/1
  Demux/2 -> Math Function2/1
  Math Function/1 -> Sum/1
  Math Function2/1 -> Sum/2
  Sum/1 -> Sqrt/1
  Demux/3 -> Terminator/1
  Demux1/1 -> Math Function1/1
  abc to dq1/1 -> Demux1/1
  Sum1/1 -> Sqrt1/1
  Demux1/2 -> Math Function3/1
  Demux1/3 -> Terminator1/1
  Math Function1/1 -> Sum1/1
  Math Function3/1 -> Sum1/2
  Sqrt1/1 -> Gain1/1
  MATLAB Function/2(delta_V) -> Display/1
  MATLAB Function/3(delta_theta) -> Display1/1
  MATLAB Function/4(delta_w) -> Display2/1
  Sqrt/1 -> Gain/1
  Gain/1 -> Display3/1, MATLAB Function/1(V1)
  Gain1/1 -> Display4/1, MATLAB Function/2(V2)
  MATLAB Function/1(close_signal) -> Data Type Conversion/1
  Clock/1 -> MATLAB Function/7(t)
  Data Type Conversion/1 -> close_signal/1
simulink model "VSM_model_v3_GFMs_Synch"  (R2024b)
settings: Solver=ode23tb  StartTime=0.0  StopTime=Tend  FixedStep=T_s  RelTol=1e-3  EnableMultiTasking=on
PostLoadFcn:
  | Tcontrol=20e-6;
InitFcn:
  | Tcontrol=20e-6;
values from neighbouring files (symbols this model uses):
  C_4 = 0.1670*C_b    (= 1.00487241952e-06)    [VSM.m]    (also in VSM_CSIRO.m)
  C_6 = 0.2835*C_b    (= 1.70587623314e-06)    [VSM.m]    (also in VSM_CSIRO.m)
  C_8 = 0.2275*C_b    (= 1.36891302659e-06)    [VSM.m]    (also in VSM_CSIRO.m)
  C_dc = 0.008*(n)    (= 1.6)    [VSM.m]    (also in VSM_CSIRO.m)
  C_f = n*300*10^-6    (= 0.06)    [VSM.m]    (also in VSM_CSIRO.m)
  C_f_gfl = (n_gfl) * Cf_unit_gfl    (= 0.00350140874802)    [DER_param.m]
  D_p = (1/(m_p*w_b))    (= 101321.183642)    [VSM.m]    (also in VSM_CSIRO.m)
  droop_percentage = 5    [VSM.m]    (also in VSM_CSIRO.m = 1)
  I_b_dc = S_b/Vdc_n    [VSM.m]    (also in VSM_CSIRO.m)
  I_b_LV_peak = I_b_LV * sqrt(2)    [VSM.m]
  I_b_SG_peak = I_b_SG * sqrt(2)    [VSM.m]
  i_ll = -1.15*(S_b/Vdc_n)-i_loss_dc    [VSM.m]    (also in VSM_CSIRO.m)
  i_ul = 1.15*(S_b/Vdc_n)+i_loss_dc    [VSM.m]    (also in VSM_CSIRO.m)
  J = D_p*tau_f    (= 2026.42367285)    [VSM.m]    (also in VSM_CSIRO.m)
  k_dc = eta_1/(Vdc_n*m_p)    [VSM.m]    (also in VSM_CSIRO.m)
  K_p = (1/Vdc_n)    [VSM.m]    (also in VSM_CSIRO.m)
  K_r = 1/R_dc    [VSM.m]    (also in VSM_CSIRO.m)
  Kff_i = 1    [VSM.m]    (also in VSM_CSIRO.m)
  Kff_v = 1    [VSM.m]    (also in VSM_CSIRO.m)
  Ki_i = (1/n)*1.19    (= 0.00595)    [VSM.m]    (also in VSM_CSIRO.m)
  Ki_i_gfl = (1/n_gfl) * Ki_i_unit_gfl    (= 0.571198664289)    [DER_param.m]
  Ki_v = (n)*1.161022    (= 232.2044)    [VSM.m]    (also in VSM_CSIRO.m)
  ki_v_ac = 4*5.2500e-04    (= 0.0021)    [VSM.m]    (also in VSM_CSIRO.m)
  Kp_i = 0.738891    [VSM.m]    (also in VSM_CSIRO.m)
  Kp_i_gfl = (1/n_gfl) * Kp_i_unit_gfl    (= 0.00909090909091)    [DER_param.m]
  Kp_v = 0.52    [VSM.m]    (also in VSM_CSIRO.m)
  kp_v_ac = 0.001    [VSM.m]    (also in VSM_CSIRO.m)
  L1_f_gfl = (1/n_gfl) * L1_unit_gfl    (= 1.44686311902e-05)    [DER_param.m]
  L1_pu = 1*0.0186/m    (= 0.000186)    [VSM.m]    (also in VSM_CSIRO.m)
  L1_pu_gfl = 0.03    [DER_param.m]
  L2_f_gfl = (1/n_gfl) * L2_unit_gfl    (= 2.89372623803e-06)    [DER_param.m]
  L2_pu_gfl = 0.03    [DER_param.m]
  L_45 = L_lines(2)    [VSM.m]    (also in VSM_CSIRO.m)
  L_56 = L_lines(3)    [VSM.m]    (also in VSM_CSIRO.m)
  L_67 = L_lines(5)    [VSM.m]    (also in VSM_CSIRO.m)
  L_78 = L_lines(6)    [VSM.m]    (also in VSM_CSIRO.m)
  L_89 = L_lines(8)    [VSM.m]    (also in VSM_CSIRO.m)
  L_94 = L_lines(9)    [VSM.m]    (also in VSM_CSIRO.m)
  L_f = (1/n)*200*10^-6    (= 1e-06)    [VSM.m]    (also in VSM_CSIRO.m)
  Lg = (X_BY_R_gfl * Rg) / wn_gfl    [DER_param.m]    (also in initialcondition_gfm_Pooyan.m = X_BY_R*Rg/(wn); initialcondition_Pooyan.m = X_BY_R*Rg/(wn))
  n = 200    [VSM.m]    (also in VSM_CSIRO.m)
  Pgen_MW_gfl = 20    [DER_param.m]
  ps = base/3    (= 0.75)    [VSM.m]    (also in VSM_CSIRO.m)
  R1_f_gfl = (1/n_gfl) * R1_unit_gfl    (= 0.000909090909091)    [DER_param.m]
  R1_pu = 1*0.00734/m    (= 7.34e-05)    [VSM.m]    (also in VSM_CSIRO.m)
  R1_pu_gfl = 0.005    [DER_param.m]
  R2_f_gfl = (1/n_gfl) * R2_unit_gfl    (= 0.000181818181818)    [DER_param.m]
  R2_pu_gfl = 0.005    [DER_param.m]
  R_45 = R_lines(2)    [VSM.m]    (also in VSM_CSIRO.m)
  R_56 = R_lines(3)    [VSM.m]    (also in VSM_CSIRO.m)
  R_67 = R_lines(5)    [VSM.m]    (also in VSM_CSIRO.m)
  R_78 = R_lines(6)    [VSM.m]    (also in VSM_CSIRO.m)
  R_89 = R_lines(8)    [VSM.m]    (also in VSM_CSIRO.m)
  R_94 = R_lines(9)    [VSM.m]    (also in VSM_CSIRO.m)
  R_base_gfl = (3 * Vg_gfl^2) / (2 * Pn_gfl)    [DER_param.m]
  R_dc = (Vdc_n/(0.05*(S_b)/Vdc_n))    [VSM.m]    (also in VSM_CSIRO.m)
  R_f = 0.001/n    (= 5e-06)    [VSM.m]    (also in VSM_CSIRO.m)
  Rg = (3 * Vg_gfl^2) / (2 * SCR_gfl * sqrt(1 + X_BY_R_gfl^2) * Pn_gfl)    [DER_param.m]    (also in initialcondition_gfm_Pooyan.m = (3*Vg^2)/(2*SCR*sqrt(1+X_BY_R^2)*Pn); initialcondition_Pooyan.m = (3*Vg^2)/(2*SCR*sqrt(1+X_BY_R^2)*Pn))
  S_b = 100*(10^6)    (= 100000000)    [VSM.m]    (also in VSM_CSIRO.m)
  S_bt = S_b    (= 100000000)    [VSM.m]    (also in VSM_CSIRO.m)
  S_bt_gfl = S_b_gfl    (= 22000000)    [DER_param.m]
  T_en = T_load-0.5    (= 24.5)    [VSM.m]    (also in VSM_CSIRO.m = 44.5)
  T_s = 1e-4    (= 0.0001)    [VSM.m]    (also in VSM_CSIRO.m)
  tau_dc = 0.05    [VSM.m]    (also in VSM_CSIRO.m)
  tau_g = 5    [VSM.m]    (also in VSM_CSIRO.m)
  Tend = 90    [VSM.m]    (also in VSM_CSIRO.m = 50)
  ts_DER = 15    [DER_param.m]
  V1_rms = 1000    [VSM.m]    (also in VSM_CSIRO.m)
  V1_rms_gfl = 1000    [DER_param.m]
  V1_rms_tx1_gfl = 1000    [DER_param.m]
  V2_rms = 13800    [VSM.m]    (also in VSM_CSIRO.m)
  V2_rms_tx1_gfl = 13800    [DER_param.m]
  V_b = 230*(10^3)    (= 230000)    [VSM.m]    (also in VSM_CSIRO.m)
  V_m = sqrt(2/3)*V1_rms    [VSM.m]    (also in VSM_CSIRO.m)
  V_m_gfl = sqrt(2/3)*V1_rms_gfl    [DER_param.m]
  V_sg_p = sqrt(2/3)*V2_rms    [VSM.m]
  Vdc_n = 3*V_m    [VSM.m]    (also in VSM_CSIRO.m)
  Vdc_n_gfl = 2300    [DER_param.m]
  w_b = 2*pi*f_b    (= 314.159265359)    [VSM.m]    (also in VSM_CSIRO.m)
  w_b_gfl = 2*pi*f_b_gfl    (= 314.159265359)    [DER_param.m]
  w_f = 2*pi*5    (= 31.4159265359)    [VSM.m]    (also in VSM_CSIRO.m)
undefined symbols (not defined in the file or in its folder): D1, Delta, DiscIntNeverNeededParam, dspblkCoreblockFVToolHelper, gcbh, i_dc, magnitude
libraries: spsSeriesRLCBranchLib x82, spsabctodq0Lib x40, slpidlib x36, spsVoltageMeasurementLib x32, spsThreePhaseVIMeasurementLib x31, spsThreePhaseBreakerLib x26, spsGroundLib x22, spsCurrentMeasurementLib x20, spsPLL3phLib x14, spsThreePhaseTransformerTwoWindingsLib x14, simulink x13, spsThreePhaseSeriesRLCBranchLib x10
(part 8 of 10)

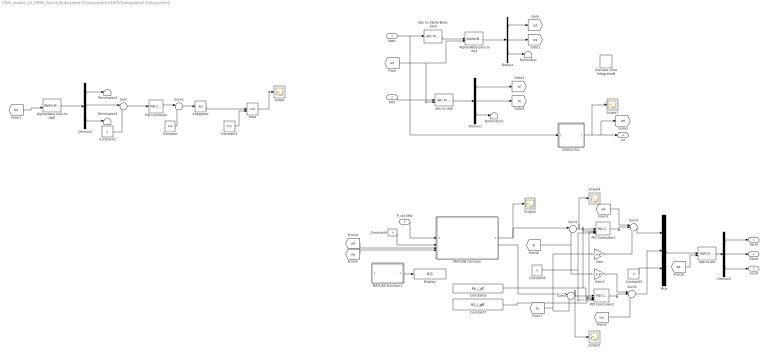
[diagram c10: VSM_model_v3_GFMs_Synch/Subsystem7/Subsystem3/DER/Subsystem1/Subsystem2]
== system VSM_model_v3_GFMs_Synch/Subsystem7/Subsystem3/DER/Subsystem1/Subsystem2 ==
  Vabc : Inport
  Iabc : Inport  Port=2
  P_ref_MW : Inport  Port=3
  Alpha-Beta-Zero to dq0 : spsAlphaBetaZerotodq0Lib/Alpha-Beta-Zero to dq0  Commented=on  Alignment=Aligned with phase A axis
  Alpha-Beta-Zero to dq1 : spsAlphaBetaZerotodq0Lib/Alpha-Beta-Zero to dq0  Alignment=Aligned with phase A axis
  Constant : Constant  Commented=on  Value=314
  Constant1 : Constant  Commented=on  Value=2*pi
  Constant2 : Constant  Commented=on  Value=0
  Constant3 : Constant  Value=Kp_i_gfl
  Constant4 : Constant  Value=0
  Constant5 : Constant  Value=0
  Constant6 : Constant  Value=0
  Constant7 : Constant  Value=Ki_i_gfl
  DSOGI-PLL : Subsystem
  Demux : Demux  Outputs=3
  Demux1 : Demux  Outputs=3
  Demux2 : Demux  Commented=on  Outputs=3
  Demux3 : Demux  Outputs=3
  Discrete-Time Integrator8 : DiscreteIntegrator  Commented=on  SampleTime=-1  ICPrevOutput=DiscIntNeverNeededParam  ICPrevScaledInput=DiscIntNeverNeededParam
  Display : Display
  Gain : Gain  Gain=w_b_gfl*L1_f_gfl
  Gain1 : Gain  Gain=w_b_gfl*L1_f_gfl
  Integrator : Integrator  Commented=on
  MATLAB Function : MATLAB Function  TreatAsAtomicUnit=on
  MATLAB Function1 : MATLAB Function  Commented=on  TreatAsAtomicUnit=on
  Mod : Math  Commented=on  Operator=mod
  Mux : Mux  Inputs=3
  PID Controller : slpidlib/PID Controller  Commented=on  Controller=PI  Form=Parallel  TimeDomain=Continuous-time  UseExternalTs=off  SampleTime=-1  IntegratorMethod=Forward Euler  FilterMethod=Forward Euler  ControllerParametersSource=internal  P=10  I=50000  UseKiTs=off  D=0  UseExternalDerivativeSource=off  N=100  UseFilter=on  TunerSelectOption=Transfer Function Based (PID Tuner App)  InitialConditionSource=internal  InitialConditionForIntegrator=0  InitialConditionForFilter=0  DifferentiatorICPrevScaledInput=0  ExternalReset=none  TrackingMode=off  Kt=1  LimitOutput=off  SatLimitsSource=internal  UpperSaturationLimit=inf  LowerSaturationLimit=-inf  LinearizeAsGain=on  AntiWindupMode=none  Kb=1  LimitIntegrator=off  UpperIntegratorSaturationLimit=inf  LowerIntegratorSaturationLimit=-inf  POutMin=[]  POutMax=[]  IOutMin=[]  IOutMax=[]  DOutMin=[]  DOutMax=[]  NOutMin=[]  NOutMax=[]  SumOutMin=[]  SumOutMax=[]  SaturationOutMin=[]  SaturationOutMax=[]  PParamMin=[]  PParamMax=[]  IParamMin=[]  IParamMax=[]  DParamMin=[]  DParamMax=[]  NParamMin=[]  NParamMax=[]  KbParamMin=[]  KbParamMax=[]  KtParamMin=[]  KtParamMax=[]  KbOutMin=[]  KbOutMax=[]  KtOutMin=[]  KtOutMax=[]  IntegratorOutMin=[]  IntegratorOutMax=[]  FilterOutMin=[]  FilterOutMax=[]  SumI1OutMin=[]  SumI1OutMax=[]  SumI2OutMin=[]  SumI2OutMax=[]  SumI3OutMin=[]  SumI3OutMax=[]  SumI4OutMin=[]  SumI4OutMax=[]  SumDOutMin=[]  SumDOutMax=[]  DifferentiatorOutMin=[]  DifferentiatorOutMax=[]  FilterDiffOutCoefMin=[]  FilterDiffOutCoefMax=[]  ReciprocalOutMin=[]  ReciprocalOutMax=[]  SumDenOutMin=[]  SumDenOutMax=[]  SumNumOutMin=[]  SumNumOutMax=[]  DivideOutMin=[]  DivideOutMax=[]  UdiffTsProdOutMin=[]  UdiffTsProdOutMax=[]  NTsProdOutMin=[]  NTsProdOutMax=[]  UintegralTsProdOutMin=[]  UintegralTsProdOutMax=[]  UngainTsProdOutMin=[]  UngainTsProdOutMax=[]  ClampingZeroOutDataTypeStr=Inherit: Inherit via back propagation  ClampingZeroOutMin=[]  ClampingZeroOutMax=[]  FilterDenConstantOutDataTypeStr=Inherit: Inherit via back propagation  FilterDenConstantOutMin=[]  FilterDenConstantOutMax=[]  PCopyOutDataTypeStr=Inherit: Inherit via back propagation  PCopyOutMin=[]  PCopyOutMax=[]  NCopyOutDataTypeStr=Inherit: Inherit via back propagation  NCopyOutMin=[]  NCopyOutMax=[]  IntegratorContinuousStateAttributes=''  IntegratorStateMustResolveToSignalObject=off  IntegratorRTWStateStorageClass=Auto  FilterContinuousStateAttributes=''  FilterStateMustResolveToSignalObject=off  FilterRTWStateStorageClass=Auto  ParallelPVariant=InternalParameters  IdealPVariant=Disabled  IVariant=InternalParameters  DVariant=Disabled  IntegratorVariant=Continuous  SatVariant=Disabled  AWVariant=Passthrough  PCopyVariant=Disabled  TRVariant=Disabled  FdbkBlocksVariant=Forward  IdealPFdbkVariant=Disabled  SatFdbkVariant=Disabled  DerivativeFilterVariant=Disabled  NVariant=Disabled  NCopyVariant=Disabled_SignalSpec  FilterICVariant=Disabled  IntegratorICVariant=InternalICs  ExternalResetVariant=Disabled  TRSumVariant=Passthrough  SumFdbkVariant=Disabled  SumVariant=Sum_PI  TsampFilterVariant=InternalTs  TsampNgainVariant=Passthrough  TsampIntegralVariant=Disabled_SignalSpec  ExternalSaturationOutDataTypeStr=Inherit: Same as second input  DerivativeSourceVariant=Disabled  PreIntVariant=InternalPreInt
  PID Controller1 : slpidlib/PID Controller  Controller=PI  Form=Parallel  TimeDomain=Continuous-time  UseExternalTs=off  SampleTime=-1  IntegratorMethod=Forward Euler  FilterMethod=Forward Euler  ControllerParametersSource=external  P=Kp_i_gfl  I=Ki_i_gfl  UseKiTs=off  D=0  UseExternalDerivativeSource=off  N=100  UseFilter=on  TunerSelectOption=Transfer Function Based (PID Tuner App)  InitialConditionSource=internal  InitialConditionForIntegrator=0  InitialConditionForFilter=0  DifferentiatorICPrevScaledInput=0  ExternalReset=level  TrackingMode=off  Kt=1  LimitOutput=off  SatLimitsSource=internal  UpperSaturationLimit=inf  LowerSaturationLimit=-inf  LinearizeAsGain=on  AntiWindupMode=none  Kb=1  LimitIntegrator=off  UpperIntegratorSaturationLimit=inf  LowerIntegratorSaturationLimit=-inf  POutMin=[]  POutMax=[]  IOutMin=[]  IOutMax=[]  DOutMin=[]  DOutMax=[]  NOutMin=[]  NOutMax=[]  SumOutMin=[]  SumOutMax=[]  SaturationOutMin=[]  SaturationOutMax=[]  PParamMin=[]  PParamMax=[]  IParamMin=[]  IParamMax=[]  DParamMin=[]  DParamMax=[]  NParamMin=[]  NParamMax=[]  KbParamMin=[]  KbParamMax=[]  KtParamMin=[]  KtParamMax=[]  KbOutMin=[]  KbOutMax=[]  KtOutMin=[]  KtOutMax=[]  IntegratorOutMin=[]  IntegratorOutMax=[]  FilterOutMin=[]  FilterOutMax=[]  SumI1OutMin=[]  SumI1OutMax=[]  SumI2OutMin=[]  SumI2OutMax=[]  SumI3OutMin=[]  SumI3OutMax=[]  SumI4OutMin=[]  SumI4OutMax=[]  SumDOutMin=[]  SumDOutMax=[]  DifferentiatorOutMin=[]  DifferentiatorOutMax=[]  FilterDiffOutCoefMin=[]  FilterDiffOutCoefMax=[]  ReciprocalOutMin=[]  ReciprocalOutMax=[]  SumDenOutMin=[]  SumDenOutMax=[]  SumNumOutMin=[]  SumNumOutMax=[]  DivideOutMin=[]  DivideOutMax=[]  UdiffTsProdOutMin=[]  UdiffTsProdOutMax=[]  NTsProdOutMin=[]  NTsProdOutMax=[]  UintegralTsProdOutMin=[]  UintegralTsProdOutMax=[]  UngainTsProdOutMin=[]  UngainTsProdOutMax=[]  ClampingZeroOutDataTypeStr=Inherit: Inherit via back propagation  ClampingZeroOutMin=[]  ClampingZeroOutMax=[]  FilterDenConstantOutDataTypeStr=Inherit: Inherit via back propagation  FilterDenConstantOutMin=[]  FilterDenConstantOutMax=[]  PCopyOutDataTypeStr=Inherit: Inherit via back propagation  PCopyOutMin=[]  PCopyOutMax=[]  NCopyOutDataTypeStr=Inherit: Inherit via back propagation  NCopyOutMin=[]  NCopyOutMax=[]  IntegratorContinuousStateAttributes=''  IntegratorStateMustResolveToSignalObject=off  IntegratorRTWStateStorageClass=Auto  FilterContinuousStateAttributes=''  FilterStateMustResolveToSignalObject=off  FilterRTWStateStorageClass=Auto  ParallelPVariant=ExternalParameters  IdealPVariant=Disabled  IVariant=ExternalParameters  DVariant=Disabled  IntegratorVariant=Continuous  SatVariant=Disabled  AWVariant=Passthrough  PCopyVariant=Disabled  TRVariant=Disabled  FdbkBlocksVariant=Forward  IdealPFdbkVariant=Disabled  SatFdbkVariant=Disabled  DerivativeFilterVariant=Disabled  NVariant=Disabled  NCopyVariant=Disabled_SignalSpec  FilterICVariant=Disabled  IntegratorICVariant=InternalICs  ExternalResetVariant=ExternalReset  TRSumVariant=Passthrough  SumFdbkVariant=Disabled  SumVariant=Sum_PI  TsampFilterVariant=InternalTs  TsampNgainVariant=Passthrough  TsampIntegralVariant=Disabled_SignalSpec  ExternalSaturationOutDataTypeStr=Inherit: Same as second input  DerivativeSourceVariant=Disabled  PreIntVariant=InternalPreInt
  PID Controller2 : slpidlib/PID Controller  Controller=PI  Form=Parallel  TimeDomain=Continuous-time  UseExternalTs=off  SampleTime=-1  IntegratorMethod=Forward Euler  FilterMethod=Forward Euler  ControllerParametersSource=external  P=Kp_i_gfl  I=Ki_i_gfl  UseKiTs=off  D=0  UseExternalDerivativeSource=off  N=100  UseFilter=on  TunerSelectOption=Transfer Function Based (PID Tuner App)  InitialConditionSource=internal  InitialConditionForIntegrator=0  InitialConditionForFilter=0  DifferentiatorICPrevScaledInput=0  ExternalReset=level  TrackingMode=off  Kt=1  LimitOutput=off  SatLimitsSource=internal  UpperSaturationLimit=inf  LowerSaturationLimit=-inf  LinearizeAsGain=on  AntiWindupMode=none  Kb=1  LimitIntegrator=off  UpperIntegratorSaturationLimit=inf  LowerIntegratorSaturationLimit=-inf  POutMin=[]  POutMax=[]  IOutMin=[]  IOutMax=[]  DOutMin=[]  DOutMax=[]  NOutMin=[]  NOutMax=[]  SumOutMin=[]  SumOutMax=[]  SaturationOutMin=[]  SaturationOutMax=[]  PParamMin=[]  PParamMax=[]  IParamMin=[]  IParamMax=[]  DParamMin=[]  DParamMax=[]  NParamMin=[]  NParamMax=[]  KbParamMin=[]  KbParamMax=[]  KtParamMin=[]  KtParamMax=[]  KbOutMin=[]  KbOutMax=[]  KtOutMin=[]  KtOutMax=[]  IntegratorOutMin=[]  IntegratorOutMax=[]  FilterOutMin=[]  FilterOutMax=[]  SumI1OutMin=[]  SumI1OutMax=[]  SumI2OutMin=[]  SumI2OutMax=[]  SumI3OutMin=[]  SumI3OutMax=[]  SumI4OutMin=[]  SumI4OutMax=[]  SumDOutMin=[]  SumDOutMax=[]  DifferentiatorOutMin=[]  DifferentiatorOutMax=[]  FilterDiffOutCoefMin=[]  FilterDiffOutCoefMax=[]  ReciprocalOutMin=[]  ReciprocalOutMax=[]  SumDenOutMin=[]  SumDenOutMax=[]  SumNumOutMin=[]  SumNumOutMax=[]  DivideOutMin=[]  DivideOutMax=[]  UdiffTsProdOutMin=[]  UdiffTsProdOutMax=[]  NTsProdOutMin=[]  NTsProdOutMax=[]  UintegralTsProdOutMin=[]  UintegralTsProdOutMax=[]  UngainTsProdOutMin=[]  UngainTsProdOutMax=[]  ClampingZeroOutDataTypeStr=Inherit: Inherit via back propagation  ClampingZeroOutMin=[]  ClampingZeroOutMax=[]  FilterDenConstantOutDataTypeStr=Inherit: Inherit via back propagation  FilterDenConstantOutMin=[]  FilterDenConstantOutMax=[]  PCopyOutDataTypeStr=Inherit: Inherit via back propagation  PCopyOutMin=[]  PCopyOutMax=[]  NCopyOutDataTypeStr=Inherit: Inherit via back propagation  NCopyOutMin=[]  NCopyOutMax=[]  IntegratorContinuousStateAttributes=''  IntegratorStateMustResolveToSignalObject=off  IntegratorRTWStateStorageClass=Auto  FilterContinuousStateAttributes=''  FilterStateMustResolveToSignalObject=off  FilterRTWStateStorageClass=Auto  ParallelPVariant=ExternalParameters  IdealPVariant=Disabled  IVariant=ExternalParameters  DVariant=Disabled  IntegratorVariant=Continuous  SatVariant=Disabled  AWVariant=Passthrough  PCopyVariant=Disabled  TRVariant=Disabled  FdbkBlocksVariant=Forward  IdealPFdbkVariant=Disabled  SatFdbkVariant=Disabled  DerivativeFilterVariant=Disabled  NVariant=Disabled  NCopyVariant=Disabled_SignalSpec  FilterICVariant=Disabled  IntegratorICVariant=InternalICs  ExternalResetVariant=ExternalReset  TRSumVariant=Passthrough  SumFdbkVariant=Disabled  SumVariant=Sum_PI  TsampFilterVariant=InternalTs  TsampNgainVariant=Passthrough  TsampIntegralVariant=Disabled_SignalSpec  ExternalSaturationOutDataTypeStr=Inherit: Same as second input  DerivativeSourceVariant=Disabled  PreIntVariant=InternalPreInt
  Scope{,1..4} (5 alike) : Scope
  Sum : Sum  Commented=on  Inputs=|-+
  Sum1 : Sum  Commented=on  Inputs=|++
  Sum2 : Sum  Inputs=|+-
  Sum3 : Sum  Inputs=|++-
  Sum4 : Sum  Inputs=|+-
  Sum5 : Sum  Inputs=|+++
  Terminator{,1..3} (4 alike) : Terminator
  abc to Alpha-Beta-Zero : spsabctoAlphaBetaZeroLib/abc to Alpha-Beta-Zero
  abc to dq0 : spsabctodq0Lib/abc to dq0  Alignment=Aligned with phase A axis
  dq0 to abc : spsdq0toabcLib/dq0 to abc  Alignment=Aligned with phase A axis
  Varef : Outport
  Vbref : Outport  Port=2
  Vcref : Outport  Port=3
  wt : Outport  Port=4
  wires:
  Demux/1 -> [ud]
  Alpha-Beta-Zero to dq0/1 -> Demux2/1
  Demux2/3 -> Terminator3/1
  Constant2/1 -> Sum/2
  Demux1/3 -> Terminator1/1
  Iabc/1 -> abc to dq0/1
  abc to dq0/1 -> Demux1/1
  Demux1/2 -> [iq]
  Demux/2 -> [uq]
  Alpha-Beta-Zero to dq1/1 -> Demux/1
  Sum/1 -> PID Controller/1
  abc to Alpha-Beta-Zero/1 -> Alpha-Beta-Zero to dq1/1
  Vabc/1 -> DSOGI-PLL/1(abc), abc to Alpha-Beta-Zero/1
  Demux1/1 -> [id]
  Demux2/1 -> Terminator2/1
  Demux/3 -> Terminator/1
  Constant/1 -> Sum1/2
  Constant1/1 -> Mod/2
  Demux2/2 -> Sum/1
  PID Controller/1 -> Sum1/1
  Sum1/1 -> Integrator/1
  Mod/1 -> Scope/1
  Integrator/1 -> Mod/1
  DSOGI-PLL/1(theta_pcc) -> Scope1/1, wt/1, [wt]
  [wt] -> Alpha-Beta-Zero to dq1/2, abc to dq0/2
  [wt] -> Alpha-Beta-Zero to dq0/2
  PID Controller2/1 -> Sum5/2
  Constant5/1 -> Mux/3
  MATLAB Function/1(id_ref) -> Scope2/1, Sum2/1
  Sum3/1 -> Mux/1
  PID Controller1/1 -> Sum3/2
  Sum2/1 -> Scope4/1, PID Controller1/1
  P_ref_MW/1 -> MATLAB Function/1(P_ref_MW)
  Constant6/1 -> PID Controller2/4, PID Controller1/4
  Gain/1 -> Sum3/3
  [ud] -> Sum3/1
  Demux3/2 -> Vbref/1
  dq0 to abc/1 -> Demux3/1
  Constant7/1 -> PID Controller1/3, PID Controller2/3
  [uq] -> Sum5/3
  Sum5/1 -> Mux/2
  [wt] -> dq0 to abc/2
  Mux/1 -> dq0 to abc/1
  [ud] -> MATLAB Function/3(v_d)
  Gain1/1 -> Sum5/1
  Demux3/1 -> Varef/1
  MATLAB Function1/1(Q_ref_MVAr) -> Display/1
  MATLAB Function/2(iq_ref) -> Sum4/1
  Demux3/3 -> Vcref/1
  [uq] -> MATLAB Function/4(v_q)
  [id] -> Sum2/2, Gain1/1
  Constant3/1 -> PID Controller1/2, PID Controller2/2
  [iq] -> Sum4/2, Gain/1
  Sum4/1 -> Scope3/1, PID Controller2/1
  Constant4/1 -> MATLAB Function/2(Q_ref_MVAr)

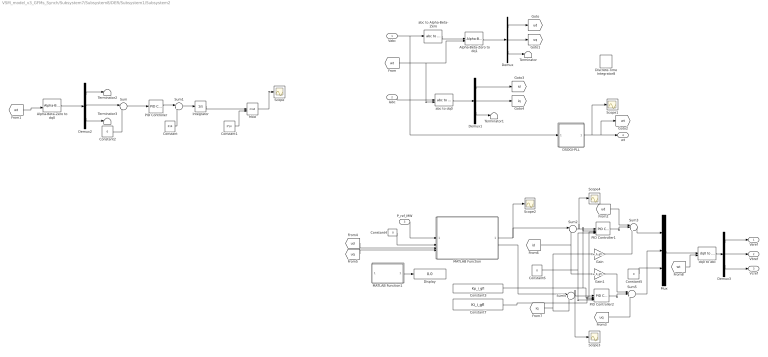
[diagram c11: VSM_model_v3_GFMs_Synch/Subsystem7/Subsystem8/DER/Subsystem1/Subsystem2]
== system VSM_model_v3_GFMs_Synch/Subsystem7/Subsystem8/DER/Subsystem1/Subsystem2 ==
  Vabc : Inport
  Iabc : Inport  Port=2
  P_ref_MW : Inport  Port=3
  Alpha-Beta-Zero to dq0 : spsAlphaBetaZerotodq0Lib/Alpha-Beta-Zero to dq0  Commented=on  Alignment=Aligned with phase A axis
  Alpha-Beta-Zero to dq1 : spsAlphaBetaZerotodq0Lib/Alpha-Beta-Zero to dq0  Alignment=Aligned with phase A axis
  Constant : Constant  Commented=on  Value=314
  Constant1 : Constant  Commented=on  Value=2*pi
  Constant2 : Constant  Commented=on  Value=0
  Constant3 : Constant  Value=Kp_i_gfl
  Constant4 : Constant  Value=0
  Constant5 : Constant  Value=0
  Constant6 : Constant  Value=0
  Constant7 : Constant  Value=Ki_i_gfl
  DSOGI-PLL : Subsystem
  Demux : Demux  Outputs=3
  Demux1 : Demux  Outputs=3
  Demux2 : Demux  Commented=on  Outputs=3
  Demux3 : Demux  Outputs=3
  Discrete-Time Integrator8 : DiscreteIntegrator  Commented=on  SampleTime=-1  ICPrevOutput=DiscIntNeverNeededParam  ICPrevScaledInput=DiscIntNeverNeededParam
  Display : Display
  Gain : Gain  Gain=w_b_gfl*L1_f_gfl
  Gain1 : Gain  Gain=w_b_gfl*L1_f_gfl
  Integrator : Integrator  Commented=on
  MATLAB Function : MATLAB Function  TreatAsAtomicUnit=on
  MATLAB Function1 : MATLAB Function  Commented=on  TreatAsAtomicUnit=on
  Mod : Math  Commented=on  Operator=mod
  Mux : Mux  Inputs=3
  PID Controller : slpidlib/PID Controller  Commented=on  Controller=PI  Form=Parallel  TimeDomain=Continuous-time  UseExternalTs=off  SampleTime=-1  IntegratorMethod=Forward Euler  FilterMethod=Forward Euler  ControllerParametersSource=internal  P=10  I=50000  UseKiTs=off  D=0  UseExternalDerivativeSource=off  N=100  UseFilter=on  TunerSelectOption=Transfer Function Based (PID Tuner App)  InitialConditionSource=internal  InitialConditionForIntegrator=0  InitialConditionForFilter=0  DifferentiatorICPrevScaledInput=0  ExternalReset=none  TrackingMode=off  Kt=1  LimitOutput=off  SatLimitsSource=internal  UpperSaturationLimit=inf  LowerSaturationLimit=-inf  LinearizeAsGain=on  AntiWindupMode=none  Kb=1  LimitIntegrator=off  UpperIntegratorSaturationLimit=inf  LowerIntegratorSaturationLimit=-inf  POutMin=[]  POutMax=[]  IOutMin=[]  IOutMax=[]  DOutMin=[]  DOutMax=[]  NOutMin=[]  NOutMax=[]  SumOutMin=[]  SumOutMax=[]  SaturationOutMin=[]  SaturationOutMax=[]  PParamMin=[]  PParamMax=[]  IParamMin=[]  IParamMax=[]  DParamMin=[]  DParamMax=[]  NParamMin=[]  NParamMax=[]  KbParamMin=[]  KbParamMax=[]  KtParamMin=[]  KtParamMax=[]  KbOutMin=[]  KbOutMax=[]  KtOutMin=[]  KtOutMax=[]  IntegratorOutMin=[]  IntegratorOutMax=[]  FilterOutMin=[]  FilterOutMax=[]  SumI1OutMin=[]  SumI1OutMax=[]  SumI2OutMin=[]  SumI2OutMax=[]  SumI3OutMin=[]  SumI3OutMax=[]  SumI4OutMin=[]  SumI4OutMax=[]  SumDOutMin=[]  SumDOutMax=[]  DifferentiatorOutMin=[]  DifferentiatorOutMax=[]  FilterDiffOutCoefMin=[]  FilterDiffOutCoefMax=[]  ReciprocalOutMin=[]  ReciprocalOutMax=[]  SumDenOutMin=[]  SumDenOutMax=[]  SumNumOutMin=[]  SumNumOutMax=[]  DivideOutMin=[]  DivideOutMax=[]  UdiffTsProdOutMin=[]  UdiffTsProdOutMax=[]  NTsProdOutMin=[]  NTsProdOutMax=[]  UintegralTsProdOutMin=[]  UintegralTsProdOutMax=[]  UngainTsProdOutMin=[]  UngainTsProdOutMax=[]  ClampingZeroOutDataTypeStr=Inherit: Inherit via back propagation  ClampingZeroOutMin=[]  ClampingZeroOutMax=[]  FilterDenConstantOutDataTypeStr=Inherit: Inherit via back propagation  FilterDenConstantOutMin=[]  FilterDenConstantOutMax=[]  PCopyOutDataTypeStr=Inherit: Inherit via back propagation  PCopyOutMin=[]  PCopyOutMax=[]  NCopyOutDataTypeStr=Inherit: Inherit via back propagation  NCopyOutMin=[]  NCopyOutMax=[]  IntegratorContinuousStateAttributes=''  IntegratorStateMustResolveToSignalObject=off  IntegratorRTWStateStorageClass=Auto  FilterContinuousStateAttributes=''  FilterStateMustResolveToSignalObject=off  FilterRTWStateStorageClass=Auto  ParallelPVariant=InternalParameters  IdealPVariant=Disabled  IVariant=InternalParameters  DVariant=Disabled  IntegratorVariant=Continuous  SatVariant=Disabled  AWVariant=Passthrough  PCopyVariant=Disabled  TRVariant=Disabled  FdbkBlocksVariant=Forward  IdealPFdbkVariant=Disabled  SatFdbkVariant=Disabled  DerivativeFilterVariant=Disabled  NVariant=Disabled  NCopyVariant=Disabled_SignalSpec  FilterICVariant=Disabled  IntegratorICVariant=InternalICs  ExternalResetVariant=Disabled  TRSumVariant=Passthrough  SumFdbkVariant=Disabled  SumVariant=Sum_PI  TsampFilterVariant=InternalTs  TsampNgainVariant=Passthrough  TsampIntegralVariant=Disabled_SignalSpec  ExternalSaturationOutDataTypeStr=Inherit: Same as second input  DerivativeSourceVariant=Disabled  PreIntVariant=InternalPreInt
  PID Controller1 : slpidlib/PID Controller  Controller=PI  Form=Parallel  TimeDomain=Continuous-time  UseExternalTs=off  SampleTime=-1  IntegratorMethod=Forward Euler  FilterMethod=Forward Euler  ControllerParametersSource=external  P=Kp_i_gfl  I=Ki_i_gfl  UseKiTs=off  D=0  UseExternalDerivativeSource=off  N=100  UseFilter=on  TunerSelectOption=Transfer Function Based (PID Tuner App)  InitialConditionSource=internal  InitialConditionForIntegrator=0  InitialConditionForFilter=0  DifferentiatorICPrevScaledInput=0  ExternalReset=level  TrackingMode=off  Kt=1  LimitOutput=off  SatLimitsSource=internal  UpperSaturationLimit=inf  LowerSaturationLimit=-inf  LinearizeAsGain=on  AntiWindupMode=none  Kb=1  LimitIntegrator=off  UpperIntegratorSaturationLimit=inf  LowerIntegratorSaturationLimit=-inf  POutMin=[]  POutMax=[]  IOutMin=[]  IOutMax=[]  DOutMin=[]  DOutMax=[]  NOutMin=[]  NOutMax=[]  SumOutMin=[]  SumOutMax=[]  SaturationOutMin=[]  SaturationOutMax=[]  PParamMin=[]  PParamMax=[]  IParamMin=[]  IParamMax=[]  DParamMin=[]  DParamMax=[]  NParamMin=[]  NParamMax=[]  KbParamMin=[]  KbParamMax=[]  KtParamMin=[]  KtParamMax=[]  KbOutMin=[]  KbOutMax=[]  KtOutMin=[]  KtOutMax=[]  IntegratorOutMin=[]  IntegratorOutMax=[]  FilterOutMin=[]  FilterOutMax=[]  SumI1OutMin=[]  SumI1OutMax=[]  SumI2OutMin=[]  SumI2OutMax=[]  SumI3OutMin=[]  SumI3OutMax=[]  SumI4OutMin=[]  SumI4OutMax=[]  SumDOutMin=[]  SumDOutMax=[]  DifferentiatorOutMin=[]  DifferentiatorOutMax=[]  FilterDiffOutCoefMin=[]  FilterDiffOutCoefMax=[]  ReciprocalOutMin=[]  ReciprocalOutMax=[]  SumDenOutMin=[]  SumDenOutMax=[]  SumNumOutMin=[]  SumNumOutMax=[]  DivideOutMin=[]  DivideOutMax=[]  UdiffTsProdOutMin=[]  UdiffTsProdOutMax=[]  NTsProdOutMin=[]  NTsProdOutMax=[]  UintegralTsProdOutMin=[]  UintegralTsProdOutMax=[]  UngainTsProdOutMin=[]  UngainTsProdOutMax=[]  ClampingZeroOutDataTypeStr=Inherit: Inherit via back propagation  ClampingZeroOutMin=[]  ClampingZeroOutMax=[]  FilterDenConstantOutDataTypeStr=Inherit: Inherit via back propagation  FilterDenConstantOutMin=[]  FilterDenConstantOutMax=[]  PCopyOutDataTypeStr=Inherit: Inherit via back propagation  PCopyOutMin=[]  PCopyOutMax=[]  NCopyOutDataTypeStr=Inherit: Inherit via back propagation  NCopyOutMin=[]  NCopyOutMax=[]  IntegratorContinuousStateAttributes=''  IntegratorStateMustResolveToSignalObject=off  IntegratorRTWStateStorageClass=Auto  FilterContinuousStateAttributes=''  FilterStateMustResolveToSignalObject=off  FilterRTWStateStorageClass=Auto  ParallelPVariant=ExternalParameters  IdealPVariant=Disabled  IVariant=ExternalParameters  DVariant=Disabled  IntegratorVariant=Continuous  SatVariant=Disabled  AWVariant=Passthrough  PCopyVariant=Disabled  TRVariant=Disabled  FdbkBlocksVariant=Forward  IdealPFdbkVariant=Disabled  SatFdbkVariant=Disabled  DerivativeFilterVariant=Disabled  NVariant=Disabled  NCopyVariant=Disabled_SignalSpec  FilterICVariant=Disabled  IntegratorICVariant=InternalICs  ExternalResetVariant=ExternalReset  TRSumVariant=Passthrough  SumFdbkVariant=Disabled  SumVariant=Sum_PI  TsampFilterVariant=InternalTs  TsampNgainVariant=Passthrough  TsampIntegralVariant=Disabled_SignalSpec  ExternalSaturationOutDataTypeStr=Inherit: Same as second input  DerivativeSourceVariant=Disabled  PreIntVariant=InternalPreInt
  PID Controller2 : slpidlib/PID Controller  Controller=PI  Form=Parallel  TimeDomain=Continuous-time  UseExternalTs=off  SampleTime=-1  IntegratorMethod=Forward Euler  FilterMethod=Forward Euler  ControllerParametersSource=external  P=Kp_i_gfl  I=Ki_i_gfl  UseKiTs=off  D=0  UseExternalDerivativeSource=off  N=100  UseFilter=on  TunerSelectOption=Transfer Function Based (PID Tuner App)  InitialConditionSource=internal  InitialConditionForIntegrator=0  InitialConditionForFilter=0  DifferentiatorICPrevScaledInput=0  ExternalReset=level  TrackingMode=off  Kt=1  LimitOutput=off  SatLimitsSource=internal  UpperSaturationLimit=inf  LowerSaturationLimit=-inf  LinearizeAsGain=on  AntiWindupMode=none  Kb=1  LimitIntegrator=off  UpperIntegratorSaturationLimit=inf  LowerIntegratorSaturationLimit=-inf  POutMin=[]  POutMax=[]  IOutMin=[]  IOutMax=[]  DOutMin=[]  DOutMax=[]  NOutMin=[]  NOutMax=[]  SumOutMin=[]  SumOutMax=[]  SaturationOutMin=[]  SaturationOutMax=[]  PParamMin=[]  PParamMax=[]  IParamMin=[]  IParamMax=[]  DParamMin=[]  DParamMax=[]  NParamMin=[]  NParamMax=[]  KbParamMin=[]  KbParamMax=[]  KtParamMin=[]  KtParamMax=[]  KbOutMin=[]  KbOutMax=[]  KtOutMin=[]  KtOutMax=[]  IntegratorOutMin=[]  IntegratorOutMax=[]  FilterOutMin=[]  FilterOutMax=[]  SumI1OutMin=[]  SumI1OutMax=[]  SumI2OutMin=[]  SumI2OutMax=[]  SumI3OutMin=[]  SumI3OutMax=[]  SumI4OutMin=[]  SumI4OutMax=[]  SumDOutMin=[]  SumDOutMax=[]  DifferentiatorOutMin=[]  DifferentiatorOutMax=[]  FilterDiffOutCoefMin=[]  FilterDiffOutCoefMax=[]  ReciprocalOutMin=[]  ReciprocalOutMax=[]  SumDenOutMin=[]  SumDenOutMax=[]  SumNumOutMin=[]  SumNumOutMax=[]  DivideOutMin=[]  DivideOutMax=[]  UdiffTsProdOutMin=[]  UdiffTsProdOutMax=[]  NTsProdOutMin=[]  NTsProdOutMax=[]  UintegralTsProdOutMin=[]  UintegralTsProdOutMax=[]  UngainTsProdOutMin=[]  UngainTsProdOutMax=[]  ClampingZeroOutDataTypeStr=Inherit: Inherit via back propagation  ClampingZeroOutMin=[]  ClampingZeroOutMax=[]  FilterDenConstantOutDataTypeStr=Inherit: Inherit via back propagation  FilterDenConstantOutMin=[]  FilterDenConstantOutMax=[]  PCopyOutDataTypeStr=Inherit: Inherit via back propagation  PCopyOutMin=[]  PCopyOutMax=[]  NCopyOutDataTypeStr=Inherit: Inherit via back propagation  NCopyOutMin=[]  NCopyOutMax=[]  IntegratorContinuousStateAttributes=''  IntegratorStateMustResolveToSignalObject=off  IntegratorRTWStateStorageClass=Auto  FilterContinuousStateAttributes=''  FilterStateMustResolveToSignalObject=off  FilterRTWStateStorageClass=Auto  ParallelPVariant=ExternalParameters  IdealPVariant=Disabled  IVariant=ExternalParameters  DVariant=Disabled  IntegratorVariant=Continuous  SatVariant=Disabled  AWVariant=Passthrough  PCopyVariant=Disabled  TRVariant=Disabled  FdbkBlocksVariant=Forward  IdealPFdbkVariant=Disabled  SatFdbkVariant=Disabled  DerivativeFilterVariant=Disabled  NVariant=Disabled  NCopyVariant=Disabled_SignalSpec  FilterICVariant=Disabled  IntegratorICVariant=InternalICs  ExternalResetVariant=ExternalReset  TRSumVariant=Passthrough  SumFdbkVariant=Disabled  SumVariant=Sum_PI  TsampFilterVariant=InternalTs  TsampNgainVariant=Passthrough  TsampIntegralVariant=Disabled_SignalSpec  ExternalSaturationOutDataTypeStr=Inherit: Same as second input  DerivativeSourceVariant=Disabled  PreIntVariant=InternalPreInt
  Scope{,1..4} (5 alike) : Scope
  Sum : Sum  Commented=on  Inputs=|-+
  Sum1 : Sum  Commented=on  Inputs=|++
  Sum2 : Sum  Inputs=|+-
  Sum3 : Sum  Inputs=|++-
  Sum4 : Sum  Inputs=|+-
  Sum5 : Sum  Inputs=|+++
  Terminator{,1..3} (4 alike) : Terminator
  abc to Alpha-Beta-Zero : spsabctoAlphaBetaZeroLib/abc to Alpha-Beta-Zero
  abc to dq0 : spsabctodq0Lib/abc to dq0  Alignment=Aligned with phase A axis
  dq0 to abc : spsdq0toabcLib/dq0 to abc  Alignment=Aligned with phase A axis
  Varef : Outport
  Vbref : Outport  Port=2
  Vcref : Outport  Port=3
  wt : Outport  Port=4
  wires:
  Demux/1 -> [ud]
  Alpha-Beta-Zero to dq0/1 -> Demux2/1
  Demux2/3 -> Terminator3/1
  Constant2/1 -> Sum/2
  Demux1/3 -> Terminator1/1
  Iabc/1 -> abc to dq0/1
  abc to dq0/1 -> Demux1/1
  Demux1/2 -> [iq]
  Demux/2 -> [uq]
  Alpha-Beta-Zero to dq1/1 -> Demux/1
  Sum/1 -> PID Controller/1
  abc to Alpha-Beta-Zero/1 -> Alpha-Beta-Zero to dq1/1
  Vabc/1 -> DSOGI-PLL/1(abc), abc to Alpha-Beta-Zero/1
  Demux1/1 -> [id]
  Demux2/1 -> Terminator2/1
  Demux/3 -> Terminator/1
  Constant/1 -> Sum1/2
  Constant1/1 -> Mod/2
  Demux2/2 -> Sum/1
  PID Controller/1 -> Sum1/1
  Sum1/1 -> Integrator/1
  Mod/1 -> Scope/1
  Integrator/1 -> Mod/1
  DSOGI-PLL/1(theta_pcc) -> Scope1/1, wt/1, [wt]
  [wt] -> Alpha-Beta-Zero to dq1/2, abc to dq0/2
  [wt] -> Alpha-Beta-Zero to dq0/2
  PID Controller2/1 -> Sum5/2
  Constant5/1 -> Mux/3
  MATLAB Function/1(id_ref) -> Scope2/1, Sum2/1
  Sum3/1 -> Mux/1
  PID Controller1/1 -> Sum3/2
  Sum2/1 -> Scope4/1, PID Controller1/1
  P_ref_MW/1 -> MATLAB Function/1(P_ref_MW)
  Constant6/1 -> PID Controller2/4, PID Controller1/4
  Gain/1 -> Sum3/3
  [ud] -> Sum3/1
  Demux3/2 -> Vbref/1
  dq0 to abc/1 -> Demux3/1
  Constant7/1 -> PID Controller1/3, PID Controller2/3
  [uq] -> Sum5/3
  Sum5/1 -> Mux/2
  [wt] -> dq0 to abc/2
  Mux/1 -> dq0 to abc/1
  [ud] -> MATLAB Function/3(v_d)
  Gain1/1 -> Sum5/1
  Demux3/1 -> Varef/1
  MATLAB Function1/1(Q_ref_MVAr) -> Display/1
  MATLAB Function/2(iq_ref) -> Sum4/1
  Demux3/3 -> Vcref/1
  [uq] -> MATLAB Function/4(v_q)
  [id] -> Sum2/2, Gain1/1
  Constant3/1 -> PID Controller1/2, PID Controller2/2
  [iq] -> Sum4/2, Gain/1
  Sum4/1 -> Scope3/1, PID Controller2/1
  Constant4/1 -> MATLAB Function/2(Q_ref_MVAr)

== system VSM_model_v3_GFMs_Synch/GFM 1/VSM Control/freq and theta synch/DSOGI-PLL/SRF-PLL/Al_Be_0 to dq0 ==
  Al_Be_0 : Inport
  wt : Inport  Port=2
  Fcn : Fcn  Expr=u[1]*cos(u[4]) + u[2]*sin(u[4])
  Fcn1 : Fcn  Expr=-u[1]*sin(u[4]) + u[2]*cos(u[4])
  Fcn2 : Fcn  Expr=u[3]
  Mux1 : Mux  Inputs=[3 1]
  Mux2 : Mux  Inputs=3
  dq0 : Outport  VectorParamsAs1DForOutWhenUnconnected=off
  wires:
  Mux1/1 -> Fcn/1, Fcn2/1, Fcn1/1
  Fcn1/1 -> Mux2/2
  wt/1 -> Mux1/2
  Mux2/1 -> dq0/1
  Al_Be_0/1 -> Mux1/1
  Fcn2/1 -> Mux2/3
  Fcn/1 -> Mux2/1

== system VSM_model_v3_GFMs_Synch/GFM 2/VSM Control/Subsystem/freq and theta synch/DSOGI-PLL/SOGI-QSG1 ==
  Va : Inport
  f : Inport  Port=2
  2*pi : Gain  Gain=2*pi
  Divide1 : Product  Inputs=**
  Divide2 : Product  Inputs=**
  Integrator : Integrator
  Integrator1 : Integrator
  K : Gain  Gain=0.8
  Sum1 : Sum  Inputs=|+-
  Sum2 : Sum  Inputs=-+|
  vad : Outport  VectorParamsAs1DForOutWhenUnconnected=off
  vaq : Outport  Port=2  VectorParamsAs1DForOutWhenUnconnected=off
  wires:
  2*pi/1 -> Divide1/2, Divide2/2
  Va/1 -> Sum2/2
  Integrator1/1 -> vaq/1, Sum1/2
  Divide2/1 -> Integrator1/1
  Integrator/1 -> vad/1, Divide2/1, Sum2/1
  Sum2/1 -> K/1
  K/1 -> Sum1/1
  Sum1/1 -> Divide1/1
  Divide1/1 -> Integrator/1
  f/1 -> 2*pi/1

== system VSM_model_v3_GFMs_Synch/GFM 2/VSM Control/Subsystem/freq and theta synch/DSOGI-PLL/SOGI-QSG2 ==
  f : Inport
  Vb : Inport  Port=2
  2*pi : Gain  Gain=2*pi
  Divide1 : Product  Inputs=**
  Divide2 : Product  Inputs=**
  Integrator : Integrator
  Integrator1 : Integrator
  K : Gain  Gain=0.8
  Sum1 : Sum  Inputs=|+-
  Sum2 : Sum  Inputs=-+|
  vbd : Outport  VectorParamsAs1DForOutWhenUnconnected=off
  vbq : Outport  Port=2  VectorParamsAs1DForOutWhenUnconnected=off
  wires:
  Divide1/1 -> Integrator/1
  Sum1/1 -> Divide1/1
  K/1 -> Sum1/1
  Sum2/1 -> K/1
  Integrator/1 -> Sum2/1, Divide2/1, vbd/1
  Divide2/1 -> Integrator1/1
  Integrator1/1 -> Sum1/2, vbq/1
  Vb/1 -> Sum2/2
  2*pi/1 -> Divide2/2, Divide1/2
  f/1 -> 2*pi/1

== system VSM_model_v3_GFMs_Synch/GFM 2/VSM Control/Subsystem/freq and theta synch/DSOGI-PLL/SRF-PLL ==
  al-be-0 : Inport
  1/2/pi : Gain  Gain=1/(2*pi)
  2 : Constant  Value=2*pi
  3 : Constant  Value=0
  Al_Be_0 to dq0 : Subsystem
  Integrator : Integrator
  Math Function : Math  Operator=mod  SignedPower=on
  "PI " : slpidlib/PID Controller  Controller=PI  Form=Parallel  TimeDomain=Continuous-time  UseExternalTs=off  SampleTime=100e-6  IntegratorMethod=Forward Euler  FilterMethod=Forward Euler  ControllerParametersSource=internal  P=10  I=30  UseKiTs=off  D=0  UseExternalDerivativeSource=off  N=100  UseFilter=on  TunerSelectOption=Transfer Function Based (PID Tuner App)  InitialConditionSource=internal  InitialConditionForIntegrator=0  InitialConditionForFilter=0  DifferentiatorICPrevScaledInput=0  ExternalReset=none  TrackingMode=off  Kt=1  LimitOutput=off  SatLimitsSource=internal  UpperSaturationLimit=inf  LowerSaturationLimit=-inf  LinearizeAsGain=on  AntiWindupMode=none  Kb=1  LimitIntegrator=off  UpperIntegratorSaturationLimit=inf  LowerIntegratorSaturationLimit=-inf  POutMin=[]  POutMax=[]  IOutMin=[]  IOutMax=[]  DOutMin=[]  DOutMax=[]  NOutMin=[]  NOutMax=[]  SumOutMin=[]  SumOutMax=[]  SaturationOutMin=[]  SaturationOutMax=[]  PParamMin=[]  PParamMax=[]  IParamMin=[]  IParamMax=[]  DParamMin=[]  DParamMax=[]  NParamMin=[]  NParamMax=[]  KbParamMin=[]  KbParamMax=[]  KtParamMin=[]  KtParamMax=[]  KbOutMin=[]  KbOutMax=[]  KtOutMin=[]  KtOutMax=[]  IntegratorOutMin=[]  IntegratorOutMax=[]  FilterOutMin=[]  FilterOutMax=[]  SumI1OutMin=[]  SumI1OutMax=[]  SumI2OutMin=[]  SumI2OutMax=[]  SumI3OutMin=[]  SumI3OutMax=[]  SumI4OutMin=[]  SumI4OutMax=[]  SumDOutMin=[]  SumDOutMax=[]  DifferentiatorOutMin=[]  DifferentiatorOutMax=[]  FilterDiffOutCoefMin=[]  FilterDiffOutCoefMax=[]  ReciprocalOutMin=[]  ReciprocalOutMax=[]  SumDenOutMin=[]  SumDenOutMax=[]  SumNumOutMin=[]  SumNumOutMax=[]  DivideOutMin=[]  DivideOutMax=[]  UdiffTsProdOutMin=[]  UdiffTsProdOutMax=[]  NTsProdOutMin=[]  NTsProdOutMax=[]  UintegralTsProdOutMin=[]  UintegralTsProdOutMax=[]  UngainTsProdOutMin=[]  UngainTsProdOutMax=[]  ClampingZeroOutDataTypeStr=Inherit: Inherit via back propagation  ClampingZeroOutMin=[]  ClampingZeroOutMax=[]  FilterDenConstantOutDataTypeStr=Inherit: Inherit via back propagation  FilterDenConstantOutMin=[]  FilterDenConstantOutMax=[]  PCopyOutDataTypeStr=Inherit: Inherit via back propagation  PCopyOutMin=[]  PCopyOutMax=[]  NCopyOutDataTypeStr=Inherit: Inherit via back propagation  NCopyOutMin=[]  NCopyOutMax=[]  IntegratorContinuousStateAttributes=''  IntegratorStateMustResolveToSignalObject=off  IntegratorRTWStateStorageClass=Auto  FilterContinuousStateAttributes=''  FilterStateMustResolveToSignalObject=off  FilterRTWStateStorageClass=Auto  ParallelPVariant=InternalParameters  IdealPVariant=Disabled  IVariant=InternalParameters  DVariant=Disabled  IntegratorVariant=Continuous  SatVariant=Disabled  AWVariant=Passthrough  PCopyVariant=Disabled  TRVariant=Disabled  FdbkBlocksVariant=Forward  IdealPFdbkVariant=Disabled  SatFdbkVariant=Disabled  DerivativeFilterVariant=Disabled  NVariant=Disabled  NCopyVariant=Disabled_SignalSpec  FilterICVariant=Disabled  IntegratorICVariant=InternalICs  ExternalResetVariant=Disabled  TRSumVariant=Passthrough  SumFdbkVariant=Disabled  SumVariant=Sum_PI  TsampFilterVariant=InternalTs  TsampNgainVariant=Passthrough  TsampIntegralVariant=Disabled_SignalSpec  ExternalSaturationOutDataTypeStr=Inherit: Same as second input  DerivativeSourceVariant=Disabled  PreIntVariant=InternalPreInt
  Second-Order Filter : spsSecondOrderFilterLib/Second-Order Filter  FilterType=Lowpass  Fo=5  Zeta=0.707  Ts=0  Initialize=off  Vac_Init="[0,  0,  50]"  Vdc_Init=0  PlotResponse=off  FreqRange=[0, 500, 1]
  Selector : Selector  InputPortWidth=3  IndexOptions=Index vector (dialog)  Indices=1  OutputSizes=1
  Sum1 : Sum  Inputs=|++
  Sum2 : Sum  Inputs=|+-
  w : Constant  Value=100*pi
  theta_pcc : Outport  VectorParamsAs1DForOutWhenUnconnected=off
  f : Outport  Port=2  VectorParamsAs1DForOutWhenUnconnected=off
  w_pcc : Outport  Port=3  VectorParamsAs1DForOutWhenUnconnected=off
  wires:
  1/2/pi/1 -> Second-Order Filter/1
  Integrator/1 -> Al_Be_0 to dq0/2(wt), theta_pcc/1, Math Function/1
  2/1 -> Math Function/2
  Sum1/1 -> Integrator/1, w_pcc/1, 1/2/pi/1
  w/1 -> Sum1/2
  "PI "/1 -> Sum1/1
  Sum2/1 -> "PI "/1
  al-be-0/1 -> Al_Be_0 to dq0/1(Al_Be_0)
  3/1 -> Sum2/2
  Al_Be_0 to dq0/1(dq0) -> Selector/1
  Selector/1 -> Sum2/1
  Second-Order Filter/1 -> f/1

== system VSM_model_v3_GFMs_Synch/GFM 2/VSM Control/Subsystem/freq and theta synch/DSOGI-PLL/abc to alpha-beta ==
  abc : Inport
  Gain1 : Gain  Gain=(2/3)  SaturateOnIntegerOverflow=on
  Gain3 : Gain  Gain="[ 1   -1/2   -1/2; 0   sqrt(3)/2   -sqrt(3)/2 ]"  Multiplication=Matrix(K*u) (u vector)  SaturateOnIntegerOverflow=on
  al_be : Outport  VectorParamsAs1DForOutWhenUnconnected=off
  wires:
  abc/1 -> Gain3/1
  Gain1/1 -> al_be/1
  Gain3/1 -> Gain1/1

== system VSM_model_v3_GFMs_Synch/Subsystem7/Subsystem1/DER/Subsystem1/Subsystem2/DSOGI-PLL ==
  note: PI
  note: dqPLL: PID _ filtering
  abc : Inport
  Abs5 : Abs
  Constant : Constant  Value=100*pi
  Constant17 : Constant  Value=100*pi
  Constant18 : Constant  Value=0
  Delay6 : Delay  DelayLength=1
  Delay7 : Delay  DelayLength=1
  Demux1 : Demux  Outputs=2
  Discrete-Time Integrator : DiscreteIntegrator  Commented=on  SampleTime=-1  ICPrevOutput=DiscIntNeverNeededParam  ICPrevScaledInput=DiscIntNeverNeededParam
  Discrete-Time Integrator4 : DiscreteIntegrator  SampleTime=-1  ICPrevOutput=DiscIntNeverNeededParam  ICPrevScaledInput=DiscIntNeverNeededParam
  Embedded MATLAB Function27 : MATLAB Function  TreatAsAtomicUnit=on
  Embedded MATLAB Function7 : MATLAB Function  TreatAsAtomicUnit=on
  Gain2 : Gain  Gain=0.296
  Gain3 : Gain  Gain=0.296/(21.7e-3)
  Gain6 : Gain  Gain=1/2
  PID Controller : slpidlib/PID Controller  Commented=on  Controller=PID  Form=Parallel  TimeDomain=Discrete-time  UseExternalTs=off  SampleTime=-1  IntegratorMethod=Forward Euler  FilterMethod=Forward Euler  ControllerParametersSource=internal  P=10  I=30  UseKiTs=off  D=0  UseExternalDerivativeSource=off  N=100  UseFilter=on  TunerSelectOption=Transfer Function Based (PID Tuner App)  InitialConditionSource=internal  InitialConditionForIntegrator=0  InitialConditionForFilter=0  DifferentiatorICPrevScaledInput=0  ExternalReset=none  TrackingMode=off  Kt=1  LimitOutput=off  SatLimitsSource=internal  UpperSaturationLimit=inf  LowerSaturationLimit=-inf  LinearizeAsGain=on  AntiWindupMode=none  Kb=1  LimitIntegrator=off  UpperIntegratorSaturationLimit=inf  LowerIntegratorSaturationLimit=-inf  POutMin=[]  POutMax=[]  IOutMin=[]  IOutMax=[]  DOutMin=[]  DOutMax=[]  NOutMin=[]  NOutMax=[]  SumOutMin=[]  SumOutMax=[]  SaturationOutMin=[]  SaturationOutMax=[]  PParamMin=[]  PParamMax=[]  IParamMin=[]  IParamMax=[]  DParamMin=[]  DParamMax=[]  NParamMin=[]  NParamMax=[]  KbParamMin=[]  KbParamMax=[]  KtParamMin=[]  KtParamMax=[]  KbOutMin=[]  KbOutMax=[]  KtOutMin=[]  KtOutMax=[]  IntegratorOutMin=[]  IntegratorOutMax=[]  FilterOutMin=[]  FilterOutMax=[]  SumI1OutMin=[]  SumI1OutMax=[]  SumI2OutMin=[]  SumI2OutMax=[]  SumI3OutMin=[]  SumI3OutMax=[]  SumI4OutMin=[]  SumI4OutMax=[]  SumDOutMin=[]  SumDOutMax=[]  DifferentiatorOutMin=[]  DifferentiatorOutMax=[]  FilterDiffOutCoefMin=[]  FilterDiffOutCoefMax=[]  ReciprocalOutMin=[]  ReciprocalOutMax=[]  SumDenOutMin=[]  SumDenOutMax=[]  SumNumOutMin=[]  SumNumOutMax=[]  DivideOutMin=[]  DivideOutMax=[]  UdiffTsProdOutMin=[]  UdiffTsProdOutMax=[]  NTsProdOutMin=[]  NTsProdOutMax=[]  UintegralTsProdOutMin=[]  UintegralTsProdOutMax=[]  UngainTsProdOutMin=[]  UngainTsProdOutMax=[]  ClampingZeroOutDataTypeStr=Inherit: Inherit via back propagation  ClampingZeroOutMin=[]  ClampingZeroOutMax=[]  FilterDenConstantOutDataTypeStr=Inherit: Inherit via back propagation  FilterDenConstantOutMin=[]  FilterDenConstantOutMax=[]  PCopyOutDataTypeStr=Inherit: Inherit via back propagation  PCopyOutMin=[]  PCopyOutMax=[]  NCopyOutDataTypeStr=Inherit: Inherit via back propagation  NCopyOutMin=[]  NCopyOutMax=[]  IntegratorContinuousStateAttributes=''  IntegratorStateMustResolveToSignalObject=off  IntegratorRTWStateStorageClass=Auto  FilterContinuousStateAttributes=''  FilterStateMustResolveToSignalObject=off  FilterRTWStateStorageClass=Auto  ParallelPVariant=InternalParameters  IdealPVariant=Disabled  IVariant=InternalParameters  DVariant=InternalParameters  IntegratorVariant=Discrete  SatVariant=Disabled  AWVariant=Passthrough  PCopyVariant=Disabled  TRVariant=Disabled  FdbkBlocksVariant=Forward  IdealPFdbkVariant=Disabled  SatFdbkVariant=Disabled  DerivativeFilterVariant=ForwardEulerFilter  NVariant=InternalParameters  NCopyVariant=Disabled  FilterICVariant=InternalICsFilter  IntegratorICVariant=InternalICs  ExternalResetVariant=Disabled  TRSumVariant=Passthrough  SumFdbkVariant=Disabled  SumVariant=Sum_PID  TsampFilterVariant=InternalTs  TsampNgainVariant=Passthrough  TsampIntegralVariant=Disabled_SignalSpec  ExternalSaturationOutDataTypeStr=Inherit: Same as second input  DerivativeSourceVariant=ErrorSignal  PreIntVariant=InternalPreInt
  Sum13 : Sum  Inputs=++|
  Sum25 : Sum  Inputs=|++
  Sum37 : Sum  Inputs=|++
  Sum38 : Sum  Inputs=|+-
  Sum39 : Sum  Inputs=|++
  Sum40 : Sum  Inputs=|-+
  Teta_sogi7 : Scope
  Ts3 : SampleTimeMath  TsampMathOp=*
  Vd_sogi7 : Scope
  Vq_sogi7 : Scope
  abc to alpha-beta1 : Subsystem
  integral3 : Subsystem
  integral4 : Subsystem
  theta_pcc : Outport  VectorParamsAs1DForOutWhenUnconnected=off
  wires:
  Discrete-Time Integrator4/1 -> Sum25/2
  Gain3/1 -> Discrete-Time Integrator4/1
  Abs5/1 -> Gain6/1
  Gain2/1 -> Sum25/1
  Constant17/1 -> Sum37/2
  Gain6/1 -> Vd_sogi7/1
  Constant18/1 -> Sum40/1
  Sum37/1 -> Ts3/1, [w4]
  Delay6/1 -> [Teta_sogi9], Embedded MATLAB Function27/3(As), Teta_sogi7/1
  Sum13/1 -> Embedded MATLAB Function7/1(A)
  Delay7/1 -> Sum13/1
  Ts3/1 -> Sum13/2
  abc/1 -> abc to alpha-beta1/1(abc)
  abc to alpha-beta1/1(al_be) -> Demux1/1
  Demux1/1 -> integral3/1(Vg)
  Demux1/2 -> integral4/1(Vg)
  Constant/1 -> integral3/2(W), integral4/2(W)
  integral3/1(v) -> Sum38/1
  integral3/2(qv) -> Sum39/1
  Sum38/1 -> Embedded MATLAB Function27/1(alpha)
  Sum39/1 -> Embedded MATLAB Function27/2(beta)
  integral4/2(qv) -> Sum38/2
  integral4/1(v) -> Sum39/2
  Embedded MATLAB Function27/1(Vds) -> Abs5/1
  Embedded MATLAB Function27/2(Vqs) -> Vq_sogi7/1, Sum40/2
  Sum40/1 -> Gain3/1, Gain2/1
  Embedded MATLAB Function7/1(Am) -> Delay6/1, Delay7/1
  [Teta_sogi9] -> theta_pcc/1
  Sum25/1 -> Sum37/1
